VERSION 5.8 ;
BUSBITCHARS "[]" ;
DIVIDERCHAR "/" ;
UNITS
    DATABASE MICRONS 1000 ;
END UNITS

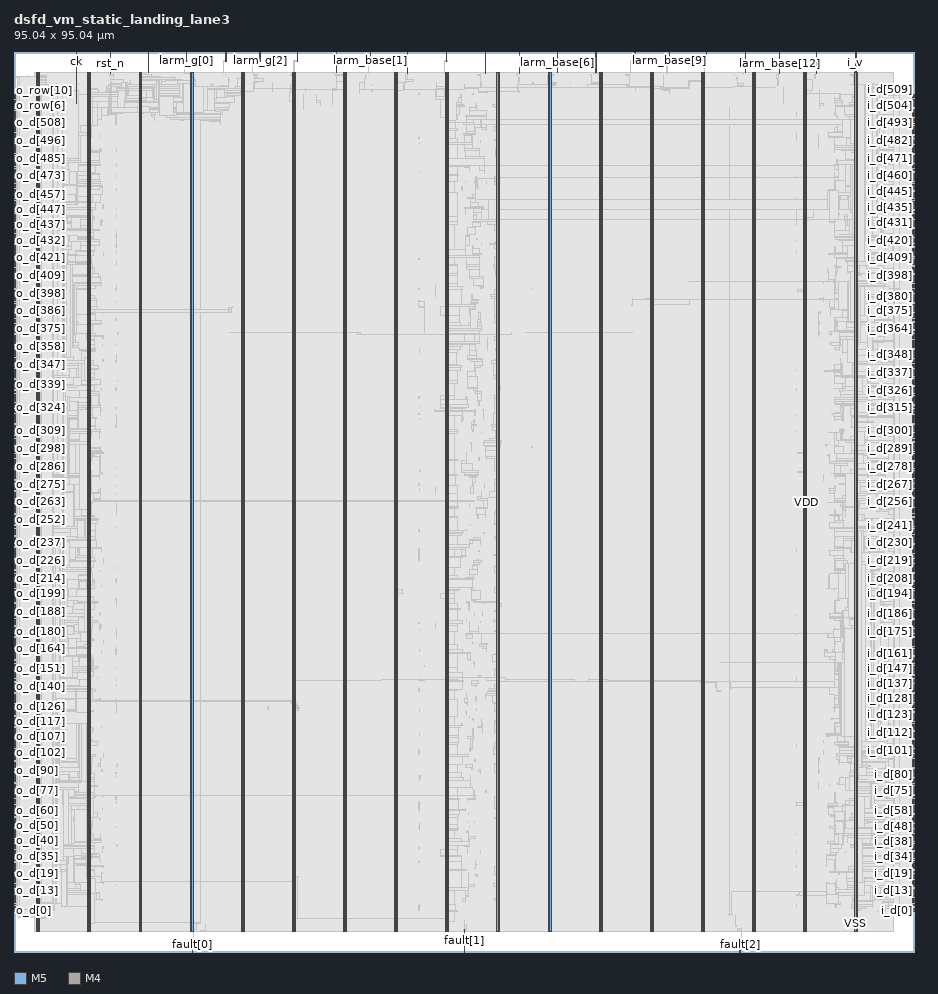
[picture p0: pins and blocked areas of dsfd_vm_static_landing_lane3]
MACRO dsfd_vm_static_landing_lane3
  FOREIGN dsfd_vm_static_landing_lane3 0 0 ;
  CLASS BLOCK ;
  SIZE 95.04 BY 95.04 ;
  PIN ck
    DIRECTION INPUT ;
    USE SIGNAL ;
    PORT
      LAYER M5 ;
        RECT  6.576 94.848 6.6 95.04 ;
    END
    PORT
      LAYER M5 ;
        RECT  6.576 89.555 6.6 94.864 ;
    END
  END ck
  PIN fault[0]
    DIRECTION OUTPUT ;
    USE SIGNAL ;
    PORT
      LAYER M5 ;
        RECT  18.816 0 18.84 0.192 ;
    END
    PORT
      LAYER M5 ;
        RECT  18.816 0.144 18.84 0.563 ;
    END
  END fault[0]
  PIN fault[1]
    DIRECTION OUTPUT ;
    USE SIGNAL ;
    PORT
      LAYER M5 ;
        RECT  47.568 0 47.592 0.192 ;
    END
    PORT
      LAYER M5 ;
        RECT  47.568 0.144 47.592 2.339 ;
    END
  END fault[1]
  PIN fault[2]
    DIRECTION OUTPUT ;
    USE SIGNAL ;
    PORT
      LAYER M5 ;
        RECT  76.656 0 76.68 0.192 ;
    END
    PORT
      LAYER M5 ;
        RECT  76.656 0.144 76.68 0.227 ;
    END
  END fault[2]
  PIN i_d[0]
    DIRECTION INPUT ;
    USE SIGNAL ;
    PORT
      LAYER M4 ;
        RECT  94.848 4.32 95.04 4.344 ;
    END
  END i_d[0]
  PIN i_d[100]
    DIRECTION INPUT ;
    USE SIGNAL ;
    PORT
      LAYER M4 ;
        RECT  94.848 21.168 95.04 21.192 ;
    END
  END i_d[100]
  PIN i_d[101]
    DIRECTION INPUT ;
    USE SIGNAL ;
    PORT
      LAYER M4 ;
        RECT  94.848 21.312 95.04 21.336 ;
    END
  END i_d[101]
  PIN i_d[102]
    DIRECTION INPUT ;
    USE SIGNAL ;
    PORT
      LAYER M4 ;
        RECT  94.848 21.6 95.04 21.624 ;
    END
  END i_d[102]
  PIN i_d[103]
    DIRECTION INPUT ;
    USE SIGNAL ;
    PORT
      LAYER M4 ;
        RECT  94.848 21.744 95.04 21.768 ;
    END
  END i_d[103]
  PIN i_d[104]
    DIRECTION INPUT ;
    USE SIGNAL ;
    PORT
      LAYER M4 ;
        RECT  94.848 21.888 95.04 21.912 ;
    END
  END i_d[104]
  PIN i_d[105]
    DIRECTION INPUT ;
    USE SIGNAL ;
    PORT
      LAYER M4 ;
        RECT  94.848 22.032 95.04 22.056 ;
    END
  END i_d[105]
  PIN i_d[106]
    DIRECTION INPUT ;
    USE SIGNAL ;
    PORT
      LAYER M4 ;
        RECT  94.848 22.176 95.04 22.2 ;
    END
  END i_d[106]
  PIN i_d[107]
    DIRECTION INPUT ;
    USE SIGNAL ;
    PORT
      LAYER M4 ;
        RECT  94.848 22.32 95.04 22.344 ;
    END
  END i_d[107]
  PIN i_d[108]
    DIRECTION INPUT ;
    USE SIGNAL ;
    PORT
      LAYER M4 ;
        RECT  94.848 22.608 95.04 22.632 ;
    END
  END i_d[108]
  PIN i_d[109]
    DIRECTION INPUT ;
    USE SIGNAL ;
    PORT
      LAYER M4 ;
        RECT  94.848 22.752 95.04 22.776 ;
    END
  END i_d[109]
  PIN i_d[10]
    DIRECTION INPUT ;
    USE SIGNAL ;
    PORT
      LAYER M4 ;
        RECT  94.848 6.048 95.04 6.072 ;
    END
  END i_d[10]
  PIN i_d[110]
    DIRECTION INPUT ;
    USE SIGNAL ;
    PORT
      LAYER M4 ;
        RECT  94.848 22.896 95.04 22.92 ;
    END
  END i_d[110]
  PIN i_d[111]
    DIRECTION INPUT ;
    USE SIGNAL ;
    PORT
      LAYER M4 ;
        RECT  94.848 23.04 95.04 23.064 ;
    END
  END i_d[111]
  PIN i_d[112]
    DIRECTION INPUT ;
    USE SIGNAL ;
    PORT
      LAYER M4 ;
        RECT  94.848 23.184 95.04 23.208 ;
    END
  END i_d[112]
  PIN i_d[113]
    DIRECTION INPUT ;
    USE SIGNAL ;
    PORT
      LAYER M4 ;
        RECT  94.848 23.472 95.04 23.496 ;
    END
  END i_d[113]
  PIN i_d[114]
    DIRECTION INPUT ;
    USE SIGNAL ;
    PORT
      LAYER M4 ;
        RECT  94.848 23.616 95.04 23.64 ;
    END
  END i_d[114]
  PIN i_d[115]
    DIRECTION INPUT ;
    USE SIGNAL ;
    PORT
      LAYER M4 ;
        RECT  94.848 23.76 95.04 23.784 ;
    END
  END i_d[115]
  PIN i_d[116]
    DIRECTION INPUT ;
    USE SIGNAL ;
    PORT
      LAYER M4 ;
        RECT  94.848 23.904 95.04 23.928 ;
    END
  END i_d[116]
  PIN i_d[117]
    DIRECTION INPUT ;
    USE SIGNAL ;
    PORT
      LAYER M4 ;
        RECT  94.848 24.048 95.04 24.072 ;
    END
  END i_d[117]
  PIN i_d[118]
    DIRECTION INPUT ;
    USE SIGNAL ;
    PORT
      LAYER M4 ;
        RECT  94.848 24.192 95.04 24.216 ;
    END
  END i_d[118]
  PIN i_d[119]
    DIRECTION INPUT ;
    USE SIGNAL ;
    PORT
      LAYER M4 ;
        RECT  94.848 24.48 95.04 24.504 ;
    END
  END i_d[119]
  PIN i_d[11]
    DIRECTION INPUT ;
    USE SIGNAL ;
    PORT
      LAYER M4 ;
        RECT  94.848 6.192 95.04 6.216 ;
    END
  END i_d[11]
  PIN i_d[120]
    DIRECTION INPUT ;
    USE SIGNAL ;
    PORT
      LAYER M4 ;
        RECT  94.848 24.624 95.04 24.648 ;
    END
  END i_d[120]
  PIN i_d[121]
    DIRECTION INPUT ;
    USE SIGNAL ;
    PORT
      LAYER M4 ;
        RECT  94.848 24.768 95.04 24.792 ;
    END
  END i_d[121]
  PIN i_d[122]
    DIRECTION INPUT ;
    USE SIGNAL ;
    PORT
      LAYER M4 ;
        RECT  94.848 24.912 95.04 24.936 ;
    END
  END i_d[122]
  PIN i_d[123]
    DIRECTION INPUT ;
    USE SIGNAL ;
    PORT
      LAYER M4 ;
        RECT  94.848 25.056 95.04 25.08 ;
    END
  END i_d[123]
  PIN i_d[124]
    DIRECTION INPUT ;
    USE SIGNAL ;
    PORT
      LAYER M4 ;
        RECT  94.848 25.2 95.04 25.224 ;
    END
  END i_d[124]
  PIN i_d[125]
    DIRECTION INPUT ;
    USE SIGNAL ;
    PORT
      LAYER M4 ;
        RECT  94.848 25.488 95.04 25.512 ;
    END
  END i_d[125]
  PIN i_d[126]
    DIRECTION INPUT ;
    USE SIGNAL ;
    PORT
      LAYER M4 ;
        RECT  94.848 25.632 95.04 25.656 ;
    END
  END i_d[126]
  PIN i_d[127]
    DIRECTION INPUT ;
    USE SIGNAL ;
    PORT
      LAYER M4 ;
        RECT  94.848 25.776 95.04 25.8 ;
    END
  END i_d[127]
  PIN i_d[128]
    DIRECTION INPUT ;
    USE SIGNAL ;
    PORT
      LAYER M4 ;
        RECT  94.848 25.92 95.04 25.944 ;
    END
  END i_d[128]
  PIN i_d[129]
    DIRECTION INPUT ;
    USE SIGNAL ;
    PORT
      LAYER M4 ;
        RECT  94.848 26.064 95.04 26.088 ;
    END
  END i_d[129]
  PIN i_d[12]
    DIRECTION INPUT ;
    USE SIGNAL ;
    PORT
      LAYER M4 ;
        RECT  94.848 6.336 95.04 6.36 ;
    END
  END i_d[12]
  PIN i_d[130]
    DIRECTION INPUT ;
    USE SIGNAL ;
    PORT
      LAYER M4 ;
        RECT  94.848 26.208 95.04 26.232 ;
    END
  END i_d[130]
  PIN i_d[131]
    DIRECTION INPUT ;
    USE SIGNAL ;
    PORT
      LAYER M4 ;
        RECT  94.848 26.496 95.04 26.52 ;
    END
  END i_d[131]
  PIN i_d[132]
    DIRECTION INPUT ;
    USE SIGNAL ;
    PORT
      LAYER M4 ;
        RECT  94.848 26.64 95.04 26.664 ;
    END
  END i_d[132]
  PIN i_d[133]
    DIRECTION INPUT ;
    USE SIGNAL ;
    PORT
      LAYER M4 ;
        RECT  94.848 26.784 95.04 26.808 ;
    END
  END i_d[133]
  PIN i_d[134]
    DIRECTION INPUT ;
    USE SIGNAL ;
    PORT
      LAYER M4 ;
        RECT  94.848 26.928 95.04 26.952 ;
    END
  END i_d[134]
  PIN i_d[135]
    DIRECTION INPUT ;
    USE SIGNAL ;
    PORT
      LAYER M4 ;
        RECT  94.848 27.072 95.04 27.096 ;
    END
  END i_d[135]
  PIN i_d[136]
    DIRECTION INPUT ;
    USE SIGNAL ;
    PORT
      LAYER M4 ;
        RECT  94.848 27.216 95.04 27.24 ;
    END
  END i_d[136]
  PIN i_d[137]
    DIRECTION INPUT ;
    USE SIGNAL ;
    PORT
      LAYER M4 ;
        RECT  94.848 27.504 95.04 27.528 ;
    END
  END i_d[137]
  PIN i_d[138]
    DIRECTION INPUT ;
    USE SIGNAL ;
    PORT
      LAYER M4 ;
        RECT  94.848 27.648 95.04 27.672 ;
    END
  END i_d[138]
  PIN i_d[139]
    DIRECTION INPUT ;
    USE SIGNAL ;
    PORT
      LAYER M4 ;
        RECT  94.848 27.792 95.04 27.816 ;
    END
  END i_d[139]
  PIN i_d[13]
    DIRECTION INPUT ;
    USE SIGNAL ;
    PORT
      LAYER M4 ;
        RECT  94.848 6.48 95.04 6.504 ;
    END
  END i_d[13]
  PIN i_d[140]
    DIRECTION INPUT ;
    USE SIGNAL ;
    PORT
      LAYER M4 ;
        RECT  94.848 27.936 95.04 27.96 ;
    END
  END i_d[140]
  PIN i_d[141]
    DIRECTION INPUT ;
    USE SIGNAL ;
    PORT
      LAYER M4 ;
        RECT  94.848 28.08 95.04 28.104 ;
    END
  END i_d[141]
  PIN i_d[142]
    DIRECTION INPUT ;
    USE SIGNAL ;
    PORT
      LAYER M4 ;
        RECT  94.848 28.224 95.04 28.248 ;
    END
  END i_d[142]
  PIN i_d[143]
    DIRECTION INPUT ;
    USE SIGNAL ;
    PORT
      LAYER M4 ;
        RECT  94.848 28.512 95.04 28.536 ;
    END
  END i_d[143]
  PIN i_d[144]
    DIRECTION INPUT ;
    USE SIGNAL ;
    PORT
      LAYER M4 ;
        RECT  94.848 28.656 95.04 28.68 ;
    END
  END i_d[144]
  PIN i_d[145]
    DIRECTION INPUT ;
    USE SIGNAL ;
    PORT
      LAYER M4 ;
        RECT  94.848 28.8 95.04 28.824 ;
    END
  END i_d[145]
  PIN i_d[146]
    DIRECTION INPUT ;
    USE SIGNAL ;
    PORT
      LAYER M4 ;
        RECT  94.848 28.944 95.04 28.968 ;
    END
  END i_d[146]
  PIN i_d[147]
    DIRECTION INPUT ;
    USE SIGNAL ;
    PORT
      LAYER M4 ;
        RECT  94.848 29.088 95.04 29.112 ;
    END
  END i_d[147]
  PIN i_d[148]
    DIRECTION INPUT ;
    USE SIGNAL ;
    PORT
      LAYER M4 ;
        RECT  94.848 29.376 95.04 29.4 ;
    END
  END i_d[148]
  PIN i_d[149]
    DIRECTION INPUT ;
    USE SIGNAL ;
    PORT
      LAYER M4 ;
        RECT  94.848 29.52 95.04 29.544 ;
    END
  END i_d[149]
  PIN i_d[14]
    DIRECTION INPUT ;
    USE SIGNAL ;
    PORT
      LAYER M4 ;
        RECT  94.848 6.624 95.04 6.648 ;
    END
  END i_d[14]
  PIN i_d[150]
    DIRECTION INPUT ;
    USE SIGNAL ;
    PORT
      LAYER M4 ;
        RECT  94.848 29.664 95.04 29.688 ;
    END
  END i_d[150]
  PIN i_d[151]
    DIRECTION INPUT ;
    USE SIGNAL ;
    PORT
      LAYER M4 ;
        RECT  94.848 29.808 95.04 29.832 ;
    END
  END i_d[151]
  PIN i_d[152]
    DIRECTION INPUT ;
    USE SIGNAL ;
    PORT
      LAYER M4 ;
        RECT  94.848 29.952 95.04 29.976 ;
    END
  END i_d[152]
  PIN i_d[153]
    DIRECTION INPUT ;
    USE SIGNAL ;
    PORT
      LAYER M4 ;
        RECT  94.848 30.096 95.04 30.12 ;
    END
  END i_d[153]
  PIN i_d[154]
    DIRECTION INPUT ;
    USE SIGNAL ;
    PORT
      LAYER M4 ;
        RECT  94.848 30.384 95.04 30.408 ;
    END
  END i_d[154]
  PIN i_d[155]
    DIRECTION INPUT ;
    USE SIGNAL ;
    PORT
      LAYER M4 ;
        RECT  94.848 30.528 95.04 30.552 ;
    END
  END i_d[155]
  PIN i_d[156]
    DIRECTION INPUT ;
    USE SIGNAL ;
    PORT
      LAYER M4 ;
        RECT  94.848 30.672 95.04 30.696 ;
    END
  END i_d[156]
  PIN i_d[157]
    DIRECTION INPUT ;
    USE SIGNAL ;
    PORT
      LAYER M4 ;
        RECT  94.848 30.816 95.04 30.84 ;
    END
  END i_d[157]
  PIN i_d[158]
    DIRECTION INPUT ;
    USE SIGNAL ;
    PORT
      LAYER M4 ;
        RECT  94.848 30.96 95.04 30.984 ;
    END
  END i_d[158]
  PIN i_d[159]
    DIRECTION INPUT ;
    USE SIGNAL ;
    PORT
      LAYER M4 ;
        RECT  94.848 31.104 95.04 31.128 ;
    END
  END i_d[159]
  PIN i_d[15]
    DIRECTION INPUT ;
    USE SIGNAL ;
    PORT
      LAYER M4 ;
        RECT  94.848 6.912 95.04 6.936 ;
    END
  END i_d[15]
  PIN i_d[160]
    DIRECTION INPUT ;
    USE SIGNAL ;
    PORT
      LAYER M4 ;
        RECT  94.848 31.392 95.04 31.416 ;
    END
  END i_d[160]
  PIN i_d[161]
    DIRECTION INPUT ;
    USE SIGNAL ;
    PORT
      LAYER M4 ;
        RECT  94.848 31.536 95.04 31.56 ;
    END
  END i_d[161]
  PIN i_d[162]
    DIRECTION INPUT ;
    USE SIGNAL ;
    PORT
      LAYER M4 ;
        RECT  94.848 31.68 95.04 31.704 ;
    END
  END i_d[162]
  PIN i_d[163]
    DIRECTION INPUT ;
    USE SIGNAL ;
    PORT
      LAYER M4 ;
        RECT  94.848 31.824 95.04 31.848 ;
    END
  END i_d[163]
  PIN i_d[164]
    DIRECTION INPUT ;
    USE SIGNAL ;
    PORT
      LAYER M4 ;
        RECT  94.848 31.968 95.04 31.992 ;
    END
  END i_d[164]
  PIN i_d[165]
    DIRECTION INPUT ;
    USE SIGNAL ;
    PORT
      LAYER M4 ;
        RECT  94.848 32.112 95.04 32.136 ;
    END
  END i_d[165]
  PIN i_d[166]
    DIRECTION INPUT ;
    USE SIGNAL ;
    PORT
      LAYER M4 ;
        RECT  94.848 32.4 95.04 32.424 ;
    END
  END i_d[166]
  PIN i_d[167]
    DIRECTION INPUT ;
    USE SIGNAL ;
    PORT
      LAYER M4 ;
        RECT  94.848 32.544 95.04 32.568 ;
    END
  END i_d[167]
  PIN i_d[168]
    DIRECTION INPUT ;
    USE SIGNAL ;
    PORT
      LAYER M4 ;
        RECT  94.848 32.688 95.04 32.712 ;
    END
  END i_d[168]
  PIN i_d[169]
    DIRECTION INPUT ;
    USE SIGNAL ;
    PORT
      LAYER M4 ;
        RECT  94.848 32.832 95.04 32.856 ;
    END
  END i_d[169]
  PIN i_d[16]
    DIRECTION INPUT ;
    USE SIGNAL ;
    PORT
      LAYER M4 ;
        RECT  94.848 7.056 95.04 7.08 ;
    END
  END i_d[16]
  PIN i_d[170]
    DIRECTION INPUT ;
    USE SIGNAL ;
    PORT
      LAYER M4 ;
        RECT  94.848 32.976 95.04 33 ;
    END
  END i_d[170]
  PIN i_d[171]
    DIRECTION INPUT ;
    USE SIGNAL ;
    PORT
      LAYER M4 ;
        RECT  94.848 33.12 95.04 33.144 ;
    END
  END i_d[171]
  PIN i_d[172]
    DIRECTION INPUT ;
    USE SIGNAL ;
    PORT
      LAYER M4 ;
        RECT  94.848 33.408 95.04 33.432 ;
    END
  END i_d[172]
  PIN i_d[173]
    DIRECTION INPUT ;
    USE SIGNAL ;
    PORT
      LAYER M4 ;
        RECT  94.848 33.552 95.04 33.576 ;
    END
  END i_d[173]
  PIN i_d[174]
    DIRECTION INPUT ;
    USE SIGNAL ;
    PORT
      LAYER M4 ;
        RECT  94.848 33.696 95.04 33.72 ;
    END
  END i_d[174]
  PIN i_d[175]
    DIRECTION INPUT ;
    USE SIGNAL ;
    PORT
      LAYER M4 ;
        RECT  94.848 33.84 95.04 33.864 ;
    END
  END i_d[175]
  PIN i_d[176]
    DIRECTION INPUT ;
    USE SIGNAL ;
    PORT
      LAYER M4 ;
        RECT  94.848 33.984 95.04 34.008 ;
    END
  END i_d[176]
  PIN i_d[177]
    DIRECTION INPUT ;
    USE SIGNAL ;
    PORT
      LAYER M4 ;
        RECT  94.848 34.272 95.04 34.296 ;
    END
  END i_d[177]
  PIN i_d[178]
    DIRECTION INPUT ;
    USE SIGNAL ;
    PORT
      LAYER M4 ;
        RECT  94.848 34.416 95.04 34.44 ;
    END
  END i_d[178]
  PIN i_d[179]
    DIRECTION INPUT ;
    USE SIGNAL ;
    PORT
      LAYER M4 ;
        RECT  94.848 34.56 95.04 34.584 ;
    END
  END i_d[179]
  PIN i_d[17]
    DIRECTION INPUT ;
    USE SIGNAL ;
    PORT
      LAYER M4 ;
        RECT  94.848 7.2 95.04 7.224 ;
    END
  END i_d[17]
  PIN i_d[180]
    DIRECTION INPUT ;
    USE SIGNAL ;
    PORT
      LAYER M4 ;
        RECT  94.848 34.704 95.04 34.728 ;
    END
  END i_d[180]
  PIN i_d[181]
    DIRECTION INPUT ;
    USE SIGNAL ;
    PORT
      LAYER M4 ;
        RECT  94.848 34.848 95.04 34.872 ;
    END
  END i_d[181]
  PIN i_d[182]
    DIRECTION INPUT ;
    USE SIGNAL ;
    PORT
      LAYER M4 ;
        RECT  94.848 34.992 95.04 35.016 ;
    END
  END i_d[182]
  PIN i_d[183]
    DIRECTION INPUT ;
    USE SIGNAL ;
    PORT
      LAYER M4 ;
        RECT  94.848 35.28 95.04 35.304 ;
    END
  END i_d[183]
  PIN i_d[184]
    DIRECTION INPUT ;
    USE SIGNAL ;
    PORT
      LAYER M4 ;
        RECT  94.848 35.424 95.04 35.448 ;
    END
  END i_d[184]
  PIN i_d[185]
    DIRECTION INPUT ;
    USE SIGNAL ;
    PORT
      LAYER M4 ;
        RECT  94.848 35.568 95.04 35.592 ;
    END
  END i_d[185]
  PIN i_d[186]
    DIRECTION INPUT ;
    USE SIGNAL ;
    PORT
      LAYER M4 ;
        RECT  94.848 35.712 95.04 35.736 ;
    END
  END i_d[186]
  PIN i_d[187]
    DIRECTION INPUT ;
    USE SIGNAL ;
    PORT
      LAYER M4 ;
        RECT  94.848 35.856 95.04 35.88 ;
    END
  END i_d[187]
  PIN i_d[188]
    DIRECTION INPUT ;
    USE SIGNAL ;
    PORT
      LAYER M4 ;
        RECT  94.848 36 95.04 36.024 ;
    END
  END i_d[188]
  PIN i_d[189]
    DIRECTION INPUT ;
    USE SIGNAL ;
    PORT
      LAYER M4 ;
        RECT  94.848 36.288 95.04 36.312 ;
    END
  END i_d[189]
  PIN i_d[18]
    DIRECTION INPUT ;
    USE SIGNAL ;
    PORT
      LAYER M4 ;
        RECT  94.848 7.344 95.04 7.368 ;
    END
  END i_d[18]
  PIN i_d[190]
    DIRECTION INPUT ;
    USE SIGNAL ;
    PORT
      LAYER M4 ;
        RECT  94.848 36.432 95.04 36.456 ;
    END
  END i_d[190]
  PIN i_d[191]
    DIRECTION INPUT ;
    USE SIGNAL ;
    PORT
      LAYER M4 ;
        RECT  94.848 36.576 95.04 36.6 ;
    END
  END i_d[191]
  PIN i_d[192]
    DIRECTION INPUT ;
    USE SIGNAL ;
    PORT
      LAYER M4 ;
        RECT  94.848 36.72 95.04 36.744 ;
    END
  END i_d[192]
  PIN i_d[193]
    DIRECTION INPUT ;
    USE SIGNAL ;
    PORT
      LAYER M4 ;
        RECT  94.848 36.864 95.04 36.888 ;
    END
  END i_d[193]
  PIN i_d[194]
    DIRECTION INPUT ;
    USE SIGNAL ;
    PORT
      LAYER M4 ;
        RECT  94.848 37.008 95.04 37.032 ;
    END
  END i_d[194]
  PIN i_d[195]
    DIRECTION INPUT ;
    USE SIGNAL ;
    PORT
      LAYER M4 ;
        RECT  94.848 37.296 95.04 37.32 ;
    END
  END i_d[195]
  PIN i_d[196]
    DIRECTION INPUT ;
    USE SIGNAL ;
    PORT
      LAYER M4 ;
        RECT  94.848 37.44 95.04 37.464 ;
    END
  END i_d[196]
  PIN i_d[197]
    DIRECTION INPUT ;
    USE SIGNAL ;
    PORT
      LAYER M4 ;
        RECT  94.848 37.584 95.04 37.608 ;
    END
  END i_d[197]
  PIN i_d[198]
    DIRECTION INPUT ;
    USE SIGNAL ;
    PORT
      LAYER M4 ;
        RECT  94.848 37.728 95.04 37.752 ;
    END
  END i_d[198]
  PIN i_d[199]
    DIRECTION INPUT ;
    USE SIGNAL ;
    PORT
      LAYER M4 ;
        RECT  94.848 37.872 95.04 37.896 ;
    END
  END i_d[199]
  PIN i_d[19]
    DIRECTION INPUT ;
    USE SIGNAL ;
    PORT
      LAYER M4 ;
        RECT  94.848 7.488 95.04 7.512 ;
    END
  END i_d[19]
  PIN i_d[1]
    DIRECTION INPUT ;
    USE SIGNAL ;
    PORT
      LAYER M4 ;
        RECT  94.848 4.464 95.04 4.488 ;
    END
  END i_d[1]
  PIN i_d[200]
    DIRECTION INPUT ;
    USE SIGNAL ;
    PORT
      LAYER M4 ;
        RECT  94.848 38.016 95.04 38.04 ;
    END
  END i_d[200]
  PIN i_d[201]
    DIRECTION INPUT ;
    USE SIGNAL ;
    PORT
      LAYER M4 ;
        RECT  94.848 38.304 95.04 38.328 ;
    END
  END i_d[201]
  PIN i_d[202]
    DIRECTION INPUT ;
    USE SIGNAL ;
    PORT
      LAYER M4 ;
        RECT  94.848 38.448 95.04 38.472 ;
    END
  END i_d[202]
  PIN i_d[203]
    DIRECTION INPUT ;
    USE SIGNAL ;
    PORT
      LAYER M4 ;
        RECT  94.848 38.592 95.04 38.616 ;
    END
  END i_d[203]
  PIN i_d[204]
    DIRECTION INPUT ;
    USE SIGNAL ;
    PORT
      LAYER M4 ;
        RECT  94.848 38.736 95.04 38.76 ;
    END
  END i_d[204]
  PIN i_d[205]
    DIRECTION INPUT ;
    USE SIGNAL ;
    PORT
      LAYER M4 ;
        RECT  94.848 38.88 95.04 38.904 ;
    END
  END i_d[205]
  PIN i_d[206]
    DIRECTION INPUT ;
    USE SIGNAL ;
    PORT
      LAYER M4 ;
        RECT  94.848 39.024 95.04 39.048 ;
    END
  END i_d[206]
  PIN i_d[207]
    DIRECTION INPUT ;
    USE SIGNAL ;
    PORT
      LAYER M4 ;
        RECT  94.848 39.312 95.04 39.336 ;
    END
  END i_d[207]
  PIN i_d[208]
    DIRECTION INPUT ;
    USE SIGNAL ;
    PORT
      LAYER M4 ;
        RECT  94.848 39.456 95.04 39.48 ;
    END
  END i_d[208]
  PIN i_d[209]
    DIRECTION INPUT ;
    USE SIGNAL ;
    PORT
      LAYER M4 ;
        RECT  94.848 39.6 95.04 39.624 ;
    END
  END i_d[209]
  PIN i_d[20]
    DIRECTION INPUT ;
    USE SIGNAL ;
    PORT
      LAYER M4 ;
        RECT  94.848 7.776 95.04 7.8 ;
    END
  END i_d[20]
  PIN i_d[210]
    DIRECTION INPUT ;
    USE SIGNAL ;
    PORT
      LAYER M4 ;
        RECT  94.848 39.744 95.04 39.768 ;
    END
  END i_d[210]
  PIN i_d[211]
    DIRECTION INPUT ;
    USE SIGNAL ;
    PORT
      LAYER M4 ;
        RECT  94.848 39.888 95.04 39.912 ;
    END
  END i_d[211]
  PIN i_d[212]
    DIRECTION INPUT ;
    USE SIGNAL ;
    PORT
      LAYER M4 ;
        RECT  94.848 40.176 95.04 40.2 ;
    END
  END i_d[212]
  PIN i_d[213]
    DIRECTION INPUT ;
    USE SIGNAL ;
    PORT
      LAYER M4 ;
        RECT  94.848 40.32 95.04 40.344 ;
    END
  END i_d[213]
  PIN i_d[214]
    DIRECTION INPUT ;
    USE SIGNAL ;
    PORT
      LAYER M4 ;
        RECT  94.848 40.464 95.04 40.488 ;
    END
  END i_d[214]
  PIN i_d[215]
    DIRECTION INPUT ;
    USE SIGNAL ;
    PORT
      LAYER M4 ;
        RECT  94.848 40.608 95.04 40.632 ;
    END
  END i_d[215]
  PIN i_d[216]
    DIRECTION INPUT ;
    USE SIGNAL ;
    PORT
      LAYER M4 ;
        RECT  94.848 40.752 95.04 40.776 ;
    END
  END i_d[216]
  PIN i_d[217]
    DIRECTION INPUT ;
    USE SIGNAL ;
    PORT
      LAYER M4 ;
        RECT  94.848 40.896 95.04 40.92 ;
    END
  END i_d[217]
  PIN i_d[218]
    DIRECTION INPUT ;
    USE SIGNAL ;
    PORT
      LAYER M4 ;
        RECT  94.848 41.184 95.04 41.208 ;
    END
  END i_d[218]
  PIN i_d[219]
    DIRECTION INPUT ;
    USE SIGNAL ;
    PORT
      LAYER M4 ;
        RECT  94.848 41.328 95.04 41.352 ;
    END
  END i_d[219]
  PIN i_d[21]
    DIRECTION INPUT ;
    USE SIGNAL ;
    PORT
      LAYER M4 ;
        RECT  94.848 7.92 95.04 7.944 ;
    END
  END i_d[21]
  PIN i_d[220]
    DIRECTION INPUT ;
    USE SIGNAL ;
    PORT
      LAYER M4 ;
        RECT  94.848 41.472 95.04 41.496 ;
    END
  END i_d[220]
  PIN i_d[221]
    DIRECTION INPUT ;
    USE SIGNAL ;
    PORT
      LAYER M4 ;
        RECT  94.848 41.616 95.04 41.64 ;
    END
  END i_d[221]
  PIN i_d[222]
    DIRECTION INPUT ;
    USE SIGNAL ;
    PORT
      LAYER M4 ;
        RECT  94.848 41.76 95.04 41.784 ;
    END
  END i_d[222]
  PIN i_d[223]
    DIRECTION INPUT ;
    USE SIGNAL ;
    PORT
      LAYER M4 ;
        RECT  94.848 41.904 95.04 41.928 ;
    END
  END i_d[223]
  PIN i_d[224]
    DIRECTION INPUT ;
    USE SIGNAL ;
    PORT
      LAYER M4 ;
        RECT  94.848 42.192 95.04 42.216 ;
    END
  END i_d[224]
  PIN i_d[225]
    DIRECTION INPUT ;
    USE SIGNAL ;
    PORT
      LAYER M4 ;
        RECT  94.848 42.336 95.04 42.36 ;
    END
  END i_d[225]
  PIN i_d[226]
    DIRECTION INPUT ;
    USE SIGNAL ;
    PORT
      LAYER M4 ;
        RECT  94.848 42.48 95.04 42.504 ;
    END
  END i_d[226]
  PIN i_d[227]
    DIRECTION INPUT ;
    USE SIGNAL ;
    PORT
      LAYER M4 ;
        RECT  94.848 42.624 95.04 42.648 ;
    END
  END i_d[227]
  PIN i_d[228]
    DIRECTION INPUT ;
    USE SIGNAL ;
    PORT
      LAYER M4 ;
        RECT  94.848 42.768 95.04 42.792 ;
    END
  END i_d[228]
  PIN i_d[229]
    DIRECTION INPUT ;
    USE SIGNAL ;
    PORT
      LAYER M4 ;
        RECT  94.848 42.912 95.04 42.936 ;
    END
  END i_d[229]
  PIN i_d[22]
    DIRECTION INPUT ;
    USE SIGNAL ;
    PORT
      LAYER M4 ;
        RECT  94.848 8.064 95.04 8.088 ;
    END
  END i_d[22]
  PIN i_d[230]
    DIRECTION INPUT ;
    USE SIGNAL ;
    PORT
      LAYER M4 ;
        RECT  94.848 43.2 95.04 43.224 ;
    END
  END i_d[230]
  PIN i_d[231]
    DIRECTION INPUT ;
    USE SIGNAL ;
    PORT
      LAYER M4 ;
        RECT  94.848 43.344 95.04 43.368 ;
    END
  END i_d[231]
  PIN i_d[232]
    DIRECTION INPUT ;
    USE SIGNAL ;
    PORT
      LAYER M4 ;
        RECT  94.848 43.488 95.04 43.512 ;
    END
  END i_d[232]
  PIN i_d[233]
    DIRECTION INPUT ;
    USE SIGNAL ;
    PORT
      LAYER M4 ;
        RECT  94.848 43.632 95.04 43.656 ;
    END
  END i_d[233]
  PIN i_d[234]
    DIRECTION INPUT ;
    USE SIGNAL ;
    PORT
      LAYER M4 ;
        RECT  94.848 43.776 95.04 43.8 ;
    END
  END i_d[234]
  PIN i_d[235]
    DIRECTION INPUT ;
    USE SIGNAL ;
    PORT
      LAYER M4 ;
        RECT  94.848 43.92 95.04 43.944 ;
    END
  END i_d[235]
  PIN i_d[236]
    DIRECTION INPUT ;
    USE SIGNAL ;
    PORT
      LAYER M4 ;
        RECT  94.848 44.208 95.04 44.232 ;
    END
  END i_d[236]
  PIN i_d[237]
    DIRECTION INPUT ;
    USE SIGNAL ;
    PORT
      LAYER M4 ;
        RECT  94.848 44.352 95.04 44.376 ;
    END
  END i_d[237]
  PIN i_d[238]
    DIRECTION INPUT ;
    USE SIGNAL ;
    PORT
      LAYER M4 ;
        RECT  94.848 44.496 95.04 44.52 ;
    END
  END i_d[238]
  PIN i_d[239]
    DIRECTION INPUT ;
    USE SIGNAL ;
    PORT
      LAYER M4 ;
        RECT  94.848 44.64 95.04 44.664 ;
    END
  END i_d[239]
  PIN i_d[23]
    DIRECTION INPUT ;
    USE SIGNAL ;
    PORT
      LAYER M4 ;
        RECT  94.848 8.208 95.04 8.232 ;
    END
  END i_d[23]
  PIN i_d[240]
    DIRECTION INPUT ;
    USE SIGNAL ;
    PORT
      LAYER M4 ;
        RECT  94.848 44.784 95.04 44.808 ;
    END
  END i_d[240]
  PIN i_d[241]
    DIRECTION INPUT ;
    USE SIGNAL ;
    PORT
      LAYER M4 ;
        RECT  94.848 45.072 95.04 45.096 ;
    END
  END i_d[241]
  PIN i_d[242]
    DIRECTION INPUT ;
    USE SIGNAL ;
    PORT
      LAYER M4 ;
        RECT  94.848 45.216 95.04 45.24 ;
    END
  END i_d[242]
  PIN i_d[243]
    DIRECTION INPUT ;
    USE SIGNAL ;
    PORT
      LAYER M4 ;
        RECT  94.848 45.36 95.04 45.384 ;
    END
  END i_d[243]
  PIN i_d[244]
    DIRECTION INPUT ;
    USE SIGNAL ;
    PORT
      LAYER M4 ;
        RECT  94.848 45.504 95.04 45.528 ;
    END
  END i_d[244]
  PIN i_d[245]
    DIRECTION INPUT ;
    USE SIGNAL ;
    PORT
      LAYER M4 ;
        RECT  94.848 45.648 95.04 45.672 ;
    END
  END i_d[245]
  PIN i_d[246]
    DIRECTION INPUT ;
    USE SIGNAL ;
    PORT
      LAYER M4 ;
        RECT  94.848 45.792 95.04 45.816 ;
    END
  END i_d[246]
  PIN i_d[247]
    DIRECTION INPUT ;
    USE SIGNAL ;
    PORT
      LAYER M4 ;
        RECT  94.848 46.08 95.04 46.104 ;
    END
  END i_d[247]
  PIN i_d[248]
    DIRECTION INPUT ;
    USE SIGNAL ;
    PORT
      LAYER M4 ;
        RECT  94.848 46.224 95.04 46.248 ;
    END
  END i_d[248]
  PIN i_d[249]
    DIRECTION INPUT ;
    USE SIGNAL ;
    PORT
      LAYER M4 ;
        RECT  94.848 46.368 95.04 46.392 ;
    END
  END i_d[249]
  PIN i_d[24]
    DIRECTION INPUT ;
    USE SIGNAL ;
    PORT
      LAYER M4 ;
        RECT  94.848 8.352 95.04 8.376 ;
    END
  END i_d[24]
  PIN i_d[250]
    DIRECTION INPUT ;
    USE SIGNAL ;
    PORT
      LAYER M4 ;
        RECT  94.848 46.512 95.04 46.536 ;
    END
  END i_d[250]
  PIN i_d[251]
    DIRECTION INPUT ;
    USE SIGNAL ;
    PORT
      LAYER M4 ;
        RECT  94.848 46.656 95.04 46.68 ;
    END
  END i_d[251]
  PIN i_d[252]
    DIRECTION INPUT ;
    USE SIGNAL ;
    PORT
      LAYER M4 ;
        RECT  94.848 46.8 95.04 46.824 ;
    END
  END i_d[252]
  PIN i_d[253]
    DIRECTION INPUT ;
    USE SIGNAL ;
    PORT
      LAYER M4 ;
        RECT  94.848 47.088 95.04 47.112 ;
    END
  END i_d[253]
  PIN i_d[254]
    DIRECTION INPUT ;
    USE SIGNAL ;
    PORT
      LAYER M4 ;
        RECT  94.848 47.232 95.04 47.256 ;
    END
  END i_d[254]
  PIN i_d[255]
    DIRECTION INPUT ;
    USE SIGNAL ;
    PORT
      LAYER M4 ;
        RECT  94.848 47.376 95.04 47.4 ;
    END
  END i_d[255]
  PIN i_d[256]
    DIRECTION INPUT ;
    USE SIGNAL ;
    PORT
      LAYER M4 ;
        RECT  94.848 47.52 95.04 47.544 ;
    END
  END i_d[256]
  PIN i_d[257]
    DIRECTION INPUT ;
    USE SIGNAL ;
    PORT
      LAYER M4 ;
        RECT  94.848 47.664 95.04 47.688 ;
    END
  END i_d[257]
  PIN i_d[258]
    DIRECTION INPUT ;
    USE SIGNAL ;
    PORT
      LAYER M4 ;
        RECT  94.848 47.808 95.04 47.832 ;
    END
  END i_d[258]
  PIN i_d[259]
    DIRECTION INPUT ;
    USE SIGNAL ;
    PORT
      LAYER M4 ;
        RECT  94.848 48.096 95.04 48.12 ;
    END
  END i_d[259]
  PIN i_d[25]
    DIRECTION INPUT ;
    USE SIGNAL ;
    PORT
      LAYER M4 ;
        RECT  94.848 8.496 95.04 8.52 ;
    END
  END i_d[25]
  PIN i_d[260]
    DIRECTION INPUT ;
    USE SIGNAL ;
    PORT
      LAYER M4 ;
        RECT  94.848 48.24 95.04 48.264 ;
    END
  END i_d[260]
  PIN i_d[261]
    DIRECTION INPUT ;
    USE SIGNAL ;
    PORT
      LAYER M4 ;
        RECT  94.848 48.384 95.04 48.408 ;
    END
  END i_d[261]
  PIN i_d[262]
    DIRECTION INPUT ;
    USE SIGNAL ;
    PORT
      LAYER M4 ;
        RECT  94.848 48.528 95.04 48.552 ;
    END
  END i_d[262]
  PIN i_d[263]
    DIRECTION INPUT ;
    USE SIGNAL ;
    PORT
      LAYER M4 ;
        RECT  94.848 48.672 95.04 48.696 ;
    END
  END i_d[263]
  PIN i_d[264]
    DIRECTION INPUT ;
    USE SIGNAL ;
    PORT
      LAYER M4 ;
        RECT  94.848 48.816 95.04 48.84 ;
    END
  END i_d[264]
  PIN i_d[265]
    DIRECTION INPUT ;
    USE SIGNAL ;
    PORT
      LAYER M4 ;
        RECT  94.848 49.104 95.04 49.128 ;
    END
  END i_d[265]
  PIN i_d[266]
    DIRECTION INPUT ;
    USE SIGNAL ;
    PORT
      LAYER M4 ;
        RECT  94.848 49.248 95.04 49.272 ;
    END
  END i_d[266]
  PIN i_d[267]
    DIRECTION INPUT ;
    USE SIGNAL ;
    PORT
      LAYER M4 ;
        RECT  94.848 49.392 95.04 49.416 ;
    END
  END i_d[267]
  PIN i_d[268]
    DIRECTION INPUT ;
    USE SIGNAL ;
    PORT
      LAYER M4 ;
        RECT  94.848 49.536 95.04 49.56 ;
    END
  END i_d[268]
  PIN i_d[269]
    DIRECTION INPUT ;
    USE SIGNAL ;
    PORT
      LAYER M4 ;
        RECT  94.848 49.68 95.04 49.704 ;
    END
  END i_d[269]
  PIN i_d[26]
    DIRECTION INPUT ;
    USE SIGNAL ;
    PORT
      LAYER M4 ;
        RECT  94.848 8.784 95.04 8.808 ;
    END
  END i_d[26]
  PIN i_d[270]
    DIRECTION INPUT ;
    USE SIGNAL ;
    PORT
      LAYER M4 ;
        RECT  94.848 49.824 95.04 49.848 ;
    END
  END i_d[270]
  PIN i_d[271]
    DIRECTION INPUT ;
    USE SIGNAL ;
    PORT
      LAYER M4 ;
        RECT  94.848 50.112 95.04 50.136 ;
    END
  END i_d[271]
  PIN i_d[272]
    DIRECTION INPUT ;
    USE SIGNAL ;
    PORT
      LAYER M4 ;
        RECT  94.848 50.256 95.04 50.28 ;
    END
  END i_d[272]
  PIN i_d[273]
    DIRECTION INPUT ;
    USE SIGNAL ;
    PORT
      LAYER M4 ;
        RECT  94.848 50.4 95.04 50.424 ;
    END
  END i_d[273]
  PIN i_d[274]
    DIRECTION INPUT ;
    USE SIGNAL ;
    PORT
      LAYER M4 ;
        RECT  94.848 50.544 95.04 50.568 ;
    END
  END i_d[274]
  PIN i_d[275]
    DIRECTION INPUT ;
    USE SIGNAL ;
    PORT
      LAYER M4 ;
        RECT  94.848 50.688 95.04 50.712 ;
    END
  END i_d[275]
  PIN i_d[276]
    DIRECTION INPUT ;
    USE SIGNAL ;
    PORT
      LAYER M4 ;
        RECT  94.848 50.976 95.04 51 ;
    END
  END i_d[276]
  PIN i_d[277]
    DIRECTION INPUT ;
    USE SIGNAL ;
    PORT
      LAYER M4 ;
        RECT  94.848 51.12 95.04 51.144 ;
    END
  END i_d[277]
  PIN i_d[278]
    DIRECTION INPUT ;
    USE SIGNAL ;
    PORT
      LAYER M4 ;
        RECT  94.848 51.264 95.04 51.288 ;
    END
  END i_d[278]
  PIN i_d[279]
    DIRECTION INPUT ;
    USE SIGNAL ;
    PORT
      LAYER M4 ;
        RECT  94.848 51.408 95.04 51.432 ;
    END
  END i_d[279]
  PIN i_d[27]
    DIRECTION INPUT ;
    USE SIGNAL ;
    PORT
      LAYER M4 ;
        RECT  94.848 8.928 95.04 8.952 ;
    END
  END i_d[27]
  PIN i_d[280]
    DIRECTION INPUT ;
    USE SIGNAL ;
    PORT
      LAYER M4 ;
        RECT  94.848 51.552 95.04 51.576 ;
    END
  END i_d[280]
  PIN i_d[281]
    DIRECTION INPUT ;
    USE SIGNAL ;
    PORT
      LAYER M4 ;
        RECT  94.848 51.696 95.04 51.72 ;
    END
  END i_d[281]
  PIN i_d[282]
    DIRECTION INPUT ;
    USE SIGNAL ;
    PORT
      LAYER M4 ;
        RECT  94.848 51.984 95.04 52.008 ;
    END
  END i_d[282]
  PIN i_d[283]
    DIRECTION INPUT ;
    USE SIGNAL ;
    PORT
      LAYER M4 ;
        RECT  94.848 52.128 95.04 52.152 ;
    END
  END i_d[283]
  PIN i_d[284]
    DIRECTION INPUT ;
    USE SIGNAL ;
    PORT
      LAYER M4 ;
        RECT  94.848 52.272 95.04 52.296 ;
    END
  END i_d[284]
  PIN i_d[285]
    DIRECTION INPUT ;
    USE SIGNAL ;
    PORT
      LAYER M4 ;
        RECT  94.848 52.416 95.04 52.44 ;
    END
  END i_d[285]
  PIN i_d[286]
    DIRECTION INPUT ;
    USE SIGNAL ;
    PORT
      LAYER M4 ;
        RECT  94.848 52.56 95.04 52.584 ;
    END
  END i_d[286]
  PIN i_d[287]
    DIRECTION INPUT ;
    USE SIGNAL ;
    PORT
      LAYER M4 ;
        RECT  94.848 52.704 95.04 52.728 ;
    END
  END i_d[287]
  PIN i_d[288]
    DIRECTION INPUT ;
    USE SIGNAL ;
    PORT
      LAYER M4 ;
        RECT  94.848 52.992 95.04 53.016 ;
    END
  END i_d[288]
  PIN i_d[289]
    DIRECTION INPUT ;
    USE SIGNAL ;
    PORT
      LAYER M4 ;
        RECT  94.848 53.136 95.04 53.16 ;
    END
  END i_d[289]
  PIN i_d[28]
    DIRECTION INPUT ;
    USE SIGNAL ;
    PORT
      LAYER M4 ;
        RECT  94.848 9.072 95.04 9.096 ;
    END
  END i_d[28]
  PIN i_d[290]
    DIRECTION INPUT ;
    USE SIGNAL ;
    PORT
      LAYER M4 ;
        RECT  94.848 53.28 95.04 53.304 ;
    END
  END i_d[290]
  PIN i_d[291]
    DIRECTION INPUT ;
    USE SIGNAL ;
    PORT
      LAYER M4 ;
        RECT  94.848 53.424 95.04 53.448 ;
    END
  END i_d[291]
  PIN i_d[292]
    DIRECTION INPUT ;
    USE SIGNAL ;
    PORT
      LAYER M4 ;
        RECT  94.848 53.568 95.04 53.592 ;
    END
  END i_d[292]
  PIN i_d[293]
    DIRECTION INPUT ;
    USE SIGNAL ;
    PORT
      LAYER M4 ;
        RECT  94.848 53.712 95.04 53.736 ;
    END
  END i_d[293]
  PIN i_d[294]
    DIRECTION INPUT ;
    USE SIGNAL ;
    PORT
      LAYER M4 ;
        RECT  94.848 54 95.04 54.024 ;
    END
  END i_d[294]
  PIN i_d[295]
    DIRECTION INPUT ;
    USE SIGNAL ;
    PORT
      LAYER M4 ;
        RECT  94.848 54.144 95.04 54.168 ;
    END
  END i_d[295]
  PIN i_d[296]
    DIRECTION INPUT ;
    USE SIGNAL ;
    PORT
      LAYER M4 ;
        RECT  94.848 54.288 95.04 54.312 ;
    END
  END i_d[296]
  PIN i_d[297]
    DIRECTION INPUT ;
    USE SIGNAL ;
    PORT
      LAYER M4 ;
        RECT  94.848 54.432 95.04 54.456 ;
    END
  END i_d[297]
  PIN i_d[298]
    DIRECTION INPUT ;
    USE SIGNAL ;
    PORT
      LAYER M4 ;
        RECT  94.848 54.576 95.04 54.6 ;
    END
  END i_d[298]
  PIN i_d[299]
    DIRECTION INPUT ;
    USE SIGNAL ;
    PORT
      LAYER M4 ;
        RECT  94.848 54.72 95.04 54.744 ;
    END
  END i_d[299]
  PIN i_d[29]
    DIRECTION INPUT ;
    USE SIGNAL ;
    PORT
      LAYER M4 ;
        RECT  94.848 9.216 95.04 9.24 ;
    END
  END i_d[29]
  PIN i_d[2]
    DIRECTION INPUT ;
    USE SIGNAL ;
    PORT
      LAYER M4 ;
        RECT  94.848 4.608 95.04 4.632 ;
    END
  END i_d[2]
  PIN i_d[300]
    DIRECTION INPUT ;
    USE SIGNAL ;
    PORT
      LAYER M4 ;
        RECT  94.848 55.008 95.04 55.032 ;
    END
  END i_d[300]
  PIN i_d[301]
    DIRECTION INPUT ;
    USE SIGNAL ;
    PORT
      LAYER M4 ;
        RECT  94.848 55.152 95.04 55.176 ;
    END
  END i_d[301]
  PIN i_d[302]
    DIRECTION INPUT ;
    USE SIGNAL ;
    PORT
      LAYER M4 ;
        RECT  94.848 55.296 95.04 55.32 ;
    END
  END i_d[302]
  PIN i_d[303]
    DIRECTION INPUT ;
    USE SIGNAL ;
    PORT
      LAYER M4 ;
        RECT  94.848 55.44 95.04 55.464 ;
    END
  END i_d[303]
  PIN i_d[304]
    DIRECTION INPUT ;
    USE SIGNAL ;
    PORT
      LAYER M4 ;
        RECT  94.848 55.584 95.04 55.608 ;
    END
  END i_d[304]
  PIN i_d[305]
    DIRECTION INPUT ;
    USE SIGNAL ;
    PORT
      LAYER M4 ;
        RECT  94.848 55.872 95.04 55.896 ;
    END
  END i_d[305]
  PIN i_d[306]
    DIRECTION INPUT ;
    USE SIGNAL ;
    PORT
      LAYER M4 ;
        RECT  94.848 56.016 95.04 56.04 ;
    END
  END i_d[306]
  PIN i_d[307]
    DIRECTION INPUT ;
    USE SIGNAL ;
    PORT
      LAYER M4 ;
        RECT  94.848 56.16 95.04 56.184 ;
    END
  END i_d[307]
  PIN i_d[308]
    DIRECTION INPUT ;
    USE SIGNAL ;
    PORT
      LAYER M4 ;
        RECT  94.848 56.304 95.04 56.328 ;
    END
  END i_d[308]
  PIN i_d[309]
    DIRECTION INPUT ;
    USE SIGNAL ;
    PORT
      LAYER M4 ;
        RECT  94.848 56.448 95.04 56.472 ;
    END
  END i_d[309]
  PIN i_d[30]
    DIRECTION INPUT ;
    USE SIGNAL ;
    PORT
      LAYER M4 ;
        RECT  94.848 9.36 95.04 9.384 ;
    END
  END i_d[30]
  PIN i_d[310]
    DIRECTION INPUT ;
    USE SIGNAL ;
    PORT
      LAYER M4 ;
        RECT  94.848 56.592 95.04 56.616 ;
    END
  END i_d[310]
  PIN i_d[311]
    DIRECTION INPUT ;
    USE SIGNAL ;
    PORT
      LAYER M4 ;
        RECT  94.848 56.88 95.04 56.904 ;
    END
  END i_d[311]
  PIN i_d[312]
    DIRECTION INPUT ;
    USE SIGNAL ;
    PORT
      LAYER M4 ;
        RECT  94.848 57.024 95.04 57.048 ;
    END
  END i_d[312]
  PIN i_d[313]
    DIRECTION INPUT ;
    USE SIGNAL ;
    PORT
      LAYER M4 ;
        RECT  94.848 57.168 95.04 57.192 ;
    END
  END i_d[313]
  PIN i_d[314]
    DIRECTION INPUT ;
    USE SIGNAL ;
    PORT
      LAYER M4 ;
        RECT  94.848 57.312 95.04 57.336 ;
    END
  END i_d[314]
  PIN i_d[315]
    DIRECTION INPUT ;
    USE SIGNAL ;
    PORT
      LAYER M4 ;
        RECT  94.848 57.456 95.04 57.48 ;
    END
  END i_d[315]
  PIN i_d[316]
    DIRECTION INPUT ;
    USE SIGNAL ;
    PORT
      LAYER M4 ;
        RECT  94.848 57.6 95.04 57.624 ;
    END
  END i_d[316]
  PIN i_d[317]
    DIRECTION INPUT ;
    USE SIGNAL ;
    PORT
      LAYER M4 ;
        RECT  94.848 57.888 95.04 57.912 ;
    END
  END i_d[317]
  PIN i_d[318]
    DIRECTION INPUT ;
    USE SIGNAL ;
    PORT
      LAYER M4 ;
        RECT  94.848 58.032 95.04 58.056 ;
    END
  END i_d[318]
  PIN i_d[319]
    DIRECTION INPUT ;
    USE SIGNAL ;
    PORT
      LAYER M4 ;
        RECT  94.848 58.176 95.04 58.2 ;
    END
  END i_d[319]
  PIN i_d[31]
    DIRECTION INPUT ;
    USE SIGNAL ;
    PORT
      LAYER M4 ;
        RECT  94.848 9.504 95.04 9.528 ;
    END
  END i_d[31]
  PIN i_d[320]
    DIRECTION INPUT ;
    USE SIGNAL ;
    PORT
      LAYER M4 ;
        RECT  94.848 58.32 95.04 58.344 ;
    END
  END i_d[320]
  PIN i_d[321]
    DIRECTION INPUT ;
    USE SIGNAL ;
    PORT
      LAYER M4 ;
        RECT  94.848 58.464 95.04 58.488 ;
    END
  END i_d[321]
  PIN i_d[322]
    DIRECTION INPUT ;
    USE SIGNAL ;
    PORT
      LAYER M4 ;
        RECT  94.848 58.608 95.04 58.632 ;
    END
  END i_d[322]
  PIN i_d[323]
    DIRECTION INPUT ;
    USE SIGNAL ;
    PORT
      LAYER M4 ;
        RECT  94.848 58.896 95.04 58.92 ;
    END
  END i_d[323]
  PIN i_d[324]
    DIRECTION INPUT ;
    USE SIGNAL ;
    PORT
      LAYER M4 ;
        RECT  94.848 59.04 95.04 59.064 ;
    END
  END i_d[324]
  PIN i_d[325]
    DIRECTION INPUT ;
    USE SIGNAL ;
    PORT
      LAYER M4 ;
        RECT  94.848 59.184 95.04 59.208 ;
    END
  END i_d[325]
  PIN i_d[326]
    DIRECTION INPUT ;
    USE SIGNAL ;
    PORT
      LAYER M4 ;
        RECT  94.848 59.328 95.04 59.352 ;
    END
  END i_d[326]
  PIN i_d[327]
    DIRECTION INPUT ;
    USE SIGNAL ;
    PORT
      LAYER M4 ;
        RECT  94.848 59.472 95.04 59.496 ;
    END
  END i_d[327]
  PIN i_d[328]
    DIRECTION INPUT ;
    USE SIGNAL ;
    PORT
      LAYER M4 ;
        RECT  94.848 59.616 95.04 59.64 ;
    END
  END i_d[328]
  PIN i_d[329]
    DIRECTION INPUT ;
    USE SIGNAL ;
    PORT
      LAYER M4 ;
        RECT  94.848 59.904 95.04 59.928 ;
    END
  END i_d[329]
  PIN i_d[32]
    DIRECTION INPUT ;
    USE SIGNAL ;
    PORT
      LAYER M4 ;
        RECT  94.848 9.792 95.04 9.816 ;
    END
  END i_d[32]
  PIN i_d[330]
    DIRECTION INPUT ;
    USE SIGNAL ;
    PORT
      LAYER M4 ;
        RECT  94.848 60.048 95.04 60.072 ;
    END
  END i_d[330]
  PIN i_d[331]
    DIRECTION INPUT ;
    USE SIGNAL ;
    PORT
      LAYER M4 ;
        RECT  94.848 60.192 95.04 60.216 ;
    END
  END i_d[331]
  PIN i_d[332]
    DIRECTION INPUT ;
    USE SIGNAL ;
    PORT
      LAYER M4 ;
        RECT  94.848 60.336 95.04 60.36 ;
    END
  END i_d[332]
  PIN i_d[333]
    DIRECTION INPUT ;
    USE SIGNAL ;
    PORT
      LAYER M4 ;
        RECT  94.848 60.48 95.04 60.504 ;
    END
  END i_d[333]
  PIN i_d[334]
    DIRECTION INPUT ;
    USE SIGNAL ;
    PORT
      LAYER M4 ;
        RECT  94.848 60.624 95.04 60.648 ;
    END
  END i_d[334]
  PIN i_d[335]
    DIRECTION INPUT ;
    USE SIGNAL ;
    PORT
      LAYER M4 ;
        RECT  94.848 60.912 95.04 60.936 ;
    END
  END i_d[335]
  PIN i_d[336]
    DIRECTION INPUT ;
    USE SIGNAL ;
    PORT
      LAYER M4 ;
        RECT  94.848 61.056 95.04 61.08 ;
    END
  END i_d[336]
  PIN i_d[337]
    DIRECTION INPUT ;
    USE SIGNAL ;
    PORT
      LAYER M4 ;
        RECT  94.848 61.2 95.04 61.224 ;
    END
  END i_d[337]
  PIN i_d[338]
    DIRECTION INPUT ;
    USE SIGNAL ;
    PORT
      LAYER M4 ;
        RECT  94.848 61.344 95.04 61.368 ;
    END
  END i_d[338]
  PIN i_d[339]
    DIRECTION INPUT ;
    USE SIGNAL ;
    PORT
      LAYER M4 ;
        RECT  94.848 61.488 95.04 61.512 ;
    END
  END i_d[339]
  PIN i_d[33]
    DIRECTION INPUT ;
    USE SIGNAL ;
    PORT
      LAYER M4 ;
        RECT  94.848 9.936 95.04 9.96 ;
    END
  END i_d[33]
  PIN i_d[340]
    DIRECTION INPUT ;
    USE SIGNAL ;
    PORT
      LAYER M4 ;
        RECT  94.848 61.776 95.04 61.8 ;
    END
  END i_d[340]
  PIN i_d[341]
    DIRECTION INPUT ;
    USE SIGNAL ;
    PORT
      LAYER M4 ;
        RECT  94.848 61.92 95.04 61.944 ;
    END
  END i_d[341]
  PIN i_d[342]
    DIRECTION INPUT ;
    USE SIGNAL ;
    PORT
      LAYER M4 ;
        RECT  94.848 62.064 95.04 62.088 ;
    END
  END i_d[342]
  PIN i_d[343]
    DIRECTION INPUT ;
    USE SIGNAL ;
    PORT
      LAYER M4 ;
        RECT  94.848 62.208 95.04 62.232 ;
    END
  END i_d[343]
  PIN i_d[344]
    DIRECTION INPUT ;
    USE SIGNAL ;
    PORT
      LAYER M4 ;
        RECT  94.848 62.352 95.04 62.376 ;
    END
  END i_d[344]
  PIN i_d[345]
    DIRECTION INPUT ;
    USE SIGNAL ;
    PORT
      LAYER M4 ;
        RECT  94.848 62.496 95.04 62.52 ;
    END
  END i_d[345]
  PIN i_d[346]
    DIRECTION INPUT ;
    USE SIGNAL ;
    PORT
      LAYER M4 ;
        RECT  94.848 62.784 95.04 62.808 ;
    END
  END i_d[346]
  PIN i_d[347]
    DIRECTION INPUT ;
    USE SIGNAL ;
    PORT
      LAYER M4 ;
        RECT  94.848 62.928 95.04 62.952 ;
    END
  END i_d[347]
  PIN i_d[348]
    DIRECTION INPUT ;
    USE SIGNAL ;
    PORT
      LAYER M4 ;
        RECT  94.848 63.072 95.04 63.096 ;
    END
  END i_d[348]
  PIN i_d[349]
    DIRECTION INPUT ;
    USE SIGNAL ;
    PORT
      LAYER M4 ;
        RECT  94.848 63.216 95.04 63.24 ;
    END
  END i_d[349]
  PIN i_d[34]
    DIRECTION INPUT ;
    USE SIGNAL ;
    PORT
      LAYER M4 ;
        RECT  94.848 10.08 95.04 10.104 ;
    END
  END i_d[34]
  PIN i_d[350]
    DIRECTION INPUT ;
    USE SIGNAL ;
    PORT
      LAYER M4 ;
        RECT  94.848 63.36 95.04 63.384 ;
    END
  END i_d[350]
  PIN i_d[351]
    DIRECTION INPUT ;
    USE SIGNAL ;
    PORT
      LAYER M4 ;
        RECT  94.848 63.504 95.04 63.528 ;
    END
  END i_d[351]
  PIN i_d[352]
    DIRECTION INPUT ;
    USE SIGNAL ;
    PORT
      LAYER M4 ;
        RECT  94.848 63.792 95.04 63.816 ;
    END
  END i_d[352]
  PIN i_d[353]
    DIRECTION INPUT ;
    USE SIGNAL ;
    PORT
      LAYER M4 ;
        RECT  94.848 63.936 95.04 63.96 ;
    END
  END i_d[353]
  PIN i_d[354]
    DIRECTION INPUT ;
    USE SIGNAL ;
    PORT
      LAYER M4 ;
        RECT  94.848 64.08 95.04 64.104 ;
    END
  END i_d[354]
  PIN i_d[355]
    DIRECTION INPUT ;
    USE SIGNAL ;
    PORT
      LAYER M4 ;
        RECT  94.848 64.224 95.04 64.248 ;
    END
  END i_d[355]
  PIN i_d[356]
    DIRECTION INPUT ;
    USE SIGNAL ;
    PORT
      LAYER M4 ;
        RECT  94.848 64.368 95.04 64.392 ;
    END
  END i_d[356]
  PIN i_d[357]
    DIRECTION INPUT ;
    USE SIGNAL ;
    PORT
      LAYER M4 ;
        RECT  94.848 64.512 95.04 64.536 ;
    END
  END i_d[357]
  PIN i_d[358]
    DIRECTION INPUT ;
    USE SIGNAL ;
    PORT
      LAYER M4 ;
        RECT  94.848 64.8 95.04 64.824 ;
    END
  END i_d[358]
  PIN i_d[359]
    DIRECTION INPUT ;
    USE SIGNAL ;
    PORT
      LAYER M4 ;
        RECT  94.848 64.944 95.04 64.968 ;
    END
  END i_d[359]
  PIN i_d[35]
    DIRECTION INPUT ;
    USE SIGNAL ;
    PORT
      LAYER M4 ;
        RECT  94.848 10.224 95.04 10.248 ;
    END
  END i_d[35]
  PIN i_d[360]
    DIRECTION INPUT ;
    USE SIGNAL ;
    PORT
      LAYER M4 ;
        RECT  94.848 65.088 95.04 65.112 ;
    END
  END i_d[360]
  PIN i_d[361]
    DIRECTION INPUT ;
    USE SIGNAL ;
    PORT
      LAYER M4 ;
        RECT  94.848 65.232 95.04 65.256 ;
    END
  END i_d[361]
  PIN i_d[362]
    DIRECTION INPUT ;
    USE SIGNAL ;
    PORT
      LAYER M4 ;
        RECT  94.848 65.376 95.04 65.4 ;
    END
  END i_d[362]
  PIN i_d[363]
    DIRECTION INPUT ;
    USE SIGNAL ;
    PORT
      LAYER M4 ;
        RECT  94.848 65.52 95.04 65.544 ;
    END
  END i_d[363]
  PIN i_d[364]
    DIRECTION INPUT ;
    USE SIGNAL ;
    PORT
      LAYER M4 ;
        RECT  94.848 65.808 95.04 65.832 ;
    END
  END i_d[364]
  PIN i_d[365]
    DIRECTION INPUT ;
    USE SIGNAL ;
    PORT
      LAYER M4 ;
        RECT  94.848 65.952 95.04 65.976 ;
    END
  END i_d[365]
  PIN i_d[366]
    DIRECTION INPUT ;
    USE SIGNAL ;
    PORT
      LAYER M4 ;
        RECT  94.848 66.096 95.04 66.12 ;
    END
  END i_d[366]
  PIN i_d[367]
    DIRECTION INPUT ;
    USE SIGNAL ;
    PORT
      LAYER M4 ;
        RECT  94.848 66.24 95.04 66.264 ;
    END
  END i_d[367]
  PIN i_d[368]
    DIRECTION INPUT ;
    USE SIGNAL ;
    PORT
      LAYER M4 ;
        RECT  94.848 66.384 95.04 66.408 ;
    END
  END i_d[368]
  PIN i_d[369]
    DIRECTION INPUT ;
    USE SIGNAL ;
    PORT
      LAYER M4 ;
        RECT  94.848 66.672 95.04 66.696 ;
    END
  END i_d[369]
  PIN i_d[36]
    DIRECTION INPUT ;
    USE SIGNAL ;
    PORT
      LAYER M4 ;
        RECT  94.848 10.368 95.04 10.392 ;
    END
  END i_d[36]
  PIN i_d[370]
    DIRECTION INPUT ;
    USE SIGNAL ;
    PORT
      LAYER M4 ;
        RECT  94.848 66.816 95.04 66.84 ;
    END
  END i_d[370]
  PIN i_d[371]
    DIRECTION INPUT ;
    USE SIGNAL ;
    PORT
      LAYER M4 ;
        RECT  94.848 66.96 95.04 66.984 ;
    END
  END i_d[371]
  PIN i_d[372]
    DIRECTION INPUT ;
    USE SIGNAL ;
    PORT
      LAYER M4 ;
        RECT  94.848 67.104 95.04 67.128 ;
    END
  END i_d[372]
  PIN i_d[373]
    DIRECTION INPUT ;
    USE SIGNAL ;
    PORT
      LAYER M4 ;
        RECT  94.848 67.248 95.04 67.272 ;
    END
  END i_d[373]
  PIN i_d[374]
    DIRECTION INPUT ;
    USE SIGNAL ;
    PORT
      LAYER M4 ;
        RECT  94.848 67.392 95.04 67.416 ;
    END
  END i_d[374]
  PIN i_d[375]
    DIRECTION INPUT ;
    USE SIGNAL ;
    PORT
      LAYER M4 ;
        RECT  94.848 67.68 95.04 67.704 ;
    END
  END i_d[375]
  PIN i_d[376]
    DIRECTION INPUT ;
    USE SIGNAL ;
    PORT
      LAYER M4 ;
        RECT  94.848 67.824 95.04 67.848 ;
    END
  END i_d[376]
  PIN i_d[377]
    DIRECTION INPUT ;
    USE SIGNAL ;
    PORT
      LAYER M4 ;
        RECT  94.848 67.968 95.04 67.992 ;
    END
  END i_d[377]
  PIN i_d[378]
    DIRECTION INPUT ;
    USE SIGNAL ;
    PORT
      LAYER M4 ;
        RECT  94.848 68.112 95.04 68.136 ;
    END
  END i_d[378]
  PIN i_d[379]
    DIRECTION INPUT ;
    USE SIGNAL ;
    PORT
      LAYER M4 ;
        RECT  94.848 68.256 95.04 68.28 ;
    END
  END i_d[379]
  PIN i_d[37]
    DIRECTION INPUT ;
    USE SIGNAL ;
    PORT
      LAYER M4 ;
        RECT  94.848 10.512 95.04 10.536 ;
    END
  END i_d[37]
  PIN i_d[380]
    DIRECTION INPUT ;
    USE SIGNAL ;
    PORT
      LAYER M4 ;
        RECT  94.848 68.4 95.04 68.424 ;
    END
  END i_d[380]
  PIN i_d[381]
    DIRECTION INPUT ;
    USE SIGNAL ;
    PORT
      LAYER M4 ;
        RECT  94.848 68.688 95.04 68.712 ;
    END
  END i_d[381]
  PIN i_d[382]
    DIRECTION INPUT ;
    USE SIGNAL ;
    PORT
      LAYER M4 ;
        RECT  94.848 68.832 95.04 68.856 ;
    END
  END i_d[382]
  PIN i_d[383]
    DIRECTION INPUT ;
    USE SIGNAL ;
    PORT
      LAYER M4 ;
        RECT  94.848 68.976 95.04 69 ;
    END
  END i_d[383]
  PIN i_d[384]
    DIRECTION INPUT ;
    USE SIGNAL ;
    PORT
      LAYER M4 ;
        RECT  94.848 69.12 95.04 69.144 ;
    END
  END i_d[384]
  PIN i_d[385]
    DIRECTION INPUT ;
    USE SIGNAL ;
    PORT
      LAYER M4 ;
        RECT  94.848 69.264 95.04 69.288 ;
    END
  END i_d[385]
  PIN i_d[386]
    DIRECTION INPUT ;
    USE SIGNAL ;
    PORT
      LAYER M4 ;
        RECT  94.848 69.408 95.04 69.432 ;
    END
  END i_d[386]
  PIN i_d[387]
    DIRECTION INPUT ;
    USE SIGNAL ;
    PORT
      LAYER M4 ;
        RECT  94.848 69.696 95.04 69.72 ;
    END
  END i_d[387]
  PIN i_d[388]
    DIRECTION INPUT ;
    USE SIGNAL ;
    PORT
      LAYER M4 ;
        RECT  94.848 69.84 95.04 69.864 ;
    END
  END i_d[388]
  PIN i_d[389]
    DIRECTION INPUT ;
    USE SIGNAL ;
    PORT
      LAYER M4 ;
        RECT  94.848 69.984 95.04 70.008 ;
    END
  END i_d[389]
  PIN i_d[38]
    DIRECTION INPUT ;
    USE SIGNAL ;
    PORT
      LAYER M4 ;
        RECT  94.848 10.8 95.04 10.824 ;
    END
  END i_d[38]
  PIN i_d[390]
    DIRECTION INPUT ;
    USE SIGNAL ;
    PORT
      LAYER M4 ;
        RECT  94.848 70.128 95.04 70.152 ;
    END
  END i_d[390]
  PIN i_d[391]
    DIRECTION INPUT ;
    USE SIGNAL ;
    PORT
      LAYER M4 ;
        RECT  94.848 70.272 95.04 70.296 ;
    END
  END i_d[391]
  PIN i_d[392]
    DIRECTION INPUT ;
    USE SIGNAL ;
    PORT
      LAYER M4 ;
        RECT  94.848 70.416 95.04 70.44 ;
    END
  END i_d[392]
  PIN i_d[393]
    DIRECTION INPUT ;
    USE SIGNAL ;
    PORT
      LAYER M4 ;
        RECT  94.848 70.704 95.04 70.728 ;
    END
  END i_d[393]
  PIN i_d[394]
    DIRECTION INPUT ;
    USE SIGNAL ;
    PORT
      LAYER M4 ;
        RECT  94.848 70.848 95.04 70.872 ;
    END
  END i_d[394]
  PIN i_d[395]
    DIRECTION INPUT ;
    USE SIGNAL ;
    PORT
      LAYER M4 ;
        RECT  94.848 70.992 95.04 71.016 ;
    END
  END i_d[395]
  PIN i_d[396]
    DIRECTION INPUT ;
    USE SIGNAL ;
    PORT
      LAYER M4 ;
        RECT  94.848 71.136 95.04 71.16 ;
    END
  END i_d[396]
  PIN i_d[397]
    DIRECTION INPUT ;
    USE SIGNAL ;
    PORT
      LAYER M4 ;
        RECT  94.848 71.28 95.04 71.304 ;
    END
  END i_d[397]
  PIN i_d[398]
    DIRECTION INPUT ;
    USE SIGNAL ;
    PORT
      LAYER M4 ;
        RECT  94.848 71.424 95.04 71.448 ;
    END
  END i_d[398]
  PIN i_d[399]
    DIRECTION INPUT ;
    USE SIGNAL ;
    PORT
      LAYER M4 ;
        RECT  94.848 71.712 95.04 71.736 ;
    END
  END i_d[399]
  PIN i_d[39]
    DIRECTION INPUT ;
    USE SIGNAL ;
    PORT
      LAYER M4 ;
        RECT  94.848 10.944 95.04 10.968 ;
    END
  END i_d[39]
  PIN i_d[3]
    DIRECTION INPUT ;
    USE SIGNAL ;
    PORT
      LAYER M4 ;
        RECT  94.848 4.896 95.04 4.92 ;
    END
  END i_d[3]
  PIN i_d[400]
    DIRECTION INPUT ;
    USE SIGNAL ;
    PORT
      LAYER M4 ;
        RECT  94.848 71.856 95.04 71.88 ;
    END
  END i_d[400]
  PIN i_d[401]
    DIRECTION INPUT ;
    USE SIGNAL ;
    PORT
      LAYER M4 ;
        RECT  94.848 72 95.04 72.024 ;
    END
  END i_d[401]
  PIN i_d[402]
    DIRECTION INPUT ;
    USE SIGNAL ;
    PORT
      LAYER M4 ;
        RECT  94.848 72.144 95.04 72.168 ;
    END
  END i_d[402]
  PIN i_d[403]
    DIRECTION INPUT ;
    USE SIGNAL ;
    PORT
      LAYER M4 ;
        RECT  94.848 72.288 95.04 72.312 ;
    END
  END i_d[403]
  PIN i_d[404]
    DIRECTION INPUT ;
    USE SIGNAL ;
    PORT
      LAYER M4 ;
        RECT  94.848 72.576 95.04 72.6 ;
    END
  END i_d[404]
  PIN i_d[405]
    DIRECTION INPUT ;
    USE SIGNAL ;
    PORT
      LAYER M4 ;
        RECT  94.848 72.72 95.04 72.744 ;
    END
  END i_d[405]
  PIN i_d[406]
    DIRECTION INPUT ;
    USE SIGNAL ;
    PORT
      LAYER M4 ;
        RECT  94.848 72.864 95.04 72.888 ;
    END
  END i_d[406]
  PIN i_d[407]
    DIRECTION INPUT ;
    USE SIGNAL ;
    PORT
      LAYER M4 ;
        RECT  94.848 73.008 95.04 73.032 ;
    END
  END i_d[407]
  PIN i_d[408]
    DIRECTION INPUT ;
    USE SIGNAL ;
    PORT
      LAYER M4 ;
        RECT  94.848 73.152 95.04 73.176 ;
    END
  END i_d[408]
  PIN i_d[409]
    DIRECTION INPUT ;
    USE SIGNAL ;
    PORT
      LAYER M4 ;
        RECT  94.848 73.296 95.04 73.32 ;
    END
  END i_d[409]
  PIN i_d[40]
    DIRECTION INPUT ;
    USE SIGNAL ;
    PORT
      LAYER M4 ;
        RECT  94.848 11.088 95.04 11.112 ;
    END
  END i_d[40]
  PIN i_d[410]
    DIRECTION INPUT ;
    USE SIGNAL ;
    PORT
      LAYER M4 ;
        RECT  94.848 73.584 95.04 73.608 ;
    END
  END i_d[410]
  PIN i_d[411]
    DIRECTION INPUT ;
    USE SIGNAL ;
    PORT
      LAYER M4 ;
        RECT  94.848 73.728 95.04 73.752 ;
    END
  END i_d[411]
  PIN i_d[412]
    DIRECTION INPUT ;
    USE SIGNAL ;
    PORT
      LAYER M4 ;
        RECT  94.848 73.872 95.04 73.896 ;
    END
  END i_d[412]
  PIN i_d[413]
    DIRECTION INPUT ;
    USE SIGNAL ;
    PORT
      LAYER M4 ;
        RECT  94.848 74.016 95.04 74.04 ;
    END
  END i_d[413]
  PIN i_d[414]
    DIRECTION INPUT ;
    USE SIGNAL ;
    PORT
      LAYER M4 ;
        RECT  94.848 74.16 95.04 74.184 ;
    END
  END i_d[414]
  PIN i_d[415]
    DIRECTION INPUT ;
    USE SIGNAL ;
    PORT
      LAYER M4 ;
        RECT  94.848 74.304 95.04 74.328 ;
    END
  END i_d[415]
  PIN i_d[416]
    DIRECTION INPUT ;
    USE SIGNAL ;
    PORT
      LAYER M4 ;
        RECT  94.848 74.592 95.04 74.616 ;
    END
  END i_d[416]
  PIN i_d[417]
    DIRECTION INPUT ;
    USE SIGNAL ;
    PORT
      LAYER M4 ;
        RECT  94.848 74.736 95.04 74.76 ;
    END
  END i_d[417]
  PIN i_d[418]
    DIRECTION INPUT ;
    USE SIGNAL ;
    PORT
      LAYER M4 ;
        RECT  94.848 74.88 95.04 74.904 ;
    END
  END i_d[418]
  PIN i_d[419]
    DIRECTION INPUT ;
    USE SIGNAL ;
    PORT
      LAYER M4 ;
        RECT  94.848 75.024 95.04 75.048 ;
    END
  END i_d[419]
  PIN i_d[41]
    DIRECTION INPUT ;
    USE SIGNAL ;
    PORT
      LAYER M4 ;
        RECT  94.848 11.232 95.04 11.256 ;
    END
  END i_d[41]
  PIN i_d[420]
    DIRECTION INPUT ;
    USE SIGNAL ;
    PORT
      LAYER M4 ;
        RECT  94.848 75.168 95.04 75.192 ;
    END
  END i_d[420]
  PIN i_d[421]
    DIRECTION INPUT ;
    USE SIGNAL ;
    PORT
      LAYER M4 ;
        RECT  94.848 75.312 95.04 75.336 ;
    END
  END i_d[421]
  PIN i_d[422]
    DIRECTION INPUT ;
    USE SIGNAL ;
    PORT
      LAYER M4 ;
        RECT  94.848 75.6 95.04 75.624 ;
    END
  END i_d[422]
  PIN i_d[423]
    DIRECTION INPUT ;
    USE SIGNAL ;
    PORT
      LAYER M4 ;
        RECT  94.848 75.744 95.04 75.768 ;
    END
  END i_d[423]
  PIN i_d[424]
    DIRECTION INPUT ;
    USE SIGNAL ;
    PORT
      LAYER M4 ;
        RECT  94.848 75.888 95.04 75.912 ;
    END
  END i_d[424]
  PIN i_d[425]
    DIRECTION INPUT ;
    USE SIGNAL ;
    PORT
      LAYER M4 ;
        RECT  94.848 76.032 95.04 76.056 ;
    END
  END i_d[425]
  PIN i_d[426]
    DIRECTION INPUT ;
    USE SIGNAL ;
    PORT
      LAYER M4 ;
        RECT  94.848 76.176 95.04 76.2 ;
    END
  END i_d[426]
  PIN i_d[427]
    DIRECTION INPUT ;
    USE SIGNAL ;
    PORT
      LAYER M4 ;
        RECT  94.848 76.32 95.04 76.344 ;
    END
  END i_d[427]
  PIN i_d[428]
    DIRECTION INPUT ;
    USE SIGNAL ;
    PORT
      LAYER M4 ;
        RECT  94.848 76.608 95.04 76.632 ;
    END
  END i_d[428]
  PIN i_d[429]
    DIRECTION INPUT ;
    USE SIGNAL ;
    PORT
      LAYER M4 ;
        RECT  94.848 76.752 95.04 76.776 ;
    END
  END i_d[429]
  PIN i_d[42]
    DIRECTION INPUT ;
    USE SIGNAL ;
    PORT
      LAYER M4 ;
        RECT  94.848 11.376 95.04 11.4 ;
    END
  END i_d[42]
  PIN i_d[430]
    DIRECTION INPUT ;
    USE SIGNAL ;
    PORT
      LAYER M4 ;
        RECT  94.848 76.896 95.04 76.92 ;
    END
  END i_d[430]
  PIN i_d[431]
    DIRECTION INPUT ;
    USE SIGNAL ;
    PORT
      LAYER M4 ;
        RECT  94.848 77.04 95.04 77.064 ;
    END
  END i_d[431]
  PIN i_d[432]
    DIRECTION INPUT ;
    USE SIGNAL ;
    PORT
      LAYER M4 ;
        RECT  94.848 77.184 95.04 77.208 ;
    END
  END i_d[432]
  PIN i_d[433]
    DIRECTION INPUT ;
    USE SIGNAL ;
    PORT
      LAYER M4 ;
        RECT  94.848 77.472 95.04 77.496 ;
    END
  END i_d[433]
  PIN i_d[434]
    DIRECTION INPUT ;
    USE SIGNAL ;
    PORT
      LAYER M4 ;
        RECT  94.848 77.616 95.04 77.64 ;
    END
  END i_d[434]
  PIN i_d[435]
    DIRECTION INPUT ;
    USE SIGNAL ;
    PORT
      LAYER M4 ;
        RECT  94.848 77.76 95.04 77.784 ;
    END
  END i_d[435]
  PIN i_d[436]
    DIRECTION INPUT ;
    USE SIGNAL ;
    PORT
      LAYER M4 ;
        RECT  94.848 77.904 95.04 77.928 ;
    END
  END i_d[436]
  PIN i_d[437]
    DIRECTION INPUT ;
    USE SIGNAL ;
    PORT
      LAYER M4 ;
        RECT  94.848 78.048 95.04 78.072 ;
    END
  END i_d[437]
  PIN i_d[438]
    DIRECTION INPUT ;
    USE SIGNAL ;
    PORT
      LAYER M4 ;
        RECT  94.848 78.192 95.04 78.216 ;
    END
  END i_d[438]
  PIN i_d[439]
    DIRECTION INPUT ;
    USE SIGNAL ;
    PORT
      LAYER M4 ;
        RECT  94.848 78.48 95.04 78.504 ;
    END
  END i_d[439]
  PIN i_d[43]
    DIRECTION INPUT ;
    USE SIGNAL ;
    PORT
      LAYER M4 ;
        RECT  94.848 11.52 95.04 11.544 ;
    END
  END i_d[43]
  PIN i_d[440]
    DIRECTION INPUT ;
    USE SIGNAL ;
    PORT
      LAYER M4 ;
        RECT  94.848 78.624 95.04 78.648 ;
    END
  END i_d[440]
  PIN i_d[441]
    DIRECTION INPUT ;
    USE SIGNAL ;
    PORT
      LAYER M4 ;
        RECT  94.848 78.768 95.04 78.792 ;
    END
  END i_d[441]
  PIN i_d[442]
    DIRECTION INPUT ;
    USE SIGNAL ;
    PORT
      LAYER M4 ;
        RECT  94.848 78.912 95.04 78.936 ;
    END
  END i_d[442]
  PIN i_d[443]
    DIRECTION INPUT ;
    USE SIGNAL ;
    PORT
      LAYER M4 ;
        RECT  94.848 79.056 95.04 79.08 ;
    END
  END i_d[443]
  PIN i_d[444]
    DIRECTION INPUT ;
    USE SIGNAL ;
    PORT
      LAYER M4 ;
        RECT  94.848 79.2 95.04 79.224 ;
    END
  END i_d[444]
  PIN i_d[445]
    DIRECTION INPUT ;
    USE SIGNAL ;
    PORT
      LAYER M4 ;
        RECT  94.848 79.488 95.04 79.512 ;
    END
  END i_d[445]
  PIN i_d[446]
    DIRECTION INPUT ;
    USE SIGNAL ;
    PORT
      LAYER M4 ;
        RECT  94.848 79.632 95.04 79.656 ;
    END
  END i_d[446]
  PIN i_d[447]
    DIRECTION INPUT ;
    USE SIGNAL ;
    PORT
      LAYER M4 ;
        RECT  94.848 79.776 95.04 79.8 ;
    END
  END i_d[447]
  PIN i_d[448]
    DIRECTION INPUT ;
    USE SIGNAL ;
    PORT
      LAYER M4 ;
        RECT  94.848 79.92 95.04 79.944 ;
    END
  END i_d[448]
  PIN i_d[449]
    DIRECTION INPUT ;
    USE SIGNAL ;
    PORT
      LAYER M4 ;
        RECT  94.848 80.064 95.04 80.088 ;
    END
  END i_d[449]
  PIN i_d[44]
    DIRECTION INPUT ;
    USE SIGNAL ;
    PORT
      LAYER M4 ;
        RECT  94.848 11.808 95.04 11.832 ;
    END
  END i_d[44]
  PIN i_d[450]
    DIRECTION INPUT ;
    USE SIGNAL ;
    PORT
      LAYER M4 ;
        RECT  94.848 80.208 95.04 80.232 ;
    END
  END i_d[450]
  PIN i_d[451]
    DIRECTION INPUT ;
    USE SIGNAL ;
    PORT
      LAYER M4 ;
        RECT  94.848 80.496 95.04 80.52 ;
    END
  END i_d[451]
  PIN i_d[452]
    DIRECTION INPUT ;
    USE SIGNAL ;
    PORT
      LAYER M4 ;
        RECT  94.848 80.64 95.04 80.664 ;
    END
  END i_d[452]
  PIN i_d[453]
    DIRECTION INPUT ;
    USE SIGNAL ;
    PORT
      LAYER M4 ;
        RECT  94.848 80.784 95.04 80.808 ;
    END
  END i_d[453]
  PIN i_d[454]
    DIRECTION INPUT ;
    USE SIGNAL ;
    PORT
      LAYER M4 ;
        RECT  94.848 80.928 95.04 80.952 ;
    END
  END i_d[454]
  PIN i_d[455]
    DIRECTION INPUT ;
    USE SIGNAL ;
    PORT
      LAYER M4 ;
        RECT  94.848 81.072 95.04 81.096 ;
    END
  END i_d[455]
  PIN i_d[456]
    DIRECTION INPUT ;
    USE SIGNAL ;
    PORT
      LAYER M4 ;
        RECT  94.848 81.216 95.04 81.24 ;
    END
  END i_d[456]
  PIN i_d[457]
    DIRECTION INPUT ;
    USE SIGNAL ;
    PORT
      LAYER M4 ;
        RECT  94.848 81.504 95.04 81.528 ;
    END
  END i_d[457]
  PIN i_d[458]
    DIRECTION INPUT ;
    USE SIGNAL ;
    PORT
      LAYER M4 ;
        RECT  94.848 81.648 95.04 81.672 ;
    END
  END i_d[458]
  PIN i_d[459]
    DIRECTION INPUT ;
    USE SIGNAL ;
    PORT
      LAYER M4 ;
        RECT  94.848 81.792 95.04 81.816 ;
    END
  END i_d[459]
  PIN i_d[45]
    DIRECTION INPUT ;
    USE SIGNAL ;
    PORT
      LAYER M4 ;
        RECT  94.848 11.952 95.04 11.976 ;
    END
  END i_d[45]
  PIN i_d[460]
    DIRECTION INPUT ;
    USE SIGNAL ;
    PORT
      LAYER M4 ;
        RECT  94.848 81.936 95.04 81.96 ;
    END
  END i_d[460]
  PIN i_d[461]
    DIRECTION INPUT ;
    USE SIGNAL ;
    PORT
      LAYER M4 ;
        RECT  94.848 82.08 95.04 82.104 ;
    END
  END i_d[461]
  PIN i_d[462]
    DIRECTION INPUT ;
    USE SIGNAL ;
    PORT
      LAYER M4 ;
        RECT  94.848 82.224 95.04 82.248 ;
    END
  END i_d[462]
  PIN i_d[463]
    DIRECTION INPUT ;
    USE SIGNAL ;
    PORT
      LAYER M4 ;
        RECT  94.848 82.512 95.04 82.536 ;
    END
  END i_d[463]
  PIN i_d[464]
    DIRECTION INPUT ;
    USE SIGNAL ;
    PORT
      LAYER M4 ;
        RECT  94.848 82.656 95.04 82.68 ;
    END
  END i_d[464]
  PIN i_d[465]
    DIRECTION INPUT ;
    USE SIGNAL ;
    PORT
      LAYER M4 ;
        RECT  94.848 82.8 95.04 82.824 ;
    END
  END i_d[465]
  PIN i_d[466]
    DIRECTION INPUT ;
    USE SIGNAL ;
    PORT
      LAYER M4 ;
        RECT  94.848 82.944 95.04 82.968 ;
    END
  END i_d[466]
  PIN i_d[467]
    DIRECTION INPUT ;
    USE SIGNAL ;
    PORT
      LAYER M4 ;
        RECT  94.848 83.088 95.04 83.112 ;
    END
  END i_d[467]
  PIN i_d[468]
    DIRECTION INPUT ;
    USE SIGNAL ;
    PORT
      LAYER M4 ;
        RECT  94.848 83.376 95.04 83.4 ;
    END
  END i_d[468]
  PIN i_d[469]
    DIRECTION INPUT ;
    USE SIGNAL ;
    PORT
      LAYER M4 ;
        RECT  94.848 83.52 95.04 83.544 ;
    END
  END i_d[469]
  PIN i_d[46]
    DIRECTION INPUT ;
    USE SIGNAL ;
    PORT
      LAYER M4 ;
        RECT  94.848 12.096 95.04 12.12 ;
    END
  END i_d[46]
  PIN i_d[470]
    DIRECTION INPUT ;
    USE SIGNAL ;
    PORT
      LAYER M4 ;
        RECT  94.848 83.664 95.04 83.688 ;
    END
  END i_d[470]
  PIN i_d[471]
    DIRECTION INPUT ;
    USE SIGNAL ;
    PORT
      LAYER M4 ;
        RECT  94.848 83.808 95.04 83.832 ;
    END
  END i_d[471]
  PIN i_d[472]
    DIRECTION INPUT ;
    USE SIGNAL ;
    PORT
      LAYER M4 ;
        RECT  94.848 83.952 95.04 83.976 ;
    END
  END i_d[472]
  PIN i_d[473]
    DIRECTION INPUT ;
    USE SIGNAL ;
    PORT
      LAYER M4 ;
        RECT  94.848 84.096 95.04 84.12 ;
    END
  END i_d[473]
  PIN i_d[474]
    DIRECTION INPUT ;
    USE SIGNAL ;
    PORT
      LAYER M4 ;
        RECT  94.848 84.384 95.04 84.408 ;
    END
  END i_d[474]
  PIN i_d[475]
    DIRECTION INPUT ;
    USE SIGNAL ;
    PORT
      LAYER M4 ;
        RECT  94.848 84.528 95.04 84.552 ;
    END
  END i_d[475]
  PIN i_d[476]
    DIRECTION INPUT ;
    USE SIGNAL ;
    PORT
      LAYER M4 ;
        RECT  94.848 84.672 95.04 84.696 ;
    END
  END i_d[476]
  PIN i_d[477]
    DIRECTION INPUT ;
    USE SIGNAL ;
    PORT
      LAYER M4 ;
        RECT  94.848 84.816 95.04 84.84 ;
    END
  END i_d[477]
  PIN i_d[478]
    DIRECTION INPUT ;
    USE SIGNAL ;
    PORT
      LAYER M4 ;
        RECT  94.848 84.96 95.04 84.984 ;
    END
  END i_d[478]
  PIN i_d[479]
    DIRECTION INPUT ;
    USE SIGNAL ;
    PORT
      LAYER M4 ;
        RECT  94.848 85.104 95.04 85.128 ;
    END
  END i_d[479]
  PIN i_d[47]
    DIRECTION INPUT ;
    USE SIGNAL ;
    PORT
      LAYER M4 ;
        RECT  94.848 12.24 95.04 12.264 ;
    END
  END i_d[47]
  PIN i_d[480]
    DIRECTION INPUT ;
    USE SIGNAL ;
    PORT
      LAYER M4 ;
        RECT  94.848 85.392 95.04 85.416 ;
    END
  END i_d[480]
  PIN i_d[481]
    DIRECTION INPUT ;
    USE SIGNAL ;
    PORT
      LAYER M4 ;
        RECT  94.848 85.536 95.04 85.56 ;
    END
  END i_d[481]
  PIN i_d[482]
    DIRECTION INPUT ;
    USE SIGNAL ;
    PORT
      LAYER M4 ;
        RECT  94.848 85.68 95.04 85.704 ;
    END
  END i_d[482]
  PIN i_d[483]
    DIRECTION INPUT ;
    USE SIGNAL ;
    PORT
      LAYER M4 ;
        RECT  94.848 85.824 95.04 85.848 ;
    END
  END i_d[483]
  PIN i_d[484]
    DIRECTION INPUT ;
    USE SIGNAL ;
    PORT
      LAYER M4 ;
        RECT  94.848 85.968 95.04 85.992 ;
    END
  END i_d[484]
  PIN i_d[485]
    DIRECTION INPUT ;
    USE SIGNAL ;
    PORT
      LAYER M4 ;
        RECT  94.848 86.112 95.04 86.136 ;
    END
  END i_d[485]
  PIN i_d[486]
    DIRECTION INPUT ;
    USE SIGNAL ;
    PORT
      LAYER M4 ;
        RECT  94.848 86.4 95.04 86.424 ;
    END
  END i_d[486]
  PIN i_d[487]
    DIRECTION INPUT ;
    USE SIGNAL ;
    PORT
      LAYER M4 ;
        RECT  94.848 86.544 95.04 86.568 ;
    END
  END i_d[487]
  PIN i_d[488]
    DIRECTION INPUT ;
    USE SIGNAL ;
    PORT
      LAYER M4 ;
        RECT  94.848 86.688 95.04 86.712 ;
    END
  END i_d[488]
  PIN i_d[489]
    DIRECTION INPUT ;
    USE SIGNAL ;
    PORT
      LAYER M4 ;
        RECT  94.848 86.832 95.04 86.856 ;
    END
  END i_d[489]
  PIN i_d[48]
    DIRECTION INPUT ;
    USE SIGNAL ;
    PORT
      LAYER M4 ;
        RECT  94.848 12.384 95.04 12.408 ;
    END
  END i_d[48]
  PIN i_d[490]
    DIRECTION INPUT ;
    USE SIGNAL ;
    PORT
      LAYER M4 ;
        RECT  94.848 86.976 95.04 87 ;
    END
  END i_d[490]
  PIN i_d[491]
    DIRECTION INPUT ;
    USE SIGNAL ;
    PORT
      LAYER M4 ;
        RECT  94.848 87.12 95.04 87.144 ;
    END
  END i_d[491]
  PIN i_d[492]
    DIRECTION INPUT ;
    USE SIGNAL ;
    PORT
      LAYER M4 ;
        RECT  94.848 87.408 95.04 87.432 ;
    END
  END i_d[492]
  PIN i_d[493]
    DIRECTION INPUT ;
    USE SIGNAL ;
    PORT
      LAYER M4 ;
        RECT  94.848 87.552 95.04 87.576 ;
    END
  END i_d[493]
  PIN i_d[494]
    DIRECTION INPUT ;
    USE SIGNAL ;
    PORT
      LAYER M4 ;
        RECT  94.848 87.696 95.04 87.72 ;
    END
  END i_d[494]
  PIN i_d[495]
    DIRECTION INPUT ;
    USE SIGNAL ;
    PORT
      LAYER M4 ;
        RECT  94.848 87.84 95.04 87.864 ;
    END
  END i_d[495]
  PIN i_d[496]
    DIRECTION INPUT ;
    USE SIGNAL ;
    PORT
      LAYER M4 ;
        RECT  94.848 87.984 95.04 88.008 ;
    END
  END i_d[496]
  PIN i_d[497]
    DIRECTION INPUT ;
    USE SIGNAL ;
    PORT
      LAYER M4 ;
        RECT  94.848 88.272 95.04 88.296 ;
    END
  END i_d[497]
  PIN i_d[498]
    DIRECTION INPUT ;
    USE SIGNAL ;
    PORT
      LAYER M4 ;
        RECT  94.848 88.416 95.04 88.44 ;
    END
  END i_d[498]
  PIN i_d[499]
    DIRECTION INPUT ;
    USE SIGNAL ;
    PORT
      LAYER M4 ;
        RECT  94.848 88.56 95.04 88.584 ;
    END
  END i_d[499]
  PIN i_d[49]
    DIRECTION INPUT ;
    USE SIGNAL ;
    PORT
      LAYER M4 ;
        RECT  94.848 12.672 95.04 12.696 ;
    END
  END i_d[49]
  PIN i_d[4]
    DIRECTION INPUT ;
    USE SIGNAL ;
    PORT
      LAYER M4 ;
        RECT  94.848 5.04 95.04 5.064 ;
    END
  END i_d[4]
  PIN i_d[500]
    DIRECTION INPUT ;
    USE SIGNAL ;
    PORT
      LAYER M4 ;
        RECT  94.848 88.704 95.04 88.728 ;
    END
  END i_d[500]
  PIN i_d[501]
    DIRECTION INPUT ;
    USE SIGNAL ;
    PORT
      LAYER M4 ;
        RECT  94.848 88.848 95.04 88.872 ;
    END
  END i_d[501]
  PIN i_d[502]
    DIRECTION INPUT ;
    USE SIGNAL ;
    PORT
      LAYER M4 ;
        RECT  94.848 88.992 95.04 89.016 ;
    END
  END i_d[502]
  PIN i_d[503]
    DIRECTION INPUT ;
    USE SIGNAL ;
    PORT
      LAYER M4 ;
        RECT  94.848 89.28 95.04 89.304 ;
    END
  END i_d[503]
  PIN i_d[504]
    DIRECTION INPUT ;
    USE SIGNAL ;
    PORT
      LAYER M4 ;
        RECT  94.848 89.424 95.04 89.448 ;
    END
  END i_d[504]
  PIN i_d[505]
    DIRECTION INPUT ;
    USE SIGNAL ;
    PORT
      LAYER M4 ;
        RECT  94.848 89.568 95.04 89.592 ;
    END
  END i_d[505]
  PIN i_d[506]
    DIRECTION INPUT ;
    USE SIGNAL ;
    PORT
      LAYER M4 ;
        RECT  94.848 89.712 95.04 89.736 ;
    END
  END i_d[506]
  PIN i_d[507]
    DIRECTION INPUT ;
    USE SIGNAL ;
    PORT
      LAYER M4 ;
        RECT  94.848 89.856 95.04 89.88 ;
    END
  END i_d[507]
  PIN i_d[508]
    DIRECTION INPUT ;
    USE SIGNAL ;
    PORT
      LAYER M4 ;
        RECT  94.848 90 95.04 90.024 ;
    END
  END i_d[508]
  PIN i_d[509]
    DIRECTION INPUT ;
    USE SIGNAL ;
    PORT
      LAYER M4 ;
        RECT  94.848 90.288 95.04 90.312 ;
    END
  END i_d[509]
  PIN i_d[50]
    DIRECTION INPUT ;
    USE SIGNAL ;
    PORT
      LAYER M4 ;
        RECT  94.848 12.816 95.04 12.84 ;
    END
  END i_d[50]
  PIN i_d[510]
    DIRECTION INPUT ;
    USE SIGNAL ;
    PORT
      LAYER M4 ;
        RECT  94.848 90.432 95.04 90.456 ;
    END
  END i_d[510]
  PIN i_d[511]
    DIRECTION INPUT ;
    USE SIGNAL ;
    PORT
      LAYER M4 ;
        RECT  94.848 90.576 95.04 90.6 ;
    END
  END i_d[511]
  PIN i_d[51]
    DIRECTION INPUT ;
    USE SIGNAL ;
    PORT
      LAYER M4 ;
        RECT  94.848 12.96 95.04 12.984 ;
    END
  END i_d[51]
  PIN i_d[52]
    DIRECTION INPUT ;
    USE SIGNAL ;
    PORT
      LAYER M4 ;
        RECT  94.848 13.104 95.04 13.128 ;
    END
  END i_d[52]
  PIN i_d[53]
    DIRECTION INPUT ;
    USE SIGNAL ;
    PORT
      LAYER M4 ;
        RECT  94.848 13.248 95.04 13.272 ;
    END
  END i_d[53]
  PIN i_d[54]
    DIRECTION INPUT ;
    USE SIGNAL ;
    PORT
      LAYER M4 ;
        RECT  94.848 13.392 95.04 13.416 ;
    END
  END i_d[54]
  PIN i_d[55]
    DIRECTION INPUT ;
    USE SIGNAL ;
    PORT
      LAYER M4 ;
        RECT  94.848 13.68 95.04 13.704 ;
    END
  END i_d[55]
  PIN i_d[56]
    DIRECTION INPUT ;
    USE SIGNAL ;
    PORT
      LAYER M4 ;
        RECT  94.848 13.824 95.04 13.848 ;
    END
  END i_d[56]
  PIN i_d[57]
    DIRECTION INPUT ;
    USE SIGNAL ;
    PORT
      LAYER M4 ;
        RECT  94.848 13.968 95.04 13.992 ;
    END
  END i_d[57]
  PIN i_d[58]
    DIRECTION INPUT ;
    USE SIGNAL ;
    PORT
      LAYER M4 ;
        RECT  94.848 14.112 95.04 14.136 ;
    END
  END i_d[58]
  PIN i_d[59]
    DIRECTION INPUT ;
    USE SIGNAL ;
    PORT
      LAYER M4 ;
        RECT  94.848 14.256 95.04 14.28 ;
    END
  END i_d[59]
  PIN i_d[5]
    DIRECTION INPUT ;
    USE SIGNAL ;
    PORT
      LAYER M4 ;
        RECT  94.848 5.184 95.04 5.208 ;
    END
  END i_d[5]
  PIN i_d[60]
    DIRECTION INPUT ;
    USE SIGNAL ;
    PORT
      LAYER M4 ;
        RECT  94.848 14.4 95.04 14.424 ;
    END
  END i_d[60]
  PIN i_d[61]
    DIRECTION INPUT ;
    USE SIGNAL ;
    PORT
      LAYER M4 ;
        RECT  94.848 14.688 95.04 14.712 ;
    END
  END i_d[61]
  PIN i_d[62]
    DIRECTION INPUT ;
    USE SIGNAL ;
    PORT
      LAYER M4 ;
        RECT  94.848 14.832 95.04 14.856 ;
    END
  END i_d[62]
  PIN i_d[63]
    DIRECTION INPUT ;
    USE SIGNAL ;
    PORT
      LAYER M4 ;
        RECT  94.848 14.976 95.04 15 ;
    END
  END i_d[63]
  PIN i_d[64]
    DIRECTION INPUT ;
    USE SIGNAL ;
    PORT
      LAYER M4 ;
        RECT  94.848 15.12 95.04 15.144 ;
    END
  END i_d[64]
  PIN i_d[65]
    DIRECTION INPUT ;
    USE SIGNAL ;
    PORT
      LAYER M4 ;
        RECT  94.848 15.264 95.04 15.288 ;
    END
  END i_d[65]
  PIN i_d[66]
    DIRECTION INPUT ;
    USE SIGNAL ;
    PORT
      LAYER M4 ;
        RECT  94.848 15.408 95.04 15.432 ;
    END
  END i_d[66]
  PIN i_d[67]
    DIRECTION INPUT ;
    USE SIGNAL ;
    PORT
      LAYER M4 ;
        RECT  94.848 15.696 95.04 15.72 ;
    END
  END i_d[67]
  PIN i_d[68]
    DIRECTION INPUT ;
    USE SIGNAL ;
    PORT
      LAYER M4 ;
        RECT  94.848 15.84 95.04 15.864 ;
    END
  END i_d[68]
  PIN i_d[69]
    DIRECTION INPUT ;
    USE SIGNAL ;
    PORT
      LAYER M4 ;
        RECT  94.848 15.984 95.04 16.008 ;
    END
  END i_d[69]
  PIN i_d[6]
    DIRECTION INPUT ;
    USE SIGNAL ;
    PORT
      LAYER M4 ;
        RECT  94.848 5.328 95.04 5.352 ;
    END
  END i_d[6]
  PIN i_d[70]
    DIRECTION INPUT ;
    USE SIGNAL ;
    PORT
      LAYER M4 ;
        RECT  94.848 16.128 95.04 16.152 ;
    END
  END i_d[70]
  PIN i_d[71]
    DIRECTION INPUT ;
    USE SIGNAL ;
    PORT
      LAYER M4 ;
        RECT  94.848 16.272 95.04 16.296 ;
    END
  END i_d[71]
  PIN i_d[72]
    DIRECTION INPUT ;
    USE SIGNAL ;
    PORT
      LAYER M4 ;
        RECT  94.848 16.416 95.04 16.44 ;
    END
  END i_d[72]
  PIN i_d[73]
    DIRECTION INPUT ;
    USE SIGNAL ;
    PORT
      LAYER M4 ;
        RECT  94.848 16.704 95.04 16.728 ;
    END
  END i_d[73]
  PIN i_d[74]
    DIRECTION INPUT ;
    USE SIGNAL ;
    PORT
      LAYER M4 ;
        RECT  94.848 16.848 95.04 16.872 ;
    END
  END i_d[74]
  PIN i_d[75]
    DIRECTION INPUT ;
    USE SIGNAL ;
    PORT
      LAYER M4 ;
        RECT  94.848 16.992 95.04 17.016 ;
    END
  END i_d[75]
  PIN i_d[76]
    DIRECTION INPUT ;
    USE SIGNAL ;
    PORT
      LAYER M4 ;
        RECT  94.848 17.136 95.04 17.16 ;
    END
  END i_d[76]
  PIN i_d[77]
    DIRECTION INPUT ;
    USE SIGNAL ;
    PORT
      LAYER M4 ;
        RECT  94.848 17.28 95.04 17.304 ;
    END
  END i_d[77]
  PIN i_d[78]
    DIRECTION INPUT ;
    USE SIGNAL ;
    PORT
      LAYER M4 ;
        RECT  94.848 17.424 95.04 17.448 ;
    END
  END i_d[78]
  PIN i_d[79]
    DIRECTION INPUT ;
    USE SIGNAL ;
    PORT
      LAYER M4 ;
        RECT  94.848 17.712 95.04 17.736 ;
    END
  END i_d[79]
  PIN i_d[7]
    DIRECTION INPUT ;
    USE SIGNAL ;
    PORT
      LAYER M4 ;
        RECT  94.848 5.472 95.04 5.496 ;
    END
  END i_d[7]
  PIN i_d[80]
    DIRECTION INPUT ;
    USE SIGNAL ;
    PORT
      LAYER M4 ;
        RECT  94.848 17.856 95.04 17.88 ;
    END
  END i_d[80]
  PIN i_d[81]
    DIRECTION INPUT ;
    USE SIGNAL ;
    PORT
      LAYER M4 ;
        RECT  94.848 18 95.04 18.024 ;
    END
  END i_d[81]
  PIN i_d[82]
    DIRECTION INPUT ;
    USE SIGNAL ;
    PORT
      LAYER M4 ;
        RECT  94.848 18.144 95.04 18.168 ;
    END
  END i_d[82]
  PIN i_d[83]
    DIRECTION INPUT ;
    USE SIGNAL ;
    PORT
      LAYER M4 ;
        RECT  94.848 18.288 95.04 18.312 ;
    END
  END i_d[83]
  PIN i_d[84]
    DIRECTION INPUT ;
    USE SIGNAL ;
    PORT
      LAYER M4 ;
        RECT  94.848 18.576 95.04 18.6 ;
    END
  END i_d[84]
  PIN i_d[85]
    DIRECTION INPUT ;
    USE SIGNAL ;
    PORT
      LAYER M4 ;
        RECT  94.848 18.72 95.04 18.744 ;
    END
  END i_d[85]
  PIN i_d[86]
    DIRECTION INPUT ;
    USE SIGNAL ;
    PORT
      LAYER M4 ;
        RECT  94.848 18.864 95.04 18.888 ;
    END
  END i_d[86]
  PIN i_d[87]
    DIRECTION INPUT ;
    USE SIGNAL ;
    PORT
      LAYER M4 ;
        RECT  94.848 19.008 95.04 19.032 ;
    END
  END i_d[87]
  PIN i_d[88]
    DIRECTION INPUT ;
    USE SIGNAL ;
    PORT
      LAYER M4 ;
        RECT  94.848 19.152 95.04 19.176 ;
    END
  END i_d[88]
  PIN i_d[89]
    DIRECTION INPUT ;
    USE SIGNAL ;
    PORT
      LAYER M4 ;
        RECT  94.848 19.296 95.04 19.32 ;
    END
  END i_d[89]
  PIN i_d[8]
    DIRECTION INPUT ;
    USE SIGNAL ;
    PORT
      LAYER M4 ;
        RECT  94.848 5.616 95.04 5.64 ;
    END
  END i_d[8]
  PIN i_d[90]
    DIRECTION INPUT ;
    USE SIGNAL ;
    PORT
      LAYER M4 ;
        RECT  94.848 19.584 95.04 19.608 ;
    END
  END i_d[90]
  PIN i_d[91]
    DIRECTION INPUT ;
    USE SIGNAL ;
    PORT
      LAYER M4 ;
        RECT  94.848 19.728 95.04 19.752 ;
    END
  END i_d[91]
  PIN i_d[92]
    DIRECTION INPUT ;
    USE SIGNAL ;
    PORT
      LAYER M4 ;
        RECT  94.848 19.872 95.04 19.896 ;
    END
  END i_d[92]
  PIN i_d[93]
    DIRECTION INPUT ;
    USE SIGNAL ;
    PORT
      LAYER M4 ;
        RECT  94.848 20.016 95.04 20.04 ;
    END
  END i_d[93]
  PIN i_d[94]
    DIRECTION INPUT ;
    USE SIGNAL ;
    PORT
      LAYER M4 ;
        RECT  94.848 20.16 95.04 20.184 ;
    END
  END i_d[94]
  PIN i_d[95]
    DIRECTION INPUT ;
    USE SIGNAL ;
    PORT
      LAYER M4 ;
        RECT  94.848 20.304 95.04 20.328 ;
    END
  END i_d[95]
  PIN i_d[96]
    DIRECTION INPUT ;
    USE SIGNAL ;
    PORT
      LAYER M4 ;
        RECT  94.848 20.592 95.04 20.616 ;
    END
  END i_d[96]
  PIN i_d[97]
    DIRECTION INPUT ;
    USE SIGNAL ;
    PORT
      LAYER M4 ;
        RECT  94.848 20.736 95.04 20.76 ;
    END
  END i_d[97]
  PIN i_d[98]
    DIRECTION INPUT ;
    USE SIGNAL ;
    PORT
      LAYER M4 ;
        RECT  94.848 20.88 95.04 20.904 ;
    END
  END i_d[98]
  PIN i_d[99]
    DIRECTION INPUT ;
    USE SIGNAL ;
    PORT
      LAYER M4 ;
        RECT  94.848 21.024 95.04 21.048 ;
    END
  END i_d[99]
  PIN i_d[9]
    DIRECTION INPUT ;
    USE SIGNAL ;
    PORT
      LAYER M4 ;
        RECT  94.848 5.904 95.04 5.928 ;
    END
  END i_d[9]
  PIN i_v
    DIRECTION INPUT ;
    USE SIGNAL ;
    PORT
      LAYER M5 ;
        RECT  88.896 94.848 88.92 95.04 ;
    END
    PORT
      LAYER M5 ;
        RECT  88.896 92.903 88.92 94.864 ;
    END
  END i_v
  PIN larm_base[0]
    DIRECTION INPUT ;
    USE SIGNAL ;
    PORT
      LAYER M5 ;
        RECT  34.032 94.848 34.056 95.04 ;
    END
    PORT
      LAYER M5 ;
        RECT  34.032 92.903 34.056 94.864 ;
    END
  END larm_base[0]
  PIN larm_base[10]
    DIRECTION INPUT ;
    USE SIGNAL ;
    PORT
      LAYER M5 ;
        RECT  73.104 94.848 73.128 95.04 ;
    END
    PORT
      LAYER M5 ;
        RECT  73.104 94.069 73.128 94.864 ;
    END
  END larm_base[10]
  PIN larm_base[11]
    DIRECTION INPUT ;
    USE SIGNAL ;
    PORT
      LAYER M5 ;
        RECT  77.232 94.848 77.256 95.04 ;
    END
    PORT
      LAYER M5 ;
        RECT  77.232 92.903 77.256 94.864 ;
    END
  END larm_base[11]
  PIN larm_base[12]
    DIRECTION INPUT ;
    USE SIGNAL ;
    PORT
      LAYER M5 ;
        RECT  80.832 94.848 80.856 95.04 ;
    END
    PORT
      LAYER M5 ;
        RECT  80.832 92.821 80.856 94.864 ;
    END
  END larm_base[12]
  PIN larm_base[13]
    DIRECTION INPUT ;
    USE SIGNAL ;
    PORT
      LAYER M5 ;
        RECT  84.768 94.848 84.792 95.04 ;
    END
    PORT
      LAYER M5 ;
        RECT  84.768 92.821 84.792 94.864 ;
    END
  END larm_base[13]
  PIN larm_base[1]
    DIRECTION INPUT ;
    USE SIGNAL ;
    PORT
      LAYER M5 ;
        RECT  37.632 94.848 37.656 95.04 ;
    END
    PORT
      LAYER M5 ;
        RECT  37.632 94.069 37.656 94.864 ;
    END
  END larm_base[1]
  PIN larm_base[2]
    DIRECTION INPUT ;
    USE SIGNAL ;
    PORT
      LAYER M5 ;
        RECT  41.568 94.848 41.592 95.04 ;
    END
    PORT
      LAYER M5 ;
        RECT  41.568 92.821 41.592 94.864 ;
    END
  END larm_base[2]
  PIN larm_base[3]
    DIRECTION INPUT ;
    USE SIGNAL ;
    PORT
      LAYER M5 ;
        RECT  45.696 94.848 45.72 95.04 ;
    END
    PORT
      LAYER M5 ;
        RECT  45.696 94.069 45.72 94.864 ;
    END
  END larm_base[3]
  PIN larm_base[4]
    DIRECTION INPUT ;
    USE SIGNAL ;
    PORT
      LAYER M5 ;
        RECT  49.776 94.848 49.8 95.04 ;
    END
    PORT
      LAYER M5 ;
        RECT  49.776 92.821 49.8 94.864 ;
    END
  END larm_base[4]
  PIN larm_base[5]
    DIRECTION INPUT ;
    USE SIGNAL ;
    PORT
      LAYER M5 ;
        RECT  53.376 94.848 53.4 95.04 ;
    END
    PORT
      LAYER M5 ;
        RECT  53.376 92.821 53.4 94.864 ;
    END
  END larm_base[5]
  PIN larm_base[6]
    DIRECTION INPUT ;
    USE SIGNAL ;
    PORT
      LAYER M5 ;
        RECT  57.36 94.848 57.384 95.04 ;
    END
    PORT
      LAYER M5 ;
        RECT  57.36 92.903 57.384 94.864 ;
    END
  END larm_base[6]
  PIN larm_base[7]
    DIRECTION INPUT ;
    USE SIGNAL ;
    PORT
      LAYER M5 ;
        RECT  61.44 94.848 61.464 95.04 ;
    END
    PORT
      LAYER M5 ;
        RECT  61.44 92.903 61.464 94.864 ;
    END
  END larm_base[7]
  PIN larm_base[8]
    DIRECTION INPUT ;
    USE SIGNAL ;
    PORT
      LAYER M5 ;
        RECT  65.568 94.848 65.592 95.04 ;
    END
    PORT
      LAYER M5 ;
        RECT  65.568 94.069 65.592 94.864 ;
    END
  END larm_base[8]
  PIN larm_base[9]
    DIRECTION INPUT ;
    USE SIGNAL ;
    PORT
      LAYER M5 ;
        RECT  69.168 94.848 69.192 95.04 ;
    END
    PORT
      LAYER M5 ;
        RECT  69.168 94.069 69.192 94.864 ;
    END
  END larm_base[9]
  PIN larm_g[0]
    DIRECTION INPUT ;
    USE SIGNAL ;
    PORT
      LAYER M5 ;
        RECT  18.24 94.848 18.264 95.04 ;
    END
    PORT
      LAYER M5 ;
        RECT  18.24 94.069 18.264 94.864 ;
    END
  END larm_g[0]
  PIN larm_g[1]
    DIRECTION INPUT ;
    USE SIGNAL ;
    PORT
      LAYER M5 ;
        RECT  22.368 94.848 22.392 95.04 ;
    END
    PORT
      LAYER M5 ;
        RECT  22.368 94.069 22.392 94.864 ;
    END
  END larm_g[1]
  PIN larm_g[2]
    DIRECTION INPUT ;
    USE SIGNAL ;
    PORT
      LAYER M5 ;
        RECT  25.968 94.848 25.992 95.04 ;
    END
    PORT
      LAYER M5 ;
        RECT  25.968 94.069 25.992 94.864 ;
    END
  END larm_g[2]
  PIN larm_g[3]
    DIRECTION INPUT ;
    USE SIGNAL ;
    PORT
      LAYER M5 ;
        RECT  29.904 94.848 29.928 95.04 ;
    END
    PORT
      LAYER M5 ;
        RECT  29.904 94.069 29.928 94.864 ;
    END
  END larm_g[3]
  PIN larm_v
    DIRECTION INPUT ;
    USE SIGNAL ;
    PORT
      LAYER M5 ;
        RECT  14.16 94.848 14.184 95.04 ;
    END
    PORT
      LAYER M5 ;
        RECT  14.16 92.903 14.184 94.864 ;
    END
  END larm_v
  PIN o_d[0]
    DIRECTION OUTPUT ;
    USE SIGNAL ;
    PORT
      LAYER M4 ;
        RECT  0 4.32 0.192 4.344 ;
    END
  END o_d[0]
  PIN o_d[100]
    DIRECTION OUTPUT ;
    USE SIGNAL ;
    PORT
      LAYER M4 ;
        RECT  0 20.736 0.192 20.76 ;
    END
  END o_d[100]
  PIN o_d[101]
    DIRECTION OUTPUT ;
    USE SIGNAL ;
    PORT
      LAYER M4 ;
        RECT  0 20.88 0.192 20.904 ;
    END
  END o_d[101]
  PIN o_d[102]
    DIRECTION OUTPUT ;
    USE SIGNAL ;
    PORT
      LAYER M4 ;
        RECT  0 21.024 0.192 21.048 ;
    END
  END o_d[102]
  PIN o_d[103]
    DIRECTION OUTPUT ;
    USE SIGNAL ;
    PORT
      LAYER M4 ;
        RECT  0 21.168 0.192 21.192 ;
    END
  END o_d[103]
  PIN o_d[104]
    DIRECTION OUTPUT ;
    USE SIGNAL ;
    PORT
      LAYER M4 ;
        RECT  0 21.312 0.192 21.336 ;
    END
  END o_d[104]
  PIN o_d[105]
    DIRECTION OUTPUT ;
    USE SIGNAL ;
    PORT
      LAYER M4 ;
        RECT  0 21.6 0.192 21.624 ;
    END
  END o_d[105]
  PIN o_d[106]
    DIRECTION OUTPUT ;
    USE SIGNAL ;
    PORT
      LAYER M4 ;
        RECT  0 21.744 0.192 21.768 ;
    END
  END o_d[106]
  PIN o_d[107]
    DIRECTION OUTPUT ;
    USE SIGNAL ;
    PORT
      LAYER M4 ;
        RECT  0 21.888 0.192 21.912 ;
    END
  END o_d[107]
  PIN o_d[108]
    DIRECTION OUTPUT ;
    USE SIGNAL ;
    PORT
      LAYER M4 ;
        RECT  0 22.032 0.192 22.056 ;
    END
  END o_d[108]
  PIN o_d[109]
    DIRECTION OUTPUT ;
    USE SIGNAL ;
    PORT
      LAYER M4 ;
        RECT  0 22.176 0.192 22.2 ;
    END
  END o_d[109]
  PIN o_d[10]
    DIRECTION OUTPUT ;
    USE SIGNAL ;
    PORT
      LAYER M4 ;
        RECT  0 5.904 0.192 5.928 ;
    END
  END o_d[10]
  PIN o_d[110]
    DIRECTION OUTPUT ;
    USE SIGNAL ;
    PORT
      LAYER M4 ;
        RECT  0 22.32 0.192 22.344 ;
    END
  END o_d[110]
  PIN o_d[111]
    DIRECTION OUTPUT ;
    USE SIGNAL ;
    PORT
      LAYER M4 ;
        RECT  0 22.464 0.192 22.488 ;
    END
  END o_d[111]
  PIN o_d[112]
    DIRECTION OUTPUT ;
    USE SIGNAL ;
    PORT
      LAYER M4 ;
        RECT  0 22.752 0.192 22.776 ;
    END
  END o_d[112]
  PIN o_d[113]
    DIRECTION OUTPUT ;
    USE SIGNAL ;
    PORT
      LAYER M4 ;
        RECT  0 22.896 0.192 22.92 ;
    END
  END o_d[113]
  PIN o_d[114]
    DIRECTION OUTPUT ;
    USE SIGNAL ;
    PORT
      LAYER M4 ;
        RECT  0 23.04 0.192 23.064 ;
    END
  END o_d[114]
  PIN o_d[115]
    DIRECTION OUTPUT ;
    USE SIGNAL ;
    PORT
      LAYER M4 ;
        RECT  0 23.184 0.192 23.208 ;
    END
  END o_d[115]
  PIN o_d[116]
    DIRECTION OUTPUT ;
    USE SIGNAL ;
    PORT
      LAYER M4 ;
        RECT  0 23.328 0.192 23.352 ;
    END
  END o_d[116]
  PIN o_d[117]
    DIRECTION OUTPUT ;
    USE SIGNAL ;
    PORT
      LAYER M4 ;
        RECT  0 23.472 0.192 23.496 ;
    END
  END o_d[117]
  PIN o_d[118]
    DIRECTION OUTPUT ;
    USE SIGNAL ;
    PORT
      LAYER M4 ;
        RECT  0 23.616 0.192 23.64 ;
    END
  END o_d[118]
  PIN o_d[119]
    DIRECTION OUTPUT ;
    USE SIGNAL ;
    PORT
      LAYER M4 ;
        RECT  0 23.904 0.192 23.928 ;
    END
  END o_d[119]
  PIN o_d[11]
    DIRECTION OUTPUT ;
    USE SIGNAL ;
    PORT
      LAYER M4 ;
        RECT  0 6.192 0.192 6.216 ;
    END
  END o_d[11]
  PIN o_d[120]
    DIRECTION OUTPUT ;
    USE SIGNAL ;
    PORT
      LAYER M4 ;
        RECT  0 24.048 0.192 24.072 ;
    END
  END o_d[120]
  PIN o_d[121]
    DIRECTION OUTPUT ;
    USE SIGNAL ;
    PORT
      LAYER M4 ;
        RECT  0 24.192 0.192 24.216 ;
    END
  END o_d[121]
  PIN o_d[122]
    DIRECTION OUTPUT ;
    USE SIGNAL ;
    PORT
      LAYER M4 ;
        RECT  0 24.336 0.192 24.36 ;
    END
  END o_d[122]
  PIN o_d[123]
    DIRECTION OUTPUT ;
    USE SIGNAL ;
    PORT
      LAYER M4 ;
        RECT  0 24.48 0.192 24.504 ;
    END
  END o_d[123]
  PIN o_d[124]
    DIRECTION OUTPUT ;
    USE SIGNAL ;
    PORT
      LAYER M4 ;
        RECT  0 24.624 0.192 24.648 ;
    END
  END o_d[124]
  PIN o_d[125]
    DIRECTION OUTPUT ;
    USE SIGNAL ;
    PORT
      LAYER M4 ;
        RECT  0 24.768 0.192 24.792 ;
    END
  END o_d[125]
  PIN o_d[126]
    DIRECTION OUTPUT ;
    USE SIGNAL ;
    PORT
      LAYER M4 ;
        RECT  0 25.056 0.192 25.08 ;
    END
  END o_d[126]
  PIN o_d[127]
    DIRECTION OUTPUT ;
    USE SIGNAL ;
    PORT
      LAYER M4 ;
        RECT  0 25.2 0.192 25.224 ;
    END
  END o_d[127]
  PIN o_d[128]
    DIRECTION OUTPUT ;
    USE SIGNAL ;
    PORT
      LAYER M4 ;
        RECT  0 25.344 0.192 25.368 ;
    END
  END o_d[128]
  PIN o_d[129]
    DIRECTION OUTPUT ;
    USE SIGNAL ;
    PORT
      LAYER M4 ;
        RECT  0 25.488 0.192 25.512 ;
    END
  END o_d[129]
  PIN o_d[12]
    DIRECTION OUTPUT ;
    USE SIGNAL ;
    PORT
      LAYER M4 ;
        RECT  0 6.336 0.192 6.36 ;
    END
  END o_d[12]
  PIN o_d[130]
    DIRECTION OUTPUT ;
    USE SIGNAL ;
    PORT
      LAYER M4 ;
        RECT  0 25.632 0.192 25.656 ;
    END
  END o_d[130]
  PIN o_d[131]
    DIRECTION OUTPUT ;
    USE SIGNAL ;
    PORT
      LAYER M4 ;
        RECT  0 25.776 0.192 25.8 ;
    END
  END o_d[131]
  PIN o_d[132]
    DIRECTION OUTPUT ;
    USE SIGNAL ;
    PORT
      LAYER M4 ;
        RECT  0 25.92 0.192 25.944 ;
    END
  END o_d[132]
  PIN o_d[133]
    DIRECTION OUTPUT ;
    USE SIGNAL ;
    PORT
      LAYER M4 ;
        RECT  0 26.064 0.192 26.088 ;
    END
  END o_d[133]
  PIN o_d[134]
    DIRECTION OUTPUT ;
    USE SIGNAL ;
    PORT
      LAYER M4 ;
        RECT  0 26.352 0.192 26.376 ;
    END
  END o_d[134]
  PIN o_d[135]
    DIRECTION OUTPUT ;
    USE SIGNAL ;
    PORT
      LAYER M4 ;
        RECT  0 26.496 0.192 26.52 ;
    END
  END o_d[135]
  PIN o_d[136]
    DIRECTION OUTPUT ;
    USE SIGNAL ;
    PORT
      LAYER M4 ;
        RECT  0 26.64 0.192 26.664 ;
    END
  END o_d[136]
  PIN o_d[137]
    DIRECTION OUTPUT ;
    USE SIGNAL ;
    PORT
      LAYER M4 ;
        RECT  0 26.784 0.192 26.808 ;
    END
  END o_d[137]
  PIN o_d[138]
    DIRECTION OUTPUT ;
    USE SIGNAL ;
    PORT
      LAYER M4 ;
        RECT  0 26.928 0.192 26.952 ;
    END
  END o_d[138]
  PIN o_d[139]
    DIRECTION OUTPUT ;
    USE SIGNAL ;
    PORT
      LAYER M4 ;
        RECT  0 27.072 0.192 27.096 ;
    END
  END o_d[139]
  PIN o_d[13]
    DIRECTION OUTPUT ;
    USE SIGNAL ;
    PORT
      LAYER M4 ;
        RECT  0 6.48 0.192 6.504 ;
    END
  END o_d[13]
  PIN o_d[140]
    DIRECTION OUTPUT ;
    USE SIGNAL ;
    PORT
      LAYER M4 ;
        RECT  0 27.216 0.192 27.24 ;
    END
  END o_d[140]
  PIN o_d[141]
    DIRECTION OUTPUT ;
    USE SIGNAL ;
    PORT
      LAYER M4 ;
        RECT  0 27.504 0.192 27.528 ;
    END
  END o_d[141]
  PIN o_d[142]
    DIRECTION OUTPUT ;
    USE SIGNAL ;
    PORT
      LAYER M4 ;
        RECT  0 27.648 0.192 27.672 ;
    END
  END o_d[142]
  PIN o_d[143]
    DIRECTION OUTPUT ;
    USE SIGNAL ;
    PORT
      LAYER M4 ;
        RECT  0 27.792 0.192 27.816 ;
    END
  END o_d[143]
  PIN o_d[144]
    DIRECTION OUTPUT ;
    USE SIGNAL ;
    PORT
      LAYER M4 ;
        RECT  0 27.936 0.192 27.96 ;
    END
  END o_d[144]
  PIN o_d[145]
    DIRECTION OUTPUT ;
    USE SIGNAL ;
    PORT
      LAYER M4 ;
        RECT  0 28.08 0.192 28.104 ;
    END
  END o_d[145]
  PIN o_d[146]
    DIRECTION OUTPUT ;
    USE SIGNAL ;
    PORT
      LAYER M4 ;
        RECT  0 28.224 0.192 28.248 ;
    END
  END o_d[146]
  PIN o_d[147]
    DIRECTION OUTPUT ;
    USE SIGNAL ;
    PORT
      LAYER M4 ;
        RECT  0 28.368 0.192 28.392 ;
    END
  END o_d[147]
  PIN o_d[148]
    DIRECTION OUTPUT ;
    USE SIGNAL ;
    PORT
      LAYER M4 ;
        RECT  0 28.656 0.192 28.68 ;
    END
  END o_d[148]
  PIN o_d[149]
    DIRECTION OUTPUT ;
    USE SIGNAL ;
    PORT
      LAYER M4 ;
        RECT  0 28.8 0.192 28.824 ;
    END
  END o_d[149]
  PIN o_d[14]
    DIRECTION OUTPUT ;
    USE SIGNAL ;
    PORT
      LAYER M4 ;
        RECT  0 6.624 0.192 6.648 ;
    END
  END o_d[14]
  PIN o_d[150]
    DIRECTION OUTPUT ;
    USE SIGNAL ;
    PORT
      LAYER M4 ;
        RECT  0 28.944 0.192 28.968 ;
    END
  END o_d[150]
  PIN o_d[151]
    DIRECTION OUTPUT ;
    USE SIGNAL ;
    PORT
      LAYER M4 ;
        RECT  0 29.088 0.192 29.112 ;
    END
  END o_d[151]
  PIN o_d[152]
    DIRECTION OUTPUT ;
    USE SIGNAL ;
    PORT
      LAYER M4 ;
        RECT  0 29.232 0.192 29.256 ;
    END
  END o_d[152]
  PIN o_d[153]
    DIRECTION OUTPUT ;
    USE SIGNAL ;
    PORT
      LAYER M4 ;
        RECT  0 29.376 0.192 29.4 ;
    END
  END o_d[153]
  PIN o_d[154]
    DIRECTION OUTPUT ;
    USE SIGNAL ;
    PORT
      LAYER M4 ;
        RECT  0 29.52 0.192 29.544 ;
    END
  END o_d[154]
  PIN o_d[155]
    DIRECTION OUTPUT ;
    USE SIGNAL ;
    PORT
      LAYER M4 ;
        RECT  0 29.808 0.192 29.832 ;
    END
  END o_d[155]
  PIN o_d[156]
    DIRECTION OUTPUT ;
    USE SIGNAL ;
    PORT
      LAYER M4 ;
        RECT  0 29.952 0.192 29.976 ;
    END
  END o_d[156]
  PIN o_d[157]
    DIRECTION OUTPUT ;
    USE SIGNAL ;
    PORT
      LAYER M4 ;
        RECT  0 30.096 0.192 30.12 ;
    END
  END o_d[157]
  PIN o_d[158]
    DIRECTION OUTPUT ;
    USE SIGNAL ;
    PORT
      LAYER M4 ;
        RECT  0 30.24 0.192 30.264 ;
    END
  END o_d[158]
  PIN o_d[159]
    DIRECTION OUTPUT ;
    USE SIGNAL ;
    PORT
      LAYER M4 ;
        RECT  0 30.384 0.192 30.408 ;
    END
  END o_d[159]
  PIN o_d[15]
    DIRECTION OUTPUT ;
    USE SIGNAL ;
    PORT
      LAYER M4 ;
        RECT  0 6.768 0.192 6.792 ;
    END
  END o_d[15]
  PIN o_d[160]
    DIRECTION OUTPUT ;
    USE SIGNAL ;
    PORT
      LAYER M4 ;
        RECT  0 30.528 0.192 30.552 ;
    END
  END o_d[160]
  PIN o_d[161]
    DIRECTION OUTPUT ;
    USE SIGNAL ;
    PORT
      LAYER M4 ;
        RECT  0 30.672 0.192 30.696 ;
    END
  END o_d[161]
  PIN o_d[162]
    DIRECTION OUTPUT ;
    USE SIGNAL ;
    PORT
      LAYER M4 ;
        RECT  0 30.96 0.192 30.984 ;
    END
  END o_d[162]
  PIN o_d[163]
    DIRECTION OUTPUT ;
    USE SIGNAL ;
    PORT
      LAYER M4 ;
        RECT  0 31.104 0.192 31.128 ;
    END
  END o_d[163]
  PIN o_d[164]
    DIRECTION OUTPUT ;
    USE SIGNAL ;
    PORT
      LAYER M4 ;
        RECT  0 31.248 0.192 31.272 ;
    END
  END o_d[164]
  PIN o_d[165]
    DIRECTION OUTPUT ;
    USE SIGNAL ;
    PORT
      LAYER M4 ;
        RECT  0 31.392 0.192 31.416 ;
    END
  END o_d[165]
  PIN o_d[166]
    DIRECTION OUTPUT ;
    USE SIGNAL ;
    PORT
      LAYER M4 ;
        RECT  0 31.536 0.192 31.56 ;
    END
  END o_d[166]
  PIN o_d[167]
    DIRECTION OUTPUT ;
    USE SIGNAL ;
    PORT
      LAYER M4 ;
        RECT  0 31.68 0.192 31.704 ;
    END
  END o_d[167]
  PIN o_d[168]
    DIRECTION OUTPUT ;
    USE SIGNAL ;
    PORT
      LAYER M4 ;
        RECT  0 31.824 0.192 31.848 ;
    END
  END o_d[168]
  PIN o_d[169]
    DIRECTION OUTPUT ;
    USE SIGNAL ;
    PORT
      LAYER M4 ;
        RECT  0 31.968 0.192 31.992 ;
    END
  END o_d[169]
  PIN o_d[16]
    DIRECTION OUTPUT ;
    USE SIGNAL ;
    PORT
      LAYER M4 ;
        RECT  0 6.912 0.192 6.936 ;
    END
  END o_d[16]
  PIN o_d[170]
    DIRECTION OUTPUT ;
    USE SIGNAL ;
    PORT
      LAYER M4 ;
        RECT  0 32.256 0.192 32.28 ;
    END
  END o_d[170]
  PIN o_d[171]
    DIRECTION OUTPUT ;
    USE SIGNAL ;
    PORT
      LAYER M4 ;
        RECT  0 32.4 0.192 32.424 ;
    END
  END o_d[171]
  PIN o_d[172]
    DIRECTION OUTPUT ;
    USE SIGNAL ;
    PORT
      LAYER M4 ;
        RECT  0 32.544 0.192 32.568 ;
    END
  END o_d[172]
  PIN o_d[173]
    DIRECTION OUTPUT ;
    USE SIGNAL ;
    PORT
      LAYER M4 ;
        RECT  0 32.688 0.192 32.712 ;
    END
  END o_d[173]
  PIN o_d[174]
    DIRECTION OUTPUT ;
    USE SIGNAL ;
    PORT
      LAYER M4 ;
        RECT  0 32.832 0.192 32.856 ;
    END
  END o_d[174]
  PIN o_d[175]
    DIRECTION OUTPUT ;
    USE SIGNAL ;
    PORT
      LAYER M4 ;
        RECT  0 32.976 0.192 33 ;
    END
  END o_d[175]
  PIN o_d[176]
    DIRECTION OUTPUT ;
    USE SIGNAL ;
    PORT
      LAYER M4 ;
        RECT  0 33.12 0.192 33.144 ;
    END
  END o_d[176]
  PIN o_d[177]
    DIRECTION OUTPUT ;
    USE SIGNAL ;
    PORT
      LAYER M4 ;
        RECT  0 33.408 0.192 33.432 ;
    END
  END o_d[177]
  PIN o_d[178]
    DIRECTION OUTPUT ;
    USE SIGNAL ;
    PORT
      LAYER M4 ;
        RECT  0 33.552 0.192 33.576 ;
    END
  END o_d[178]
  PIN o_d[179]
    DIRECTION OUTPUT ;
    USE SIGNAL ;
    PORT
      LAYER M4 ;
        RECT  0 33.696 0.192 33.72 ;
    END
  END o_d[179]
  PIN o_d[17]
    DIRECTION OUTPUT ;
    USE SIGNAL ;
    PORT
      LAYER M4 ;
        RECT  0 7.056 0.192 7.08 ;
    END
  END o_d[17]
  PIN o_d[180]
    DIRECTION OUTPUT ;
    USE SIGNAL ;
    PORT
      LAYER M4 ;
        RECT  0 33.84 0.192 33.864 ;
    END
  END o_d[180]
  PIN o_d[181]
    DIRECTION OUTPUT ;
    USE SIGNAL ;
    PORT
      LAYER M4 ;
        RECT  0 33.984 0.192 34.008 ;
    END
  END o_d[181]
  PIN o_d[182]
    DIRECTION OUTPUT ;
    USE SIGNAL ;
    PORT
      LAYER M4 ;
        RECT  0 34.128 0.192 34.152 ;
    END
  END o_d[182]
  PIN o_d[183]
    DIRECTION OUTPUT ;
    USE SIGNAL ;
    PORT
      LAYER M4 ;
        RECT  0 34.272 0.192 34.296 ;
    END
  END o_d[183]
  PIN o_d[184]
    DIRECTION OUTPUT ;
    USE SIGNAL ;
    PORT
      LAYER M4 ;
        RECT  0 34.56 0.192 34.584 ;
    END
  END o_d[184]
  PIN o_d[185]
    DIRECTION OUTPUT ;
    USE SIGNAL ;
    PORT
      LAYER M4 ;
        RECT  0 34.704 0.192 34.728 ;
    END
  END o_d[185]
  PIN o_d[186]
    DIRECTION OUTPUT ;
    USE SIGNAL ;
    PORT
      LAYER M4 ;
        RECT  0 34.848 0.192 34.872 ;
    END
  END o_d[186]
  PIN o_d[187]
    DIRECTION OUTPUT ;
    USE SIGNAL ;
    PORT
      LAYER M4 ;
        RECT  0 34.992 0.192 35.016 ;
    END
  END o_d[187]
  PIN o_d[188]
    DIRECTION OUTPUT ;
    USE SIGNAL ;
    PORT
      LAYER M4 ;
        RECT  0 35.136 0.192 35.16 ;
    END
  END o_d[188]
  PIN o_d[189]
    DIRECTION OUTPUT ;
    USE SIGNAL ;
    PORT
      LAYER M4 ;
        RECT  0 35.28 0.192 35.304 ;
    END
  END o_d[189]
  PIN o_d[18]
    DIRECTION OUTPUT ;
    USE SIGNAL ;
    PORT
      LAYER M4 ;
        RECT  0 7.344 0.192 7.368 ;
    END
  END o_d[18]
  PIN o_d[190]
    DIRECTION OUTPUT ;
    USE SIGNAL ;
    PORT
      LAYER M4 ;
        RECT  0 35.424 0.192 35.448 ;
    END
  END o_d[190]
  PIN o_d[191]
    DIRECTION OUTPUT ;
    USE SIGNAL ;
    PORT
      LAYER M4 ;
        RECT  0 35.712 0.192 35.736 ;
    END
  END o_d[191]
  PIN o_d[192]
    DIRECTION OUTPUT ;
    USE SIGNAL ;
    PORT
      LAYER M4 ;
        RECT  0 35.856 0.192 35.88 ;
    END
  END o_d[192]
  PIN o_d[193]
    DIRECTION OUTPUT ;
    USE SIGNAL ;
    PORT
      LAYER M4 ;
        RECT  0 36 0.192 36.024 ;
    END
  END o_d[193]
  PIN o_d[194]
    DIRECTION OUTPUT ;
    USE SIGNAL ;
    PORT
      LAYER M4 ;
        RECT  0 36.144 0.192 36.168 ;
    END
  END o_d[194]
  PIN o_d[195]
    DIRECTION OUTPUT ;
    USE SIGNAL ;
    PORT
      LAYER M4 ;
        RECT  0 36.288 0.192 36.312 ;
    END
  END o_d[195]
  PIN o_d[196]
    DIRECTION OUTPUT ;
    USE SIGNAL ;
    PORT
      LAYER M4 ;
        RECT  0 36.432 0.192 36.456 ;
    END
  END o_d[196]
  PIN o_d[197]
    DIRECTION OUTPUT ;
    USE SIGNAL ;
    PORT
      LAYER M4 ;
        RECT  0 36.576 0.192 36.6 ;
    END
  END o_d[197]
  PIN o_d[198]
    DIRECTION OUTPUT ;
    USE SIGNAL ;
    PORT
      LAYER M4 ;
        RECT  0 36.72 0.192 36.744 ;
    END
  END o_d[198]
  PIN o_d[199]
    DIRECTION OUTPUT ;
    USE SIGNAL ;
    PORT
      LAYER M4 ;
        RECT  0 37.008 0.192 37.032 ;
    END
  END o_d[199]
  PIN o_d[19]
    DIRECTION OUTPUT ;
    USE SIGNAL ;
    PORT
      LAYER M4 ;
        RECT  0 7.488 0.192 7.512 ;
    END
  END o_d[19]
  PIN o_d[1]
    DIRECTION OUTPUT ;
    USE SIGNAL ;
    PORT
      LAYER M4 ;
        RECT  0 4.464 0.192 4.488 ;
    END
  END o_d[1]
  PIN o_d[200]
    DIRECTION OUTPUT ;
    USE SIGNAL ;
    PORT
      LAYER M4 ;
        RECT  0 37.152 0.192 37.176 ;
    END
  END o_d[200]
  PIN o_d[201]
    DIRECTION OUTPUT ;
    USE SIGNAL ;
    PORT
      LAYER M4 ;
        RECT  0 37.296 0.192 37.32 ;
    END
  END o_d[201]
  PIN o_d[202]
    DIRECTION OUTPUT ;
    USE SIGNAL ;
    PORT
      LAYER M4 ;
        RECT  0 37.44 0.192 37.464 ;
    END
  END o_d[202]
  PIN o_d[203]
    DIRECTION OUTPUT ;
    USE SIGNAL ;
    PORT
      LAYER M4 ;
        RECT  0 37.584 0.192 37.608 ;
    END
  END o_d[203]
  PIN o_d[204]
    DIRECTION OUTPUT ;
    USE SIGNAL ;
    PORT
      LAYER M4 ;
        RECT  0 37.728 0.192 37.752 ;
    END
  END o_d[204]
  PIN o_d[205]
    DIRECTION OUTPUT ;
    USE SIGNAL ;
    PORT
      LAYER M4 ;
        RECT  0 37.872 0.192 37.896 ;
    END
  END o_d[205]
  PIN o_d[206]
    DIRECTION OUTPUT ;
    USE SIGNAL ;
    PORT
      LAYER M4 ;
        RECT  0 38.16 0.192 38.184 ;
    END
  END o_d[206]
  PIN o_d[207]
    DIRECTION OUTPUT ;
    USE SIGNAL ;
    PORT
      LAYER M4 ;
        RECT  0 38.304 0.192 38.328 ;
    END
  END o_d[207]
  PIN o_d[208]
    DIRECTION OUTPUT ;
    USE SIGNAL ;
    PORT
      LAYER M4 ;
        RECT  0 38.448 0.192 38.472 ;
    END
  END o_d[208]
  PIN o_d[209]
    DIRECTION OUTPUT ;
    USE SIGNAL ;
    PORT
      LAYER M4 ;
        RECT  0 38.592 0.192 38.616 ;
    END
  END o_d[209]
  PIN o_d[20]
    DIRECTION OUTPUT ;
    USE SIGNAL ;
    PORT
      LAYER M4 ;
        RECT  0 7.632 0.192 7.656 ;
    END
  END o_d[20]
  PIN o_d[210]
    DIRECTION OUTPUT ;
    USE SIGNAL ;
    PORT
      LAYER M4 ;
        RECT  0 38.736 0.192 38.76 ;
    END
  END o_d[210]
  PIN o_d[211]
    DIRECTION OUTPUT ;
    USE SIGNAL ;
    PORT
      LAYER M4 ;
        RECT  0 38.88 0.192 38.904 ;
    END
  END o_d[211]
  PIN o_d[212]
    DIRECTION OUTPUT ;
    USE SIGNAL ;
    PORT
      LAYER M4 ;
        RECT  0 39.024 0.192 39.048 ;
    END
  END o_d[212]
  PIN o_d[213]
    DIRECTION OUTPUT ;
    USE SIGNAL ;
    PORT
      LAYER M4 ;
        RECT  0 39.312 0.192 39.336 ;
    END
  END o_d[213]
  PIN o_d[214]
    DIRECTION OUTPUT ;
    USE SIGNAL ;
    PORT
      LAYER M4 ;
        RECT  0 39.456 0.192 39.48 ;
    END
  END o_d[214]
  PIN o_d[215]
    DIRECTION OUTPUT ;
    USE SIGNAL ;
    PORT
      LAYER M4 ;
        RECT  0 39.6 0.192 39.624 ;
    END
  END o_d[215]
  PIN o_d[216]
    DIRECTION OUTPUT ;
    USE SIGNAL ;
    PORT
      LAYER M4 ;
        RECT  0 39.744 0.192 39.768 ;
    END
  END o_d[216]
  PIN o_d[217]
    DIRECTION OUTPUT ;
    USE SIGNAL ;
    PORT
      LAYER M4 ;
        RECT  0 39.888 0.192 39.912 ;
    END
  END o_d[217]
  PIN o_d[218]
    DIRECTION OUTPUT ;
    USE SIGNAL ;
    PORT
      LAYER M4 ;
        RECT  0 40.032 0.192 40.056 ;
    END
  END o_d[218]
  PIN o_d[219]
    DIRECTION OUTPUT ;
    USE SIGNAL ;
    PORT
      LAYER M4 ;
        RECT  0 40.176 0.192 40.2 ;
    END
  END o_d[219]
  PIN o_d[21]
    DIRECTION OUTPUT ;
    USE SIGNAL ;
    PORT
      LAYER M4 ;
        RECT  0 7.776 0.192 7.8 ;
    END
  END o_d[21]
  PIN o_d[220]
    DIRECTION OUTPUT ;
    USE SIGNAL ;
    PORT
      LAYER M4 ;
        RECT  0 40.464 0.192 40.488 ;
    END
  END o_d[220]
  PIN o_d[221]
    DIRECTION OUTPUT ;
    USE SIGNAL ;
    PORT
      LAYER M4 ;
        RECT  0 40.608 0.192 40.632 ;
    END
  END o_d[221]
  PIN o_d[222]
    DIRECTION OUTPUT ;
    USE SIGNAL ;
    PORT
      LAYER M4 ;
        RECT  0 40.752 0.192 40.776 ;
    END
  END o_d[222]
  PIN o_d[223]
    DIRECTION OUTPUT ;
    USE SIGNAL ;
    PORT
      LAYER M4 ;
        RECT  0 40.896 0.192 40.92 ;
    END
  END o_d[223]
  PIN o_d[224]
    DIRECTION OUTPUT ;
    USE SIGNAL ;
    PORT
      LAYER M4 ;
        RECT  0 41.04 0.192 41.064 ;
    END
  END o_d[224]
  PIN o_d[225]
    DIRECTION OUTPUT ;
    USE SIGNAL ;
    PORT
      LAYER M4 ;
        RECT  0 41.184 0.192 41.208 ;
    END
  END o_d[225]
  PIN o_d[226]
    DIRECTION OUTPUT ;
    USE SIGNAL ;
    PORT
      LAYER M4 ;
        RECT  0 41.328 0.192 41.352 ;
    END
  END o_d[226]
  PIN o_d[227]
    DIRECTION OUTPUT ;
    USE SIGNAL ;
    PORT
      LAYER M4 ;
        RECT  0 41.616 0.192 41.64 ;
    END
  END o_d[227]
  PIN o_d[228]
    DIRECTION OUTPUT ;
    USE SIGNAL ;
    PORT
      LAYER M4 ;
        RECT  0 41.76 0.192 41.784 ;
    END
  END o_d[228]
  PIN o_d[229]
    DIRECTION OUTPUT ;
    USE SIGNAL ;
    PORT
      LAYER M4 ;
        RECT  0 41.904 0.192 41.928 ;
    END
  END o_d[229]
  PIN o_d[22]
    DIRECTION OUTPUT ;
    USE SIGNAL ;
    PORT
      LAYER M4 ;
        RECT  0 7.92 0.192 7.944 ;
    END
  END o_d[22]
  PIN o_d[230]
    DIRECTION OUTPUT ;
    USE SIGNAL ;
    PORT
      LAYER M4 ;
        RECT  0 42.048 0.192 42.072 ;
    END
  END o_d[230]
  PIN o_d[231]
    DIRECTION OUTPUT ;
    USE SIGNAL ;
    PORT
      LAYER M4 ;
        RECT  0 42.192 0.192 42.216 ;
    END
  END o_d[231]
  PIN o_d[232]
    DIRECTION OUTPUT ;
    USE SIGNAL ;
    PORT
      LAYER M4 ;
        RECT  0 42.336 0.192 42.36 ;
    END
  END o_d[232]
  PIN o_d[233]
    DIRECTION OUTPUT ;
    USE SIGNAL ;
    PORT
      LAYER M4 ;
        RECT  0 42.48 0.192 42.504 ;
    END
  END o_d[233]
  PIN o_d[234]
    DIRECTION OUTPUT ;
    USE SIGNAL ;
    PORT
      LAYER M4 ;
        RECT  0 42.624 0.192 42.648 ;
    END
  END o_d[234]
  PIN o_d[235]
    DIRECTION OUTPUT ;
    USE SIGNAL ;
    PORT
      LAYER M4 ;
        RECT  0 42.912 0.192 42.936 ;
    END
  END o_d[235]
  PIN o_d[236]
    DIRECTION OUTPUT ;
    USE SIGNAL ;
    PORT
      LAYER M4 ;
        RECT  0 43.056 0.192 43.08 ;
    END
  END o_d[236]
  PIN o_d[237]
    DIRECTION OUTPUT ;
    USE SIGNAL ;
    PORT
      LAYER M4 ;
        RECT  0 43.2 0.192 43.224 ;
    END
  END o_d[237]
  PIN o_d[238]
    DIRECTION OUTPUT ;
    USE SIGNAL ;
    PORT
      LAYER M4 ;
        RECT  0 43.344 0.192 43.368 ;
    END
  END o_d[238]
  PIN o_d[239]
    DIRECTION OUTPUT ;
    USE SIGNAL ;
    PORT
      LAYER M4 ;
        RECT  0 43.488 0.192 43.512 ;
    END
  END o_d[239]
  PIN o_d[23]
    DIRECTION OUTPUT ;
    USE SIGNAL ;
    PORT
      LAYER M4 ;
        RECT  0 8.064 0.192 8.088 ;
    END
  END o_d[23]
  PIN o_d[240]
    DIRECTION OUTPUT ;
    USE SIGNAL ;
    PORT
      LAYER M4 ;
        RECT  0 43.632 0.192 43.656 ;
    END
  END o_d[240]
  PIN o_d[241]
    DIRECTION OUTPUT ;
    USE SIGNAL ;
    PORT
      LAYER M4 ;
        RECT  0 43.776 0.192 43.8 ;
    END
  END o_d[241]
  PIN o_d[242]
    DIRECTION OUTPUT ;
    USE SIGNAL ;
    PORT
      LAYER M4 ;
        RECT  0 44.064 0.192 44.088 ;
    END
  END o_d[242]
  PIN o_d[243]
    DIRECTION OUTPUT ;
    USE SIGNAL ;
    PORT
      LAYER M4 ;
        RECT  0 44.208 0.192 44.232 ;
    END
  END o_d[243]
  PIN o_d[244]
    DIRECTION OUTPUT ;
    USE SIGNAL ;
    PORT
      LAYER M4 ;
        RECT  0 44.352 0.192 44.376 ;
    END
  END o_d[244]
  PIN o_d[245]
    DIRECTION OUTPUT ;
    USE SIGNAL ;
    PORT
      LAYER M4 ;
        RECT  0 44.496 0.192 44.52 ;
    END
  END o_d[245]
  PIN o_d[246]
    DIRECTION OUTPUT ;
    USE SIGNAL ;
    PORT
      LAYER M4 ;
        RECT  0 44.64 0.192 44.664 ;
    END
  END o_d[246]
  PIN o_d[247]
    DIRECTION OUTPUT ;
    USE SIGNAL ;
    PORT
      LAYER M4 ;
        RECT  0 44.784 0.192 44.808 ;
    END
  END o_d[247]
  PIN o_d[248]
    DIRECTION OUTPUT ;
    USE SIGNAL ;
    PORT
      LAYER M4 ;
        RECT  0 44.928 0.192 44.952 ;
    END
  END o_d[248]
  PIN o_d[249]
    DIRECTION OUTPUT ;
    USE SIGNAL ;
    PORT
      LAYER M4 ;
        RECT  0 45.216 0.192 45.24 ;
    END
  END o_d[249]
  PIN o_d[24]
    DIRECTION OUTPUT ;
    USE SIGNAL ;
    PORT
      LAYER M4 ;
        RECT  0 8.208 0.192 8.232 ;
    END
  END o_d[24]
  PIN o_d[250]
    DIRECTION OUTPUT ;
    USE SIGNAL ;
    PORT
      LAYER M4 ;
        RECT  0 45.36 0.192 45.384 ;
    END
  END o_d[250]
  PIN o_d[251]
    DIRECTION OUTPUT ;
    USE SIGNAL ;
    PORT
      LAYER M4 ;
        RECT  0 45.504 0.192 45.528 ;
    END
  END o_d[251]
  PIN o_d[252]
    DIRECTION OUTPUT ;
    USE SIGNAL ;
    PORT
      LAYER M4 ;
        RECT  0 45.648 0.192 45.672 ;
    END
  END o_d[252]
  PIN o_d[253]
    DIRECTION OUTPUT ;
    USE SIGNAL ;
    PORT
      LAYER M4 ;
        RECT  0 45.792 0.192 45.816 ;
    END
  END o_d[253]
  PIN o_d[254]
    DIRECTION OUTPUT ;
    USE SIGNAL ;
    PORT
      LAYER M4 ;
        RECT  0 45.936 0.192 45.96 ;
    END
  END o_d[254]
  PIN o_d[255]
    DIRECTION OUTPUT ;
    USE SIGNAL ;
    PORT
      LAYER M4 ;
        RECT  0 46.08 0.192 46.104 ;
    END
  END o_d[255]
  PIN o_d[256]
    DIRECTION OUTPUT ;
    USE SIGNAL ;
    PORT
      LAYER M4 ;
        RECT  0 46.368 0.192 46.392 ;
    END
  END o_d[256]
  PIN o_d[257]
    DIRECTION OUTPUT ;
    USE SIGNAL ;
    PORT
      LAYER M4 ;
        RECT  0 46.512 0.192 46.536 ;
    END
  END o_d[257]
  PIN o_d[258]
    DIRECTION OUTPUT ;
    USE SIGNAL ;
    PORT
      LAYER M4 ;
        RECT  0 46.656 0.192 46.68 ;
    END
  END o_d[258]
  PIN o_d[259]
    DIRECTION OUTPUT ;
    USE SIGNAL ;
    PORT
      LAYER M4 ;
        RECT  0 46.8 0.192 46.824 ;
    END
  END o_d[259]
  PIN o_d[25]
    DIRECTION OUTPUT ;
    USE SIGNAL ;
    PORT
      LAYER M4 ;
        RECT  0 8.496 0.192 8.52 ;
    END
  END o_d[25]
  PIN o_d[260]
    DIRECTION OUTPUT ;
    USE SIGNAL ;
    PORT
      LAYER M4 ;
        RECT  0 46.944 0.192 46.968 ;
    END
  END o_d[260]
  PIN o_d[261]
    DIRECTION OUTPUT ;
    USE SIGNAL ;
    PORT
      LAYER M4 ;
        RECT  0 47.088 0.192 47.112 ;
    END
  END o_d[261]
  PIN o_d[262]
    DIRECTION OUTPUT ;
    USE SIGNAL ;
    PORT
      LAYER M4 ;
        RECT  0 47.232 0.192 47.256 ;
    END
  END o_d[262]
  PIN o_d[263]
    DIRECTION OUTPUT ;
    USE SIGNAL ;
    PORT
      LAYER M4 ;
        RECT  0 47.52 0.192 47.544 ;
    END
  END o_d[263]
  PIN o_d[264]
    DIRECTION OUTPUT ;
    USE SIGNAL ;
    PORT
      LAYER M4 ;
        RECT  0 47.664 0.192 47.688 ;
    END
  END o_d[264]
  PIN o_d[265]
    DIRECTION OUTPUT ;
    USE SIGNAL ;
    PORT
      LAYER M4 ;
        RECT  0 47.808 0.192 47.832 ;
    END
  END o_d[265]
  PIN o_d[266]
    DIRECTION OUTPUT ;
    USE SIGNAL ;
    PORT
      LAYER M4 ;
        RECT  0 47.952 0.192 47.976 ;
    END
  END o_d[266]
  PIN o_d[267]
    DIRECTION OUTPUT ;
    USE SIGNAL ;
    PORT
      LAYER M4 ;
        RECT  0 48.096 0.192 48.12 ;
    END
  END o_d[267]
  PIN o_d[268]
    DIRECTION OUTPUT ;
    USE SIGNAL ;
    PORT
      LAYER M4 ;
        RECT  0 48.24 0.192 48.264 ;
    END
  END o_d[268]
  PIN o_d[269]
    DIRECTION OUTPUT ;
    USE SIGNAL ;
    PORT
      LAYER M4 ;
        RECT  0 48.384 0.192 48.408 ;
    END
  END o_d[269]
  PIN o_d[26]
    DIRECTION OUTPUT ;
    USE SIGNAL ;
    PORT
      LAYER M4 ;
        RECT  0 8.64 0.192 8.664 ;
    END
  END o_d[26]
  PIN o_d[270]
    DIRECTION OUTPUT ;
    USE SIGNAL ;
    PORT
      LAYER M4 ;
        RECT  0 48.528 0.192 48.552 ;
    END
  END o_d[270]
  PIN o_d[271]
    DIRECTION OUTPUT ;
    USE SIGNAL ;
    PORT
      LAYER M4 ;
        RECT  0 48.816 0.192 48.84 ;
    END
  END o_d[271]
  PIN o_d[272]
    DIRECTION OUTPUT ;
    USE SIGNAL ;
    PORT
      LAYER M4 ;
        RECT  0 48.96 0.192 48.984 ;
    END
  END o_d[272]
  PIN o_d[273]
    DIRECTION OUTPUT ;
    USE SIGNAL ;
    PORT
      LAYER M4 ;
        RECT  0 49.104 0.192 49.128 ;
    END
  END o_d[273]
  PIN o_d[274]
    DIRECTION OUTPUT ;
    USE SIGNAL ;
    PORT
      LAYER M4 ;
        RECT  0 49.248 0.192 49.272 ;
    END
  END o_d[274]
  PIN o_d[275]
    DIRECTION OUTPUT ;
    USE SIGNAL ;
    PORT
      LAYER M4 ;
        RECT  0 49.392 0.192 49.416 ;
    END
  END o_d[275]
  PIN o_d[276]
    DIRECTION OUTPUT ;
    USE SIGNAL ;
    PORT
      LAYER M4 ;
        RECT  0 49.536 0.192 49.56 ;
    END
  END o_d[276]
  PIN o_d[277]
    DIRECTION OUTPUT ;
    USE SIGNAL ;
    PORT
      LAYER M4 ;
        RECT  0 49.68 0.192 49.704 ;
    END
  END o_d[277]
  PIN o_d[278]
    DIRECTION OUTPUT ;
    USE SIGNAL ;
    PORT
      LAYER M4 ;
        RECT  0 49.968 0.192 49.992 ;
    END
  END o_d[278]
  PIN o_d[279]
    DIRECTION OUTPUT ;
    USE SIGNAL ;
    PORT
      LAYER M4 ;
        RECT  0 50.112 0.192 50.136 ;
    END
  END o_d[279]
  PIN o_d[27]
    DIRECTION OUTPUT ;
    USE SIGNAL ;
    PORT
      LAYER M4 ;
        RECT  0 8.784 0.192 8.808 ;
    END
  END o_d[27]
  PIN o_d[280]
    DIRECTION OUTPUT ;
    USE SIGNAL ;
    PORT
      LAYER M4 ;
        RECT  0 50.256 0.192 50.28 ;
    END
  END o_d[280]
  PIN o_d[281]
    DIRECTION OUTPUT ;
    USE SIGNAL ;
    PORT
      LAYER M4 ;
        RECT  0 50.4 0.192 50.424 ;
    END
  END o_d[281]
  PIN o_d[282]
    DIRECTION OUTPUT ;
    USE SIGNAL ;
    PORT
      LAYER M4 ;
        RECT  0 50.544 0.192 50.568 ;
    END
  END o_d[282]
  PIN o_d[283]
    DIRECTION OUTPUT ;
    USE SIGNAL ;
    PORT
      LAYER M4 ;
        RECT  0 50.688 0.192 50.712 ;
    END
  END o_d[283]
  PIN o_d[284]
    DIRECTION OUTPUT ;
    USE SIGNAL ;
    PORT
      LAYER M4 ;
        RECT  0 50.832 0.192 50.856 ;
    END
  END o_d[284]
  PIN o_d[285]
    DIRECTION OUTPUT ;
    USE SIGNAL ;
    PORT
      LAYER M4 ;
        RECT  0 51.12 0.192 51.144 ;
    END
  END o_d[285]
  PIN o_d[286]
    DIRECTION OUTPUT ;
    USE SIGNAL ;
    PORT
      LAYER M4 ;
        RECT  0 51.264 0.192 51.288 ;
    END
  END o_d[286]
  PIN o_d[287]
    DIRECTION OUTPUT ;
    USE SIGNAL ;
    PORT
      LAYER M4 ;
        RECT  0 51.408 0.192 51.432 ;
    END
  END o_d[287]
  PIN o_d[288]
    DIRECTION OUTPUT ;
    USE SIGNAL ;
    PORT
      LAYER M4 ;
        RECT  0 51.552 0.192 51.576 ;
    END
  END o_d[288]
  PIN o_d[289]
    DIRECTION OUTPUT ;
    USE SIGNAL ;
    PORT
      LAYER M4 ;
        RECT  0 51.696 0.192 51.72 ;
    END
  END o_d[289]
  PIN o_d[28]
    DIRECTION OUTPUT ;
    USE SIGNAL ;
    PORT
      LAYER M4 ;
        RECT  0 8.928 0.192 8.952 ;
    END
  END o_d[28]
  PIN o_d[290]
    DIRECTION OUTPUT ;
    USE SIGNAL ;
    PORT
      LAYER M4 ;
        RECT  0 51.84 0.192 51.864 ;
    END
  END o_d[290]
  PIN o_d[291]
    DIRECTION OUTPUT ;
    USE SIGNAL ;
    PORT
      LAYER M4 ;
        RECT  0 51.984 0.192 52.008 ;
    END
  END o_d[291]
  PIN o_d[292]
    DIRECTION OUTPUT ;
    USE SIGNAL ;
    PORT
      LAYER M4 ;
        RECT  0 52.272 0.192 52.296 ;
    END
  END o_d[292]
  PIN o_d[293]
    DIRECTION OUTPUT ;
    USE SIGNAL ;
    PORT
      LAYER M4 ;
        RECT  0 52.416 0.192 52.44 ;
    END
  END o_d[293]
  PIN o_d[294]
    DIRECTION OUTPUT ;
    USE SIGNAL ;
    PORT
      LAYER M4 ;
        RECT  0 52.56 0.192 52.584 ;
    END
  END o_d[294]
  PIN o_d[295]
    DIRECTION OUTPUT ;
    USE SIGNAL ;
    PORT
      LAYER M4 ;
        RECT  0 52.704 0.192 52.728 ;
    END
  END o_d[295]
  PIN o_d[296]
    DIRECTION OUTPUT ;
    USE SIGNAL ;
    PORT
      LAYER M4 ;
        RECT  0 52.848 0.192 52.872 ;
    END
  END o_d[296]
  PIN o_d[297]
    DIRECTION OUTPUT ;
    USE SIGNAL ;
    PORT
      LAYER M4 ;
        RECT  0 52.992 0.192 53.016 ;
    END
  END o_d[297]
  PIN o_d[298]
    DIRECTION OUTPUT ;
    USE SIGNAL ;
    PORT
      LAYER M4 ;
        RECT  0 53.136 0.192 53.16 ;
    END
  END o_d[298]
  PIN o_d[299]
    DIRECTION OUTPUT ;
    USE SIGNAL ;
    PORT
      LAYER M4 ;
        RECT  0 53.28 0.192 53.304 ;
    END
  END o_d[299]
  PIN o_d[29]
    DIRECTION OUTPUT ;
    USE SIGNAL ;
    PORT
      LAYER M4 ;
        RECT  0 9.072 0.192 9.096 ;
    END
  END o_d[29]
  PIN o_d[2]
    DIRECTION OUTPUT ;
    USE SIGNAL ;
    PORT
      LAYER M4 ;
        RECT  0 4.608 0.192 4.632 ;
    END
  END o_d[2]
  PIN o_d[300]
    DIRECTION OUTPUT ;
    USE SIGNAL ;
    PORT
      LAYER M4 ;
        RECT  0 53.568 0.192 53.592 ;
    END
  END o_d[300]
  PIN o_d[301]
    DIRECTION OUTPUT ;
    USE SIGNAL ;
    PORT
      LAYER M4 ;
        RECT  0 53.712 0.192 53.736 ;
    END
  END o_d[301]
  PIN o_d[302]
    DIRECTION OUTPUT ;
    USE SIGNAL ;
    PORT
      LAYER M4 ;
        RECT  0 53.856 0.192 53.88 ;
    END
  END o_d[302]
  PIN o_d[303]
    DIRECTION OUTPUT ;
    USE SIGNAL ;
    PORT
      LAYER M4 ;
        RECT  0 54 0.192 54.024 ;
    END
  END o_d[303]
  PIN o_d[304]
    DIRECTION OUTPUT ;
    USE SIGNAL ;
    PORT
      LAYER M4 ;
        RECT  0 54.144 0.192 54.168 ;
    END
  END o_d[304]
  PIN o_d[305]
    DIRECTION OUTPUT ;
    USE SIGNAL ;
    PORT
      LAYER M4 ;
        RECT  0 54.288 0.192 54.312 ;
    END
  END o_d[305]
  PIN o_d[306]
    DIRECTION OUTPUT ;
    USE SIGNAL ;
    PORT
      LAYER M4 ;
        RECT  0 54.432 0.192 54.456 ;
    END
  END o_d[306]
  PIN o_d[307]
    DIRECTION OUTPUT ;
    USE SIGNAL ;
    PORT
      LAYER M4 ;
        RECT  0 54.72 0.192 54.744 ;
    END
  END o_d[307]
  PIN o_d[308]
    DIRECTION OUTPUT ;
    USE SIGNAL ;
    PORT
      LAYER M4 ;
        RECT  0 54.864 0.192 54.888 ;
    END
  END o_d[308]
  PIN o_d[309]
    DIRECTION OUTPUT ;
    USE SIGNAL ;
    PORT
      LAYER M4 ;
        RECT  0 55.008 0.192 55.032 ;
    END
  END o_d[309]
  PIN o_d[30]
    DIRECTION OUTPUT ;
    USE SIGNAL ;
    PORT
      LAYER M4 ;
        RECT  0 9.216 0.192 9.24 ;
    END
  END o_d[30]
  PIN o_d[310]
    DIRECTION OUTPUT ;
    USE SIGNAL ;
    PORT
      LAYER M4 ;
        RECT  0 55.152 0.192 55.176 ;
    END
  END o_d[310]
  PIN o_d[311]
    DIRECTION OUTPUT ;
    USE SIGNAL ;
    PORT
      LAYER M4 ;
        RECT  0 55.296 0.192 55.32 ;
    END
  END o_d[311]
  PIN o_d[312]
    DIRECTION OUTPUT ;
    USE SIGNAL ;
    PORT
      LAYER M4 ;
        RECT  0 55.44 0.192 55.464 ;
    END
  END o_d[312]
  PIN o_d[313]
    DIRECTION OUTPUT ;
    USE SIGNAL ;
    PORT
      LAYER M4 ;
        RECT  0 55.584 0.192 55.608 ;
    END
  END o_d[313]
  PIN o_d[314]
    DIRECTION OUTPUT ;
    USE SIGNAL ;
    PORT
      LAYER M4 ;
        RECT  0 55.872 0.192 55.896 ;
    END
  END o_d[314]
  PIN o_d[315]
    DIRECTION OUTPUT ;
    USE SIGNAL ;
    PORT
      LAYER M4 ;
        RECT  0 56.016 0.192 56.04 ;
    END
  END o_d[315]
  PIN o_d[316]
    DIRECTION OUTPUT ;
    USE SIGNAL ;
    PORT
      LAYER M4 ;
        RECT  0 56.16 0.192 56.184 ;
    END
  END o_d[316]
  PIN o_d[317]
    DIRECTION OUTPUT ;
    USE SIGNAL ;
    PORT
      LAYER M4 ;
        RECT  0 56.304 0.192 56.328 ;
    END
  END o_d[317]
  PIN o_d[318]
    DIRECTION OUTPUT ;
    USE SIGNAL ;
    PORT
      LAYER M4 ;
        RECT  0 56.448 0.192 56.472 ;
    END
  END o_d[318]
  PIN o_d[319]
    DIRECTION OUTPUT ;
    USE SIGNAL ;
    PORT
      LAYER M4 ;
        RECT  0 56.592 0.192 56.616 ;
    END
  END o_d[319]
  PIN o_d[31]
    DIRECTION OUTPUT ;
    USE SIGNAL ;
    PORT
      LAYER M4 ;
        RECT  0 9.36 0.192 9.384 ;
    END
  END o_d[31]
  PIN o_d[320]
    DIRECTION OUTPUT ;
    USE SIGNAL ;
    PORT
      LAYER M4 ;
        RECT  0 56.736 0.192 56.76 ;
    END
  END o_d[320]
  PIN o_d[321]
    DIRECTION OUTPUT ;
    USE SIGNAL ;
    PORT
      LAYER M4 ;
        RECT  0 57.024 0.192 57.048 ;
    END
  END o_d[321]
  PIN o_d[322]
    DIRECTION OUTPUT ;
    USE SIGNAL ;
    PORT
      LAYER M4 ;
        RECT  0 57.168 0.192 57.192 ;
    END
  END o_d[322]
  PIN o_d[323]
    DIRECTION OUTPUT ;
    USE SIGNAL ;
    PORT
      LAYER M4 ;
        RECT  0 57.312 0.192 57.336 ;
    END
  END o_d[323]
  PIN o_d[324]
    DIRECTION OUTPUT ;
    USE SIGNAL ;
    PORT
      LAYER M4 ;
        RECT  0 57.456 0.192 57.48 ;
    END
  END o_d[324]
  PIN o_d[325]
    DIRECTION OUTPUT ;
    USE SIGNAL ;
    PORT
      LAYER M4 ;
        RECT  0 57.6 0.192 57.624 ;
    END
  END o_d[325]
  PIN o_d[326]
    DIRECTION OUTPUT ;
    USE SIGNAL ;
    PORT
      LAYER M4 ;
        RECT  0 57.744 0.192 57.768 ;
    END
  END o_d[326]
  PIN o_d[327]
    DIRECTION OUTPUT ;
    USE SIGNAL ;
    PORT
      LAYER M4 ;
        RECT  0 57.888 0.192 57.912 ;
    END
  END o_d[327]
  PIN o_d[328]
    DIRECTION OUTPUT ;
    USE SIGNAL ;
    PORT
      LAYER M4 ;
        RECT  0 58.176 0.192 58.2 ;
    END
  END o_d[328]
  PIN o_d[329]
    DIRECTION OUTPUT ;
    USE SIGNAL ;
    PORT
      LAYER M4 ;
        RECT  0 58.32 0.192 58.344 ;
    END
  END o_d[329]
  PIN o_d[32]
    DIRECTION OUTPUT ;
    USE SIGNAL ;
    PORT
      LAYER M4 ;
        RECT  0 9.648 0.192 9.672 ;
    END
  END o_d[32]
  PIN o_d[330]
    DIRECTION OUTPUT ;
    USE SIGNAL ;
    PORT
      LAYER M4 ;
        RECT  0 58.464 0.192 58.488 ;
    END
  END o_d[330]
  PIN o_d[331]
    DIRECTION OUTPUT ;
    USE SIGNAL ;
    PORT
      LAYER M4 ;
        RECT  0 58.608 0.192 58.632 ;
    END
  END o_d[331]
  PIN o_d[332]
    DIRECTION OUTPUT ;
    USE SIGNAL ;
    PORT
      LAYER M4 ;
        RECT  0 58.752 0.192 58.776 ;
    END
  END o_d[332]
  PIN o_d[333]
    DIRECTION OUTPUT ;
    USE SIGNAL ;
    PORT
      LAYER M4 ;
        RECT  0 58.896 0.192 58.92 ;
    END
  END o_d[333]
  PIN o_d[334]
    DIRECTION OUTPUT ;
    USE SIGNAL ;
    PORT
      LAYER M4 ;
        RECT  0 59.04 0.192 59.064 ;
    END
  END o_d[334]
  PIN o_d[335]
    DIRECTION OUTPUT ;
    USE SIGNAL ;
    PORT
      LAYER M4 ;
        RECT  0 59.184 0.192 59.208 ;
    END
  END o_d[335]
  PIN o_d[336]
    DIRECTION OUTPUT ;
    USE SIGNAL ;
    PORT
      LAYER M4 ;
        RECT  0 59.472 0.192 59.496 ;
    END
  END o_d[336]
  PIN o_d[337]
    DIRECTION OUTPUT ;
    USE SIGNAL ;
    PORT
      LAYER M4 ;
        RECT  0 59.616 0.192 59.64 ;
    END
  END o_d[337]
  PIN o_d[338]
    DIRECTION OUTPUT ;
    USE SIGNAL ;
    PORT
      LAYER M4 ;
        RECT  0 59.76 0.192 59.784 ;
    END
  END o_d[338]
  PIN o_d[339]
    DIRECTION OUTPUT ;
    USE SIGNAL ;
    PORT
      LAYER M4 ;
        RECT  0 59.904 0.192 59.928 ;
    END
  END o_d[339]
  PIN o_d[33]
    DIRECTION OUTPUT ;
    USE SIGNAL ;
    PORT
      LAYER M4 ;
        RECT  0 9.792 0.192 9.816 ;
    END
  END o_d[33]
  PIN o_d[340]
    DIRECTION OUTPUT ;
    USE SIGNAL ;
    PORT
      LAYER M4 ;
        RECT  0 60.048 0.192 60.072 ;
    END
  END o_d[340]
  PIN o_d[341]
    DIRECTION OUTPUT ;
    USE SIGNAL ;
    PORT
      LAYER M4 ;
        RECT  0 60.192 0.192 60.216 ;
    END
  END o_d[341]
  PIN o_d[342]
    DIRECTION OUTPUT ;
    USE SIGNAL ;
    PORT
      LAYER M4 ;
        RECT  0 60.336 0.192 60.36 ;
    END
  END o_d[342]
  PIN o_d[343]
    DIRECTION OUTPUT ;
    USE SIGNAL ;
    PORT
      LAYER M4 ;
        RECT  0 60.624 0.192 60.648 ;
    END
  END o_d[343]
  PIN o_d[344]
    DIRECTION OUTPUT ;
    USE SIGNAL ;
    PORT
      LAYER M4 ;
        RECT  0 60.768 0.192 60.792 ;
    END
  END o_d[344]
  PIN o_d[345]
    DIRECTION OUTPUT ;
    USE SIGNAL ;
    PORT
      LAYER M4 ;
        RECT  0 60.912 0.192 60.936 ;
    END
  END o_d[345]
  PIN o_d[346]
    DIRECTION OUTPUT ;
    USE SIGNAL ;
    PORT
      LAYER M4 ;
        RECT  0 61.056 0.192 61.08 ;
    END
  END o_d[346]
  PIN o_d[347]
    DIRECTION OUTPUT ;
    USE SIGNAL ;
    PORT
      LAYER M4 ;
        RECT  0 61.2 0.192 61.224 ;
    END
  END o_d[347]
  PIN o_d[348]
    DIRECTION OUTPUT ;
    USE SIGNAL ;
    PORT
      LAYER M4 ;
        RECT  0 61.344 0.192 61.368 ;
    END
  END o_d[348]
  PIN o_d[349]
    DIRECTION OUTPUT ;
    USE SIGNAL ;
    PORT
      LAYER M4 ;
        RECT  0 61.488 0.192 61.512 ;
    END
  END o_d[349]
  PIN o_d[34]
    DIRECTION OUTPUT ;
    USE SIGNAL ;
    PORT
      LAYER M4 ;
        RECT  0 9.936 0.192 9.96 ;
    END
  END o_d[34]
  PIN o_d[350]
    DIRECTION OUTPUT ;
    USE SIGNAL ;
    PORT
      LAYER M4 ;
        RECT  0 61.776 0.192 61.8 ;
    END
  END o_d[350]
  PIN o_d[351]
    DIRECTION OUTPUT ;
    USE SIGNAL ;
    PORT
      LAYER M4 ;
        RECT  0 61.92 0.192 61.944 ;
    END
  END o_d[351]
  PIN o_d[352]
    DIRECTION OUTPUT ;
    USE SIGNAL ;
    PORT
      LAYER M4 ;
        RECT  0 62.064 0.192 62.088 ;
    END
  END o_d[352]
  PIN o_d[353]
    DIRECTION OUTPUT ;
    USE SIGNAL ;
    PORT
      LAYER M4 ;
        RECT  0 62.208 0.192 62.232 ;
    END
  END o_d[353]
  PIN o_d[354]
    DIRECTION OUTPUT ;
    USE SIGNAL ;
    PORT
      LAYER M4 ;
        RECT  0 62.352 0.192 62.376 ;
    END
  END o_d[354]
  PIN o_d[355]
    DIRECTION OUTPUT ;
    USE SIGNAL ;
    PORT
      LAYER M4 ;
        RECT  0 62.496 0.192 62.52 ;
    END
  END o_d[355]
  PIN o_d[356]
    DIRECTION OUTPUT ;
    USE SIGNAL ;
    PORT
      LAYER M4 ;
        RECT  0 62.64 0.192 62.664 ;
    END
  END o_d[356]
  PIN o_d[357]
    DIRECTION OUTPUT ;
    USE SIGNAL ;
    PORT
      LAYER M4 ;
        RECT  0 62.928 0.192 62.952 ;
    END
  END o_d[357]
  PIN o_d[358]
    DIRECTION OUTPUT ;
    USE SIGNAL ;
    PORT
      LAYER M4 ;
        RECT  0 63.072 0.192 63.096 ;
    END
  END o_d[358]
  PIN o_d[359]
    DIRECTION OUTPUT ;
    USE SIGNAL ;
    PORT
      LAYER M4 ;
        RECT  0 63.216 0.192 63.24 ;
    END
  END o_d[359]
  PIN o_d[35]
    DIRECTION OUTPUT ;
    USE SIGNAL ;
    PORT
      LAYER M4 ;
        RECT  0 10.08 0.192 10.104 ;
    END
  END o_d[35]
  PIN o_d[360]
    DIRECTION OUTPUT ;
    USE SIGNAL ;
    PORT
      LAYER M4 ;
        RECT  0 63.36 0.192 63.384 ;
    END
  END o_d[360]
  PIN o_d[361]
    DIRECTION OUTPUT ;
    USE SIGNAL ;
    PORT
      LAYER M4 ;
        RECT  0 63.504 0.192 63.528 ;
    END
  END o_d[361]
  PIN o_d[362]
    DIRECTION OUTPUT ;
    USE SIGNAL ;
    PORT
      LAYER M4 ;
        RECT  0 63.648 0.192 63.672 ;
    END
  END o_d[362]
  PIN o_d[363]
    DIRECTION OUTPUT ;
    USE SIGNAL ;
    PORT
      LAYER M4 ;
        RECT  0 63.792 0.192 63.816 ;
    END
  END o_d[363]
  PIN o_d[364]
    DIRECTION OUTPUT ;
    USE SIGNAL ;
    PORT
      LAYER M4 ;
        RECT  0 63.936 0.192 63.96 ;
    END
  END o_d[364]
  PIN o_d[365]
    DIRECTION OUTPUT ;
    USE SIGNAL ;
    PORT
      LAYER M4 ;
        RECT  0 64.224 0.192 64.248 ;
    END
  END o_d[365]
  PIN o_d[366]
    DIRECTION OUTPUT ;
    USE SIGNAL ;
    PORT
      LAYER M4 ;
        RECT  0 64.368 0.192 64.392 ;
    END
  END o_d[366]
  PIN o_d[367]
    DIRECTION OUTPUT ;
    USE SIGNAL ;
    PORT
      LAYER M4 ;
        RECT  0 64.512 0.192 64.536 ;
    END
  END o_d[367]
  PIN o_d[368]
    DIRECTION OUTPUT ;
    USE SIGNAL ;
    PORT
      LAYER M4 ;
        RECT  0 64.656 0.192 64.68 ;
    END
  END o_d[368]
  PIN o_d[369]
    DIRECTION OUTPUT ;
    USE SIGNAL ;
    PORT
      LAYER M4 ;
        RECT  0 64.8 0.192 64.824 ;
    END
  END o_d[369]
  PIN o_d[36]
    DIRECTION OUTPUT ;
    USE SIGNAL ;
    PORT
      LAYER M4 ;
        RECT  0 10.224 0.192 10.248 ;
    END
  END o_d[36]
  PIN o_d[370]
    DIRECTION OUTPUT ;
    USE SIGNAL ;
    PORT
      LAYER M4 ;
        RECT  0 64.944 0.192 64.968 ;
    END
  END o_d[370]
  PIN o_d[371]
    DIRECTION OUTPUT ;
    USE SIGNAL ;
    PORT
      LAYER M4 ;
        RECT  0 65.088 0.192 65.112 ;
    END
  END o_d[371]
  PIN o_d[372]
    DIRECTION OUTPUT ;
    USE SIGNAL ;
    PORT
      LAYER M4 ;
        RECT  0 65.376 0.192 65.4 ;
    END
  END o_d[372]
  PIN o_d[373]
    DIRECTION OUTPUT ;
    USE SIGNAL ;
    PORT
      LAYER M4 ;
        RECT  0 65.52 0.192 65.544 ;
    END
  END o_d[373]
  PIN o_d[374]
    DIRECTION OUTPUT ;
    USE SIGNAL ;
    PORT
      LAYER M4 ;
        RECT  0 65.664 0.192 65.688 ;
    END
  END o_d[374]
  PIN o_d[375]
    DIRECTION OUTPUT ;
    USE SIGNAL ;
    PORT
      LAYER M4 ;
        RECT  0 65.808 0.192 65.832 ;
    END
  END o_d[375]
  PIN o_d[376]
    DIRECTION OUTPUT ;
    USE SIGNAL ;
    PORT
      LAYER M4 ;
        RECT  0 65.952 0.192 65.976 ;
    END
  END o_d[376]
  PIN o_d[377]
    DIRECTION OUTPUT ;
    USE SIGNAL ;
    PORT
      LAYER M4 ;
        RECT  0 66.096 0.192 66.12 ;
    END
  END o_d[377]
  PIN o_d[378]
    DIRECTION OUTPUT ;
    USE SIGNAL ;
    PORT
      LAYER M4 ;
        RECT  0 66.24 0.192 66.264 ;
    END
  END o_d[378]
  PIN o_d[379]
    DIRECTION OUTPUT ;
    USE SIGNAL ;
    PORT
      LAYER M4 ;
        RECT  0 66.528 0.192 66.552 ;
    END
  END o_d[379]
  PIN o_d[37]
    DIRECTION OUTPUT ;
    USE SIGNAL ;
    PORT
      LAYER M4 ;
        RECT  0 10.368 0.192 10.392 ;
    END
  END o_d[37]
  PIN o_d[380]
    DIRECTION OUTPUT ;
    USE SIGNAL ;
    PORT
      LAYER M4 ;
        RECT  0 66.672 0.192 66.696 ;
    END
  END o_d[380]
  PIN o_d[381]
    DIRECTION OUTPUT ;
    USE SIGNAL ;
    PORT
      LAYER M4 ;
        RECT  0 66.816 0.192 66.84 ;
    END
  END o_d[381]
  PIN o_d[382]
    DIRECTION OUTPUT ;
    USE SIGNAL ;
    PORT
      LAYER M4 ;
        RECT  0 66.96 0.192 66.984 ;
    END
  END o_d[382]
  PIN o_d[383]
    DIRECTION OUTPUT ;
    USE SIGNAL ;
    PORT
      LAYER M4 ;
        RECT  0 67.104 0.192 67.128 ;
    END
  END o_d[383]
  PIN o_d[384]
    DIRECTION OUTPUT ;
    USE SIGNAL ;
    PORT
      LAYER M4 ;
        RECT  0 67.248 0.192 67.272 ;
    END
  END o_d[384]
  PIN o_d[385]
    DIRECTION OUTPUT ;
    USE SIGNAL ;
    PORT
      LAYER M4 ;
        RECT  0 67.392 0.192 67.416 ;
    END
  END o_d[385]
  PIN o_d[386]
    DIRECTION OUTPUT ;
    USE SIGNAL ;
    PORT
      LAYER M4 ;
        RECT  0 67.68 0.192 67.704 ;
    END
  END o_d[386]
  PIN o_d[387]
    DIRECTION OUTPUT ;
    USE SIGNAL ;
    PORT
      LAYER M4 ;
        RECT  0 67.824 0.192 67.848 ;
    END
  END o_d[387]
  PIN o_d[388]
    DIRECTION OUTPUT ;
    USE SIGNAL ;
    PORT
      LAYER M4 ;
        RECT  0 67.968 0.192 67.992 ;
    END
  END o_d[388]
  PIN o_d[389]
    DIRECTION OUTPUT ;
    USE SIGNAL ;
    PORT
      LAYER M4 ;
        RECT  0 68.112 0.192 68.136 ;
    END
  END o_d[389]
  PIN o_d[38]
    DIRECTION OUTPUT ;
    USE SIGNAL ;
    PORT
      LAYER M4 ;
        RECT  0 10.512 0.192 10.536 ;
    END
  END o_d[38]
  PIN o_d[390]
    DIRECTION OUTPUT ;
    USE SIGNAL ;
    PORT
      LAYER M4 ;
        RECT  0 68.256 0.192 68.28 ;
    END
  END o_d[390]
  PIN o_d[391]
    DIRECTION OUTPUT ;
    USE SIGNAL ;
    PORT
      LAYER M4 ;
        RECT  0 68.4 0.192 68.424 ;
    END
  END o_d[391]
  PIN o_d[392]
    DIRECTION OUTPUT ;
    USE SIGNAL ;
    PORT
      LAYER M4 ;
        RECT  0 68.544 0.192 68.568 ;
    END
  END o_d[392]
  PIN o_d[393]
    DIRECTION OUTPUT ;
    USE SIGNAL ;
    PORT
      LAYER M4 ;
        RECT  0 68.832 0.192 68.856 ;
    END
  END o_d[393]
  PIN o_d[394]
    DIRECTION OUTPUT ;
    USE SIGNAL ;
    PORT
      LAYER M4 ;
        RECT  0 68.976 0.192 69 ;
    END
  END o_d[394]
  PIN o_d[395]
    DIRECTION OUTPUT ;
    USE SIGNAL ;
    PORT
      LAYER M4 ;
        RECT  0 69.12 0.192 69.144 ;
    END
  END o_d[395]
  PIN o_d[396]
    DIRECTION OUTPUT ;
    USE SIGNAL ;
    PORT
      LAYER M4 ;
        RECT  0 69.264 0.192 69.288 ;
    END
  END o_d[396]
  PIN o_d[397]
    DIRECTION OUTPUT ;
    USE SIGNAL ;
    PORT
      LAYER M4 ;
        RECT  0 69.408 0.192 69.432 ;
    END
  END o_d[397]
  PIN o_d[398]
    DIRECTION OUTPUT ;
    USE SIGNAL ;
    PORT
      LAYER M4 ;
        RECT  0 69.552 0.192 69.576 ;
    END
  END o_d[398]
  PIN o_d[399]
    DIRECTION OUTPUT ;
    USE SIGNAL ;
    PORT
      LAYER M4 ;
        RECT  0 69.696 0.192 69.72 ;
    END
  END o_d[399]
  PIN o_d[39]
    DIRECTION OUTPUT ;
    USE SIGNAL ;
    PORT
      LAYER M4 ;
        RECT  0 10.656 0.192 10.68 ;
    END
  END o_d[39]
  PIN o_d[3]
    DIRECTION OUTPUT ;
    USE SIGNAL ;
    PORT
      LAYER M4 ;
        RECT  0 4.752 0.192 4.776 ;
    END
  END o_d[3]
  PIN o_d[400]
    DIRECTION OUTPUT ;
    USE SIGNAL ;
    PORT
      LAYER M4 ;
        RECT  0 69.84 0.192 69.864 ;
    END
  END o_d[400]
  PIN o_d[401]
    DIRECTION OUTPUT ;
    USE SIGNAL ;
    PORT
      LAYER M4 ;
        RECT  0 70.128 0.192 70.152 ;
    END
  END o_d[401]
  PIN o_d[402]
    DIRECTION OUTPUT ;
    USE SIGNAL ;
    PORT
      LAYER M4 ;
        RECT  0 70.272 0.192 70.296 ;
    END
  END o_d[402]
  PIN o_d[403]
    DIRECTION OUTPUT ;
    USE SIGNAL ;
    PORT
      LAYER M4 ;
        RECT  0 70.416 0.192 70.44 ;
    END
  END o_d[403]
  PIN o_d[404]
    DIRECTION OUTPUT ;
    USE SIGNAL ;
    PORT
      LAYER M4 ;
        RECT  0 70.56 0.192 70.584 ;
    END
  END o_d[404]
  PIN o_d[405]
    DIRECTION OUTPUT ;
    USE SIGNAL ;
    PORT
      LAYER M4 ;
        RECT  0 70.704 0.192 70.728 ;
    END
  END o_d[405]
  PIN o_d[406]
    DIRECTION OUTPUT ;
    USE SIGNAL ;
    PORT
      LAYER M4 ;
        RECT  0 70.848 0.192 70.872 ;
    END
  END o_d[406]
  PIN o_d[407]
    DIRECTION OUTPUT ;
    USE SIGNAL ;
    PORT
      LAYER M4 ;
        RECT  0 70.992 0.192 71.016 ;
    END
  END o_d[407]
  PIN o_d[408]
    DIRECTION OUTPUT ;
    USE SIGNAL ;
    PORT
      LAYER M4 ;
        RECT  0 71.28 0.192 71.304 ;
    END
  END o_d[408]
  PIN o_d[409]
    DIRECTION OUTPUT ;
    USE SIGNAL ;
    PORT
      LAYER M4 ;
        RECT  0 71.424 0.192 71.448 ;
    END
  END o_d[409]
  PIN o_d[40]
    DIRECTION OUTPUT ;
    USE SIGNAL ;
    PORT
      LAYER M4 ;
        RECT  0 10.944 0.192 10.968 ;
    END
  END o_d[40]
  PIN o_d[410]
    DIRECTION OUTPUT ;
    USE SIGNAL ;
    PORT
      LAYER M4 ;
        RECT  0 71.568 0.192 71.592 ;
    END
  END o_d[410]
  PIN o_d[411]
    DIRECTION OUTPUT ;
    USE SIGNAL ;
    PORT
      LAYER M4 ;
        RECT  0 71.712 0.192 71.736 ;
    END
  END o_d[411]
  PIN o_d[412]
    DIRECTION OUTPUT ;
    USE SIGNAL ;
    PORT
      LAYER M4 ;
        RECT  0 71.856 0.192 71.88 ;
    END
  END o_d[412]
  PIN o_d[413]
    DIRECTION OUTPUT ;
    USE SIGNAL ;
    PORT
      LAYER M4 ;
        RECT  0 72 0.192 72.024 ;
    END
  END o_d[413]
  PIN o_d[414]
    DIRECTION OUTPUT ;
    USE SIGNAL ;
    PORT
      LAYER M4 ;
        RECT  0 72.144 0.192 72.168 ;
    END
  END o_d[414]
  PIN o_d[415]
    DIRECTION OUTPUT ;
    USE SIGNAL ;
    PORT
      LAYER M4 ;
        RECT  0 72.432 0.192 72.456 ;
    END
  END o_d[415]
  PIN o_d[416]
    DIRECTION OUTPUT ;
    USE SIGNAL ;
    PORT
      LAYER M4 ;
        RECT  0 72.576 0.192 72.6 ;
    END
  END o_d[416]
  PIN o_d[417]
    DIRECTION OUTPUT ;
    USE SIGNAL ;
    PORT
      LAYER M4 ;
        RECT  0 72.72 0.192 72.744 ;
    END
  END o_d[417]
  PIN o_d[418]
    DIRECTION OUTPUT ;
    USE SIGNAL ;
    PORT
      LAYER M4 ;
        RECT  0 72.864 0.192 72.888 ;
    END
  END o_d[418]
  PIN o_d[419]
    DIRECTION OUTPUT ;
    USE SIGNAL ;
    PORT
      LAYER M4 ;
        RECT  0 73.008 0.192 73.032 ;
    END
  END o_d[419]
  PIN o_d[41]
    DIRECTION OUTPUT ;
    USE SIGNAL ;
    PORT
      LAYER M4 ;
        RECT  0 11.088 0.192 11.112 ;
    END
  END o_d[41]
  PIN o_d[420]
    DIRECTION OUTPUT ;
    USE SIGNAL ;
    PORT
      LAYER M4 ;
        RECT  0 73.152 0.192 73.176 ;
    END
  END o_d[420]
  PIN o_d[421]
    DIRECTION OUTPUT ;
    USE SIGNAL ;
    PORT
      LAYER M4 ;
        RECT  0 73.296 0.192 73.32 ;
    END
  END o_d[421]
  PIN o_d[422]
    DIRECTION OUTPUT ;
    USE SIGNAL ;
    PORT
      LAYER M4 ;
        RECT  0 73.584 0.192 73.608 ;
    END
  END o_d[422]
  PIN o_d[423]
    DIRECTION OUTPUT ;
    USE SIGNAL ;
    PORT
      LAYER M4 ;
        RECT  0 73.728 0.192 73.752 ;
    END
  END o_d[423]
  PIN o_d[424]
    DIRECTION OUTPUT ;
    USE SIGNAL ;
    PORT
      LAYER M4 ;
        RECT  0 73.872 0.192 73.896 ;
    END
  END o_d[424]
  PIN o_d[425]
    DIRECTION OUTPUT ;
    USE SIGNAL ;
    PORT
      LAYER M4 ;
        RECT  0 74.016 0.192 74.04 ;
    END
  END o_d[425]
  PIN o_d[426]
    DIRECTION OUTPUT ;
    USE SIGNAL ;
    PORT
      LAYER M4 ;
        RECT  0 74.16 0.192 74.184 ;
    END
  END o_d[426]
  PIN o_d[427]
    DIRECTION OUTPUT ;
    USE SIGNAL ;
    PORT
      LAYER M4 ;
        RECT  0 74.304 0.192 74.328 ;
    END
  END o_d[427]
  PIN o_d[428]
    DIRECTION OUTPUT ;
    USE SIGNAL ;
    PORT
      LAYER M4 ;
        RECT  0 74.448 0.192 74.472 ;
    END
  END o_d[428]
  PIN o_d[429]
    DIRECTION OUTPUT ;
    USE SIGNAL ;
    PORT
      LAYER M4 ;
        RECT  0 74.592 0.192 74.616 ;
    END
  END o_d[429]
  PIN o_d[42]
    DIRECTION OUTPUT ;
    USE SIGNAL ;
    PORT
      LAYER M4 ;
        RECT  0 11.232 0.192 11.256 ;
    END
  END o_d[42]
  PIN o_d[430]
    DIRECTION OUTPUT ;
    USE SIGNAL ;
    PORT
      LAYER M4 ;
        RECT  0 74.88 0.192 74.904 ;
    END
  END o_d[430]
  PIN o_d[431]
    DIRECTION OUTPUT ;
    USE SIGNAL ;
    PORT
      LAYER M4 ;
        RECT  0 75.024 0.192 75.048 ;
    END
  END o_d[431]
  PIN o_d[432]
    DIRECTION OUTPUT ;
    USE SIGNAL ;
    PORT
      LAYER M4 ;
        RECT  0 75.168 0.192 75.192 ;
    END
  END o_d[432]
  PIN o_d[433]
    DIRECTION OUTPUT ;
    USE SIGNAL ;
    PORT
      LAYER M4 ;
        RECT  0 75.312 0.192 75.336 ;
    END
  END o_d[433]
  PIN o_d[434]
    DIRECTION OUTPUT ;
    USE SIGNAL ;
    PORT
      LAYER M4 ;
        RECT  0 75.456 0.192 75.48 ;
    END
  END o_d[434]
  PIN o_d[435]
    DIRECTION OUTPUT ;
    USE SIGNAL ;
    PORT
      LAYER M4 ;
        RECT  0 75.6 0.192 75.624 ;
    END
  END o_d[435]
  PIN o_d[436]
    DIRECTION OUTPUT ;
    USE SIGNAL ;
    PORT
      LAYER M4 ;
        RECT  0 75.744 0.192 75.768 ;
    END
  END o_d[436]
  PIN o_d[437]
    DIRECTION OUTPUT ;
    USE SIGNAL ;
    PORT
      LAYER M4 ;
        RECT  0 76.032 0.192 76.056 ;
    END
  END o_d[437]
  PIN o_d[438]
    DIRECTION OUTPUT ;
    USE SIGNAL ;
    PORT
      LAYER M4 ;
        RECT  0 76.176 0.192 76.2 ;
    END
  END o_d[438]
  PIN o_d[439]
    DIRECTION OUTPUT ;
    USE SIGNAL ;
    PORT
      LAYER M4 ;
        RECT  0 76.32 0.192 76.344 ;
    END
  END o_d[439]
  PIN o_d[43]
    DIRECTION OUTPUT ;
    USE SIGNAL ;
    PORT
      LAYER M4 ;
        RECT  0 11.376 0.192 11.4 ;
    END
  END o_d[43]
  PIN o_d[440]
    DIRECTION OUTPUT ;
    USE SIGNAL ;
    PORT
      LAYER M4 ;
        RECT  0 76.464 0.192 76.488 ;
    END
  END o_d[440]
  PIN o_d[441]
    DIRECTION OUTPUT ;
    USE SIGNAL ;
    PORT
      LAYER M4 ;
        RECT  0 76.608 0.192 76.632 ;
    END
  END o_d[441]
  PIN o_d[442]
    DIRECTION OUTPUT ;
    USE SIGNAL ;
    PORT
      LAYER M4 ;
        RECT  0 76.752 0.192 76.776 ;
    END
  END o_d[442]
  PIN o_d[443]
    DIRECTION OUTPUT ;
    USE SIGNAL ;
    PORT
      LAYER M4 ;
        RECT  0 76.896 0.192 76.92 ;
    END
  END o_d[443]
  PIN o_d[444]
    DIRECTION OUTPUT ;
    USE SIGNAL ;
    PORT
      LAYER M4 ;
        RECT  0 77.184 0.192 77.208 ;
    END
  END o_d[444]
  PIN o_d[445]
    DIRECTION OUTPUT ;
    USE SIGNAL ;
    PORT
      LAYER M4 ;
        RECT  0 77.328 0.192 77.352 ;
    END
  END o_d[445]
  PIN o_d[446]
    DIRECTION OUTPUT ;
    USE SIGNAL ;
    PORT
      LAYER M4 ;
        RECT  0 77.472 0.192 77.496 ;
    END
  END o_d[446]
  PIN o_d[447]
    DIRECTION OUTPUT ;
    USE SIGNAL ;
    PORT
      LAYER M4 ;
        RECT  0 77.616 0.192 77.64 ;
    END
  END o_d[447]
  PIN o_d[448]
    DIRECTION OUTPUT ;
    USE SIGNAL ;
    PORT
      LAYER M4 ;
        RECT  0 77.76 0.192 77.784 ;
    END
  END o_d[448]
  PIN o_d[449]
    DIRECTION OUTPUT ;
    USE SIGNAL ;
    PORT
      LAYER M4 ;
        RECT  0 77.904 0.192 77.928 ;
    END
  END o_d[449]
  PIN o_d[44]
    DIRECTION OUTPUT ;
    USE SIGNAL ;
    PORT
      LAYER M4 ;
        RECT  0 11.52 0.192 11.544 ;
    END
  END o_d[44]
  PIN o_d[450]
    DIRECTION OUTPUT ;
    USE SIGNAL ;
    PORT
      LAYER M4 ;
        RECT  0 78.048 0.192 78.072 ;
    END
  END o_d[450]
  PIN o_d[451]
    DIRECTION OUTPUT ;
    USE SIGNAL ;
    PORT
      LAYER M4 ;
        RECT  0 78.336 0.192 78.36 ;
    END
  END o_d[451]
  PIN o_d[452]
    DIRECTION OUTPUT ;
    USE SIGNAL ;
    PORT
      LAYER M4 ;
        RECT  0 78.48 0.192 78.504 ;
    END
  END o_d[452]
  PIN o_d[453]
    DIRECTION OUTPUT ;
    USE SIGNAL ;
    PORT
      LAYER M4 ;
        RECT  0 78.624 0.192 78.648 ;
    END
  END o_d[453]
  PIN o_d[454]
    DIRECTION OUTPUT ;
    USE SIGNAL ;
    PORT
      LAYER M4 ;
        RECT  0 78.768 0.192 78.792 ;
    END
  END o_d[454]
  PIN o_d[455]
    DIRECTION OUTPUT ;
    USE SIGNAL ;
    PORT
      LAYER M4 ;
        RECT  0 78.912 0.192 78.936 ;
    END
  END o_d[455]
  PIN o_d[456]
    DIRECTION OUTPUT ;
    USE SIGNAL ;
    PORT
      LAYER M4 ;
        RECT  0 79.056 0.192 79.08 ;
    END
  END o_d[456]
  PIN o_d[457]
    DIRECTION OUTPUT ;
    USE SIGNAL ;
    PORT
      LAYER M4 ;
        RECT  0 79.2 0.192 79.224 ;
    END
  END o_d[457]
  PIN o_d[458]
    DIRECTION OUTPUT ;
    USE SIGNAL ;
    PORT
      LAYER M4 ;
        RECT  0 79.488 0.192 79.512 ;
    END
  END o_d[458]
  PIN o_d[459]
    DIRECTION OUTPUT ;
    USE SIGNAL ;
    PORT
      LAYER M4 ;
        RECT  0 79.632 0.192 79.656 ;
    END
  END o_d[459]
  PIN o_d[45]
    DIRECTION OUTPUT ;
    USE SIGNAL ;
    PORT
      LAYER M4 ;
        RECT  0 11.664 0.192 11.688 ;
    END
  END o_d[45]
  PIN o_d[460]
    DIRECTION OUTPUT ;
    USE SIGNAL ;
    PORT
      LAYER M4 ;
        RECT  0 79.776 0.192 79.8 ;
    END
  END o_d[460]
  PIN o_d[461]
    DIRECTION OUTPUT ;
    USE SIGNAL ;
    PORT
      LAYER M4 ;
        RECT  0 79.92 0.192 79.944 ;
    END
  END o_d[461]
  PIN o_d[462]
    DIRECTION OUTPUT ;
    USE SIGNAL ;
    PORT
      LAYER M4 ;
        RECT  0 80.064 0.192 80.088 ;
    END
  END o_d[462]
  PIN o_d[463]
    DIRECTION OUTPUT ;
    USE SIGNAL ;
    PORT
      LAYER M4 ;
        RECT  0 80.208 0.192 80.232 ;
    END
  END o_d[463]
  PIN o_d[464]
    DIRECTION OUTPUT ;
    USE SIGNAL ;
    PORT
      LAYER M4 ;
        RECT  0 80.352 0.192 80.376 ;
    END
  END o_d[464]
  PIN o_d[465]
    DIRECTION OUTPUT ;
    USE SIGNAL ;
    PORT
      LAYER M4 ;
        RECT  0 80.496 0.192 80.52 ;
    END
  END o_d[465]
  PIN o_d[466]
    DIRECTION OUTPUT ;
    USE SIGNAL ;
    PORT
      LAYER M4 ;
        RECT  0 80.784 0.192 80.808 ;
    END
  END o_d[466]
  PIN o_d[467]
    DIRECTION OUTPUT ;
    USE SIGNAL ;
    PORT
      LAYER M4 ;
        RECT  0 80.928 0.192 80.952 ;
    END
  END o_d[467]
  PIN o_d[468]
    DIRECTION OUTPUT ;
    USE SIGNAL ;
    PORT
      LAYER M4 ;
        RECT  0 81.072 0.192 81.096 ;
    END
  END o_d[468]
  PIN o_d[469]
    DIRECTION OUTPUT ;
    USE SIGNAL ;
    PORT
      LAYER M4 ;
        RECT  0 81.216 0.192 81.24 ;
    END
  END o_d[469]
  PIN o_d[46]
    DIRECTION OUTPUT ;
    USE SIGNAL ;
    PORT
      LAYER M4 ;
        RECT  0 11.808 0.192 11.832 ;
    END
  END o_d[46]
  PIN o_d[470]
    DIRECTION OUTPUT ;
    USE SIGNAL ;
    PORT
      LAYER M4 ;
        RECT  0 81.36 0.192 81.384 ;
    END
  END o_d[470]
  PIN o_d[471]
    DIRECTION OUTPUT ;
    USE SIGNAL ;
    PORT
      LAYER M4 ;
        RECT  0 81.504 0.192 81.528 ;
    END
  END o_d[471]
  PIN o_d[472]
    DIRECTION OUTPUT ;
    USE SIGNAL ;
    PORT
      LAYER M4 ;
        RECT  0 81.648 0.192 81.672 ;
    END
  END o_d[472]
  PIN o_d[473]
    DIRECTION OUTPUT ;
    USE SIGNAL ;
    PORT
      LAYER M4 ;
        RECT  0 81.936 0.192 81.96 ;
    END
  END o_d[473]
  PIN o_d[474]
    DIRECTION OUTPUT ;
    USE SIGNAL ;
    PORT
      LAYER M4 ;
        RECT  0 82.08 0.192 82.104 ;
    END
  END o_d[474]
  PIN o_d[475]
    DIRECTION OUTPUT ;
    USE SIGNAL ;
    PORT
      LAYER M4 ;
        RECT  0 82.224 0.192 82.248 ;
    END
  END o_d[475]
  PIN o_d[476]
    DIRECTION OUTPUT ;
    USE SIGNAL ;
    PORT
      LAYER M4 ;
        RECT  0 82.368 0.192 82.392 ;
    END
  END o_d[476]
  PIN o_d[477]
    DIRECTION OUTPUT ;
    USE SIGNAL ;
    PORT
      LAYER M4 ;
        RECT  0 82.512 0.192 82.536 ;
    END
  END o_d[477]
  PIN o_d[478]
    DIRECTION OUTPUT ;
    USE SIGNAL ;
    PORT
      LAYER M4 ;
        RECT  0 82.656 0.192 82.68 ;
    END
  END o_d[478]
  PIN o_d[479]
    DIRECTION OUTPUT ;
    USE SIGNAL ;
    PORT
      LAYER M4 ;
        RECT  0 82.8 0.192 82.824 ;
    END
  END o_d[479]
  PIN o_d[47]
    DIRECTION OUTPUT ;
    USE SIGNAL ;
    PORT
      LAYER M4 ;
        RECT  0 12.096 0.192 12.12 ;
    END
  END o_d[47]
  PIN o_d[480]
    DIRECTION OUTPUT ;
    USE SIGNAL ;
    PORT
      LAYER M4 ;
        RECT  0 83.088 0.192 83.112 ;
    END
  END o_d[480]
  PIN o_d[481]
    DIRECTION OUTPUT ;
    USE SIGNAL ;
    PORT
      LAYER M4 ;
        RECT  0 83.232 0.192 83.256 ;
    END
  END o_d[481]
  PIN o_d[482]
    DIRECTION OUTPUT ;
    USE SIGNAL ;
    PORT
      LAYER M4 ;
        RECT  0 83.376 0.192 83.4 ;
    END
  END o_d[482]
  PIN o_d[483]
    DIRECTION OUTPUT ;
    USE SIGNAL ;
    PORT
      LAYER M4 ;
        RECT  0 83.52 0.192 83.544 ;
    END
  END o_d[483]
  PIN o_d[484]
    DIRECTION OUTPUT ;
    USE SIGNAL ;
    PORT
      LAYER M4 ;
        RECT  0 83.664 0.192 83.688 ;
    END
  END o_d[484]
  PIN o_d[485]
    DIRECTION OUTPUT ;
    USE SIGNAL ;
    PORT
      LAYER M4 ;
        RECT  0 83.808 0.192 83.832 ;
    END
  END o_d[485]
  PIN o_d[486]
    DIRECTION OUTPUT ;
    USE SIGNAL ;
    PORT
      LAYER M4 ;
        RECT  0 83.952 0.192 83.976 ;
    END
  END o_d[486]
  PIN o_d[487]
    DIRECTION OUTPUT ;
    USE SIGNAL ;
    PORT
      LAYER M4 ;
        RECT  0 84.24 0.192 84.264 ;
    END
  END o_d[487]
  PIN o_d[488]
    DIRECTION OUTPUT ;
    USE SIGNAL ;
    PORT
      LAYER M4 ;
        RECT  0 84.384 0.192 84.408 ;
    END
  END o_d[488]
  PIN o_d[489]
    DIRECTION OUTPUT ;
    USE SIGNAL ;
    PORT
      LAYER M4 ;
        RECT  0 84.528 0.192 84.552 ;
    END
  END o_d[489]
  PIN o_d[48]
    DIRECTION OUTPUT ;
    USE SIGNAL ;
    PORT
      LAYER M4 ;
        RECT  0 12.24 0.192 12.264 ;
    END
  END o_d[48]
  PIN o_d[490]
    DIRECTION OUTPUT ;
    USE SIGNAL ;
    PORT
      LAYER M4 ;
        RECT  0 84.672 0.192 84.696 ;
    END
  END o_d[490]
  PIN o_d[491]
    DIRECTION OUTPUT ;
    USE SIGNAL ;
    PORT
      LAYER M4 ;
        RECT  0 84.816 0.192 84.84 ;
    END
  END o_d[491]
  PIN o_d[492]
    DIRECTION OUTPUT ;
    USE SIGNAL ;
    PORT
      LAYER M4 ;
        RECT  0 84.96 0.192 84.984 ;
    END
  END o_d[492]
  PIN o_d[493]
    DIRECTION OUTPUT ;
    USE SIGNAL ;
    PORT
      LAYER M4 ;
        RECT  0 85.104 0.192 85.128 ;
    END
  END o_d[493]
  PIN o_d[494]
    DIRECTION OUTPUT ;
    USE SIGNAL ;
    PORT
      LAYER M4 ;
        RECT  0 85.248 0.192 85.272 ;
    END
  END o_d[494]
  PIN o_d[495]
    DIRECTION OUTPUT ;
    USE SIGNAL ;
    PORT
      LAYER M4 ;
        RECT  0 85.536 0.192 85.56 ;
    END
  END o_d[495]
  PIN o_d[496]
    DIRECTION OUTPUT ;
    USE SIGNAL ;
    PORT
      LAYER M4 ;
        RECT  0 85.68 0.192 85.704 ;
    END
  END o_d[496]
  PIN o_d[497]
    DIRECTION OUTPUT ;
    USE SIGNAL ;
    PORT
      LAYER M4 ;
        RECT  0 85.824 0.192 85.848 ;
    END
  END o_d[497]
  PIN o_d[498]
    DIRECTION OUTPUT ;
    USE SIGNAL ;
    PORT
      LAYER M4 ;
        RECT  0 85.968 0.192 85.992 ;
    END
  END o_d[498]
  PIN o_d[499]
    DIRECTION OUTPUT ;
    USE SIGNAL ;
    PORT
      LAYER M4 ;
        RECT  0 86.112 0.192 86.136 ;
    END
  END o_d[499]
  PIN o_d[49]
    DIRECTION OUTPUT ;
    USE SIGNAL ;
    PORT
      LAYER M4 ;
        RECT  0 12.384 0.192 12.408 ;
    END
  END o_d[49]
  PIN o_d[4]
    DIRECTION OUTPUT ;
    USE SIGNAL ;
    PORT
      LAYER M4 ;
        RECT  0 5.04 0.192 5.064 ;
    END
  END o_d[4]
  PIN o_d[500]
    DIRECTION OUTPUT ;
    USE SIGNAL ;
    PORT
      LAYER M4 ;
        RECT  0 86.256 0.192 86.28 ;
    END
  END o_d[500]
  PIN o_d[501]
    DIRECTION OUTPUT ;
    USE SIGNAL ;
    PORT
      LAYER M4 ;
        RECT  0 86.4 0.192 86.424 ;
    END
  END o_d[501]
  PIN o_d[502]
    DIRECTION OUTPUT ;
    USE SIGNAL ;
    PORT
      LAYER M4 ;
        RECT  0 86.688 0.192 86.712 ;
    END
  END o_d[502]
  PIN o_d[503]
    DIRECTION OUTPUT ;
    USE SIGNAL ;
    PORT
      LAYER M4 ;
        RECT  0 86.832 0.192 86.856 ;
    END
  END o_d[503]
  PIN o_d[504]
    DIRECTION OUTPUT ;
    USE SIGNAL ;
    PORT
      LAYER M4 ;
        RECT  0 86.976 0.192 87 ;
    END
  END o_d[504]
  PIN o_d[505]
    DIRECTION OUTPUT ;
    USE SIGNAL ;
    PORT
      LAYER M4 ;
        RECT  0 87.12 0.192 87.144 ;
    END
  END o_d[505]
  PIN o_d[506]
    DIRECTION OUTPUT ;
    USE SIGNAL ;
    PORT
      LAYER M4 ;
        RECT  0 87.264 0.192 87.288 ;
    END
  END o_d[506]
  PIN o_d[507]
    DIRECTION OUTPUT ;
    USE SIGNAL ;
    PORT
      LAYER M4 ;
        RECT  0 87.408 0.192 87.432 ;
    END
  END o_d[507]
  PIN o_d[508]
    DIRECTION OUTPUT ;
    USE SIGNAL ;
    PORT
      LAYER M4 ;
        RECT  0 87.552 0.192 87.576 ;
    END
  END o_d[508]
  PIN o_d[509]
    DIRECTION OUTPUT ;
    USE SIGNAL ;
    PORT
      LAYER M4 ;
        RECT  0 87.84 0.192 87.864 ;
    END
  END o_d[509]
  PIN o_d[50]
    DIRECTION OUTPUT ;
    USE SIGNAL ;
    PORT
      LAYER M4 ;
        RECT  0 12.528 0.192 12.552 ;
    END
  END o_d[50]
  PIN o_d[510]
    DIRECTION OUTPUT ;
    USE SIGNAL ;
    PORT
      LAYER M4 ;
        RECT  0 87.984 0.192 88.008 ;
    END
  END o_d[510]
  PIN o_d[511]
    DIRECTION OUTPUT ;
    USE SIGNAL ;
    PORT
      LAYER M4 ;
        RECT  0 88.128 0.192 88.152 ;
    END
  END o_d[511]
  PIN o_d[51]
    DIRECTION OUTPUT ;
    USE SIGNAL ;
    PORT
      LAYER M4 ;
        RECT  0 12.672 0.192 12.696 ;
    END
  END o_d[51]
  PIN o_d[52]
    DIRECTION OUTPUT ;
    USE SIGNAL ;
    PORT
      LAYER M4 ;
        RECT  0 12.816 0.192 12.84 ;
    END
  END o_d[52]
  PIN o_d[53]
    DIRECTION OUTPUT ;
    USE SIGNAL ;
    PORT
      LAYER M4 ;
        RECT  0 12.96 0.192 12.984 ;
    END
  END o_d[53]
  PIN o_d[54]
    DIRECTION OUTPUT ;
    USE SIGNAL ;
    PORT
      LAYER M4 ;
        RECT  0 13.248 0.192 13.272 ;
    END
  END o_d[54]
  PIN o_d[55]
    DIRECTION OUTPUT ;
    USE SIGNAL ;
    PORT
      LAYER M4 ;
        RECT  0 13.392 0.192 13.416 ;
    END
  END o_d[55]
  PIN o_d[56]
    DIRECTION OUTPUT ;
    USE SIGNAL ;
    PORT
      LAYER M4 ;
        RECT  0 13.536 0.192 13.56 ;
    END
  END o_d[56]
  PIN o_d[57]
    DIRECTION OUTPUT ;
    USE SIGNAL ;
    PORT
      LAYER M4 ;
        RECT  0 13.68 0.192 13.704 ;
    END
  END o_d[57]
  PIN o_d[58]
    DIRECTION OUTPUT ;
    USE SIGNAL ;
    PORT
      LAYER M4 ;
        RECT  0 13.824 0.192 13.848 ;
    END
  END o_d[58]
  PIN o_d[59]
    DIRECTION OUTPUT ;
    USE SIGNAL ;
    PORT
      LAYER M4 ;
        RECT  0 13.968 0.192 13.992 ;
    END
  END o_d[59]
  PIN o_d[5]
    DIRECTION OUTPUT ;
    USE SIGNAL ;
    PORT
      LAYER M4 ;
        RECT  0 5.184 0.192 5.208 ;
    END
  END o_d[5]
  PIN o_d[60]
    DIRECTION OUTPUT ;
    USE SIGNAL ;
    PORT
      LAYER M4 ;
        RECT  0 14.112 0.192 14.136 ;
    END
  END o_d[60]
  PIN o_d[61]
    DIRECTION OUTPUT ;
    USE SIGNAL ;
    PORT
      LAYER M4 ;
        RECT  0 14.4 0.192 14.424 ;
    END
  END o_d[61]
  PIN o_d[62]
    DIRECTION OUTPUT ;
    USE SIGNAL ;
    PORT
      LAYER M4 ;
        RECT  0 14.544 0.192 14.568 ;
    END
  END o_d[62]
  PIN o_d[63]
    DIRECTION OUTPUT ;
    USE SIGNAL ;
    PORT
      LAYER M4 ;
        RECT  0 14.688 0.192 14.712 ;
    END
  END o_d[63]
  PIN o_d[64]
    DIRECTION OUTPUT ;
    USE SIGNAL ;
    PORT
      LAYER M4 ;
        RECT  0 14.832 0.192 14.856 ;
    END
  END o_d[64]
  PIN o_d[65]
    DIRECTION OUTPUT ;
    USE SIGNAL ;
    PORT
      LAYER M4 ;
        RECT  0 14.976 0.192 15 ;
    END
  END o_d[65]
  PIN o_d[66]
    DIRECTION OUTPUT ;
    USE SIGNAL ;
    PORT
      LAYER M4 ;
        RECT  0 15.12 0.192 15.144 ;
    END
  END o_d[66]
  PIN o_d[67]
    DIRECTION OUTPUT ;
    USE SIGNAL ;
    PORT
      LAYER M4 ;
        RECT  0 15.264 0.192 15.288 ;
    END
  END o_d[67]
  PIN o_d[68]
    DIRECTION OUTPUT ;
    USE SIGNAL ;
    PORT
      LAYER M4 ;
        RECT  0 15.408 0.192 15.432 ;
    END
  END o_d[68]
  PIN o_d[69]
    DIRECTION OUTPUT ;
    USE SIGNAL ;
    PORT
      LAYER M4 ;
        RECT  0 15.696 0.192 15.72 ;
    END
  END o_d[69]
  PIN o_d[6]
    DIRECTION OUTPUT ;
    USE SIGNAL ;
    PORT
      LAYER M4 ;
        RECT  0 5.328 0.192 5.352 ;
    END
  END o_d[6]
  PIN o_d[70]
    DIRECTION OUTPUT ;
    USE SIGNAL ;
    PORT
      LAYER M4 ;
        RECT  0 15.84 0.192 15.864 ;
    END
  END o_d[70]
  PIN o_d[71]
    DIRECTION OUTPUT ;
    USE SIGNAL ;
    PORT
      LAYER M4 ;
        RECT  0 15.984 0.192 16.008 ;
    END
  END o_d[71]
  PIN o_d[72]
    DIRECTION OUTPUT ;
    USE SIGNAL ;
    PORT
      LAYER M4 ;
        RECT  0 16.128 0.192 16.152 ;
    END
  END o_d[72]
  PIN o_d[73]
    DIRECTION OUTPUT ;
    USE SIGNAL ;
    PORT
      LAYER M4 ;
        RECT  0 16.272 0.192 16.296 ;
    END
  END o_d[73]
  PIN o_d[74]
    DIRECTION OUTPUT ;
    USE SIGNAL ;
    PORT
      LAYER M4 ;
        RECT  0 16.416 0.192 16.44 ;
    END
  END o_d[74]
  PIN o_d[75]
    DIRECTION OUTPUT ;
    USE SIGNAL ;
    PORT
      LAYER M4 ;
        RECT  0 16.56 0.192 16.584 ;
    END
  END o_d[75]
  PIN o_d[76]
    DIRECTION OUTPUT ;
    USE SIGNAL ;
    PORT
      LAYER M4 ;
        RECT  0 16.848 0.192 16.872 ;
    END
  END o_d[76]
  PIN o_d[77]
    DIRECTION OUTPUT ;
    USE SIGNAL ;
    PORT
      LAYER M4 ;
        RECT  0 16.992 0.192 17.016 ;
    END
  END o_d[77]
  PIN o_d[78]
    DIRECTION OUTPUT ;
    USE SIGNAL ;
    PORT
      LAYER M4 ;
        RECT  0 17.136 0.192 17.16 ;
    END
  END o_d[78]
  PIN o_d[79]
    DIRECTION OUTPUT ;
    USE SIGNAL ;
    PORT
      LAYER M4 ;
        RECT  0 17.28 0.192 17.304 ;
    END
  END o_d[79]
  PIN o_d[7]
    DIRECTION OUTPUT ;
    USE SIGNAL ;
    PORT
      LAYER M4 ;
        RECT  0 5.472 0.192 5.496 ;
    END
  END o_d[7]
  PIN o_d[80]
    DIRECTION OUTPUT ;
    USE SIGNAL ;
    PORT
      LAYER M4 ;
        RECT  0 17.424 0.192 17.448 ;
    END
  END o_d[80]
  PIN o_d[81]
    DIRECTION OUTPUT ;
    USE SIGNAL ;
    PORT
      LAYER M4 ;
        RECT  0 17.568 0.192 17.592 ;
    END
  END o_d[81]
  PIN o_d[82]
    DIRECTION OUTPUT ;
    USE SIGNAL ;
    PORT
      LAYER M4 ;
        RECT  0 17.712 0.192 17.736 ;
    END
  END o_d[82]
  PIN o_d[83]
    DIRECTION OUTPUT ;
    USE SIGNAL ;
    PORT
      LAYER M4 ;
        RECT  0 18 0.192 18.024 ;
    END
  END o_d[83]
  PIN o_d[84]
    DIRECTION OUTPUT ;
    USE SIGNAL ;
    PORT
      LAYER M4 ;
        RECT  0 18.144 0.192 18.168 ;
    END
  END o_d[84]
  PIN o_d[85]
    DIRECTION OUTPUT ;
    USE SIGNAL ;
    PORT
      LAYER M4 ;
        RECT  0 18.288 0.192 18.312 ;
    END
  END o_d[85]
  PIN o_d[86]
    DIRECTION OUTPUT ;
    USE SIGNAL ;
    PORT
      LAYER M4 ;
        RECT  0 18.432 0.192 18.456 ;
    END
  END o_d[86]
  PIN o_d[87]
    DIRECTION OUTPUT ;
    USE SIGNAL ;
    PORT
      LAYER M4 ;
        RECT  0 18.576 0.192 18.6 ;
    END
  END o_d[87]
  PIN o_d[88]
    DIRECTION OUTPUT ;
    USE SIGNAL ;
    PORT
      LAYER M4 ;
        RECT  0 18.72 0.192 18.744 ;
    END
  END o_d[88]
  PIN o_d[89]
    DIRECTION OUTPUT ;
    USE SIGNAL ;
    PORT
      LAYER M4 ;
        RECT  0 18.864 0.192 18.888 ;
    END
  END o_d[89]
  PIN o_d[8]
    DIRECTION OUTPUT ;
    USE SIGNAL ;
    PORT
      LAYER M4 ;
        RECT  0 5.616 0.192 5.64 ;
    END
  END o_d[8]
  PIN o_d[90]
    DIRECTION OUTPUT ;
    USE SIGNAL ;
    PORT
      LAYER M4 ;
        RECT  0 19.152 0.192 19.176 ;
    END
  END o_d[90]
  PIN o_d[91]
    DIRECTION OUTPUT ;
    USE SIGNAL ;
    PORT
      LAYER M4 ;
        RECT  0 19.296 0.192 19.32 ;
    END
  END o_d[91]
  PIN o_d[92]
    DIRECTION OUTPUT ;
    USE SIGNAL ;
    PORT
      LAYER M4 ;
        RECT  0 19.44 0.192 19.464 ;
    END
  END o_d[92]
  PIN o_d[93]
    DIRECTION OUTPUT ;
    USE SIGNAL ;
    PORT
      LAYER M4 ;
        RECT  0 19.584 0.192 19.608 ;
    END
  END o_d[93]
  PIN o_d[94]
    DIRECTION OUTPUT ;
    USE SIGNAL ;
    PORT
      LAYER M4 ;
        RECT  0 19.728 0.192 19.752 ;
    END
  END o_d[94]
  PIN o_d[95]
    DIRECTION OUTPUT ;
    USE SIGNAL ;
    PORT
      LAYER M4 ;
        RECT  0 19.872 0.192 19.896 ;
    END
  END o_d[95]
  PIN o_d[96]
    DIRECTION OUTPUT ;
    USE SIGNAL ;
    PORT
      LAYER M4 ;
        RECT  0 20.016 0.192 20.04 ;
    END
  END o_d[96]
  PIN o_d[97]
    DIRECTION OUTPUT ;
    USE SIGNAL ;
    PORT
      LAYER M4 ;
        RECT  0 20.304 0.192 20.328 ;
    END
  END o_d[97]
  PIN o_d[98]
    DIRECTION OUTPUT ;
    USE SIGNAL ;
    PORT
      LAYER M4 ;
        RECT  0 20.448 0.192 20.472 ;
    END
  END o_d[98]
  PIN o_d[99]
    DIRECTION OUTPUT ;
    USE SIGNAL ;
    PORT
      LAYER M4 ;
        RECT  0 20.592 0.192 20.616 ;
    END
  END o_d[99]
  PIN o_d[9]
    DIRECTION OUTPUT ;
    USE SIGNAL ;
    PORT
      LAYER M4 ;
        RECT  0 5.76 0.192 5.784 ;
    END
  END o_d[9]
  PIN o_row[0]
    DIRECTION OUTPUT ;
    USE SIGNAL ;
    PORT
      LAYER M4 ;
        RECT  0 88.416 0.192 88.44 ;
    END
  END o_row[0]
  PIN o_row[10]
    DIRECTION OUTPUT ;
    USE SIGNAL ;
    PORT
      LAYER M4 ;
        RECT  0 90.144 0.192 90.168 ;
    END
  END o_row[10]
  PIN o_row[11]
    DIRECTION OUTPUT ;
    USE SIGNAL ;
    PORT
      LAYER M4 ;
        RECT  0 90.288 0.192 90.312 ;
    END
  END o_row[11]
  PIN o_row[12]
    DIRECTION OUTPUT ;
    USE SIGNAL ;
    PORT
      LAYER M4 ;
        RECT  0 90.432 0.192 90.456 ;
    END
  END o_row[12]
  PIN o_row[13]
    DIRECTION OUTPUT ;
    USE SIGNAL ;
    PORT
      LAYER M4 ;
        RECT  0 90.576 0.192 90.6 ;
    END
  END o_row[13]
  PIN o_row[1]
    DIRECTION OUTPUT ;
    USE SIGNAL ;
    PORT
      LAYER M4 ;
        RECT  0 88.56 0.192 88.584 ;
    END
  END o_row[1]
  PIN o_row[2]
    DIRECTION OUTPUT ;
    USE SIGNAL ;
    PORT
      LAYER M4 ;
        RECT  0 88.704 0.192 88.728 ;
    END
  END o_row[2]
  PIN o_row[3]
    DIRECTION OUTPUT ;
    USE SIGNAL ;
    PORT
      LAYER M4 ;
        RECT  0 88.992 0.192 89.016 ;
    END
  END o_row[3]
  PIN o_row[4]
    DIRECTION OUTPUT ;
    USE SIGNAL ;
    PORT
      LAYER M4 ;
        RECT  0 89.136 0.192 89.16 ;
    END
  END o_row[4]
  PIN o_row[5]
    DIRECTION OUTPUT ;
    USE SIGNAL ;
    PORT
      LAYER M4 ;
        RECT  0 89.28 0.192 89.304 ;
    END
  END o_row[5]
  PIN o_row[6]
    DIRECTION OUTPUT ;
    USE SIGNAL ;
    PORT
      LAYER M4 ;
        RECT  0 89.424 0.192 89.448 ;
    END
  END o_row[6]
  PIN o_row[7]
    DIRECTION OUTPUT ;
    USE SIGNAL ;
    PORT
      LAYER M4 ;
        RECT  0 89.568 0.192 89.592 ;
    END
  END o_row[7]
  PIN o_row[8]
    DIRECTION OUTPUT ;
    USE SIGNAL ;
    PORT
      LAYER M4 ;
        RECT  0 89.712 0.192 89.736 ;
    END
  END o_row[8]
  PIN o_row[9]
    DIRECTION OUTPUT ;
    USE SIGNAL ;
    PORT
      LAYER M4 ;
        RECT  0 89.856 0.192 89.88 ;
    END
  END o_row[9]
  PIN o_v
    DIRECTION OUTPUT ;
    USE SIGNAL ;
    PORT
      LAYER M4 ;
        RECT  0 88.272 0.192 88.296 ;
    END
  END o_v
  PIN rst_n
    DIRECTION INPUT ;
    USE SIGNAL ;
    PORT
      LAYER M5 ;
        RECT  10.176 94.848 10.2 95.04 ;
    END
    PORT
      LAYER M5 ;
        RECT  10.176 92.821 10.2 94.864 ;
    END
  END rst_n
  PIN VDD
    DIRECTION INOUT ;
    USE POWER ;
    PORT
      LAYER M5 ;
        RECT  88.992 2.151 89.112 92.889 ;
        RECT  83.592 2.151 83.712 92.889 ;
        RECT  78.192 2.151 78.312 92.889 ;
        RECT  72.792 2.151 72.912 92.889 ;
        RECT  67.392 2.151 67.512 92.889 ;
        RECT  61.992 2.151 62.112 92.889 ;
        RECT  56.592 2.151 56.712 92.889 ;
        RECT  51.192 2.151 51.312 92.889 ;
        RECT  45.792 2.151 45.912 92.889 ;
        RECT  40.392 2.151 40.512 92.889 ;
        RECT  34.992 2.151 35.112 92.889 ;
        RECT  29.592 2.151 29.712 92.889 ;
        RECT  24.192 2.151 24.312 92.889 ;
        RECT  18.792 2.151 18.912 92.889 ;
        RECT  13.392 2.151 13.512 92.889 ;
        RECT  7.992 2.151 8.112 92.889 ;
        RECT  2.592 2.151 2.712 92.889 ;
    END
  END VDD
  PIN VSS
    DIRECTION INOUT ;
    USE GROUND ;
    PORT
      LAYER M5 ;
        RECT  88.8 2.137 88.92 92.903 ;
        RECT  83.4 2.137 83.52 92.903 ;
        RECT  78 2.137 78.12 92.903 ;
        RECT  72.6 2.137 72.72 92.903 ;
        RECT  67.2 2.137 67.32 92.903 ;
        RECT  61.8 2.137 61.92 92.903 ;
        RECT  56.4 2.137 56.52 92.903 ;
        RECT  51 2.137 51.12 92.903 ;
        RECT  45.6 2.137 45.72 92.903 ;
        RECT  40.2 2.137 40.32 92.903 ;
        RECT  34.8 2.137 34.92 92.903 ;
        RECT  29.4 2.137 29.52 92.903 ;
        RECT  24 2.137 24.12 92.903 ;
        RECT  18.6 2.137 18.72 92.903 ;
        RECT  13.2 2.137 13.32 92.903 ;
        RECT  7.8 2.137 7.92 92.903 ;
        RECT  2.4 2.137 2.52 92.903 ;
    END
  END VSS
  # OT_OBS_CLOSED layer=M5 d_um=1.536 added=119
  OBS
    LAYER RVTN ;
     RECT  2.16 2.16 92.88 2.295 ;
     RECT  2.16 2.565 92.88 2.835 ;
     RECT  2.16 3.105 92.88 3.375 ;
     RECT  2.16 3.645 92.88 3.915 ;
     RECT  2.16 4.185 92.88 4.455 ;
     RECT  2.16 4.725 92.88 4.995 ;
     RECT  2.16 5.265 92.88 5.535 ;
     RECT  2.16 5.805 92.88 6.075 ;
     RECT  2.16 6.345 92.88 6.615 ;
     RECT  2.16 6.885 92.88 7.155 ;
     RECT  2.16 7.425 92.88 7.695 ;
     RECT  2.16 7.965 92.88 8.235 ;
     RECT  2.16 8.505 92.88 8.775 ;
     RECT  2.16 9.045 92.88 9.315 ;
     RECT  2.16 9.585 92.88 9.855 ;
     RECT  2.16 10.125 92.88 10.395 ;
     RECT  2.16 10.665 92.88 10.935 ;
     RECT  2.16 11.205 92.88 11.475 ;
     RECT  2.16 11.745 92.88 12.015 ;
     RECT  2.16 12.285 92.88 12.555 ;
     RECT  2.16 12.825 92.88 13.095 ;
     RECT  2.16 13.365 92.88 13.635 ;
     RECT  2.16 13.905 92.88 14.175 ;
     RECT  2.16 14.445 92.88 14.715 ;
     RECT  2.16 14.985 92.88 15.255 ;
     RECT  2.16 15.525 92.88 15.795 ;
     RECT  2.16 16.065 92.88 16.335 ;
     RECT  2.16 16.605 92.88 16.875 ;
     RECT  2.16 17.145 92.88 17.415 ;
     RECT  2.16 17.685 92.88 17.955 ;
     RECT  2.16 18.225 92.88 18.495 ;
     RECT  2.16 18.765 92.88 19.035 ;
     RECT  2.16 19.305 92.88 19.575 ;
     RECT  2.16 19.845 92.88 20.115 ;
     RECT  2.16 20.385 92.88 20.655 ;
     RECT  2.16 20.925 92.88 21.195 ;
     RECT  2.16 21.465 92.88 21.735 ;
     RECT  2.16 22.005 92.88 22.275 ;
     RECT  2.16 22.545 92.88 22.815 ;
     RECT  2.16 23.085 92.88 23.355 ;
     RECT  2.16 23.625 92.88 23.895 ;
     RECT  2.16 24.165 92.88 24.435 ;
     RECT  2.16 24.705 92.88 24.975 ;
     RECT  2.16 25.245 92.88 25.515 ;
     RECT  2.16 25.785 92.88 26.055 ;
     RECT  2.16 26.325 92.88 26.595 ;
     RECT  2.16 26.865 92.88 27.135 ;
     RECT  2.16 27.405 92.88 27.675 ;
     RECT  2.16 27.945 92.88 28.215 ;
     RECT  2.16 28.485 92.88 28.755 ;
     RECT  2.16 29.025 92.88 29.295 ;
     RECT  2.16 29.565 92.88 29.835 ;
     RECT  2.16 30.105 92.88 30.375 ;
     RECT  2.16 30.645 92.88 30.915 ;
     RECT  2.16 31.185 92.88 31.455 ;
     RECT  2.16 31.725 92.88 31.995 ;
     RECT  2.16 32.265 92.88 32.535 ;
     RECT  2.16 32.805 92.88 33.075 ;
     RECT  2.16 33.345 92.88 33.615 ;
     RECT  2.16 33.885 92.88 34.155 ;
     RECT  2.16 34.425 92.88 34.695 ;
     RECT  2.16 34.965 92.88 35.235 ;
     RECT  2.16 35.505 92.88 35.775 ;
     RECT  2.16 36.045 92.88 36.315 ;
     RECT  2.16 36.585 92.88 36.855 ;
     RECT  2.16 37.125 92.88 37.395 ;
     RECT  2.16 37.665 92.88 37.935 ;
     RECT  2.16 38.205 92.88 38.475 ;
     RECT  2.16 38.745 92.88 39.015 ;
     RECT  2.16 39.285 92.88 39.555 ;
     RECT  2.16 39.825 92.88 40.095 ;
     RECT  2.16 40.365 92.88 40.635 ;
     RECT  2.16 40.905 92.88 41.175 ;
     RECT  2.16 41.445 92.88 41.715 ;
     RECT  2.16 41.985 92.88 42.255 ;
     RECT  2.16 42.525 92.88 42.795 ;
     RECT  2.16 43.065 92.88 43.335 ;
     RECT  2.16 43.605 92.88 43.875 ;
     RECT  2.16 44.145 92.88 44.415 ;
     RECT  2.16 44.685 92.88 44.955 ;
     RECT  2.16 45.225 92.88 45.495 ;
     RECT  2.16 45.765 92.88 46.035 ;
     RECT  2.16 46.305 92.88 46.575 ;
     RECT  2.16 46.845 92.88 47.115 ;
     RECT  2.16 47.385 92.88 47.655 ;
     RECT  2.16 47.925 92.88 48.195 ;
     RECT  2.16 48.465 92.88 48.735 ;
     RECT  2.16 49.005 92.88 49.275 ;
     RECT  2.16 49.545 92.88 49.815 ;
     RECT  2.16 50.085 92.88 50.355 ;
     RECT  2.16 50.625 92.88 50.895 ;
     RECT  2.16 51.165 92.88 51.435 ;
     RECT  2.16 51.705 92.88 51.975 ;
     RECT  2.16 52.245 92.88 52.515 ;
     RECT  2.16 52.785 92.88 53.055 ;
     RECT  2.16 53.325 92.88 53.595 ;
     RECT  2.16 53.865 92.88 54.135 ;
     RECT  2.16 54.405 92.88 54.675 ;
     RECT  2.16 54.945 92.88 55.215 ;
     RECT  2.16 55.485 92.88 55.755 ;
     RECT  2.16 56.025 92.88 56.295 ;
     RECT  2.16 56.565 92.88 56.835 ;
     RECT  2.16 57.105 92.88 57.375 ;
     RECT  2.16 57.645 92.88 57.915 ;
     RECT  2.16 58.185 92.88 58.455 ;
     RECT  2.16 58.725 92.88 58.995 ;
     RECT  2.16 59.265 92.88 59.535 ;
     RECT  2.16 59.805 92.88 60.075 ;
     RECT  2.16 60.345 92.88 60.615 ;
     RECT  2.16 60.885 92.88 61.155 ;
     RECT  2.16 61.425 92.88 61.695 ;
     RECT  2.16 61.965 92.88 62.235 ;
     RECT  2.16 62.505 92.88 62.775 ;
     RECT  2.16 63.045 92.88 63.315 ;
     RECT  2.16 63.585 92.88 63.855 ;
     RECT  2.16 64.125 92.88 64.395 ;
     RECT  2.16 64.665 92.88 64.935 ;
     RECT  2.16 65.205 92.88 65.475 ;
     RECT  2.16 65.745 92.88 66.015 ;
     RECT  2.16 66.285 92.88 66.555 ;
     RECT  2.16 66.825 92.88 67.095 ;
     RECT  2.16 67.365 92.88 67.635 ;
     RECT  2.16 67.905 92.88 68.175 ;
     RECT  2.16 68.445 92.88 68.715 ;
     RECT  2.16 68.985 92.88 69.255 ;
     RECT  2.16 69.525 92.88 69.795 ;
     RECT  2.16 70.065 92.88 70.335 ;
     RECT  2.16 70.605 92.88 70.875 ;
     RECT  2.16 71.145 92.88 71.415 ;
     RECT  2.16 71.685 92.88 71.955 ;
     RECT  2.16 72.225 92.88 72.495 ;
     RECT  2.16 72.765 92.88 73.035 ;
     RECT  2.16 73.305 92.88 73.575 ;
     RECT  2.16 73.845 92.88 74.115 ;
     RECT  2.16 74.385 92.88 74.655 ;
     RECT  2.16 74.925 92.88 75.195 ;
     RECT  2.16 75.465 92.88 75.735 ;
     RECT  2.16 76.005 92.88 76.275 ;
     RECT  2.16 76.545 92.88 76.815 ;
     RECT  2.16 77.085 92.88 77.355 ;
     RECT  2.16 77.625 92.88 77.895 ;
     RECT  2.16 78.165 92.88 78.435 ;
     RECT  2.16 78.705 92.88 78.975 ;
     RECT  2.16 79.245 92.88 79.515 ;
     RECT  2.16 79.785 92.88 80.055 ;
     RECT  2.16 80.325 92.88 80.595 ;
     RECT  2.16 80.865 92.88 81.135 ;
     RECT  2.16 81.405 92.88 81.675 ;
     RECT  2.16 81.945 92.88 82.215 ;
     RECT  2.16 82.485 92.88 82.755 ;
     RECT  2.16 83.025 92.88 83.295 ;
     RECT  2.16 83.565 92.88 83.835 ;
     RECT  2.16 84.105 92.88 84.375 ;
     RECT  2.16 84.645 92.88 84.915 ;
     RECT  2.16 85.185 92.88 85.455 ;
     RECT  2.16 85.725 92.88 85.995 ;
     RECT  2.16 86.265 92.88 86.535 ;
     RECT  2.16 86.805 92.88 87.075 ;
     RECT  2.16 87.345 92.88 87.615 ;
     RECT  2.16 87.885 92.88 88.155 ;
     RECT  2.16 88.425 92.88 88.695 ;
     RECT  2.16 88.965 92.88 89.235 ;
     RECT  2.16 89.505 92.88 89.775 ;
     RECT  2.16 90.045 92.88 90.315 ;
     RECT  2.16 90.585 92.88 90.855 ;
     RECT  2.16 91.125 92.88 91.395 ;
     RECT  2.16 91.665 92.88 91.935 ;
     RECT  2.16 92.205 92.88 92.475 ;
     RECT  2.16 92.745 92.88 92.88 ;
    LAYER RVTP ;
     RECT  2.16 2.295 92.88 2.565 ;
     RECT  2.16 2.835 92.88 3.105 ;
     RECT  2.16 3.375 92.88 3.645 ;
     RECT  2.16 3.915 92.88 4.185 ;
     RECT  2.16 4.455 92.88 4.725 ;
     RECT  2.16 4.995 92.88 5.265 ;
     RECT  2.16 5.535 92.88 5.805 ;
     RECT  2.16 6.075 92.88 6.345 ;
     RECT  2.16 6.615 92.88 6.885 ;
     RECT  2.16 7.155 92.88 7.425 ;
     RECT  2.16 7.695 92.88 7.965 ;
     RECT  2.16 8.235 92.88 8.505 ;
     RECT  2.16 8.775 92.88 9.045 ;
     RECT  2.16 9.315 92.88 9.585 ;
     RECT  2.16 9.855 92.88 10.125 ;
     RECT  2.16 10.395 92.88 10.665 ;
     RECT  2.16 10.935 92.88 11.205 ;
     RECT  2.16 11.475 92.88 11.745 ;
     RECT  2.16 12.015 92.88 12.285 ;
     RECT  2.16 12.555 92.88 12.825 ;
     RECT  2.16 13.095 92.88 13.365 ;
     RECT  2.16 13.635 92.88 13.905 ;
     RECT  2.16 14.175 92.88 14.445 ;
     RECT  2.16 14.715 92.88 14.985 ;
     RECT  2.16 15.255 92.88 15.525 ;
     RECT  2.16 15.795 92.88 16.065 ;
     RECT  2.16 16.335 92.88 16.605 ;
     RECT  2.16 16.875 92.88 17.145 ;
     RECT  2.16 17.415 92.88 17.685 ;
     RECT  2.16 17.955 92.88 18.225 ;
     RECT  2.16 18.495 92.88 18.765 ;
     RECT  2.16 19.035 92.88 19.305 ;
     RECT  2.16 19.575 92.88 19.845 ;
     RECT  2.16 20.115 92.88 20.385 ;
     RECT  2.16 20.655 92.88 20.925 ;
     RECT  2.16 21.195 92.88 21.465 ;
     RECT  2.16 21.735 92.88 22.005 ;
     RECT  2.16 22.275 92.88 22.545 ;
     RECT  2.16 22.815 92.88 23.085 ;
     RECT  2.16 23.355 92.88 23.625 ;
     RECT  2.16 23.895 92.88 24.165 ;
     RECT  2.16 24.435 92.88 24.705 ;
     RECT  2.16 24.975 92.88 25.245 ;
     RECT  2.16 25.515 92.88 25.785 ;
     RECT  2.16 26.055 92.88 26.325 ;
     RECT  2.16 26.595 92.88 26.865 ;
     RECT  2.16 27.135 92.88 27.405 ;
     RECT  2.16 27.675 92.88 27.945 ;
     RECT  2.16 28.215 92.88 28.485 ;
     RECT  2.16 28.755 92.88 29.025 ;
     RECT  2.16 29.295 92.88 29.565 ;
     RECT  2.16 29.835 92.88 30.105 ;
     RECT  2.16 30.375 92.88 30.645 ;
     RECT  2.16 30.915 92.88 31.185 ;
     RECT  2.16 31.455 92.88 31.725 ;
     RECT  2.16 31.995 92.88 32.265 ;
     RECT  2.16 32.535 92.88 32.805 ;
     RECT  2.16 33.075 92.88 33.345 ;
     RECT  2.16 33.615 92.88 33.885 ;
     RECT  2.16 34.155 92.88 34.425 ;
     RECT  2.16 34.695 92.88 34.965 ;
     RECT  2.16 35.235 92.88 35.505 ;
     RECT  2.16 35.775 92.88 36.045 ;
     RECT  2.16 36.315 92.88 36.585 ;
     RECT  2.16 36.855 92.88 37.125 ;
     RECT  2.16 37.395 92.88 37.665 ;
     RECT  2.16 37.935 92.88 38.205 ;
     RECT  2.16 38.475 92.88 38.745 ;
     RECT  2.16 39.015 92.88 39.285 ;
     RECT  2.16 39.555 92.88 39.825 ;
     RECT  2.16 40.095 92.88 40.365 ;
     RECT  2.16 40.635 92.88 40.905 ;
     RECT  2.16 41.175 92.88 41.445 ;
     RECT  2.16 41.715 92.88 41.985 ;
     RECT  2.16 42.255 92.88 42.525 ;
     RECT  2.16 42.795 92.88 43.065 ;
     RECT  2.16 43.335 92.88 43.605 ;
     RECT  2.16 43.875 92.88 44.145 ;
     RECT  2.16 44.415 92.88 44.685 ;
     RECT  2.16 44.955 92.88 45.225 ;
     RECT  2.16 45.495 92.88 45.765 ;
     RECT  2.16 46.035 92.88 46.305 ;
     RECT  2.16 46.575 92.88 46.845 ;
     RECT  2.16 47.115 92.88 47.385 ;
     RECT  2.16 47.655 92.88 47.925 ;
     RECT  2.16 48.195 92.88 48.465 ;
     RECT  2.16 48.735 92.88 49.005 ;
     RECT  2.16 49.275 92.88 49.545 ;
     RECT  2.16 49.815 92.88 50.085 ;
     RECT  2.16 50.355 92.88 50.625 ;
     RECT  2.16 50.895 92.88 51.165 ;
     RECT  2.16 51.435 92.88 51.705 ;
     RECT  2.16 51.975 92.88 52.245 ;
     RECT  2.16 52.515 92.88 52.785 ;
     RECT  2.16 53.055 92.88 53.325 ;
     RECT  2.16 53.595 92.88 53.865 ;
     RECT  2.16 54.135 92.88 54.405 ;
     RECT  2.16 54.675 92.88 54.945 ;
     RECT  2.16 55.215 92.88 55.485 ;
     RECT  2.16 55.755 92.88 56.025 ;
     RECT  2.16 56.295 92.88 56.565 ;
     RECT  2.16 56.835 92.88 57.105 ;
     RECT  2.16 57.375 92.88 57.645 ;
     RECT  2.16 57.915 92.88 58.185 ;
     RECT  2.16 58.455 92.88 58.725 ;
     RECT  2.16 58.995 92.88 59.265 ;
     RECT  2.16 59.535 92.88 59.805 ;
     RECT  2.16 60.075 92.88 60.345 ;
     RECT  2.16 60.615 92.88 60.885 ;
     RECT  2.16 61.155 92.88 61.425 ;
     RECT  2.16 61.695 92.88 61.965 ;
     RECT  2.16 62.235 92.88 62.505 ;
     RECT  2.16 62.775 92.88 63.045 ;
     RECT  2.16 63.315 92.88 63.585 ;
     RECT  2.16 63.855 92.88 64.125 ;
     RECT  2.16 64.395 92.88 64.665 ;
     RECT  2.16 64.935 92.88 65.205 ;
     RECT  2.16 65.475 92.88 65.745 ;
     RECT  2.16 66.015 92.88 66.285 ;
     RECT  2.16 66.555 92.88 66.825 ;
     RECT  2.16 67.095 92.88 67.365 ;
     RECT  2.16 67.635 92.88 67.905 ;
     RECT  2.16 68.175 92.88 68.445 ;
     RECT  2.16 68.715 92.88 68.985 ;
     RECT  2.16 69.255 92.88 69.525 ;
     RECT  2.16 69.795 92.88 70.065 ;
     RECT  2.16 70.335 92.88 70.605 ;
     RECT  2.16 70.875 92.88 71.145 ;
     RECT  2.16 71.415 92.88 71.685 ;
     RECT  2.16 71.955 92.88 72.225 ;
     RECT  2.16 72.495 92.88 72.765 ;
     RECT  2.16 73.035 92.88 73.305 ;
     RECT  2.16 73.575 92.88 73.845 ;
     RECT  2.16 74.115 92.88 74.385 ;
     RECT  2.16 74.655 92.88 74.925 ;
     RECT  2.16 75.195 92.88 75.465 ;
     RECT  2.16 75.735 92.88 76.005 ;
     RECT  2.16 76.275 92.88 76.545 ;
     RECT  2.16 76.815 92.88 77.085 ;
     RECT  2.16 77.355 92.88 77.625 ;
     RECT  2.16 77.895 92.88 78.165 ;
     RECT  2.16 78.435 92.88 78.705 ;
     RECT  2.16 78.975 92.88 79.245 ;
     RECT  2.16 79.515 92.88 79.785 ;
     RECT  2.16 80.055 92.88 80.325 ;
     RECT  2.16 80.595 92.88 80.865 ;
     RECT  2.16 81.135 92.88 81.405 ;
     RECT  2.16 81.675 92.88 81.945 ;
     RECT  2.16 82.215 92.88 82.485 ;
     RECT  2.16 82.755 92.88 83.025 ;
     RECT  2.16 83.295 92.88 83.565 ;
     RECT  2.16 83.835 92.88 84.105 ;
     RECT  2.16 84.375 92.88 84.645 ;
     RECT  2.16 84.915 92.88 85.185 ;
     RECT  2.16 85.455 92.88 85.725 ;
     RECT  2.16 85.995 92.88 86.265 ;
     RECT  2.16 86.535 92.88 86.805 ;
     RECT  2.16 87.075 92.88 87.345 ;
     RECT  2.16 87.615 92.88 87.885 ;
     RECT  2.16 88.155 92.88 88.425 ;
     RECT  2.16 88.695 92.88 88.965 ;
     RECT  2.16 89.235 92.88 89.505 ;
     RECT  2.16 89.775 92.88 90.045 ;
     RECT  2.16 90.315 92.88 90.585 ;
     RECT  2.16 90.855 92.88 91.125 ;
     RECT  2.16 91.395 92.88 91.665 ;
     RECT  2.16 91.935 92.88 92.205 ;
     RECT  2.16 92.475 92.88 92.745 ;
    LAYER M1 ;
     RECT  2.16 2.151 92.88 92.889 ;
    LAYER M2 ;
     RECT  0.211 76.896 0.283 76.914 ;
     RECT  0.283 76.788 0.311 76.914 ;
     RECT  0.247 18.846 0.347 18.864 ;
     RECT  0.247 33.966 0.347 33.984 ;
     RECT  0.211 37.908 0.347 37.926 ;
     RECT  0.311 76.788 0.383 76.806 ;
     RECT  0.283 4.194 0.463 4.212 ;
     RECT  0.463 4.194 0.499 4.482 ;
     RECT  0.499 3.654 0.535 4.482 ;
     RECT  0.211 81.954 0.535 81.972 ;
     RECT  0.535 3.654 2.16 4.554 ;
     RECT  0.535 6.084 2.16 6.102 ;
     RECT  0.535 11.754 2.16 12.348 ;
     RECT  0.535 16.506 2.16 16.524 ;
     RECT  0.535 17.424 2.16 17.442 ;
     RECT  2.083 40.338 2.16 40.356 ;
     RECT  0.211 51.246 2.16 51.264 ;
     RECT  0.535 57.546 2.16 57.564 ;
     RECT  0.535 81.45 2.16 81.972 ;
     RECT  1.147 90.396 2.16 90.414 ;
     RECT  1.435 92.484 2.16 92.502 ;
     RECT  2.16 2.151 92.88 92.889 ;
     RECT  92.88 4.23 92.939 91.116 ;
     RECT  92.939 4.77 92.975 20.952 ;
     RECT  92.939 32.238 92.975 57.636 ;
     RECT  92.939 58.5 92.975 59.796 ;
     RECT  92.939 60.588 92.975 65.502 ;
     RECT  92.939 75.438 92.975 91.116 ;
     RECT  92.975 6.588 93.011 11.736 ;
     RECT  92.975 12.528 93.011 17.946 ;
     RECT  92.975 45.27 93.011 51.696 ;
     RECT  92.975 52.488 93.011 56.628 ;
     RECT  92.975 4.77 93.515 5.832 ;
     RECT  93.011 6.696 93.515 11.736 ;
     RECT  93.011 12.528 93.515 13.896 ;
     RECT  93.011 15.03 93.515 17.946 ;
     RECT  92.975 18.702 93.515 18.72 ;
     RECT  92.975 19.548 93.515 20.916 ;
     RECT  92.939 21.78 93.515 30.978 ;
     RECT  92.975 32.238 93.515 33.03 ;
     RECT  92.975 33.858 93.515 36.576 ;
     RECT  92.975 37.44 93.515 43.326 ;
     RECT  92.975 44.118 93.515 44.406 ;
     RECT  93.011 45.27 93.515 49.536 ;
     RECT  93.011 50.4 93.515 51.696 ;
     RECT  93.011 52.488 93.515 56.556 ;
     RECT  92.975 57.42 93.515 57.636 ;
     RECT  92.975 58.698 93.515 59.796 ;
     RECT  92.975 60.588 93.515 63.648 ;
     RECT  92.975 64.638 93.515 65.502 ;
     RECT  92.939 66.258 93.515 74.646 ;
     RECT  92.975 75.438 93.515 78.156 ;
     RECT  92.975 79.02 93.515 80.856 ;
     RECT  92.975 81.99 93.515 88.416 ;
     RECT  92.975 89.208 93.515 89.874 ;
     RECT  92.975 90.828 93.515 91.116 ;
     RECT  93.515 7.128 93.551 10.188 ;
     RECT  93.515 11.25 93.551 11.268 ;
     RECT  93.515 13.176 93.551 13.626 ;
     RECT  93.515 15.228 93.551 15.246 ;
     RECT  93.515 16.65 93.551 17.478 ;
     RECT  93.515 20.088 93.551 20.106 ;
     RECT  93.515 23.058 93.551 23.076 ;
     RECT  93.515 24.174 93.551 24.426 ;
     RECT  93.515 35.208 93.551 35.226 ;
     RECT  93.515 37.602 93.551 38.736 ;
     RECT  93.515 40.14 93.551 40.356 ;
     RECT  93.515 41.22 93.551 42.75 ;
     RECT  93.515 45.81 93.551 46.026 ;
     RECT  93.515 48.708 93.551 48.726 ;
     RECT  93.515 50.598 93.551 50.616 ;
     RECT  93.515 59.58 93.551 59.598 ;
     RECT  93.515 60.93 93.551 60.948 ;
     RECT  93.515 61.974 93.551 62.298 ;
     RECT  93.515 67.608 93.551 68.166 ;
     RECT  93.515 69.498 93.551 69.516 ;
     RECT  93.515 70.884 93.551 71.676 ;
     RECT  93.515 73.278 93.551 73.872 ;
     RECT  93.515 75.438 93.551 75.996 ;
     RECT  93.515 84.15 93.551 84.906 ;
     RECT  93.515 85.968 93.551 85.986 ;
     RECT  93.515 87.048 93.551 87.336 ;
     RECT  93.551 87.318 93.587 87.336 ;
     RECT  93.515 5.814 94.091 5.832 ;
     RECT  93.551 9.054 94.091 9.072 ;
     RECT  93.551 9.864 94.091 9.882 ;
     RECT  93.551 13.176 94.091 13.194 ;
     RECT  93.551 17.46 94.091 17.478 ;
     RECT  93.551 24.174 94.091 24.192 ;
     RECT  93.515 25.254 94.091 25.272 ;
     RECT  93.515 26.568 94.091 26.586 ;
     RECT  93.515 27.648 94.091 28.206 ;
     RECT  93.515 32.274 94.091 32.292 ;
     RECT  93.515 34.434 94.091 34.452 ;
     RECT  93.515 36.36 94.091 36.378 ;
     RECT  93.551 37.602 94.091 37.62 ;
     RECT  93.551 40.338 94.091 40.356 ;
     RECT  93.551 41.76 94.091 42.75 ;
     RECT  93.551 45.81 94.091 45.828 ;
     RECT  93.515 46.854 94.091 47.448 ;
     RECT  93.551 61.974 94.091 61.992 ;
     RECT  93.515 65.484 94.091 65.502 ;
     RECT  93.515 66.798 94.091 66.816 ;
     RECT  93.551 70.884 94.091 71.442 ;
     RECT  93.551 73.818 94.091 73.872 ;
     RECT  93.551 75.438 94.091 75.456 ;
     RECT  93.515 77.904 94.091 77.922 ;
     RECT  93.515 82.764 94.091 82.782 ;
     RECT  93.515 88.164 94.091 88.182 ;
     RECT  93.515 89.28 94.091 89.298 ;
     RECT  93.515 91.098 94.091 91.116 ;
     RECT  94.091 73.854 94.163 73.872 ;
    LAYER M3 ;
     RECT  18.936 0.523 18.954 2.143 ;
     RECT  47.772 2.191 47.79 2.227 ;
     RECT  76.824 0.187 76.842 2.227 ;
     RECT  19.692 2.191 20.25 2.291 ;
     RECT  47.556 2.227 47.79 2.291 ;
     RECT  47.556 2.291 47.754 2.299 ;
     RECT  18.615 2.143 18.954 2.371 ;
     RECT  2.415 2.143 2.505 2.413 ;
     RECT  7.815 2.143 7.905 2.413 ;
     RECT  13.215 2.143 13.305 2.413 ;
     RECT  24.015 2.143 24.105 2.413 ;
     RECT  29.415 2.143 29.505 2.413 ;
     RECT  34.815 2.143 34.905 2.413 ;
     RECT  40.215 2.143 40.305 2.413 ;
     RECT  45.615 2.143 45.705 2.413 ;
     RECT  51.015 2.143 51.105 2.413 ;
     RECT  56.415 2.143 56.505 2.413 ;
     RECT  61.815 2.143 61.905 2.413 ;
     RECT  67.215 2.143 67.305 2.413 ;
     RECT  72.615 2.143 72.705 2.413 ;
     RECT  78.015 2.143 78.105 2.413 ;
     RECT  83.415 2.143 83.505 2.413 ;
     RECT  88.815 2.143 88.905 2.413 ;
     RECT  47.52 2.299 47.754 2.489 ;
     RECT  76.392 2.227 76.842 2.489 ;
     RECT  76.392 2.489 76.734 2.525 ;
     RECT  76.248 2.641 76.266 2.731 ;
     RECT  47.556 2.489 47.754 2.759 ;
     RECT  76.176 2.731 76.266 2.759 ;
     RECT  47.556 2.759 47.61 2.795 ;
     RECT  20.232 2.291 20.25 3.029 ;
     RECT  18.615 2.371 19.242 3.037 ;
     RECT  18.615 3.037 19.746 3.101 ;
     RECT  45.615 2.413 45.897 3.271 ;
     RECT  47.556 2.795 47.574 3.299 ;
     RECT  2.415 2.413 2.697 3.577 ;
     RECT  2.415 3.577 3.366 3.685 ;
     RECT  0.504 3.649 0.522 3.721 ;
     RECT  76.176 2.759 76.194 3.839 ;
     RECT  75.564 3.883 75.582 3.931 ;
     RECT  75.42 3.931 75.582 3.983 ;
     RECT  0.504 3.721 0.558 4.189 ;
     RECT  45.615 3.271 46.566 4.261 ;
     RECT  92.916 4.225 92.934 4.349 ;
     RECT  45.615 4.261 46.854 4.379 ;
     RECT  91.152 4.261 91.17 4.379 ;
     RECT  88.815 2.413 89.097 4.387 ;
     RECT  92.016 4.261 92.034 4.603 ;
     RECT  88.815 4.387 89.442 4.621 ;
     RECT  2.304 3.685 3.366 4.693 ;
     RECT  86.724 4.693 86.742 4.729 ;
     RECT  2.304 4.693 3.438 4.765 ;
     RECT  4.212 4.423 4.23 4.765 ;
     RECT  88.488 4.621 89.91 4.765 ;
     RECT  90.648 4.693 90.702 4.765 ;
     RECT  0.288 4.189 0.558 4.781 ;
     RECT  5.292 4.729 5.31 4.795 ;
     RECT  5.076 4.795 5.31 4.801 ;
     RECT  6.84 4.765 6.858 4.801 ;
     RECT  7.815 2.413 8.097 4.801 ;
     RECT  42.768 4.351 42.786 4.801 ;
     RECT  5.076 4.801 5.49 4.891 ;
     RECT  42.768 4.801 42.822 4.919 ;
     RECT  86.724 4.729 86.814 4.927 ;
     RECT  6.84 4.801 8.097 4.939 ;
     RECT  92.016 4.603 92.358 4.963 ;
     RECT  45.615 4.379 46.602 4.991 ;
     RECT  82.656 4.801 82.674 4.991 ;
     RECT  42.804 4.919 42.822 5.027 ;
     RECT  88.488 4.765 90.702 5.027 ;
     RECT  86.616 4.927 86.814 5.035 ;
     RECT  86.616 5.035 87.246 5.063 ;
     RECT  0.288 4.781 0.486 5.069 ;
     RECT  2.304 4.765 4.23 5.083 ;
     RECT  5.076 4.891 5.742 5.083 ;
     RECT  85.788 5.035 85.806 5.117 ;
     RECT  91.764 4.963 92.358 5.179 ;
     RECT  93.492 4.459 93.51 5.179 ;
     RECT  87.048 5.063 87.246 5.189 ;
     RECT  88.524 5.027 90.702 5.305 ;
     RECT  91.764 5.179 93.51 5.323 ;
     RECT  2.304 5.083 5.742 5.341 ;
     RECT  6.48 4.939 8.097 5.341 ;
     RECT  47.34 5.305 47.358 5.341 ;
     RECT  91.764 5.323 94.086 5.341 ;
     RECT  0.288 5.069 0.306 5.357 ;
     RECT  88.524 5.305 90.81 5.431 ;
     RECT  2.304 5.341 8.097 5.461 ;
     RECT  51.015 2.413 51.297 5.467 ;
     RECT  2.304 5.461 8.37 5.501 ;
     RECT  88.524 5.431 90.882 5.503 ;
     RECT  91.728 5.341 94.086 5.503 ;
     RECT  88.524 5.503 94.086 5.504 ;
     RECT  9.216 5.431 9.306 5.549 ;
     RECT  47.34 5.341 47.718 5.603 ;
     RECT  50.688 5.467 51.297 5.639 ;
     RECT  0.252 5.515 0.27 5.645 ;
     RECT  90.036 5.504 94.086 5.801 ;
     RECT  94.068 5.801 94.086 5.837 ;
     RECT  47.7 5.603 47.718 5.845 ;
     RECT  2.304 5.501 8.19 5.933 ;
     RECT  83.415 2.413 83.697 5.971 ;
     RECT  47.7 5.845 48.042 5.999 ;
     RECT  82.98 5.971 83.697 6.007 ;
     RECT  82.656 6.007 83.697 6.029 ;
     RECT  90.036 5.801 93.006 6.035 ;
     RECT  87.048 5.189 87.066 6.043 ;
     RECT  82.656 6.029 82.674 6.107 ;
     RECT  84.6 6.007 84.618 6.107 ;
     RECT  87.048 6.043 87.75 6.115 ;
     RECT  86.724 6.115 87.75 6.151 ;
     RECT  88.524 5.504 89.097 6.151 ;
     RECT  2.34 5.933 8.19 6.235 ;
     RECT  9.036 6.139 9.054 6.235 ;
     RECT  2.34 6.235 9.054 6.269 ;
     RECT  85.932 6.043 85.95 6.269 ;
     RECT  86.724 6.151 89.097 6.269 ;
     RECT  2.34 6.269 8.73 6.275 ;
     RECT  86.796 6.269 89.097 6.283 ;
     RECT  83.412 6.029 83.697 6.419 ;
     RECT  2.34 6.275 8.334 6.449 ;
     RECT  0.54 6.079 0.558 6.509 ;
     RECT  45.615 4.991 46.566 6.511 ;
     RECT  47.7 5.999 48.006 6.511 ;
     RECT  90.396 6.035 93.006 6.619 ;
     RECT  86.796 6.283 89.406 6.647 ;
     RECT  2.34 6.449 7.074 6.691 ;
     RECT  2.304 6.691 7.074 6.719 ;
     RECT  88.02 6.647 89.406 6.781 ;
     RECT  0.288 6.667 0.306 6.797 ;
     RECT  45.615 6.511 48.006 6.809 ;
     RECT  2.304 6.719 5.67 6.845 ;
     RECT  86.796 6.647 87.066 6.845 ;
     RECT  51.015 5.639 51.297 6.925 ;
     RECT  48.024 6.889 48.042 6.961 ;
     RECT  2.304 6.845 5.166 7.051 ;
     RECT  88.02 6.781 89.658 7.051 ;
     RECT  90.396 6.619 93.51 7.051 ;
     RECT  6.444 6.719 7.074 7.079 ;
     RECT  48.024 6.961 48.654 7.079 ;
     RECT  2.268 7.051 5.166 7.151 ;
     RECT  10.836 7.051 10.854 7.151 ;
     RECT  86.796 6.845 86.886 7.159 ;
     RECT  85.788 6.379 85.806 7.231 ;
     RECT  86.652 7.159 86.886 7.231 ;
     RECT  50.652 6.925 51.297 7.259 ;
     RECT  85.788 7.231 86.886 7.259 ;
     RECT  85.788 7.259 86.022 7.349 ;
     RECT  86.796 7.259 86.886 7.349 ;
     RECT  9.36 7.231 9.45 7.421 ;
     RECT  86.832 7.349 86.886 7.43 ;
     RECT  88.02 7.051 93.546 7.435 ;
     RECT  6.444 7.079 6.966 7.501 ;
     RECT  6.192 7.501 6.966 7.655 ;
     RECT  86.832 7.43 86.85 7.691 ;
     RECT  7.815 6.449 8.334 7.735 ;
     RECT  87.948 7.435 93.546 7.763 ;
     RECT  2.304 7.151 5.166 7.861 ;
     RECT  6.192 7.655 6.462 7.861 ;
     RECT  2.304 7.861 6.462 7.949 ;
     RECT  7.815 7.735 8.478 7.963 ;
     RECT  4.788 7.949 6.462 7.964 ;
     RECT  48.888 7.969 48.906 8.041 ;
     RECT  48.78 8.041 48.906 8.159 ;
     RECT  51.015 7.259 51.297 8.167 ;
     RECT  4.824 7.964 6.462 8.195 ;
     RECT  9.252 7.861 9.27 8.239 ;
     RECT  87.048 8.167 87.138 8.339 ;
     RECT  9.252 8.239 9.342 8.429 ;
     RECT  48.024 7.079 48.042 8.429 ;
     RECT  87.048 8.339 87.066 8.429 ;
     RECT  4.824 8.195 5.778 8.477 ;
     RECT  86.112 8.437 86.13 8.477 ;
     RECT  87.948 7.763 92.394 8.477 ;
     RECT  93.492 7.763 93.546 8.491 ;
     RECT  88.092 8.477 92.394 8.501 ;
     RECT  7.308 7.963 8.478 8.581 ;
     RECT  45.615 6.809 47.286 8.581 ;
     RECT  4.86 8.477 5.778 8.699 ;
     RECT  6.84 8.581 8.55 8.699 ;
     RECT  86.652 8.581 86.742 8.699 ;
     RECT  45.615 8.581 47.79 8.735 ;
     RECT  88.092 8.501 91.782 8.735 ;
     RECT  0.252 8.635 0.27 8.765 ;
     RECT  2.304 7.949 4.05 8.779 ;
     RECT  93.492 8.491 94.086 8.923 ;
     RECT  48.672 8.815 48.69 8.969 ;
     RECT  86.688 8.699 86.742 8.969 ;
     RECT  6.84 8.699 8.478 9.005 ;
     RECT  88.164 8.735 91.782 9.005 ;
     RECT  50.724 8.167 51.297 9.041 ;
     RECT  9.396 8.941 9.414 9.101 ;
     RECT  82.656 8.941 82.674 9.113 ;
     RECT  2.304 8.779 4.122 9.211 ;
     RECT  4.86 8.699 5.562 9.211 ;
     RECT  48.744 9.121 48.834 9.239 ;
     RECT  6.84 9.005 8.097 9.247 ;
     RECT  88.815 9.005 91.782 9.319 ;
     RECT  92.916 8.923 94.086 9.347 ;
     RECT  6.624 9.247 8.097 9.355 ;
     RECT  45.615 8.735 47.286 9.509 ;
     RECT  42.768 9.481 42.786 9.581 ;
     RECT  88.815 9.319 92.034 9.589 ;
     RECT  9.108 9.481 9.126 9.617 ;
     RECT  48.744 9.239 48.762 9.689 ;
     RECT  85.788 8.977 85.806 9.751 ;
     RECT  86.688 8.969 86.706 9.751 ;
     RECT  2.304 9.211 5.562 9.787 ;
     RECT  6.408 9.355 8.097 9.787 ;
     RECT  2.304 9.787 8.097 9.851 ;
     RECT  93.492 9.347 94.086 9.887 ;
     RECT  7.092 9.851 8.097 9.895 ;
     RECT  2.304 9.851 6.282 9.931 ;
     RECT  7.092 9.895 8.262 9.931 ;
     RECT  9.036 9.787 9.054 9.931 ;
     RECT  7.092 9.931 9.054 10.049 ;
     RECT  88.815 9.589 92.358 10.075 ;
     RECT  93.492 9.887 93.546 10.075 ;
     RECT  2.268 9.931 6.282 10.121 ;
     RECT  45.615 9.509 47.214 10.129 ;
     RECT  88.815 10.075 93.546 10.193 ;
     RECT  85.788 9.751 86.706 10.219 ;
     RECT  45.036 10.129 47.214 10.229 ;
     RECT  85.788 10.219 86.886 10.253 ;
     RECT  7.128 10.049 9.054 10.355 ;
     RECT  86.184 10.253 86.886 10.471 ;
     RECT  49.212 10.435 49.23 10.589 ;
     RECT  87.804 10.471 87.822 10.589 ;
     RECT  82.656 10.363 82.674 10.625 ;
     RECT  9.36 10.471 9.378 10.769 ;
     RECT  45.036 10.229 46.854 10.859 ;
     RECT  2.304 10.121 6.282 10.939 ;
     RECT  7.128 10.355 8.478 10.939 ;
     RECT  88.815 10.193 93.51 10.939 ;
     RECT  86.184 10.471 87.03 10.975 ;
     RECT  88.815 10.939 93.546 11.011 ;
     RECT  9.396 10.939 9.486 11.039 ;
     RECT  42.768 10.939 42.786 11.039 ;
     RECT  47.916 10.435 47.934 11.101 ;
     RECT  2.304 10.939 8.478 11.129 ;
     RECT  9.396 11.039 9.414 11.129 ;
     RECT  47.592 11.101 47.934 11.173 ;
     RECT  3.96 11.129 8.478 11.209 ;
     RECT  0.252 10.507 0.27 11.213 ;
     RECT  10.836 11.101 10.854 11.245 ;
     RECT  10.836 11.245 10.926 11.273 ;
     RECT  88.344 11.011 93.546 11.273 ;
     RECT  45.615 10.859 46.854 11.281 ;
     RECT  47.592 11.173 48.15 11.281 ;
     RECT  88.344 11.273 91.926 11.309 ;
     RECT  86.184 10.975 87.426 11.371 ;
     RECT  10.908 11.273 10.926 11.399 ;
     RECT  86.184 11.371 87.57 11.407 ;
     RECT  85.896 11.407 87.57 11.453 ;
     RECT  88.815 11.309 91.926 11.471 ;
     RECT  3.96 11.209 8.55 11.551 ;
     RECT  45.615 11.281 48.15 11.669 ;
     RECT  85.896 11.453 87.102 11.669 ;
     RECT  85.896 11.669 85.914 11.705 ;
     RECT  2.304 11.129 3.042 11.803 ;
     RECT  92.736 11.273 93.51 11.813 ;
     RECT  2.232 11.803 3.042 11.849 ;
     RECT  3.96 11.551 9.234 11.849 ;
     RECT  3.96 11.849 9.126 11.911 ;
     RECT  45.615 11.669 47.214 11.939 ;
     RECT  2.304 11.849 3.042 11.947 ;
     RECT  3.888 11.911 9.126 11.947 ;
     RECT  2.304 11.947 9.126 11.975 ;
     RECT  47.988 11.669 48.15 11.983 ;
     RECT  88.02 11.551 88.038 12.091 ;
     RECT  88.815 11.471 89.478 12.091 ;
     RECT  90.396 11.471 91.926 12.091 ;
     RECT  92.736 11.813 92.754 12.091 ;
     RECT  47.988 11.983 48.726 12.209 ;
     RECT  88.02 12.091 89.478 12.325 ;
     RECT  90.396 12.091 92.754 12.325 ;
     RECT  0.54 11.749 0.558 12.379 ;
     RECT  86.652 11.669 87.102 12.379 ;
     RECT  88.02 12.325 92.754 12.379 ;
     RECT  9.108 11.975 9.126 12.389 ;
     RECT  82.656 12.361 82.674 12.515 ;
     RECT  0.252 12.379 0.558 12.557 ;
     RECT  2.304 11.975 8.334 12.557 ;
     RECT  86.652 12.379 92.754 12.557 ;
     RECT  47.988 12.209 48.006 12.631 ;
     RECT  47.808 12.631 48.006 12.749 ;
     RECT  87.624 12.557 92.754 12.811 ;
     RECT  93.492 11.813 93.51 12.811 ;
     RECT  87.624 12.811 93.51 12.821 ;
     RECT  47.988 12.749 48.006 12.857 ;
     RECT  45.615 11.939 46.566 12.865 ;
     RECT  45.615 12.865 46.782 12.901 ;
     RECT  45.615 12.901 46.962 13.019 ;
     RECT  86.652 12.557 86.742 13.063 ;
     RECT  87.624 12.821 92.142 13.091 ;
     RECT  92.916 12.821 93.51 13.099 ;
     RECT  42.804 12.793 42.822 13.171 ;
     RECT  92.916 13.099 93.546 13.171 ;
     RECT  0.216 12.955 0.234 13.277 ;
     RECT  10.8 13.171 10.818 13.289 ;
     RECT  42.768 13.171 42.822 13.289 ;
     RECT  48.096 13.171 48.114 13.289 ;
     RECT  86.076 13.063 86.742 13.289 ;
     RECT  2.304 12.557 8.19 13.297 ;
     RECT  2.304 13.297 8.262 13.325 ;
     RECT  92.916 13.171 94.086 13.421 ;
     RECT  86.616 13.289 86.742 13.433 ;
     RECT  2.34 13.325 8.262 13.441 ;
     RECT  45.615 13.019 46.818 13.469 ;
     RECT  92.916 13.421 93.546 13.631 ;
     RECT  42.804 13.289 42.822 13.667 ;
     RECT  87.624 13.091 91.854 13.675 ;
     RECT  2.34 13.441 8.298 13.829 ;
     RECT  47.88 13.711 47.898 13.829 ;
     RECT  48.636 13.675 48.654 13.829 ;
     RECT  87.552 13.675 91.854 13.829 ;
     RECT  92.916 13.631 93.51 13.901 ;
     RECT  88.272 13.829 91.854 13.981 ;
     RECT  92.916 13.901 93.006 13.981 ;
     RECT  2.34 13.829 7.074 14.093 ;
     RECT  9.072 13.981 9.09 14.099 ;
     RECT  51.015 9.041 51.297 14.107 ;
     RECT  2.34 14.093 6.93 14.135 ;
     RECT  88.272 13.981 93.006 14.171 ;
     RECT  50.688 14.107 51.297 14.207 ;
     RECT  7.815 13.829 8.298 14.251 ;
     RECT  45.615 13.469 46.782 14.251 ;
     RECT  86.616 13.433 86.67 14.251 ;
     RECT  86.616 14.251 86.742 14.341 ;
     RECT  86.184 14.341 86.742 14.369 ;
     RECT  2.34 14.135 6.858 14.395 ;
     RECT  86.184 14.369 86.67 14.485 ;
     RECT  45.615 14.251 46.962 14.521 ;
     RECT  48.024 14.521 48.042 14.639 ;
     RECT  88.416 14.171 93.006 14.639 ;
     RECT  2.304 14.395 6.858 14.669 ;
     RECT  88.815 14.639 93.006 14.683 ;
     RECT  7.815 14.251 8.802 14.783 ;
     RECT  2.304 14.669 6.066 14.819 ;
     RECT  6.84 14.669 6.858 14.881 ;
     RECT  7.815 14.783 8.334 14.881 ;
     RECT  6.84 14.881 8.334 14.915 ;
     RECT  45.615 14.521 47.07 14.917 ;
     RECT  87.444 14.755 87.462 14.917 ;
     RECT  2.304 14.819 4.59 14.945 ;
     RECT  42.804 14.881 42.822 15.052 ;
     RECT  42.768 15.052 42.822 15.053 ;
     RECT  45.615 14.917 47.718 15.089 ;
     RECT  9.324 15.061 9.342 15.179 ;
     RECT  47.7 15.089 47.718 15.179 ;
     RECT  87.444 14.917 87.498 15.179 ;
     RECT  51.015 14.207 51.297 15.187 ;
     RECT  88.815 14.683 93.51 15.223 ;
     RECT  88.815 15.223 93.546 15.293 ;
     RECT  5.472 14.819 6.066 15.421 ;
     RECT  6.84 14.915 8.097 15.421 ;
     RECT  83.415 6.419 83.697 15.421 ;
     RECT  88.815 15.293 93.51 15.421 ;
     RECT  85.968 14.485 86.67 15.493 ;
     RECT  2.304 14.945 4.554 15.691 ;
     RECT  5.472 15.421 8.097 15.691 ;
     RECT  85.968 15.493 86.958 15.719 ;
     RECT  82.656 15.421 83.697 15.755 ;
     RECT  86.652 15.719 86.958 15.791 ;
     RECT  0.252 13.531 0.27 15.821 ;
     RECT  10.8 15.727 10.818 15.899 ;
     RECT  42.768 15.053 42.786 15.899 ;
     RECT  82.656 15.755 82.674 15.899 ;
     RECT  87.804 15.421 93.51 15.989 ;
     RECT  48.024 15.997 48.042 16.105 ;
     RECT  45.615 15.089 46.962 16.141 ;
     RECT  2.304 15.691 8.097 16.169 ;
     RECT  2.376 16.169 8.097 16.219 ;
     RECT  45.615 16.141 47.07 16.259 ;
     RECT  47.844 16.105 48.69 16.259 ;
     RECT  88.2 15.989 93.51 16.259 ;
     RECT  2.376 16.219 8.37 16.339 ;
     RECT  88.812 16.259 93.51 16.367 ;
     RECT  92.916 16.367 93.51 16.402 ;
     RECT  10.692 16.069 10.782 16.403 ;
     RECT  10.764 16.403 10.782 16.439 ;
     RECT  50.688 15.187 51.297 16.439 ;
     RECT  48.528 16.259 48.69 16.501 ;
     RECT  2.376 16.339 8.622 16.529 ;
     RECT  9.396 16.411 9.414 16.529 ;
     RECT  48.528 16.501 48.798 16.541 ;
     RECT  0.54 16.501 0.558 16.589 ;
     RECT  2.376 16.529 8.55 16.799 ;
     RECT  86.652 15.791 86.742 16.871 ;
     RECT  49.752 16.843 49.77 16.879 ;
     RECT  2.376 16.799 6.858 16.951 ;
     RECT  92.916 16.402 93.546 16.987 ;
     RECT  48.528 16.541 48.618 17.069 ;
     RECT  49.752 16.879 49.878 17.069 ;
     RECT  88.812 16.367 92.178 17.105 ;
     RECT  87.84 17.077 87.858 17.117 ;
     RECT  84.96 17.185 84.978 17.221 ;
     RECT  88.815 17.105 92.178 17.311 ;
     RECT  92.916 16.987 94.086 17.311 ;
     RECT  2.304 16.951 6.858 17.339 ;
     RECT  84.924 17.221 84.978 17.339 ;
     RECT  47.628 17.221 47.646 17.347 ;
     RECT  48.42 17.185 48.438 17.347 ;
     RECT  47.628 17.347 48.438 17.375 ;
     RECT  45.615 16.259 46.782 17.383 ;
     RECT  47.628 17.375 48.258 17.383 ;
     RECT  7.815 16.799 8.55 17.455 ;
     RECT  88.815 17.311 94.086 17.483 ;
     RECT  7.815 17.455 8.838 17.609 ;
     RECT  87.948 17.611 87.966 17.651 ;
     RECT  86.976 17.659 86.994 17.689 ;
     RECT  86.076 17.617 86.094 17.717 ;
     RECT  0.54 17.419 0.558 17.741 ;
     RECT  2.34 17.339 6.858 17.851 ;
     RECT  88.815 17.483 93.51 17.887 ;
     RECT  86.976 17.689 87.21 17.915 ;
     RECT  84.924 17.339 84.942 17.951 ;
     RECT  88.2 17.887 93.51 17.951 ;
     RECT  2.34 17.851 7.038 17.995 ;
     RECT  7.815 17.609 8.514 17.995 ;
     RECT  88.2 17.951 92.97 18.023 ;
     RECT  45.615 17.383 48.258 18.149 ;
     RECT  42.804 17.995 42.822 18.22 ;
     RECT  2.34 17.995 8.514 18.221 ;
     RECT  2.34 18.221 5.886 18.283 ;
     RECT  42.804 18.22 42.858 18.301 ;
     RECT  2.304 18.283 5.886 18.329 ;
     RECT  87.156 17.915 87.21 18.391 ;
     RECT  45.615 18.149 47.502 18.419 ;
     RECT  6.696 18.221 8.514 18.427 ;
     RECT  87.156 18.391 87.39 18.461 ;
     RECT  87.372 18.461 87.39 18.491 ;
     RECT  42.804 18.301 42.894 18.571 ;
     RECT  42.768 18.571 42.894 18.599 ;
     RECT  10.8 18.391 10.818 18.689 ;
     RECT  42.768 18.599 42.786 18.689 ;
     RECT  48.24 18.149 48.258 18.689 ;
     RECT  88.2 18.023 92.034 18.689 ;
     RECT  92.916 18.023 92.97 18.697 ;
     RECT  6.696 18.427 8.55 18.806 ;
     RECT  0.252 18.571 0.27 18.811 ;
     RECT  0.252 18.811 0.342 18.869 ;
     RECT  0.252 18.869 0.27 18.893 ;
     RECT  51.015 16.439 51.297 18.931 ;
     RECT  84.924 18.841 84.942 18.931 ;
     RECT  90.036 18.689 92.034 18.931 ;
     RECT  92.916 18.697 93.51 18.931 ;
     RECT  10.764 18.805 10.782 18.959 ;
     RECT  45.615 18.419 47.214 18.959 ;
     RECT  6.696 18.806 8.19 18.968 ;
     RECT  88.2 18.689 89.19 18.995 ;
     RECT  2.376 18.329 5.886 19.075 ;
     RECT  2.34 19.075 5.886 19.111 ;
     RECT  6.696 18.968 8.154 19.111 ;
     RECT  49.212 18.841 49.23 19.111 ;
     RECT  84.924 18.931 85.014 19.139 ;
     RECT  88.308 18.995 89.19 19.139 ;
     RECT  49.104 19.111 49.23 19.229 ;
     RECT  9.288 19.111 9.306 19.301 ;
     RECT  90.036 18.931 93.51 19.373 ;
     RECT  2.304 19.111 8.154 19.435 ;
     RECT  48.348 19.309 48.366 19.507 ;
     RECT  10.8 19.507 10.818 19.679 ;
     RECT  47.628 19.507 48.366 19.769 ;
     RECT  50.724 18.931 51.297 19.777 ;
     RECT  45.615 18.959 46.818 19.849 ;
     RECT  88.308 19.139 89.154 19.867 ;
     RECT  10.908 19.741 10.926 19.877 ;
     RECT  8.892 19.615 9.126 19.913 ;
     RECT  50.688 19.777 51.297 19.949 ;
     RECT  87.12 19.813 87.138 20.005 ;
     RECT  92.916 19.373 93.51 20.011 ;
     RECT  88.128 19.867 89.154 20.047 ;
     RECT  90.036 19.373 92.034 20.047 ;
     RECT  2.268 19.435 8.154 20.048 ;
     RECT  92.916 20.011 93.546 20.111 ;
     RECT  88.128 20.047 92.034 20.119 ;
     RECT  2.304 20.048 8.154 20.155 ;
     RECT  88.128 20.119 92.106 20.155 ;
     RECT  92.916 20.111 93.51 20.155 ;
     RECT  9.108 19.913 9.126 20.191 ;
     RECT  84.924 19.139 84.942 20.191 ;
     RECT  87.048 20.005 87.138 20.281 ;
     RECT  48.672 20.155 48.69 20.309 ;
     RECT  88.056 20.155 93.51 20.381 ;
     RECT  9.108 20.191 9.162 20.453 ;
     RECT  0.252 19.723 0.27 20.477 ;
     RECT  84.924 20.191 85.014 20.489 ;
     RECT  88.056 20.381 92.034 20.623 ;
     RECT  45.615 19.849 47.394 20.659 ;
     RECT  2.304 20.155 8.298 20.695 ;
     RECT  86.868 20.281 87.138 20.731 ;
     RECT  87.876 20.623 92.034 20.731 ;
     RECT  2.304 20.695 8.622 20.849 ;
     RECT  45.615 20.659 47.97 20.849 ;
     RECT  51.015 19.949 51.297 20.857 ;
     RECT  9.432 20.587 9.45 20.957 ;
     RECT  86.868 20.731 92.034 20.957 ;
     RECT  2.304 20.849 8.097 21.149 ;
     RECT  87.12 20.957 92.034 21.271 ;
     RECT  92.916 20.381 93.51 21.271 ;
     RECT  85.5 20.857 85.518 21.299 ;
     RECT  42.768 20.821 42.786 21.389 ;
     RECT  50.652 20.857 51.297 21.397 ;
     RECT  48.132 21.127 48.258 21.433 ;
     RECT  0.216 21.307 0.234 21.485 ;
     RECT  2.376 21.149 8.097 21.497 ;
     RECT  48.132 21.433 48.402 21.497 ;
     RECT  50.616 21.397 51.297 21.569 ;
     RECT  0.288 21.499 0.306 21.629 ;
     RECT  48.168 21.497 48.402 21.659 ;
     RECT  87.12 21.271 93.51 21.659 ;
     RECT  87.12 21.659 88.074 21.775 ;
     RECT  7.74 21.497 8.097 21.811 ;
     RECT  2.376 21.497 6.966 21.883 ;
     RECT  86.976 21.775 88.074 21.901 ;
     RECT  82.656 21.703 82.674 21.929 ;
     RECT  45.615 20.849 46.782 21.937 ;
     RECT  45.615 21.937 46.854 22.081 ;
     RECT  2.304 21.883 6.966 22.109 ;
     RECT  50.688 21.569 51.297 22.109 ;
     RECT  86.652 21.901 88.074 22.109 ;
     RECT  88.815 21.659 93.51 22.199 ;
     RECT  7.74 21.811 8.802 22.235 ;
     RECT  86.976 22.109 88.074 22.235 ;
     RECT  88.815 22.199 91.314 22.235 ;
     RECT  7.74 22.235 8.262 22.279 ;
     RECT  48.24 21.659 48.402 22.351 ;
     RECT  85.5 22.171 85.518 22.379 ;
     RECT  7.128 22.279 8.262 22.469 ;
     RECT  48.24 22.351 48.51 22.585 ;
     RECT  45.615 22.081 46.89 22.621 ;
     RECT  7.128 22.469 8.097 22.739 ;
     RECT  47.916 22.585 48.51 22.739 ;
     RECT  92.052 22.199 93.51 22.747 ;
     RECT  45.615 22.621 46.926 22.855 ;
     RECT  85.752 22.783 86.094 22.855 ;
     RECT  86.976 22.235 87.75 22.855 ;
     RECT  2.304 22.109 6.354 22.891 ;
     RECT  85.752 22.855 87.75 22.919 ;
     RECT  88.815 22.235 91.098 22.981 ;
     RECT  92.052 22.747 93.546 22.981 ;
     RECT  48.384 22.739 48.474 23.009 ;
     RECT  86.652 22.919 87.75 23.017 ;
     RECT  85.752 22.919 85.914 23.069 ;
     RECT  86.652 23.017 87.966 23.069 ;
     RECT  42.804 22.819 42.822 23.081 ;
     RECT  87.948 23.069 87.966 23.089 ;
     RECT  88.815 22.981 93.546 23.089 ;
     RECT  0.252 22.891 0.27 23.117 ;
     RECT  85.896 23.069 85.914 23.117 ;
     RECT  51.015 22.109 51.297 23.161 ;
     RECT  2.304 22.891 6.39 23.179 ;
     RECT  2.268 23.179 6.39 23.323 ;
     RECT  50.688 23.161 51.297 23.351 ;
     RECT  2.268 23.323 6.462 23.387 ;
     RECT  87.948 23.089 93.546 23.405 ;
     RECT  7.236 22.739 8.097 23.431 ;
     RECT  7.236 23.431 8.37 23.549 ;
     RECT  48.456 23.009 48.474 23.549 ;
     RECT  2.304 23.387 6.462 23.593 ;
     RECT  7.236 23.549 8.19 23.593 ;
     RECT  88.236 23.405 93.546 23.597 ;
     RECT  92.34 23.597 93.546 23.693 ;
     RECT  45.615 22.855 46.962 23.701 ;
     RECT  49.464 23.089 49.482 23.701 ;
     RECT  2.304 23.593 8.19 23.741 ;
     RECT  93.492 23.693 93.546 23.755 ;
     RECT  48.996 23.701 49.482 23.819 ;
     RECT  88.236 23.597 91.494 23.819 ;
     RECT  86.652 23.069 86.742 23.827 ;
     RECT  9.216 23.701 9.234 23.855 ;
     RECT  88.38 23.819 91.494 23.885 ;
     RECT  45.615 23.701 47.106 23.927 ;
     RECT  47.304 23.971 47.322 24.089 ;
     RECT  49.32 23.819 49.482 24.089 ;
     RECT  92.34 23.693 92.61 24.089 ;
     RECT  50.724 23.351 51.297 24.097 ;
     RECT  86.652 23.827 87.462 24.125 ;
     RECT  86.652 24.125 87.174 24.197 ;
     RECT  50.688 24.097 51.297 24.269 ;
     RECT  88.488 23.885 91.494 24.331 ;
     RECT  92.34 24.089 92.394 24.331 ;
     RECT  50.724 24.269 51.297 24.431 ;
     RECT  0.252 24.043 0.27 24.461 ;
     RECT  48.492 24.331 48.51 24.511 ;
     RECT  86.364 24.601 86.382 24.619 ;
     RECT  48.42 24.511 48.51 24.629 ;
     RECT  49.32 24.089 49.338 24.629 ;
     RECT  87.156 24.197 87.174 24.629 ;
     RECT  86.22 24.619 86.382 24.665 ;
     RECT  86.364 24.665 86.382 24.701 ;
     RECT  88.488 24.331 92.394 24.701 ;
     RECT  48.132 24.781 48.15 24.899 ;
     RECT  45.615 23.927 46.566 24.907 ;
     RECT  87.732 25.015 87.75 25.051 ;
     RECT  88.488 24.701 90.126 25.051 ;
     RECT  0.216 24.907 0.234 25.085 ;
     RECT  87.732 25.051 90.126 25.085 ;
     RECT  90.972 24.701 92.394 25.195 ;
     RECT  93.492 23.755 94.086 25.195 ;
     RECT  87.876 25.085 90.126 25.229 ;
     RECT  90.972 25.195 94.086 25.277 ;
     RECT  47.736 24.943 47.754 25.321 ;
     RECT  2.304 23.741 8.097 25.411 ;
     RECT  88.092 25.229 90.126 25.435 ;
     RECT  90.972 25.277 93.51 25.435 ;
     RECT  47.664 25.321 47.754 25.439 ;
     RECT  51.015 24.431 51.297 25.447 ;
     RECT  88.092 25.435 93.51 25.469 ;
     RECT  2.304 25.411 8.442 25.511 ;
     RECT  29.415 2.413 29.697 25.519 ;
     RECT  42.804 25.411 42.822 25.619 ;
     RECT  48.816 25.483 48.834 25.709 ;
     RECT  26.856 25.519 26.874 25.717 ;
     RECT  29.415 25.519 30.078 25.717 ;
     RECT  86.652 25.447 86.67 25.717 ;
     RECT  26.784 25.717 26.874 25.853 ;
     RECT  29.415 25.717 30.114 25.853 ;
     RECT  26.856 25.853 26.874 25.889 ;
     RECT  29.415 25.853 30.042 25.889 ;
     RECT  2.304 25.511 8.097 25.979 ;
     RECT  29.415 25.889 30.006 25.979 ;
     RECT  0.252 25.339 0.27 26.045 ;
     RECT  86.652 25.717 86.706 26.131 ;
     RECT  29.415 25.979 29.79 26.189 ;
     RECT  88.092 25.469 91.818 26.203 ;
     RECT  92.88 25.469 93.51 26.203 ;
     RECT  29.415 26.189 29.754 26.251 ;
     RECT  29.304 26.251 29.754 26.285 ;
     RECT  47.844 26.023 47.862 26.293 ;
     RECT  50.688 25.447 51.297 26.293 ;
     RECT  88.092 26.203 93.51 26.299 ;
     RECT  47.628 26.293 47.862 26.329 ;
     RECT  50.616 26.293 51.297 26.365 ;
     RECT  6.552 25.979 8.097 26.401 ;
     RECT  10.8 25.141 10.818 26.401 ;
     RECT  6.552 26.401 8.154 26.485 ;
     RECT  6.552 26.485 8.622 26.491 ;
     RECT  13.215 2.413 13.497 26.491 ;
     RECT  24.015 2.413 24.297 26.491 ;
     RECT  88.056 26.299 93.51 26.491 ;
     RECT  29.304 26.285 29.697 26.525 ;
     RECT  6.552 26.491 8.946 26.527 ;
     RECT  48.852 26.401 48.87 26.527 ;
     RECT  13.104 26.491 13.497 26.528 ;
     RECT  23.904 26.491 24.297 26.528 ;
     RECT  88.056 26.491 94.086 26.555 ;
     RECT  48.78 26.527 48.87 26.591 ;
     RECT  91.152 26.555 94.086 26.591 ;
     RECT  6.552 26.527 9.018 26.599 ;
     RECT  88.2 26.555 90.378 26.621 ;
     RECT  45.615 24.907 46.818 26.627 ;
     RECT  6.552 26.599 9.09 26.663 ;
     RECT  10.728 26.401 10.818 26.663 ;
     RECT  9.072 26.663 9.09 26.671 ;
     RECT  10.8 26.663 10.818 26.699 ;
     RECT  2.304 25.979 5.742 26.761 ;
     RECT  6.552 26.663 8.226 26.761 ;
     RECT  86.652 26.131 87.318 26.761 ;
     RECT  9.072 26.671 9.162 26.789 ;
     RECT  47.592 26.329 47.862 26.789 ;
     RECT  48.78 26.591 48.798 26.969 ;
     RECT  86.652 26.761 87.39 27.059 ;
     RECT  91.152 26.591 93.51 27.059 ;
     RECT  49.752 26.671 49.77 27.067 ;
     RECT  50.58 26.365 51.297 27.067 ;
     RECT  86.652 27.059 87.318 27.101 ;
     RECT  86.652 27.101 86.67 27.211 ;
     RECT  86.076 27.211 86.67 27.239 ;
     RECT  49.752 27.067 51.297 27.329 ;
     RECT  49.86 27.329 51.297 27.341 ;
     RECT  88.56 26.621 90.378 27.355 ;
     RECT  91.152 27.059 92.178 27.355 ;
     RECT  47.736 26.789 47.754 27.365 ;
     RECT  2.304 26.761 8.226 27.481 ;
     RECT  50.04 27.341 51.297 27.509 ;
     RECT  45.615 26.627 46.566 27.571 ;
     RECT  88.56 27.355 92.178 27.595 ;
     RECT  50.076 27.509 51.297 27.599 ;
     RECT  74.16 27.481 74.646 27.599 ;
     RECT  92.916 27.059 93.51 27.637 ;
     RECT  42.84 27.481 42.858 27.643 ;
     RECT  42.768 27.643 42.858 27.671 ;
     RECT  2.304 27.481 8.586 27.707 ;
     RECT  45.615 27.571 46.782 27.751 ;
     RECT  2.304 27.707 8.334 27.779 ;
     RECT  86.076 27.239 86.094 27.779 ;
     RECT  88.056 27.595 92.178 27.787 ;
     RECT  92.916 27.637 94.086 27.787 ;
     RECT  0.252 27.499 0.27 27.821 ;
     RECT  88.056 27.787 94.086 27.835 ;
     RECT  75.564 3.983 75.582 27.841 ;
     RECT  42.768 27.671 42.786 27.869 ;
     RECT  50.184 27.599 51.297 27.869 ;
     RECT  74.16 27.599 74.178 27.917 ;
     RECT  75.564 27.841 75.726 27.917 ;
     RECT  87.552 27.835 94.086 27.965 ;
     RECT  87.552 27.965 88.002 28.013 ;
     RECT  2.304 27.779 8.097 28.049 ;
     RECT  2.304 28.049 6.966 28.075 ;
     RECT  2.268 28.075 6.966 28.139 ;
     RECT  88.815 27.965 94.086 28.139 ;
     RECT  48.78 27.985 48.798 28.183 ;
     RECT  10.8 28.111 10.818 28.211 ;
     RECT  92.916 28.139 94.086 28.211 ;
     RECT  50.724 27.869 51.297 28.247 ;
     RECT  48.348 28.183 48.798 28.381 ;
     RECT  87.984 28.013 88.002 28.409 ;
     RECT  0.216 28.219 0.234 28.493 ;
     RECT  72.615 2.413 72.897 28.507 ;
     RECT  45.615 27.751 47.322 28.525 ;
     RECT  87.048 28.363 87.21 28.541 ;
     RECT  87.048 28.541 87.138 28.555 ;
     RECT  34.815 2.413 35.097 28.645 ;
     RECT  43.02 28.561 43.038 28.651 ;
     RECT  61.815 2.413 62.097 28.651 ;
     RECT  67.215 2.413 67.497 28.651 ;
     RECT  45.615 28.525 47.502 28.679 ;
     RECT  48.348 28.381 49.05 28.679 ;
     RECT  88.815 28.139 91.854 28.679 ;
     RECT  34.704 28.645 35.097 28.685 ;
     RECT  72.504 28.507 72.897 28.685 ;
     RECT  67.104 28.651 67.497 28.688 ;
     RECT  59.148 28.687 59.166 28.733 ;
     RECT  10.836 28.651 10.854 28.751 ;
     RECT  42.768 28.651 43.362 28.751 ;
     RECT  38.772 28.651 38.79 28.781 ;
     RECT  61.815 28.651 62.694 28.781 ;
     RECT  42.84 28.751 43.362 28.823 ;
     RECT  42.84 28.823 42.858 28.859 ;
     RECT  60.696 28.747 60.714 28.859 ;
     RECT  2.304 28.139 6.966 28.921 ;
     RECT  7.776 28.049 8.097 28.921 ;
     RECT  2.304 28.921 8.097 28.939 ;
     RECT  82.656 28.723 82.674 28.949 ;
     RECT  87.912 28.831 87.93 28.949 ;
     RECT  2.196 28.939 8.097 28.973 ;
     RECT  8.82 28.831 8.838 29.021 ;
     RECT  7.815 28.973 8.097 29.065 ;
     RECT  49.104 29.029 49.122 29.065 ;
     RECT  92.916 28.211 93.51 29.101 ;
     RECT  2.196 28.973 6.93 29.129 ;
     RECT  49.104 29.065 49.266 29.219 ;
     RECT  51.015 28.247 51.297 29.227 ;
     RECT  86.652 28.555 87.138 29.299 ;
     RECT  86.652 29.299 87.894 29.405 ;
     RECT  45.615 28.679 47.358 29.489 ;
     RECT  88.815 28.679 91.494 29.489 ;
     RECT  86.652 29.405 87.246 29.597 ;
     RECT  91.044 29.489 91.494 29.605 ;
     RECT  91.044 29.605 91.638 29.641 ;
     RECT  92.412 29.101 93.51 29.641 ;
     RECT  2.304 29.129 6.93 29.759 ;
     RECT  86.652 29.597 87.174 29.759 ;
     RECT  2.34 29.759 6.93 29.767 ;
     RECT  7.815 29.065 8.406 29.767 ;
     RECT  50.724 29.227 51.297 29.767 ;
     RECT  2.34 29.767 8.406 29.911 ;
     RECT  50.688 29.767 51.297 29.939 ;
     RECT  86.652 29.759 86.958 29.939 ;
     RECT  10.8 29.911 10.818 30.029 ;
     RECT  45.615 29.489 46.854 30.029 ;
     RECT  2.34 29.911 8.802 30.137 ;
     RECT  7.776 30.137 8.37 30.209 ;
     RECT  88.815 29.489 90.27 30.235 ;
     RECT  91.044 29.641 93.51 30.235 ;
     RECT  43.344 30.109 43.362 30.299 ;
     RECT  88.815 30.235 93.51 30.343 ;
     RECT  48.6 30.181 48.618 30.451 ;
     RECT  48.528 30.451 48.618 30.569 ;
     RECT  88.812 30.343 93.51 30.605 ;
     RECT  0.252 28.651 0.27 30.653 ;
     RECT  88.812 30.605 89.19 30.667 ;
     RECT  48.528 30.569 48.546 30.713 ;
     RECT  51.015 29.939 51.297 30.721 ;
     RECT  48.06 30.811 48.186 30.847 ;
     RECT  87.732 30.811 87.75 30.847 ;
     RECT  87.48 30.847 87.75 30.875 ;
     RECT  86.652 29.939 86.742 30.919 ;
     RECT  90 30.605 93.51 30.983 ;
     RECT  88.74 30.667 89.19 30.991 ;
     RECT  2.34 30.137 6.93 31.081 ;
     RECT  7.815 30.209 8.37 31.109 ;
     RECT  86.112 30.919 86.742 31.217 ;
     RECT  86.112 31.217 86.706 31.225 ;
     RECT  2.304 31.081 6.93 31.289 ;
     RECT  6.588 31.289 6.93 31.351 ;
     RECT  7.815 31.109 8.19 31.351 ;
     RECT  50.544 30.721 51.297 31.379 ;
     RECT  88.668 30.991 89.19 31.387 ;
     RECT  90 30.983 92.934 31.387 ;
     RECT  6.588 31.351 8.19 31.415 ;
     RECT  50.796 31.379 51.297 31.523 ;
     RECT  45.615 30.029 46.782 31.531 ;
     RECT  47.916 30.847 48.186 31.531 ;
     RECT  88.668 31.387 92.934 31.531 ;
     RECT  45.615 31.531 48.186 31.649 ;
     RECT  85.608 31.225 86.706 31.661 ;
     RECT  9.216 31.531 9.234 31.757 ;
     RECT  86.472 31.661 86.706 31.757 ;
     RECT  88.452 31.531 92.934 31.891 ;
     RECT  10.764 31.423 10.782 31.919 ;
     RECT  42.804 31.729 42.822 31.919 ;
     RECT  45.615 31.649 47.394 31.919 ;
     RECT  85.608 31.661 85.626 31.919 ;
     RECT  86.472 31.757 86.67 31.955 ;
     RECT  88.38 31.891 92.934 31.991 ;
     RECT  2.34 31.289 5.778 32.071 ;
     RECT  6.588 31.415 8.097 32.071 ;
     RECT  49.86 31.729 49.878 32.071 ;
     RECT  88.416 31.991 92.934 32.107 ;
     RECT  94.068 31.819 94.086 32.107 ;
     RECT  2.304 32.071 8.097 32.189 ;
     RECT  10.8 32.071 10.818 32.189 ;
     RECT  6.552 32.189 8.097 32.269 ;
     RECT  49.428 32.071 49.878 32.269 ;
     RECT  88.416 32.107 94.086 32.297 ;
     RECT  49.248 32.269 49.878 32.305 ;
     RECT  87.48 30.875 87.498 32.431 ;
     RECT  45.615 31.919 46.782 32.459 ;
     RECT  49.176 32.305 49.878 32.459 ;
     RECT  88.416 32.297 93.51 32.459 ;
     RECT  49.32 32.459 49.878 32.467 ;
     RECT  86.652 31.955 86.67 32.503 ;
     RECT  49.32 32.467 49.95 32.567 ;
     RECT  87.48 32.431 87.642 32.573 ;
     RECT  48.492 32.575 48.51 32.611 ;
     RECT  48.42 32.611 48.51 32.729 ;
     RECT  86.652 32.503 86.706 32.773 ;
     RECT  6.552 32.269 8.226 32.837 ;
     RECT  7.776 32.837 8.226 32.845 ;
     RECT  9.468 32.611 9.486 32.873 ;
     RECT  7.776 32.845 8.478 32.999 ;
     RECT  7.776 32.999 8.298 33.071 ;
     RECT  2.304 32.189 5.778 33.115 ;
     RECT  6.552 32.837 7.038 33.115 ;
     RECT  48.384 33.079 48.402 33.115 ;
     RECT  86.652 32.773 87.246 33.211 ;
     RECT  88.815 32.459 93.51 33.421 ;
     RECT  85.968 33.211 87.246 33.511 ;
     RECT  49.32 32.567 49.338 33.539 ;
     RECT  85.968 33.511 87.642 33.539 ;
     RECT  88.416 33.421 93.51 33.539 ;
     RECT  47.808 33.115 48.402 33.547 ;
     RECT  85.968 33.539 86.706 33.575 ;
     RECT  87.444 33.539 87.642 33.581 ;
     RECT  47.7 33.547 48.402 33.583 ;
     RECT  86.256 33.575 86.706 33.584 ;
     RECT  2.304 33.115 7.038 33.611 ;
     RECT  82.656 33.385 82.674 33.611 ;
     RECT  86.436 33.584 86.706 33.629 ;
     RECT  47.7 33.583 49.086 33.677 ;
     RECT  6.768 33.611 7.038 33.691 ;
     RECT  7.776 33.071 8.154 33.691 ;
     RECT  48.06 33.677 49.086 33.809 ;
     RECT  51.015 31.523 51.297 33.817 ;
     RECT  45.615 32.459 46.566 33.889 ;
     RECT  50.688 33.817 51.297 33.917 ;
     RECT  0.252 32.299 0.27 33.931 ;
     RECT  88.452 33.539 93.51 33.979 ;
     RECT  0.252 33.931 0.342 33.989 ;
     RECT  9.144 33.961 9.162 34.051 ;
     RECT  42.804 33.925 42.822 34.079 ;
     RECT  10.8 33.079 10.818 34.115 ;
     RECT  6.768 33.691 8.154 34.123 ;
     RECT  86.652 33.629 86.706 34.151 ;
     RECT  87.66 34.171 87.678 34.315 ;
     RECT  9.072 34.051 9.162 34.321 ;
     RECT  2.304 33.611 5.886 34.349 ;
     RECT  49.068 33.809 49.086 34.349 ;
     RECT  87.3 34.315 87.678 34.385 ;
     RECT  88.452 33.979 94.086 34.429 ;
     RECT  88.236 34.429 94.086 34.457 ;
     RECT  2.34 34.349 5.886 34.465 ;
     RECT  6.768 34.123 8.262 34.465 ;
     RECT  9.072 34.321 9.27 34.493 ;
     RECT  45.615 33.889 46.782 34.501 ;
     RECT  9.072 34.493 9.198 34.591 ;
     RECT  9.036 34.591 9.198 34.619 ;
     RECT  0.252 33.989 0.27 34.685 ;
     RECT  9.036 34.619 9.054 34.691 ;
     RECT  44.46 34.123 44.478 34.691 ;
     RECT  45.615 34.501 46.854 34.735 ;
     RECT  42.768 34.663 42.786 34.763 ;
     RECT  2.34 34.465 8.262 34.771 ;
     RECT  48.06 33.809 48.078 34.889 ;
     RECT  49.212 34.771 49.23 34.889 ;
     RECT  51.015 33.917 51.297 34.897 ;
     RECT  87.3 34.385 87.462 34.897 ;
     RECT  87.156 34.897 87.462 34.969 ;
     RECT  0.288 34.843 0.306 34.973 ;
     RECT  2.34 34.771 8.766 34.997 ;
     RECT  45.615 34.735 47.322 34.997 ;
     RECT  86.688 34.969 87.462 35.041 ;
     RECT  50.652 34.897 51.297 35.069 ;
     RECT  47.808 35.005 47.826 35.159 ;
     RECT  88.236 34.457 93.546 35.159 ;
     RECT  86.652 35.041 87.462 35.203 ;
     RECT  92.916 35.159 93.546 35.231 ;
     RECT  88.236 35.159 92.142 35.269 ;
     RECT  86.076 35.203 87.462 35.401 ;
     RECT  88.2 35.269 92.142 35.401 ;
     RECT  2.34 34.997 8.097 35.429 ;
     RECT  9 35.509 9.018 35.581 ;
     RECT  82.656 35.509 82.674 35.609 ;
     RECT  9 35.581 9.054 35.671 ;
     RECT  2.376 35.429 8.097 35.699 ;
     RECT  48.636 35.509 48.654 35.699 ;
     RECT  86.076 35.401 92.142 35.699 ;
     RECT  9 35.671 9.09 35.771 ;
     RECT  9 35.771 9.054 35.807 ;
     RECT  86.652 35.699 92.142 35.885 ;
     RECT  49.428 35.581 49.446 35.969 ;
     RECT  51.015 35.069 51.297 35.977 ;
     RECT  92.916 35.231 93.51 35.995 ;
     RECT  87.552 35.885 92.142 36.029 ;
     RECT  50.724 35.977 51.297 36.077 ;
     RECT  6.228 35.699 8.097 36.121 ;
     RECT  45.615 34.997 46.782 36.121 ;
     RECT  45.615 36.121 47.106 36.239 ;
     RECT  0.252 36.139 0.27 36.365 ;
     RECT  48.024 36.085 48.114 36.383 ;
     RECT  92.916 35.995 94.086 36.383 ;
     RECT  87.804 36.029 92.142 36.419 ;
     RECT  51.015 36.077 51.297 36.475 ;
     RECT  87.984 36.419 92.142 36.661 ;
     RECT  92.916 36.383 93.51 36.661 ;
     RECT  2.376 35.699 5.346 36.715 ;
     RECT  6.228 36.121 8.514 36.751 ;
     RECT  45.615 36.239 46.782 36.779 ;
     RECT  51.015 36.475 51.462 36.779 ;
     RECT  2.304 36.715 5.346 36.823 ;
     RECT  6.228 36.751 8.694 36.823 ;
     RECT  48.024 36.383 48.078 36.823 ;
     RECT  49.68 36.751 49.698 36.823 ;
     RECT  51.015 36.779 51.297 36.859 ;
     RECT  2.304 36.823 8.694 36.931 ;
     RECT  47.916 36.823 48.078 36.931 ;
     RECT  50.76 36.859 51.297 36.931 ;
     RECT  2.304 36.931 8.946 36.989 ;
     RECT  47.808 36.931 48.078 37.049 ;
     RECT  49.608 36.823 49.698 37.049 ;
     RECT  50.688 36.931 51.297 37.049 ;
     RECT  86.652 35.885 86.742 37.093 ;
     RECT  86.652 37.093 87.174 37.121 ;
     RECT  10.8 36.481 10.818 37.201 ;
     RECT  48.276 37.129 48.69 37.201 ;
     RECT  10.728 37.201 10.818 37.319 ;
     RECT  86.94 37.121 87.174 37.325 ;
     RECT  45.615 36.779 46.566 37.327 ;
     RECT  10.728 37.319 10.746 37.355 ;
     RECT  87.084 37.325 87.174 37.363 ;
     RECT  87.984 36.661 93.51 37.363 ;
     RECT  2.304 36.989 8.406 37.499 ;
     RECT  87.084 37.363 93.51 37.499 ;
     RECT  87.984 37.499 92.394 37.589 ;
     RECT  93.492 37.499 93.51 37.597 ;
     RECT  87.084 37.499 87.102 37.613 ;
     RECT  0.252 37.291 0.27 37.723 ;
     RECT  93.492 37.597 94.086 37.757 ;
     RECT  45.036 37.327 46.566 37.859 ;
     RECT  0.252 37.723 0.414 37.867 ;
     RECT  40.215 2.413 40.497 37.867 ;
     RECT  0.216 37.867 0.414 37.901 ;
     RECT  0.216 37.901 0.342 37.931 ;
     RECT  0.252 37.931 0.342 37.949 ;
     RECT  51.015 37.049 51.297 37.975 ;
     RECT  48.276 37.201 49.266 38.129 ;
     RECT  87.984 37.589 91.566 38.189 ;
     RECT  45.615 37.859 46.566 38.209 ;
     RECT  6.624 37.499 8.097 38.237 ;
     RECT  40.215 37.867 41.058 38.273 ;
     RECT  6.624 38.237 6.93 38.281 ;
     RECT  45.615 38.209 46.962 38.281 ;
     RECT  92.34 37.589 92.394 38.299 ;
     RECT  93.492 37.757 93.546 38.299 ;
     RECT  7.704 38.237 8.097 38.371 ;
     RECT  48.276 38.129 48.474 38.371 ;
     RECT  88.56 38.189 91.566 38.371 ;
     RECT  92.34 38.299 93.546 38.371 ;
     RECT  48.204 38.371 48.474 38.399 ;
     RECT  85.788 38.371 85.806 38.429 ;
     RECT  45.615 38.281 47.07 38.443 ;
     RECT  86.652 38.209 86.67 38.443 ;
     RECT  45.615 38.443 47.142 38.479 ;
     RECT  48.204 38.399 48.402 38.479 ;
     RECT  50.688 37.975 51.297 38.507 ;
     RECT  86.04 38.443 86.67 38.551 ;
     RECT  2.304 37.499 5.742 38.641 ;
     RECT  9.252 38.551 9.27 38.669 ;
     RECT  86.04 38.551 86.742 38.741 ;
     RECT  88.56 38.371 93.546 38.765 ;
     RECT  0.252 37.949 0.27 38.909 ;
     RECT  88.56 38.765 93.51 38.947 ;
     RECT  88.344 38.947 93.51 39.055 ;
     RECT  6.588 38.281 6.93 39.091 ;
     RECT  7.704 38.371 8.514 39.091 ;
     RECT  10.8 38.911 10.818 39.091 ;
     RECT  86.04 38.741 86.706 39.209 ;
     RECT  87.48 39.019 87.498 39.209 ;
     RECT  88.272 39.055 93.51 39.211 ;
     RECT  2.304 38.641 5.814 39.253 ;
     RECT  6.588 39.091 8.514 39.253 ;
     RECT  86.04 39.209 86.67 39.307 ;
     RECT  2.304 39.253 8.514 39.317 ;
     RECT  10.728 39.091 10.818 39.317 ;
     RECT  45.615 38.479 48.402 39.361 ;
     RECT  10.8 39.317 10.818 39.479 ;
     RECT  45.615 39.361 48.474 39.479 ;
     RECT  87.624 39.211 93.51 39.533 ;
     RECT  47.664 39.479 48.474 39.587 ;
     RECT  88.236 39.533 93.51 39.659 ;
     RECT  92.34 39.659 93.51 39.739 ;
     RECT  45.615 39.479 46.782 39.749 ;
     RECT  86.004 39.307 86.67 39.785 ;
     RECT  48.096 39.587 48.474 39.829 ;
     RECT  86.148 39.785 86.67 40.013 ;
     RECT  51.015 38.507 51.297 40.027 ;
     RECT  86.652 40.013 86.67 40.027 ;
     RECT  92.34 39.739 93.546 40.163 ;
     RECT  2.304 39.317 8.226 40.171 ;
     RECT  9 40.171 9.018 40.289 ;
     RECT  86.652 40.027 87.246 40.297 ;
     RECT  88.236 39.659 91.422 40.297 ;
     RECT  92.916 40.163 93.546 40.315 ;
     RECT  2.088 40.171 8.226 40.361 ;
     RECT  92.916 40.315 94.086 40.361 ;
     RECT  48.096 39.829 48.906 40.397 ;
     RECT  86.652 40.297 91.422 40.441 ;
     RECT  86.652 40.441 91.494 40.469 ;
     RECT  2.304 40.361 8.226 40.567 ;
     RECT  45.615 39.749 46.566 40.567 ;
     RECT  10.908 40.531 10.926 40.631 ;
     RECT  87.588 40.469 91.494 40.711 ;
     RECT  50.724 40.027 51.297 40.739 ;
     RECT  48.42 40.397 48.906 40.829 ;
     RECT  50.796 40.739 51.297 40.829 ;
     RECT  87.588 40.711 91.962 40.829 ;
     RECT  0.252 40.459 0.27 40.877 ;
     RECT  48.564 40.829 48.906 40.909 ;
     RECT  88.815 40.829 91.962 40.937 ;
     RECT  48.564 40.909 49.122 41.143 ;
     RECT  2.304 40.567 8.37 41.251 ;
     RECT  92.916 40.361 93.546 41.251 ;
     RECT  88.815 40.937 91.854 41.279 ;
     RECT  92.664 41.251 93.546 41.323 ;
     RECT  86.652 40.469 86.742 41.341 ;
     RECT  87.588 40.829 88.002 41.341 ;
     RECT  2.304 41.251 8.622 41.369 ;
     RECT  48.564 41.143 49.338 41.369 ;
     RECT  86.652 41.341 88.002 41.369 ;
     RECT  92.664 41.323 94.086 41.369 ;
     RECT  48.996 41.369 49.014 41.441 ;
     RECT  86.652 41.369 87.678 41.513 ;
     RECT  9.468 41.071 9.486 41.549 ;
     RECT  45.615 40.567 47.178 41.683 ;
     RECT  2.304 41.369 8.478 41.693 ;
     RECT  45.615 41.683 47.322 41.719 ;
     RECT  45.615 41.719 47.79 41.747 ;
     RECT  47.304 41.747 47.79 41.819 ;
     RECT  51.015 40.829 51.297 41.881 ;
     RECT  86.652 41.513 87.606 41.881 ;
     RECT  2.304 41.693 8.334 41.909 ;
     RECT  50.652 41.881 51.297 41.981 ;
     RECT  88.815 41.279 89.478 42.139 ;
     RECT  90.36 41.279 91.854 42.139 ;
     RECT  88.815 42.139 91.854 42.151 ;
     RECT  88.815 42.151 91.962 42.223 ;
     RECT  88.344 42.223 91.962 42.251 ;
     RECT  92.916 41.369 94.086 42.295 ;
     RECT  9.252 42.259 9.27 42.331 ;
     RECT  49.14 42.295 49.158 42.331 ;
     RECT  86.076 41.881 87.606 42.359 ;
     RECT  49.068 42.331 49.158 42.449 ;
     RECT  42.768 41.341 42.786 42.457 ;
     RECT  0.396 42.331 0.414 42.475 ;
     RECT  0.216 42.475 0.414 42.509 ;
     RECT  2.304 41.909 6.93 42.523 ;
     RECT  45.615 41.747 46.566 42.529 ;
     RECT  47.304 41.819 47.718 42.529 ;
     RECT  86.652 42.359 87.606 42.565 ;
     RECT  88.344 42.251 91.386 42.565 ;
     RECT  42.768 42.457 42.822 42.593 ;
     RECT  82.656 42.331 82.674 42.593 ;
     RECT  92.34 42.295 94.086 42.593 ;
     RECT  7.815 41.909 8.334 42.601 ;
     RECT  9.216 42.331 9.27 42.601 ;
     RECT  7.815 42.601 9.27 42.629 ;
     RECT  42.768 42.593 42.786 42.629 ;
     RECT  2.16 42.523 6.93 42.653 ;
     RECT  2.268 42.653 6.93 42.691 ;
     RECT  7.815 42.629 9.198 42.691 ;
     RECT  2.268 42.691 9.198 42.719 ;
     RECT  86.652 42.565 91.386 42.719 ;
     RECT  45.615 42.529 47.718 42.727 ;
     RECT  0.216 42.509 0.27 42.749 ;
     RECT  2.268 42.719 9.126 42.755 ;
     RECT  86.652 42.719 91.206 42.797 ;
     RECT  93.492 42.593 94.086 42.797 ;
     RECT  87.588 42.797 91.206 42.827 ;
     RECT  45.615 42.727 48.15 42.989 ;
     RECT  48.132 42.989 48.15 43.105 ;
     RECT  0.252 42.749 0.27 43.229 ;
     RECT  92.34 42.593 92.574 43.339 ;
     RECT  93.492 42.797 93.51 43.339 ;
     RECT  2.268 42.755 8.694 43.439 ;
     RECT  48.132 43.105 48.366 43.501 ;
     RECT  49.212 43.033 49.23 43.501 ;
     RECT  2.268 43.439 8.622 43.529 ;
     RECT  48.132 43.501 49.23 43.529 ;
     RECT  51.015 41.981 51.297 43.609 ;
     RECT  92.34 43.339 93.51 43.609 ;
     RECT  50.796 43.609 51.297 43.681 ;
     RECT  86.652 42.797 86.67 43.681 ;
     RECT  87.588 42.827 91.062 43.681 ;
     RECT  92.304 43.609 93.51 43.681 ;
     RECT  48.528 43.529 49.23 43.799 ;
     RECT  50.724 43.681 51.297 43.835 ;
     RECT  86.652 43.681 86.742 43.843 ;
     RECT  87.588 43.681 93.51 43.843 ;
     RECT  2.304 43.529 8.622 43.853 ;
     RECT  45.615 42.989 46.818 43.951 ;
     RECT  45.615 43.951 47.286 44.221 ;
     RECT  2.304 43.853 5.994 44.249 ;
     RECT  45.615 44.221 47.394 44.311 ;
     RECT  49.608 44.185 49.698 44.339 ;
     RECT  86.652 43.843 93.51 44.411 ;
     RECT  42.804 44.347 42.822 44.447 ;
     RECT  6.732 43.853 8.622 44.477 ;
     RECT  45.615 44.311 47.466 44.491 ;
     RECT  45.615 44.491 47.826 44.519 ;
     RECT  42.768 44.491 42.786 44.609 ;
     RECT  47.808 44.519 47.826 44.609 ;
     RECT  86.652 44.411 92.97 44.689 ;
     RECT  2.415 44.249 5.994 44.761 ;
     RECT  6.732 44.477 6.966 44.761 ;
     RECT  86.076 44.689 92.97 44.879 ;
     RECT  88.776 44.879 92.97 44.915 ;
     RECT  10.8 44.851 10.818 44.951 ;
     RECT  88.815 44.915 92.97 44.951 ;
     RECT  2.415 44.761 6.966 44.957 ;
     RECT  48.24 45.031 48.258 45.149 ;
     RECT  51.015 43.835 51.297 45.157 ;
     RECT  92.664 44.951 92.97 45.211 ;
     RECT  50.688 45.157 51.297 45.257 ;
     RECT  2.415 44.957 5.814 45.265 ;
     RECT  7.704 44.477 8.622 45.265 ;
     RECT  7.704 45.265 8.73 45.301 ;
     RECT  86.076 44.879 87.642 45.329 ;
     RECT  0.252 44.779 0.27 45.485 ;
     RECT  92.664 45.211 93.51 45.499 ;
     RECT  6.552 44.957 6.966 45.571 ;
     RECT  7.704 45.301 8.766 45.571 ;
     RECT  86.652 45.329 87.642 45.581 ;
     RECT  6.552 45.571 8.766 45.661 ;
     RECT  88.815 44.951 91.926 45.733 ;
     RECT  92.664 45.499 94.086 45.733 ;
     RECT  6.552 45.661 8.946 45.773 ;
     RECT  2.304 45.265 5.814 45.805 ;
     RECT  6.552 45.773 8.55 45.805 ;
     RECT  45.615 44.519 46.782 45.841 ;
     RECT  86.652 45.581 87.03 45.959 ;
     RECT  45.615 45.841 46.818 45.995 ;
     RECT  2.304 45.805 8.55 46.013 ;
     RECT  48.996 45.805 49.014 46.075 ;
     RECT  2.304 46.013 5.886 46.109 ;
     RECT  86.652 45.959 86.742 46.111 ;
     RECT  7.128 46.013 8.55 46.139 ;
     RECT  86.076 46.111 86.742 46.157 ;
     RECT  48.888 46.075 49.014 46.201 ;
     RECT  49.752 45.841 49.77 46.201 ;
     RECT  87.804 45.841 87.822 46.237 ;
     RECT  50.724 45.257 51.297 46.409 ;
     RECT  50.796 46.409 51.297 46.571 ;
     RECT  87.804 46.237 87.858 46.615 ;
     RECT  86.652 46.157 86.742 46.679 ;
     RECT  7.128 46.139 8.226 46.747 ;
     RECT  45.615 45.995 46.566 46.813 ;
     RECT  2.304 46.109 4.266 46.843 ;
     RECT  5.004 46.109 5.886 46.843 ;
     RECT  48.888 46.201 49.77 46.849 ;
     RECT  88.815 45.733 94.086 46.877 ;
     RECT  48.888 46.849 49.986 46.913 ;
     RECT  45.615 46.813 46.782 46.921 ;
     RECT  87.516 46.615 87.858 46.921 ;
     RECT  88.815 46.877 89.262 46.921 ;
     RECT  6.696 46.747 8.226 47.011 ;
     RECT  87.516 46.921 89.262 47.011 ;
     RECT  45.615 46.921 46.926 47.039 ;
     RECT  2.304 46.843 5.886 47.191 ;
     RECT  6.624 47.011 8.226 47.191 ;
     RECT  10.8 46.201 10.818 47.309 ;
     RECT  82.656 47.191 82.674 47.309 ;
     RECT  2.304 47.191 8.226 47.317 ;
     RECT  48.132 47.083 48.15 47.345 ;
     RECT  87.228 47.011 89.262 47.425 ;
     RECT  90.108 46.877 94.086 47.453 ;
     RECT  2.304 47.317 8.334 47.501 ;
     RECT  0.216 46.651 0.234 47.549 ;
     RECT  87.084 47.425 89.262 47.623 ;
     RECT  48.24 47.551 48.582 47.651 ;
     RECT  49.536 46.913 49.986 47.695 ;
     RECT  2.304 47.501 5.454 47.707 ;
     RECT  6.228 47.501 8.334 47.731 ;
     RECT  86.688 47.623 89.262 47.731 ;
     RECT  90.108 47.453 93.51 47.731 ;
     RECT  6.228 47.731 8.478 47.821 ;
     RECT  6.228 47.821 9.126 47.849 ;
     RECT  48.924 47.695 49.986 47.849 ;
     RECT  86.688 47.731 93.51 47.849 ;
     RECT  50.94 46.571 51.297 47.965 ;
     RECT  48.924 47.849 49.338 48.119 ;
     RECT  87.444 47.849 93.51 48.191 ;
     RECT  2.268 47.707 5.454 48.271 ;
     RECT  6.228 47.849 7.002 48.271 ;
     RECT  87.84 48.191 93.51 48.379 ;
     RECT  7.776 47.849 9.126 48.389 ;
     RECT  10.836 48.271 10.854 48.389 ;
     RECT  45.615 47.039 46.854 48.389 ;
     RECT  86.652 47.965 86.67 48.397 ;
     RECT  2.268 48.271 7.002 48.569 ;
     RECT  7.815 48.389 9.126 48.569 ;
     RECT  2.304 48.569 7.002 48.658 ;
     RECT  49.32 48.119 49.338 48.659 ;
     RECT  50.22 47.965 51.297 48.659 ;
     RECT  87.84 48.379 93.546 48.659 ;
     RECT  92.88 48.659 93.546 48.731 ;
     RECT  86.076 48.397 86.67 48.775 ;
     RECT  8.964 48.569 9.126 48.839 ;
     RECT  92.88 48.731 93.51 48.845 ;
     RECT  9.108 48.839 9.126 48.929 ;
     RECT  42.804 48.703 42.822 48.929 ;
     RECT  86.076 48.775 86.706 48.929 ;
     RECT  44.46 48.271 44.478 49.199 ;
     RECT  48.24 48.469 48.474 49.199 ;
     RECT  87.84 48.659 92.106 49.199 ;
     RECT  0.252 49.099 0.27 49.229 ;
     RECT  86.688 48.929 86.706 49.235 ;
     RECT  10.836 49.171 10.854 49.271 ;
     RECT  45.615 48.389 46.818 49.271 ;
     RECT  2.304 48.658 7.038 49.339 ;
     RECT  7.815 48.569 8.154 49.339 ;
     RECT  87.84 49.199 88.002 49.351 ;
     RECT  2.304 49.339 8.154 49.373 ;
     RECT  50.688 48.659 51.297 49.379 ;
     RECT  42.768 49.243 42.786 49.469 ;
     RECT  49.644 49.009 49.662 49.469 ;
     RECT  87.156 49.351 88.002 49.469 ;
     RECT  88.815 49.199 92.106 49.549 ;
     RECT  48.456 49.199 48.474 49.585 ;
     RECT  88.815 49.549 92.142 49.585 ;
     RECT  92.916 48.845 93.51 49.585 ;
     RECT  2.304 49.373 5.13 49.675 ;
     RECT  2.268 49.675 5.13 49.739 ;
     RECT  88.815 49.585 93.51 49.739 ;
     RECT  50.724 49.379 51.297 49.919 ;
     RECT  0.216 49.867 0.234 49.997 ;
     RECT  48.456 49.585 48.726 50.089 ;
     RECT  2.304 49.739 5.13 50.107 ;
     RECT  5.904 49.373 8.154 50.107 ;
     RECT  48.132 50.089 48.726 50.161 ;
     RECT  86.724 49.981 86.742 50.161 ;
     RECT  2.304 50.107 8.154 50.251 ;
     RECT  9.036 49.891 9.054 50.251 ;
     RECT  86.652 50.161 86.742 50.251 ;
     RECT  87.768 49.469 88.002 50.251 ;
     RECT  48.132 50.161 48.906 50.287 ;
     RECT  2.304 50.251 9.054 50.315 ;
     RECT  45.615 49.271 46.674 50.323 ;
     RECT  86.652 50.251 88.002 50.323 ;
     RECT  88.815 49.739 92.034 50.323 ;
     RECT  10.836 50.251 10.854 50.351 ;
     RECT  0.252 50.251 0.27 50.381 ;
     RECT  47.592 50.287 48.906 50.395 ;
     RECT  92.916 49.739 93.51 50.395 ;
     RECT  45.615 50.323 46.782 50.423 ;
     RECT  9.036 50.315 9.054 50.431 ;
     RECT  85.5 49.783 85.518 50.459 ;
     RECT  86.652 50.323 92.034 50.459 ;
     RECT  86.652 50.459 87.246 50.521 ;
     RECT  2.304 50.315 7.074 50.549 ;
     RECT  86.184 50.521 87.246 50.573 ;
     RECT  9.036 50.431 9.342 50.621 ;
     RECT  92.916 50.395 93.546 50.621 ;
     RECT  83.415 15.755 83.697 50.629 ;
     RECT  47.592 50.395 49.014 50.665 ;
     RECT  2.304 50.549 7.038 50.693 ;
     RECT  2.304 50.693 6.966 50.729 ;
     RECT  82.728 50.629 83.697 50.729 ;
     RECT  47.304 50.665 49.014 50.819 ;
     RECT  42.804 50.791 42.822 50.827 ;
     RECT  51.015 49.919 51.297 50.827 ;
     RECT  7.815 50.315 8.226 50.855 ;
     RECT  42.804 50.827 42.894 50.891 ;
     RECT  42.876 50.891 42.894 50.963 ;
     RECT  88.308 50.459 92.034 50.971 ;
     RECT  88.308 50.971 92.07 50.999 ;
     RECT  88.74 50.999 92.07 51.061 ;
     RECT  92.916 50.621 93.51 51.061 ;
     RECT  10.8 51.061 10.818 51.197 ;
     RECT  0.216 51.241 0.234 51.293 ;
     RECT  86.688 50.573 87.246 51.367 ;
     RECT  86.688 51.367 87.966 51.403 ;
     RECT  9.036 50.621 9.126 51.467 ;
     RECT  9.036 51.467 9.09 51.503 ;
     RECT  2.376 50.729 6.966 51.511 ;
     RECT  47.304 50.819 48.366 51.629 ;
     RECT  86.652 51.403 87.966 51.637 ;
     RECT  7.815 50.855 8.097 51.781 ;
     RECT  86.076 51.637 87.966 51.809 ;
     RECT  88.74 51.061 93.51 51.835 ;
     RECT  2.376 51.511 7.074 51.871 ;
     RECT  7.815 51.781 8.154 51.871 ;
     RECT  2.376 51.871 8.154 51.899 ;
     RECT  47.304 51.629 47.826 51.899 ;
     RECT  45.615 50.423 46.566 51.907 ;
     RECT  86.832 51.809 87.966 51.943 ;
     RECT  88.704 51.835 93.51 51.943 ;
     RECT  45.615 51.907 46.782 52.007 ;
     RECT  86.832 51.943 93.51 52.079 ;
     RECT  5.4 51.899 8.154 52.141 ;
     RECT  49.896 51.979 49.914 52.141 ;
     RECT  50.688 50.827 51.297 52.141 ;
     RECT  49.104 51.943 49.122 52.205 ;
     RECT  86.076 51.809 86.094 52.213 ;
     RECT  5.4 52.141 8.334 52.285 ;
     RECT  9.072 51.503 9.09 52.285 ;
     RECT  2.376 51.899 4.59 52.321 ;
     RECT  49.896 52.141 51.297 52.321 ;
     RECT  86.04 52.213 86.094 52.447 ;
     RECT  85.896 52.447 86.094 52.493 ;
     RECT  5.4 52.285 9.09 52.591 ;
     RECT  83.415 50.729 83.697 52.591 ;
     RECT  86.832 52.079 90.234 52.619 ;
     RECT  86.832 52.619 87.606 52.681 ;
     RECT  47.808 51.899 47.826 52.709 ;
     RECT  82.728 52.591 83.697 52.709 ;
     RECT  5.4 52.591 9.414 52.781 ;
     RECT  2.304 52.321 4.59 52.861 ;
     RECT  5.4 52.781 9.342 52.861 ;
     RECT  0.252 51.739 0.27 52.877 ;
     RECT  2.304 52.861 9.342 52.889 ;
     RECT  2.304 52.889 9.27 52.979 ;
     RECT  49.824 52.321 51.297 52.987 ;
     RECT  88.488 52.619 90.234 52.987 ;
     RECT  90.972 52.079 93.51 52.987 ;
     RECT  2.304 52.979 9.126 53.131 ;
     RECT  2.268 53.131 9.126 53.285 ;
     RECT  4.968 53.285 9.126 53.321 ;
     RECT  49.752 52.987 51.297 53.329 ;
     RECT  2.268 53.285 4.23 53.357 ;
     RECT  9.108 53.321 9.126 53.429 ;
     RECT  54.684 53.257 54.702 53.429 ;
     RECT  86.616 52.681 87.606 53.429 ;
     RECT  85.824 53.401 85.842 53.519 ;
     RECT  86.616 53.429 87.03 53.519 ;
     RECT  49.752 53.329 51.39 53.527 ;
     RECT  85.68 53.527 85.698 53.597 ;
     RECT  48.276 52.861 48.294 53.671 ;
     RECT  88.488 52.987 93.51 53.761 ;
     RECT  48.204 53.671 48.294 53.789 ;
     RECT  49.572 53.527 51.39 53.789 ;
     RECT  49.644 53.789 51.39 53.797 ;
     RECT  88.38 53.761 93.51 53.797 ;
     RECT  4.968 53.321 8.097 53.897 ;
     RECT  2.415 53.357 4.23 54.031 ;
     RECT  4.968 53.897 6.894 54.031 ;
     RECT  49.644 53.797 51.462 54.059 ;
     RECT  87.804 53.797 93.51 54.059 ;
     RECT  2.415 54.031 6.894 54.139 ;
     RECT  50.184 54.059 51.297 54.239 ;
     RECT  88.344 54.059 93.51 54.437 ;
     RECT  7.776 53.897 8.097 54.481 ;
     RECT  7.776 54.481 8.154 54.667 ;
     RECT  86.652 53.519 87.03 54.715 ;
     RECT  2.304 54.139 6.894 54.751 ;
     RECT  7.74 54.667 8.154 54.751 ;
     RECT  9 54.211 9.018 54.751 ;
     RECT  45.615 52.007 46.566 54.751 ;
     RECT  9 54.751 9.054 54.841 ;
     RECT  86.652 54.715 87.57 54.859 ;
     RECT  49.32 54.751 49.338 54.905 ;
     RECT  86.544 54.859 87.57 54.905 ;
     RECT  45.615 54.751 46.818 54.94 ;
     RECT  87.12 54.905 87.57 54.977 ;
     RECT  2.304 54.751 8.154 54.985 ;
     RECT  9 54.841 9.126 54.985 ;
     RECT  50.832 54.239 51.297 55.021 ;
     RECT  0.252 53.707 0.27 55.037 ;
     RECT  82.656 54.949 82.674 55.049 ;
     RECT  87.192 54.977 87.57 55.099 ;
     RECT  45.615 54.94 46.854 55.139 ;
     RECT  87.192 55.099 87.642 55.139 ;
     RECT  48.456 54.985 48.474 55.147 ;
     RECT  2.304 54.985 9.126 55.175 ;
     RECT  87.192 55.139 87.426 55.211 ;
     RECT  87.408 55.211 87.426 55.283 ;
     RECT  88.815 54.437 93.51 55.381 ;
     RECT  2.304 55.175 8.622 55.483 ;
     RECT  10.764 55.417 10.782 55.489 ;
     RECT  50.544 55.021 51.297 55.525 ;
     RECT  10.764 55.489 10.818 55.553 ;
     RECT  48.276 55.147 48.474 55.561 ;
     RECT  2.268 55.483 8.622 55.613 ;
     RECT  48.276 55.561 48.834 55.679 ;
     RECT  50.4 55.525 51.297 55.679 ;
     RECT  48.276 55.679 48.582 55.949 ;
     RECT  0.252 55.867 0.27 56.059 ;
     RECT  47.376 56.029 47.394 56.065 ;
     RECT  87.552 56.065 87.57 56.141 ;
     RECT  0.252 56.059 0.306 56.155 ;
     RECT  86.688 56.101 86.706 56.191 ;
     RECT  48.564 55.949 48.582 56.219 ;
     RECT  47.304 56.065 47.394 56.227 ;
     RECT  86.688 56.191 87.39 56.254 ;
     RECT  2.304 55.613 8.622 56.299 ;
     RECT  0.252 56.155 0.414 56.333 ;
     RECT  42.804 56.227 42.822 56.363 ;
     RECT  2.304 56.299 8.694 56.399 ;
     RECT  47.304 56.227 47.43 56.399 ;
     RECT  88.488 55.381 93.51 56.461 ;
     RECT  88.416 56.461 93.51 56.561 ;
     RECT  86.652 56.254 87.39 56.569 ;
     RECT  0.252 56.333 0.27 56.573 ;
     RECT  2.304 56.399 8.262 56.633 ;
     RECT  88.416 56.561 93.006 56.633 ;
     RECT  45.615 55.139 46.566 56.641 ;
     RECT  47.304 56.399 47.394 56.641 ;
     RECT  88.416 56.633 92.97 56.641 ;
     RECT  10.8 55.553 10.818 56.759 ;
     RECT  82.656 56.641 82.674 56.795 ;
     RECT  0.216 56.731 0.234 56.861 ;
     RECT  42.768 56.767 42.786 56.867 ;
     RECT  86.544 56.569 87.39 56.867 ;
     RECT  86.544 56.867 87.246 56.875 ;
     RECT  50.652 55.679 51.297 56.903 ;
     RECT  86.364 56.875 87.246 56.912 ;
     RECT  86.724 56.912 87.246 56.939 ;
     RECT  9.108 56.641 9.126 57.181 ;
     RECT  49.536 56.227 49.554 57.181 ;
     RECT  2.304 56.633 6.786 57.209 ;
     RECT  9.108 57.181 9.27 57.299 ;
     RECT  44.424 57.115 44.442 57.299 ;
     RECT  48.672 56.605 48.69 57.299 ;
     RECT  49.428 57.181 49.554 57.299 ;
     RECT  45.615 56.641 47.394 57.343 ;
     RECT  2.376 57.209 6.786 57.379 ;
     RECT  7.596 56.633 8.262 57.415 ;
     RECT  45.615 57.343 47.718 57.415 ;
     RECT  88.344 56.641 92.97 57.415 ;
     RECT  88.344 57.415 93.51 57.443 ;
     RECT  2.376 57.379 6.858 57.451 ;
     RECT  7.596 57.415 8.334 57.451 ;
     RECT  9.108 57.299 9.126 57.451 ;
     RECT  45.036 57.415 47.718 57.451 ;
     RECT  10.764 57.379 10.782 57.479 ;
     RECT  42.804 57.379 42.822 57.479 ;
     RECT  87.228 56.939 87.246 57.595 ;
     RECT  92.916 57.443 93.51 57.641 ;
     RECT  87.228 57.595 87.57 57.685 ;
     RECT  88.344 57.443 92.07 57.685 ;
     RECT  2.376 57.451 9.126 57.713 ;
     RECT  0.54 57.541 0.558 57.739 ;
     RECT  8.928 57.713 9.126 57.839 ;
     RECT  45.036 57.451 48.042 57.839 ;
     RECT  87.228 57.685 92.07 57.847 ;
     RECT  86.724 57.847 92.07 57.883 ;
     RECT  0.252 57.739 0.558 57.917 ;
     RECT  2.376 57.713 8.154 57.991 ;
     RECT  49.104 57.685 49.122 58.153 ;
     RECT  48.924 58.153 49.122 58.189 ;
     RECT  86.652 57.883 92.07 58.315 ;
     RECT  92.916 57.641 92.97 58.315 ;
     RECT  45.036 57.839 47.862 58.379 ;
     RECT  86.652 58.315 92.97 58.379 ;
     RECT  50.724 56.903 51.297 58.495 ;
     RECT  47.7 58.379 47.862 58.523 ;
     RECT  86.688 58.379 92.97 58.523 ;
     RECT  2.304 57.991 8.154 58.559 ;
     RECT  87.228 58.523 92.97 58.603 ;
     RECT  47.7 58.523 47.79 58.649 ;
     RECT  0.252 57.917 0.27 58.685 ;
     RECT  42.768 58.423 42.786 58.685 ;
     RECT  45.036 58.379 46.566 58.721 ;
     RECT  50.688 58.495 51.297 58.721 ;
     RECT  7.815 58.559 8.154 58.801 ;
     RECT  8.928 57.839 8.982 58.801 ;
     RECT  87.228 58.603 93.51 58.919 ;
     RECT  7.815 58.801 8.982 58.963 ;
     RECT  48.924 58.189 49.41 58.963 ;
     RECT  90.288 58.919 93.51 59.179 ;
     RECT  7.815 58.963 9.018 59.189 ;
     RECT  48.78 58.963 49.41 59.189 ;
     RECT  87.228 58.919 89.55 59.261 ;
     RECT  51.015 58.721 51.297 59.305 ;
     RECT  2.304 58.559 6.966 59.341 ;
     RECT  7.815 59.189 8.478 59.341 ;
     RECT  48.78 59.189 48.942 59.341 ;
     RECT  10.728 59.341 10.818 59.431 ;
     RECT  48.492 59.341 48.942 59.467 ;
     RECT  9.216 59.269 9.234 59.495 ;
     RECT  10.728 59.431 10.854 59.531 ;
     RECT  82.656 59.341 82.674 59.531 ;
     RECT  86.544 59.467 86.562 59.549 ;
     RECT  90.288 59.179 93.546 59.603 ;
     RECT  47.916 59.467 48.942 59.611 ;
     RECT  87.48 59.261 89.55 59.707 ;
     RECT  90.288 59.603 93.51 59.707 ;
     RECT  10.8 59.531 10.854 59.729 ;
     RECT  51.015 59.305 51.354 59.729 ;
     RECT  2.304 59.341 8.478 59.837 ;
     RECT  2.304 59.837 6.246 59.845 ;
     RECT  6.984 59.837 8.478 59.909 ;
     RECT  2.232 59.845 6.246 59.933 ;
     RECT  7.128 59.909 8.478 59.971 ;
     RECT  87.48 59.707 93.51 59.999 ;
     RECT  45.615 58.721 46.566 60.007 ;
     RECT  87.48 59.999 87.966 60.043 ;
     RECT  45.615 60.007 46.818 60.341 ;
     RECT  10.908 60.241 10.926 60.377 ;
     RECT  7.128 59.971 9.126 60.413 ;
     RECT  51.015 59.729 51.297 60.547 ;
     RECT  88.74 59.999 93.51 60.61 ;
     RECT  2.304 59.933 6.246 60.691 ;
     RECT  7.128 60.413 8.55 60.691 ;
     RECT  86.652 60.043 87.966 60.781 ;
     RECT  88.74 60.61 93.546 60.781 ;
     RECT  47.88 59.611 48.942 60.809 ;
     RECT  50.724 60.547 51.297 60.853 ;
     RECT  86.652 60.781 93.546 60.917 ;
     RECT  2.304 60.691 8.55 61.051 ;
     RECT  0.252 60.763 0.27 61.181 ;
     RECT  86.652 60.917 87.246 61.231 ;
     RECT  85.716 61.159 85.734 61.339 ;
     RECT  88.596 60.917 93.546 61.339 ;
     RECT  47.916 60.809 48.69 61.349 ;
     RECT  85.572 61.339 85.734 61.349 ;
     RECT  86.508 61.231 87.246 61.349 ;
     RECT  85.572 61.349 85.59 61.385 ;
     RECT  47.916 61.349 47.934 61.421 ;
     RECT  45.615 60.341 46.782 61.429 ;
     RECT  2.232 61.051 8.55 61.501 ;
     RECT  82.656 61.429 82.674 61.529 ;
     RECT  86.544 61.349 87.246 61.529 ;
     RECT  2.232 61.501 8.91 61.655 ;
     RECT  45.615 61.429 47.178 61.735 ;
     RECT  48.672 61.349 48.69 61.771 ;
     RECT  2.34 61.655 8.91 61.889 ;
     RECT  45.615 61.735 47.25 61.889 ;
     RECT  48.672 61.771 49.266 61.969 ;
     RECT  86.688 61.529 87.246 61.997 ;
     RECT  88.596 61.339 94.086 61.997 ;
     RECT  45.615 61.889 46.818 62.069 ;
     RECT  86.76 61.997 87.246 62.069 ;
     RECT  1.152 61.963 1.17 62.093 ;
     RECT  50.616 60.853 51.297 62.167 ;
     RECT  2.34 61.889 8.442 62.195 ;
     RECT  88.596 61.997 93.546 62.288 ;
     RECT  88.02 62.288 93.546 62.303 ;
     RECT  10.764 62.203 10.782 62.311 ;
     RECT  48.672 61.969 49.482 62.311 ;
     RECT  2.34 62.195 8.37 62.429 ;
     RECT  10.764 62.311 10.818 62.429 ;
     RECT  50.436 62.167 51.297 62.429 ;
     RECT  2.34 62.429 8.334 62.491 ;
     RECT  2.304 62.491 8.334 62.501 ;
     RECT  48.204 62.311 49.482 62.545 ;
     RECT  9.396 62.311 9.414 62.609 ;
     RECT  50.724 62.429 51.297 62.609 ;
     RECT  47.88 62.545 49.482 62.699 ;
     RECT  87.264 62.155 87.282 62.699 ;
     RECT  0.252 62.347 0.27 62.827 ;
     RECT  2.304 62.501 6.318 62.879 ;
     RECT  0.216 62.827 0.27 62.957 ;
     RECT  47.88 62.699 48.834 62.969 ;
     RECT  88.02 62.303 93.51 62.969 ;
     RECT  1.152 62.827 1.17 63.005 ;
     RECT  10.8 62.429 10.818 63.077 ;
     RECT  87.516 63.247 87.534 63.293 ;
     RECT  45.615 62.069 46.746 63.319 ;
     RECT  7.092 62.501 8.097 63.391 ;
     RECT  7.092 63.391 8.622 63.481 ;
     RECT  48.132 62.969 48.834 63.509 ;
     RECT  51.015 62.609 51.297 63.517 ;
     RECT  45.615 63.319 46.854 63.589 ;
     RECT  6.912 63.481 8.622 63.653 ;
     RECT  88.272 62.969 93.51 63.653 ;
     RECT  87.12 63.517 87.138 63.661 ;
     RECT  7.815 63.653 8.622 63.689 ;
     RECT  50.796 63.517 51.297 63.689 ;
     RECT  6.912 63.653 6.93 63.779 ;
     RECT  7.815 63.689 8.586 63.779 ;
     RECT  42.804 63.355 42.822 63.779 ;
     RECT  2.304 62.879 5.994 63.787 ;
     RECT  6.804 63.781 6.858 63.787 ;
     RECT  0.252 62.957 0.27 63.821 ;
     RECT  86.652 63.661 87.138 63.851 ;
     RECT  45.615 63.589 47.178 63.895 ;
     RECT  2.304 63.787 6.858 64.049 ;
     RECT  86.328 64.021 86.346 64.109 ;
     RECT  10.836 64.021 10.854 64.157 ;
     RECT  45.615 63.895 47.322 64.165 ;
     RECT  48.132 63.509 48.69 64.165 ;
     RECT  9.36 63.931 9.378 64.193 ;
     RECT  45.615 64.165 48.69 64.291 ;
     RECT  2.304 64.049 6.786 64.391 ;
     RECT  86.148 64.129 86.166 64.397 ;
     RECT  45.615 64.291 49.158 64.463 ;
     RECT  88.272 63.653 90.45 64.471 ;
     RECT  91.188 63.653 93.51 64.471 ;
     RECT  1.152 63.931 1.17 64.507 ;
     RECT  7.815 63.779 8.55 64.561 ;
     RECT  51.015 63.689 51.297 64.597 ;
     RECT  88.272 64.471 93.51 64.597 ;
     RECT  2.304 64.391 6.498 64.625 ;
     RECT  87.912 64.597 93.51 64.625 ;
     RECT  1.152 64.507 1.278 64.685 ;
     RECT  7.776 64.561 8.55 64.705 ;
     RECT  49.968 63.553 49.986 64.859 ;
     RECT  1.152 64.685 1.17 64.925 ;
     RECT  50.724 64.597 51.297 64.967 ;
     RECT  87.12 63.851 87.138 64.987 ;
     RECT  87.912 64.625 91.962 64.987 ;
     RECT  7.632 64.705 8.55 65.011 ;
     RECT  9.396 64.741 9.414 65.011 ;
     RECT  92.916 64.625 93.51 65.083 ;
     RECT  7.632 65.011 9.414 65.129 ;
     RECT  92.916 65.083 94.086 65.201 ;
     RECT  84.924 65.011 84.942 65.209 ;
     RECT  86.328 65.101 86.346 65.209 ;
     RECT  2.415 64.625 6.498 65.245 ;
     RECT  7.632 65.129 8.622 65.272 ;
     RECT  7.452 65.272 8.622 65.273 ;
     RECT  10.908 65.209 10.926 65.281 ;
     RECT  45.615 64.463 47.538 65.281 ;
     RECT  48.672 64.463 49.158 65.281 ;
     RECT  7.452 65.273 8.478 65.309 ;
     RECT  34.815 28.685 35.097 65.365 ;
     RECT  2.415 65.245 6.534 65.371 ;
     RECT  24.015 26.528 24.297 65.371 ;
     RECT  36.324 65.227 36.342 65.371 ;
     RECT  56.415 2.413 56.697 65.371 ;
     RECT  87.12 64.987 91.962 65.371 ;
     RECT  92.916 65.201 92.934 65.371 ;
     RECT  36.324 65.371 36.63 65.399 ;
     RECT  52.524 65.227 52.542 65.399 ;
     RECT  34.704 65.365 35.097 65.405 ;
     RECT  7.704 65.309 8.226 65.408 ;
     RECT  23.904 65.371 24.297 65.408 ;
     RECT  54.072 65.371 54.09 65.408 ;
     RECT  56.304 65.371 56.697 65.408 ;
     RECT  10.908 65.281 10.998 65.435 ;
     RECT  34.776 65.405 35.097 65.453 ;
     RECT  36.612 65.399 36.63 65.453 ;
     RECT  10.908 65.435 10.926 65.471 ;
     RECT  0.252 65.371 0.27 65.501 ;
     RECT  84.924 65.209 85.014 65.507 ;
     RECT  94.068 65.201 94.086 65.507 ;
     RECT  86.148 65.209 86.346 65.515 ;
     RECT  87.12 65.371 92.934 65.515 ;
     RECT  86.148 65.515 92.934 65.549 ;
     RECT  2.415 65.371 6.606 65.641 ;
     RECT  45.615 65.281 49.158 65.641 ;
     RECT  86.616 65.549 92.934 65.669 ;
     RECT  2.412 65.641 6.606 65.785 ;
     RECT  45.615 65.641 49.374 65.849 ;
     RECT  87.912 65.669 92.934 65.947 ;
     RECT  48.996 65.849 49.374 66.119 ;
     RECT  7.815 65.408 8.226 66.181 ;
     RECT  45.615 65.849 48.258 66.209 ;
     RECT  2.304 65.785 6.606 66.217 ;
     RECT  7.815 66.181 8.37 66.217 ;
     RECT  2.304 66.217 8.37 66.269 ;
     RECT  7.776 66.269 8.37 66.289 ;
     RECT  84.924 65.507 84.942 66.289 ;
     RECT  7.776 66.289 9.09 66.325 ;
     RECT  84.924 66.289 85.014 66.325 ;
     RECT  45.615 66.209 47.106 66.479 ;
     RECT  48.024 66.209 48.258 66.479 ;
     RECT  48.996 66.119 49.338 66.479 ;
     RECT  51.015 64.967 51.297 66.487 ;
     RECT  87.912 65.947 93.51 66.515 ;
     RECT  84.924 66.325 85.086 66.551 ;
     RECT  86.616 65.669 86.994 66.559 ;
     RECT  87.912 66.515 90.09 66.559 ;
     RECT  2.304 66.269 6.678 66.623 ;
     RECT  86.616 66.559 90.09 66.623 ;
     RECT  7.776 66.325 9.234 66.659 ;
     RECT  90.864 66.515 93.51 66.667 ;
     RECT  48.996 66.479 49.266 66.749 ;
     RECT  90.864 66.667 94.086 66.821 ;
     RECT  10.764 66.721 10.782 66.857 ;
     RECT  86.616 66.623 88.002 67.019 ;
     RECT  0.252 66.955 0.27 67.085 ;
     RECT  45.615 66.479 47.034 67.261 ;
     RECT  50.724 66.487 51.297 67.261 ;
     RECT  88.815 66.623 90.09 67.297 ;
     RECT  90.864 66.821 93.546 67.297 ;
     RECT  7.776 66.659 8.586 67.369 ;
     RECT  48.24 66.479 48.258 67.369 ;
     RECT  2.304 66.623 6.534 67.405 ;
     RECT  7.344 67.369 8.586 67.405 ;
     RECT  84.924 66.551 84.942 67.405 ;
     RECT  84.924 67.405 85.086 67.433 ;
     RECT  84.96 67.433 85.086 67.441 ;
     RECT  13.215 26.528 13.497 67.531 ;
     RECT  22.644 67.483 22.662 67.531 ;
     RECT  49.068 66.749 49.266 67.559 ;
     RECT  84.96 67.441 85.158 67.559 ;
     RECT  13.104 67.531 13.497 67.568 ;
     RECT  85.068 67.559 85.158 67.595 ;
     RECT  10.8 67.531 10.818 67.631 ;
     RECT  49.068 67.559 49.086 67.631 ;
     RECT  85.14 67.595 85.158 67.631 ;
     RECT  2.304 67.405 8.586 67.675 ;
     RECT  9.432 67.441 9.45 67.675 ;
     RECT  87.48 67.019 88.002 67.711 ;
     RECT  88.815 67.297 93.546 67.711 ;
     RECT  2.304 67.675 9.45 67.739 ;
     RECT  13.215 67.568 13.497 67.771 ;
     RECT  18.615 3.101 18.897 67.771 ;
     RECT  22.644 67.531 22.986 67.771 ;
     RECT  48.06 67.369 48.258 67.801 ;
     RECT  86.184 67.261 86.274 67.801 ;
     RECT  2.304 67.739 9.126 67.805 ;
     RECT  2.304 67.805 8.766 67.829 ;
     RECT  13.215 67.771 13.59 67.829 ;
     RECT  18.615 67.771 18.99 67.829 ;
     RECT  22.608 67.771 22.986 67.829 ;
     RECT  86.184 67.801 86.706 67.901 ;
     RECT  87.48 67.711 93.546 67.901 ;
     RECT  48.06 67.801 48.726 67.945 ;
     RECT  86.184 67.901 86.526 68.071 ;
     RECT  22.644 67.829 22.986 68.099 ;
     RECT  43.344 65.443 43.362 68.107 ;
     RECT  86.112 68.071 86.526 68.141 ;
     RECT  42.804 68.107 43.362 68.143 ;
     RECT  2.34 67.829 8.766 68.171 ;
     RECT  45.036 67.261 47.034 68.171 ;
     RECT  93.492 67.901 93.546 68.171 ;
     RECT  23.04 68.107 23.058 68.207 ;
     RECT  45.615 68.171 47.034 68.215 ;
     RECT  48.024 67.945 48.726 68.215 ;
     RECT  0.252 68.107 0.27 68.237 ;
     RECT  86.508 68.141 86.526 68.333 ;
     RECT  67.215 28.688 67.497 68.341 ;
     RECT  45.615 68.215 48.726 68.369 ;
     RECT  87.48 67.901 92.538 68.369 ;
     RECT  67.215 68.341 67.59 68.381 ;
     RECT  88.596 68.369 92.538 68.405 ;
     RECT  48.204 68.369 48.726 68.521 ;
     RECT  48.204 68.521 48.906 68.639 ;
     RECT  42.768 68.143 43.362 68.675 ;
     RECT  87.48 68.369 87.75 68.683 ;
     RECT  10.8 68.611 10.818 68.711 ;
     RECT  2.34 68.171 8.73 68.791 ;
     RECT  48.312 68.639 48.906 68.791 ;
     RECT  65.268 68.299 65.286 68.791 ;
     RECT  88.815 68.405 92.538 68.791 ;
     RECT  42.768 68.675 42.786 68.819 ;
     RECT  67.215 68.381 67.497 68.881 ;
     RECT  85.5 68.647 85.518 68.881 ;
     RECT  65.268 68.791 65.322 68.909 ;
     RECT  48.312 68.791 49.086 68.945 ;
     RECT  65.304 68.909 65.322 68.957 ;
     RECT  66.672 68.881 67.497 68.957 ;
     RECT  2.304 68.791 8.73 68.981 ;
     RECT  84.924 68.881 85.518 68.981 ;
     RECT  87.372 68.683 87.75 68.989 ;
     RECT  50.688 67.261 51.297 69.061 ;
     RECT  85.5 68.981 85.518 69.089 ;
     RECT  88.815 68.791 92.754 69.115 ;
     RECT  93.492 68.171 93.51 69.115 ;
     RECT  88.815 69.115 93.51 69.179 ;
     RECT  50.4 69.061 51.297 69.223 ;
     RECT  91.044 69.179 93.51 69.25 ;
     RECT  2.304 68.981 8.478 69.341 ;
     RECT  48.312 68.945 48.402 69.449 ;
     RECT  50.292 69.223 51.297 69.449 ;
     RECT  88.815 69.179 90.198 69.449 ;
     RECT  91.044 69.25 93.546 69.485 ;
     RECT  86.652 68.989 87.75 69.493 ;
     RECT  2.304 69.341 8.097 69.521 ;
     RECT  86.616 69.493 87.75 69.521 ;
     RECT  92.448 69.485 93.546 69.521 ;
     RECT  2.304 69.521 5.67 69.719 ;
     RECT  87.48 69.521 87.75 69.719 ;
     RECT  2.34 69.719 5.67 69.728 ;
     RECT  86.616 69.521 86.742 69.755 ;
     RECT  83.415 52.709 83.697 69.763 ;
     RECT  10.8 69.799 10.818 69.961 ;
     RECT  50.724 69.449 51.297 69.989 ;
     RECT  82.728 69.763 83.697 69.989 ;
     RECT  45.615 68.369 47.286 69.997 ;
     RECT  91.044 69.485 91.53 70.069 ;
     RECT  10.728 69.961 10.818 70.097 ;
     RECT  42.768 69.997 42.786 70.097 ;
     RECT  54.648 69.997 54.666 70.097 ;
     RECT  92.448 69.521 93.51 70.097 ;
     RECT  6.624 69.521 8.097 70.105 ;
     RECT  49.248 70.069 49.266 70.105 ;
     RECT  87.624 69.719 87.75 70.105 ;
     RECT  88.815 69.449 90.09 70.105 ;
     RECT  49.248 70.105 49.518 70.141 ;
     RECT  90.9 70.069 91.53 70.231 ;
     RECT  92.448 70.097 92.466 70.231 ;
     RECT  45.615 69.997 47.322 70.259 ;
     RECT  90.9 70.231 92.466 70.259 ;
     RECT  49.248 70.141 49.59 70.267 ;
     RECT  90.9 70.259 92.07 70.267 ;
     RECT  93.492 70.097 93.51 70.267 ;
     RECT  10.8 70.097 10.818 70.331 ;
     RECT  6.624 70.105 8.622 70.339 ;
     RECT  49.104 70.267 49.59 70.375 ;
     RECT  6.624 70.339 9.27 70.411 ;
     RECT  48.672 70.375 49.59 70.411 ;
     RECT  87.624 70.105 90.09 70.411 ;
     RECT  90.828 70.267 92.07 70.411 ;
     RECT  44.46 69.187 44.478 70.529 ;
     RECT  86.688 69.755 86.742 70.603 ;
     RECT  87.624 70.411 92.07 70.603 ;
     RECT  6.372 70.411 9.27 70.637 ;
     RECT  45.615 70.259 46.854 70.637 ;
     RECT  86.688 70.603 92.07 70.643 ;
     RECT  2.34 69.728 5.634 70.651 ;
     RECT  6.372 70.637 9.234 70.651 ;
     RECT  2.34 70.651 9.234 70.673 ;
     RECT  85.5 70.573 85.518 70.709 ;
     RECT  86.688 70.643 86.778 70.747 ;
     RECT  87.552 70.643 92.07 70.799 ;
     RECT  88.2 70.799 92.07 70.835 ;
     RECT  88.38 70.835 92.07 70.943 ;
     RECT  86.58 70.747 86.778 70.973 ;
     RECT  48.564 70.411 49.59 71.149 ;
     RECT  93.492 70.267 94.086 71.275 ;
     RECT  92.916 71.275 94.086 71.311 ;
     RECT  2.34 70.673 9.162 71.339 ;
     RECT  48.06 71.149 49.59 71.339 ;
     RECT  51.015 69.989 51.297 71.419 ;
     RECT  92.448 71.311 94.086 71.447 ;
     RECT  2.34 71.339 8.91 71.455 ;
     RECT  45.615 70.637 46.782 71.491 ;
     RECT  50.868 71.419 51.297 71.491 ;
     RECT  86.724 70.973 86.778 71.491 ;
     RECT  2.304 71.455 8.91 71.609 ;
     RECT  86.724 71.491 86.814 71.617 ;
     RECT  2.34 71.609 8.838 71.645 ;
     RECT  2.34 71.645 8.55 71.681 ;
     RECT  45.615 71.491 46.818 71.681 ;
     RECT  88.38 70.943 91.71 71.681 ;
     RECT  92.448 71.447 93.546 71.681 ;
     RECT  90.072 71.681 91.71 71.761 ;
     RECT  92.448 71.681 93.51 71.761 ;
     RECT  88.38 71.681 89.334 71.803 ;
     RECT  86.724 71.617 86.85 71.851 ;
     RECT  2.34 71.681 5.85 71.879 ;
     RECT  0.252 69.019 0.27 71.981 ;
     RECT  48.06 71.339 49.122 72.031 ;
     RECT  50.796 71.491 51.297 72.031 ;
     RECT  85.896 71.803 85.914 72.185 ;
     RECT  90.072 71.761 93.51 72.221 ;
     RECT  6.84 71.681 8.55 72.293 ;
     RECT  86.724 71.851 86.922 72.301 ;
     RECT  6.84 72.293 8.514 72.329 ;
     RECT  47.772 72.031 49.122 72.391 ;
     RECT  86.724 72.301 87.246 72.419 ;
     RECT  50.688 72.031 51.297 72.427 ;
     RECT  86.724 72.419 86.85 72.427 ;
     RECT  45.615 71.681 46.782 72.463 ;
     RECT  88.056 71.803 89.334 72.499 ;
     RECT  90.072 72.221 91.782 72.499 ;
     RECT  6.84 72.329 8.298 72.523 ;
     RECT  86.688 72.427 86.85 72.527 ;
     RECT  45.615 72.463 46.818 72.563 ;
     RECT  47.772 72.391 49.194 72.563 ;
     RECT  50.652 72.427 51.297 72.599 ;
     RECT  2.34 71.879 5.49 72.661 ;
     RECT  6.552 72.523 8.298 72.689 ;
     RECT  6.552 72.689 8.154 72.733 ;
     RECT  2.34 72.661 5.742 72.763 ;
     RECT  2.268 72.763 5.742 72.841 ;
     RECT  6.516 72.733 8.154 72.841 ;
     RECT  92.916 72.221 93.51 72.859 ;
     RECT  10.8 72.499 10.818 72.869 ;
     RECT  2.268 72.841 8.154 72.893 ;
     RECT  88.056 72.499 91.782 72.931 ;
     RECT  2.304 72.893 8.154 72.959 ;
     RECT  87.768 72.931 91.782 73.003 ;
     RECT  92.916 72.859 93.546 73.003 ;
     RECT  2.304 72.959 5.742 73.031 ;
     RECT  87.768 73.003 93.546 73.067 ;
     RECT  42.768 73.111 42.786 73.229 ;
     RECT  86.832 72.527 86.85 73.237 ;
     RECT  87.768 73.067 92.178 73.237 ;
     RECT  45.615 72.563 46.566 73.309 ;
     RECT  47.772 72.563 49.158 73.309 ;
     RECT  86.832 73.237 92.178 73.309 ;
     RECT  50.724 72.599 51.297 73.409 ;
     RECT  45.615 73.309 49.158 73.499 ;
     RECT  6.516 72.959 8.154 73.531 ;
     RECT  92.916 73.067 93.546 73.579 ;
     RECT  86.652 73.309 92.178 73.615 ;
     RECT  48.456 73.499 49.158 73.651 ;
     RECT  48.456 73.651 49.374 73.769 ;
     RECT  86.04 73.615 92.178 73.769 ;
     RECT  2.304 73.031 5.67 73.777 ;
     RECT  92.916 73.579 94.086 73.849 ;
     RECT  92.916 73.849 94.158 73.885 ;
     RECT  9.432 73.579 9.45 73.913 ;
     RECT  86.652 73.769 91.998 73.913 ;
     RECT  6.516 73.531 8.406 73.921 ;
     RECT  10.836 73.741 10.854 73.949 ;
     RECT  6.516 73.921 8.514 74.039 ;
     RECT  82.656 73.849 82.674 74.039 ;
     RECT  92.736 73.885 94.158 74.045 ;
     RECT  2.304 73.777 5.706 74.191 ;
     RECT  45.615 73.499 47.718 74.219 ;
     RECT  48.456 73.769 49.158 74.309 ;
     RECT  51.015 73.409 51.297 74.317 ;
     RECT  10.8 74.389 10.818 74.461 ;
     RECT  2.304 74.191 6.102 74.489 ;
     RECT  86.652 73.913 86.742 74.489 ;
     RECT  48.456 74.309 48.474 74.579 ;
     RECT  6.984 74.039 8.514 74.587 ;
     RECT  87.516 73.913 91.998 74.587 ;
     RECT  92.736 74.045 93.51 74.587 ;
     RECT  10.764 74.461 10.818 74.615 ;
     RECT  47.7 74.219 47.718 74.623 ;
     RECT  50.724 74.317 51.297 74.731 ;
     RECT  49.32 74.587 49.338 74.849 ;
     RECT  50.22 74.731 51.297 74.849 ;
     RECT  50.724 74.849 51.297 74.957 ;
     RECT  2.376 74.489 6.102 75.001 ;
     RECT  6.984 74.587 9.054 75.001 ;
     RECT  50.796 74.957 51.297 75.029 ;
     RECT  82.656 75.001 82.674 75.119 ;
     RECT  87.516 74.587 93.51 75.127 ;
     RECT  0.252 75.019 0.27 75.149 ;
     RECT  2.376 75.001 9.054 75.191 ;
     RECT  87.156 75.127 93.51 75.227 ;
     RECT  87.156 75.227 92.43 75.271 ;
     RECT  93.492 75.227 93.51 75.307 ;
     RECT  2.376 75.191 8.514 75.389 ;
     RECT  48.888 75.235 48.906 75.389 ;
     RECT  2.376 75.389 8.37 75.451 ;
     RECT  93.492 75.307 94.086 75.461 ;
     RECT  86.724 75.271 92.43 75.469 ;
     RECT  10.8 74.615 10.818 75.505 ;
     RECT  47.7 74.623 48.15 75.541 ;
     RECT  2.34 75.451 8.37 75.542 ;
     RECT  86.652 75.469 92.43 75.569 ;
     RECT  0.288 75.499 0.306 75.595 ;
     RECT  10.764 75.505 10.818 75.659 ;
     RECT  47.664 75.541 48.15 75.659 ;
     RECT  0.288 75.595 0.414 75.773 ;
     RECT  47.844 75.659 48.15 75.811 ;
     RECT  93.492 75.461 93.546 76.001 ;
     RECT  10.8 75.659 10.818 76.037 ;
     RECT  93.492 76.001 93.51 76.171 ;
     RECT  86.652 75.569 91.89 76.199 ;
     RECT  2.376 75.542 8.37 76.207 ;
     RECT  51.015 75.029 51.297 76.207 ;
     RECT  86.652 76.199 86.742 76.235 ;
     RECT  2.376 76.207 9.054 76.315 ;
     RECT  2.304 76.315 9.054 76.343 ;
     RECT  90.252 76.199 91.89 76.363 ;
     RECT  2.304 76.343 8.334 76.379 ;
     RECT  47.844 75.811 48.69 76.469 ;
     RECT  48.456 76.469 48.69 76.621 ;
     RECT  90.252 76.363 92.034 76.711 ;
     RECT  92.916 76.171 93.51 76.711 ;
     RECT  6.984 76.379 8.334 76.739 ;
     RECT  87.768 76.199 89.478 76.739 ;
     RECT  0.252 76.171 0.27 76.747 ;
     RECT  0.252 76.747 0.306 76.783 ;
     RECT  45.615 74.219 46.566 76.819 ;
     RECT  50.724 76.207 51.297 76.819 ;
     RECT  0.252 76.783 0.378 76.829 ;
     RECT  0.252 76.829 0.306 76.891 ;
     RECT  2.304 76.379 6.03 76.919 ;
     RECT  0.216 76.891 0.306 76.928 ;
     RECT  88.815 76.739 89.478 76.939 ;
     RECT  90.252 76.711 93.51 76.939 ;
     RECT  2.34 76.919 6.03 77.009 ;
     RECT  48.456 76.621 49.23 77.009 ;
     RECT  86.652 76.235 86.67 77.053 ;
     RECT  2.415 77.009 6.03 77.125 ;
     RECT  9.144 76.711 9.234 77.125 ;
     RECT  48.528 77.009 49.23 77.125 ;
     RECT  50.004 76.819 51.297 77.125 ;
     RECT  45.615 76.819 46.782 77.161 ;
     RECT  86.076 77.053 86.67 77.161 ;
     RECT  9.144 77.125 9.306 77.279 ;
     RECT  88.815 76.939 93.51 77.279 ;
     RECT  87.768 76.739 87.966 77.287 ;
     RECT  0.288 76.928 0.306 77.309 ;
     RECT  9.288 77.279 9.306 77.315 ;
     RECT  7.02 76.739 8.334 77.323 ;
     RECT  92.736 77.279 93.51 77.467 ;
     RECT  83.415 69.989 83.697 77.521 ;
     RECT  2.415 77.125 6.066 77.557 ;
     RECT  7.02 77.323 8.55 77.557 ;
     RECT  2.415 77.557 8.55 77.621 ;
     RECT  45.615 77.161 46.818 77.693 ;
     RECT  87.732 77.287 87.966 77.701 ;
     RECT  2.415 77.621 8.298 77.755 ;
     RECT  10.8 77.701 10.818 77.819 ;
     RECT  48.528 77.125 51.297 77.819 ;
     RECT  86.076 77.161 86.706 77.855 ;
     RECT  87.66 77.701 87.966 77.855 ;
     RECT  86.112 77.855 86.706 77.863 ;
     RECT  92.736 77.467 94.086 77.927 ;
     RECT  86.112 77.863 87.21 77.999 ;
     RECT  88.815 77.279 91.89 78.061 ;
     RECT  48.528 77.819 49.95 78.077 ;
     RECT  86.112 77.999 87.102 78.125 ;
     RECT  88.344 78.061 91.89 78.331 ;
     RECT  92.736 77.927 93.51 78.331 ;
     RECT  2.304 77.755 8.298 78.439 ;
     RECT  47.628 77.863 47.646 78.475 ;
     RECT  47.556 78.475 47.646 78.511 ;
     RECT  48.528 78.077 49.554 78.511 ;
     RECT  10.836 78.439 10.854 78.539 ;
     RECT  82.656 76.711 82.674 78.539 ;
     RECT  88.344 78.331 93.51 78.601 ;
     RECT  47.556 78.511 49.554 78.629 ;
     RECT  2.304 78.439 8.622 78.637 ;
     RECT  87.084 78.125 87.102 78.665 ;
     RECT  9.396 78.511 9.414 78.709 ;
     RECT  48.168 78.629 49.554 78.773 ;
     RECT  0.252 78.667 0.27 78.797 ;
     RECT  87.876 78.601 93.51 78.899 ;
     RECT  86.112 78.125 86.13 78.907 ;
     RECT  9.396 78.709 9.45 78.971 ;
     RECT  50.724 77.819 51.297 78.979 ;
     RECT  86.112 78.907 86.778 78.979 ;
     RECT  50.112 78.979 51.297 79.079 ;
     RECT  2.268 78.637 8.622 79.141 ;
     RECT  2.268 79.141 9.126 79.169 ;
     RECT  48.168 78.773 49.05 79.169 ;
     RECT  50.112 79.079 50.13 79.169 ;
     RECT  2.268 79.169 8.262 79.277 ;
     RECT  83.415 77.521 84.402 79.349 ;
     RECT  86.076 78.979 86.778 79.447 ;
     RECT  48.168 79.169 48.726 79.519 ;
     RECT  47.88 79.519 48.726 79.709 ;
     RECT  82.656 79.591 82.674 79.709 ;
     RECT  86.04 79.447 87.282 79.717 ;
     RECT  0.252 79.627 0.27 79.757 ;
     RECT  85.896 79.717 87.282 79.757 ;
     RECT  85.968 79.757 87.282 79.861 ;
     RECT  88.02 78.899 93.51 79.861 ;
     RECT  2.304 79.277 8.262 79.951 ;
     RECT  9.108 79.169 9.126 79.951 ;
     RECT  2.304 79.951 9.126 79.979 ;
     RECT  48.456 79.709 48.726 79.979 ;
     RECT  7.815 79.979 9.126 80.023 ;
     RECT  45.615 77.693 46.782 80.249 ;
     RECT  85.968 79.861 93.51 80.249 ;
     RECT  85.968 80.249 86.778 80.519 ;
     RECT  10.8 80.401 10.818 80.591 ;
     RECT  0.216 80.491 0.234 80.621 ;
     RECT  48.708 79.979 48.726 80.671 ;
     RECT  7.815 80.023 9.306 80.761 ;
     RECT  47.304 80.401 47.322 80.789 ;
     RECT  48.708 80.671 49.014 80.789 ;
     RECT  7.815 80.761 9.378 80.861 ;
     RECT  87.768 80.249 93.51 80.861 ;
     RECT  7.815 80.861 9.306 80.897 ;
     RECT  48.708 80.789 48.906 80.909 ;
     RECT  2.34 79.979 7.002 80.923 ;
     RECT  2.268 80.923 7.002 80.941 ;
     RECT  7.815 80.897 9.126 80.941 ;
     RECT  0.252 80.923 0.27 81.053 ;
     RECT  1.116 80.923 1.134 81.053 ;
     RECT  48.708 80.909 48.834 81.059 ;
     RECT  51.015 79.079 51.297 81.067 ;
     RECT  2.268 80.941 9.126 81.167 ;
     RECT  0.324 81.067 0.342 81.197 ;
     RECT  48.708 81.059 48.798 81.211 ;
     RECT  2.304 81.167 9.126 81.329 ;
     RECT  47.628 81.211 47.646 81.329 ;
     RECT  48.636 81.211 48.798 81.329 ;
     RECT  87.768 80.861 92.97 81.329 ;
     RECT  50.724 81.067 51.297 81.337 ;
     RECT  45.615 80.249 46.566 81.373 ;
     RECT  49.86 81.175 49.878 81.401 ;
     RECT  86.652 80.519 86.706 81.499 ;
     RECT  87.768 81.329 92.142 81.499 ;
     RECT  50.688 81.337 51.297 81.509 ;
     RECT  0.54 81.445 0.558 81.533 ;
     RECT  2.304 81.329 8.982 81.599 ;
     RECT  50.724 81.509 51.297 81.643 ;
     RECT  92.916 81.329 92.97 81.643 ;
     RECT  50.724 81.643 51.39 81.773 ;
     RECT  48.78 81.329 48.798 81.869 ;
     RECT  82.656 81.751 82.674 81.869 ;
     RECT  86.652 81.499 92.142 81.917 ;
     RECT  50.724 81.773 51.297 81.941 ;
     RECT  45.615 81.373 46.818 81.949 ;
     RECT  10.836 81.841 10.854 81.977 ;
     RECT  87.408 81.917 92.142 82.075 ;
     RECT  92.916 81.643 93.51 82.075 ;
     RECT  45.615 81.949 46.962 82.139 ;
     RECT  87.408 82.075 93.51 82.139 ;
     RECT  2.415 81.599 8.982 82.147 ;
     RECT  87.408 82.139 92.142 82.175 ;
     RECT  2.415 82.147 9.054 82.247 ;
     RECT  0.216 81.949 0.414 82.253 ;
     RECT  86.652 81.917 86.67 82.319 ;
     RECT  2.415 82.247 8.622 82.349 ;
     RECT  2.415 82.349 5.922 82.409 ;
     RECT  42.804 82.291 42.822 82.409 ;
     RECT  49.644 82.255 49.662 82.489 ;
     RECT  92.916 82.139 93.51 82.507 ;
     RECT  2.415 82.409 5.814 82.637 ;
     RECT  87.408 82.175 92.034 82.651 ;
     RECT  92.916 82.507 94.086 82.787 ;
     RECT  48.06 82.561 48.078 82.831 ;
     RECT  45.615 82.139 46.854 82.921 ;
     RECT  47.592 82.831 48.078 82.921 ;
     RECT  0.216 82.253 0.234 82.973 ;
     RECT  2.415 82.637 5.778 83.029 ;
     RECT  6.804 82.349 8.622 83.029 ;
     RECT  45.615 82.921 48.078 83.101 ;
     RECT  49.14 82.489 49.662 83.101 ;
     RECT  0.252 82.987 0.306 83.117 ;
     RECT  6.804 83.029 9.126 83.129 ;
     RECT  86.688 82.651 92.034 83.129 ;
     RECT  86.868 83.129 92.034 83.179 ;
     RECT  92.916 82.787 93.51 83.179 ;
     RECT  2.304 83.029 5.778 83.219 ;
     RECT  10.836 82.993 10.854 83.219 ;
     RECT  2.412 83.219 5.778 83.371 ;
     RECT  6.804 83.129 8.982 83.371 ;
     RECT  2.412 83.371 8.982 83.561 ;
     RECT  86.868 83.179 93.51 83.633 ;
     RECT  86.868 83.633 86.886 83.645 ;
     RECT  87.804 83.633 93.51 83.659 ;
     RECT  45.615 83.101 49.662 83.759 ;
     RECT  47.628 83.759 49.662 84.029 ;
     RECT  51.015 81.941 51.297 84.037 ;
     RECT  2.412 83.561 5.922 84.181 ;
     RECT  2.304 84.181 5.922 84.415 ;
     RECT  6.696 83.561 8.982 84.415 ;
     RECT  2.304 84.415 8.982 84.541 ;
     RECT  87.804 83.659 93.546 84.613 ;
     RECT  10.8 84.541 10.854 84.641 ;
     RECT  2.304 84.541 9.234 84.677 ;
     RECT  47.628 84.029 49.158 84.685 ;
     RECT  9.036 84.677 9.234 84.713 ;
     RECT  86.652 84.451 86.67 84.721 ;
     RECT  87.408 84.613 93.546 84.721 ;
     RECT  9.036 84.713 9.126 84.839 ;
     RECT  10.836 84.641 10.854 84.839 ;
     RECT  47.592 84.685 49.158 84.839 ;
     RECT  2.304 84.677 8.19 84.875 ;
     RECT  9.108 84.839 9.126 84.875 ;
     RECT  50.796 84.037 51.297 84.875 ;
     RECT  86.652 84.721 93.546 84.911 ;
     RECT  86.652 84.911 93.51 85.145 ;
     RECT  45.615 83.759 46.818 85.225 ;
     RECT  47.592 84.839 48.402 85.225 ;
     RECT  0.252 83.117 0.27 85.277 ;
     RECT  86.652 85.145 86.742 85.289 ;
     RECT  45.615 85.225 48.402 85.451 ;
     RECT  42.804 85.387 42.822 85.487 ;
     RECT  47.592 85.451 48.402 85.487 ;
     RECT  51.015 84.875 51.297 85.657 ;
     RECT  49.284 85.495 49.302 85.685 ;
     RECT  50.724 85.657 51.297 85.757 ;
     RECT  45.615 85.451 46.782 85.919 ;
     RECT  2.304 84.875 8.097 85.949 ;
     RECT  87.912 85.145 93.51 85.957 ;
     RECT  42.768 85.927 42.786 86.027 ;
     RECT  2.376 85.949 8.097 86.035 ;
     RECT  86.652 85.289 86.67 86.035 ;
     RECT  86.652 86.035 86.994 86.059 ;
     RECT  87.912 85.957 93.546 86.059 ;
     RECT  2.376 86.035 8.19 86.189 ;
     RECT  2.415 86.189 8.19 86.237 ;
     RECT  9.108 86.071 9.126 86.261 ;
     RECT  47.592 85.487 47.61 86.269 ;
     RECT  48.348 85.487 48.402 86.269 ;
     RECT  47.592 86.269 48.402 86.305 ;
     RECT  84.924 84.883 84.942 86.333 ;
     RECT  47.592 86.305 48.69 86.341 ;
     RECT  47.484 86.341 48.69 86.381 ;
     RECT  2.415 86.237 8.154 86.495 ;
     RECT  86.004 86.059 93.546 86.495 ;
     RECT  82.656 85.729 82.674 86.531 ;
     RECT  47.808 86.381 48.69 86.603 ;
     RECT  86.652 86.495 93.546 86.621 ;
     RECT  51.015 85.757 51.297 86.701 ;
     RECT  45.615 85.919 46.674 86.773 ;
     RECT  87.984 86.621 93.546 86.827 ;
     RECT  87.984 86.827 93.582 86.837 ;
     RECT  49.896 86.809 49.914 86.881 ;
     RECT  45.615 86.773 46.782 86.999 ;
     RECT  86.652 86.621 86.994 87.035 ;
     RECT  0.252 86.299 0.27 87.101 ;
     RECT  48.6 86.603 48.69 87.109 ;
     RECT  49.428 86.881 49.914 87.109 ;
     RECT  50.724 86.701 51.297 87.179 ;
     RECT  7.815 86.495 8.154 87.241 ;
     RECT  88.128 86.837 93.582 87.269 ;
     RECT  7.815 87.241 8.766 87.341 ;
     RECT  2.415 86.495 7.002 87.385 ;
     RECT  7.815 87.341 8.334 87.385 ;
     RECT  56.415 65.408 56.697 87.385 ;
     RECT  67.215 68.957 67.497 87.385 ;
     RECT  78.015 2.413 78.297 87.385 ;
     RECT  56.304 87.385 56.697 87.437 ;
     RECT  67.104 87.385 67.497 87.437 ;
     RECT  77.904 87.385 78.297 87.437 ;
     RECT  18.615 67.829 18.897 87.547 ;
     RECT  21.816 87.421 21.834 87.547 ;
     RECT  21.744 87.547 21.834 87.655 ;
     RECT  20.664 87.655 20.682 87.691 ;
     RECT  21.672 87.655 21.834 87.691 ;
     RECT  88.236 87.269 93.582 87.691 ;
     RECT  10.764 87.349 10.782 87.781 ;
     RECT  19.728 3.101 19.746 87.781 ;
     RECT  20.664 87.691 21.834 87.781 ;
     RECT  45.615 86.999 46.674 87.809 ;
     RECT  47.808 86.603 47.826 87.883 ;
     RECT  48.6 87.109 49.914 87.883 ;
     RECT  17.568 87.781 17.874 87.925 ;
     RECT  18.615 87.547 18.954 87.925 ;
     RECT  16.992 87.925 18.954 87.961 ;
     RECT  19.728 87.781 21.834 87.961 ;
     RECT  9.252 87.925 9.27 88.123 ;
     RECT  2.415 87.385 8.334 88.159 ;
     RECT  16.56 87.961 21.834 88.159 ;
     RECT  45.615 87.809 45.897 88.159 ;
     RECT  14.832 87.781 14.85 88.231 ;
     RECT  47.808 87.883 49.914 88.231 ;
     RECT  86.976 87.035 86.994 88.231 ;
     RECT  88.236 87.691 94.086 88.231 ;
     RECT  9.144 88.123 9.27 88.315 ;
     RECT  9.144 88.315 9.882 88.321 ;
     RECT  47.7 88.231 49.914 88.349 ;
     RECT  86.904 88.231 86.994 88.349 ;
     RECT  2.415 88.159 8.37 88.363 ;
     RECT  14.544 88.231 14.85 88.393 ;
     RECT  9.144 88.321 9.954 88.429 ;
     RECT  10.692 87.781 10.782 88.429 ;
     RECT  87.768 88.231 94.086 88.429 ;
     RECT  16.128 88.159 21.834 88.456 ;
     RECT  2.304 88.363 8.37 88.465 ;
     RECT  9.144 88.429 10.782 88.465 ;
     RECT  46.764 87.925 46.818 88.465 ;
     RECT  86.76 88.357 86.778 88.465 ;
     RECT  16.128 88.456 21.978 88.493 ;
     RECT  13.215 67.829 13.497 88.501 ;
     RECT  2.304 88.465 10.782 88.591 ;
     RECT  17.892 88.493 21.978 88.591 ;
     RECT  82.656 88.231 82.674 88.619 ;
     RECT  13.215 88.501 13.698 88.663 ;
     RECT  0.252 88.555 0.27 88.685 ;
     RECT  86.652 88.465 86.778 88.691 ;
     RECT  12.564 88.663 13.698 88.735 ;
     RECT  16.128 88.493 17.154 88.735 ;
     RECT  2.304 88.591 11.502 88.771 ;
     RECT  12.528 88.735 13.698 88.771 ;
     RECT  17.892 88.591 22.014 88.861 ;
     RECT  48.06 88.349 49.914 88.889 ;
     RECT  14.544 88.393 14.922 88.891 ;
     RECT  2.304 88.771 13.698 88.925 ;
     RECT  14.544 88.891 14.994 89.005 ;
     RECT  15.948 88.735 17.154 89.005 ;
     RECT  14.544 89.005 17.154 89.041 ;
     RECT  17.892 88.861 22.59 89.131 ;
     RECT  48.06 88.889 48.834 89.159 ;
     RECT  8.856 88.925 13.698 89.167 ;
     RECT  14.436 89.041 17.154 89.167 ;
     RECT  51.015 87.179 51.297 89.167 ;
     RECT  8.856 89.167 17.154 89.195 ;
     RECT  75.564 27.917 75.582 89.231 ;
     RECT  46.764 88.465 46.998 89.239 ;
     RECT  50.796 89.167 51.297 89.239 ;
     RECT  86.76 88.691 86.778 89.275 ;
     RECT  87.732 88.429 94.086 89.275 ;
     RECT  86.76 89.275 94.086 89.303 ;
     RECT  46.764 89.239 47.538 89.429 ;
     RECT  48.78 89.159 48.834 89.429 ;
     RECT  86.76 89.303 93.51 89.429 ;
     RECT  85.068 89.041 85.086 89.437 ;
     RECT  88.236 89.429 93.51 89.453 ;
     RECT  46.764 89.429 47.466 89.465 ;
     RECT  50.544 89.239 51.297 89.465 ;
     RECT  50.868 89.465 51.297 89.501 ;
     RECT  17.892 89.131 22.806 89.573 ;
     RECT  85.068 89.437 85.518 89.609 ;
     RECT  11.7 89.195 17.154 89.671 ;
     RECT  17.892 89.573 19.314 89.671 ;
     RECT  46.764 89.465 47.286 89.699 ;
     RECT  48.816 89.429 48.834 89.699 ;
     RECT  88.236 89.453 89.097 89.699 ;
     RECT  0.396 89.563 0.414 89.707 ;
     RECT  20.412 89.573 22.806 89.707 ;
     RECT  0.216 89.707 0.414 89.741 ;
     RECT  32.4 89.401 32.418 89.743 ;
     RECT  86.76 89.429 87.462 89.743 ;
     RECT  2.304 88.925 8.097 89.779 ;
     RECT  8.856 89.195 10.89 89.779 ;
     RECT  11.7 89.671 19.314 89.807 ;
     RECT  29.415 26.525 29.697 89.851 ;
     RECT  11.7 89.807 13.986 89.969 ;
     RECT  31.932 89.743 32.418 89.969 ;
     RECT  86.652 89.743 87.462 89.969 ;
     RECT  0.216 89.741 0.27 89.981 ;
     RECT  45.036 88.159 45.897 90.013 ;
     RECT  86.652 89.969 87.246 90.077 ;
     RECT  11.7 89.969 13.95 90.113 ;
     RECT  46.944 89.699 47.286 90.239 ;
     RECT  86.652 90.077 86.67 90.239 ;
     RECT  89.82 89.453 93.51 90.239 ;
     RECT  88.596 89.699 89.097 90.247 ;
     RECT  89.82 90.239 91.782 90.247 ;
     RECT  1.152 87.835 1.17 90.283 ;
     RECT  44.46 90.013 45.897 90.311 ;
     RECT  2.304 89.779 10.89 90.319 ;
     RECT  14.76 89.807 19.314 90.319 ;
     RECT  88.596 90.247 91.782 90.347 ;
     RECT  14.76 90.319 19.494 90.391 ;
     RECT  20.412 89.707 23.274 90.391 ;
     RECT  33.624 89.545 33.642 90.391 ;
     RECT  1.152 90.283 1.458 90.419 ;
     RECT  92.52 90.239 93.51 90.427 ;
     RECT  92.52 90.427 94.086 90.461 ;
     RECT  14.76 90.391 23.274 90.481 ;
     RECT  24.015 65.408 24.297 90.481 ;
     RECT  2.304 90.319 11.07 90.509 ;
     RECT  30.6 88.969 30.618 90.509 ;
     RECT  31.932 89.969 31.95 90.509 ;
     RECT  47.124 90.239 47.286 90.509 ;
     RECT  88.596 90.347 91.602 90.517 ;
     RECT  6.048 90.509 11.07 90.545 ;
     RECT  0.252 89.981 0.27 90.557 ;
     RECT  6.048 90.545 7.002 90.557 ;
     RECT  88.092 90.517 91.602 90.557 ;
     RECT  44.46 90.311 44.658 90.581 ;
     RECT  92.952 90.461 94.086 90.581 ;
     RECT  40.215 38.273 40.497 90.589 ;
     RECT  42.768 90.517 42.786 90.617 ;
     RECT  14.76 90.481 24.297 90.619 ;
     RECT  83.415 79.349 83.697 90.619 ;
     RECT  48.456 90.589 48.474 90.653 ;
     RECT  49.968 90.625 49.986 90.751 ;
     RECT  6.048 90.557 6.822 90.779 ;
     RECT  29.088 89.851 29.697 90.779 ;
     RECT  49.032 90.751 49.986 90.779 ;
     RECT  7.815 90.545 11.07 90.815 ;
     RECT  53.28 90.751 53.37 90.851 ;
     RECT  93.492 90.581 94.086 90.851 ;
     RECT  53.28 90.851 53.298 90.859 ;
     RECT  2.304 90.509 5.274 90.887 ;
     RECT  9.648 90.815 11.07 90.887 ;
     RECT  9.792 90.887 11.07 90.931 ;
     RECT  11.808 90.113 13.95 90.931 ;
     RECT  88.815 90.557 91.602 90.959 ;
     RECT  6.804 90.779 6.822 90.989 ;
     RECT  53.1 90.859 53.298 90.989 ;
     RECT  9.792 90.931 13.95 91.021 ;
     RECT  14.724 90.619 24.297 91.021 ;
     RECT  33.624 90.391 33.678 91.021 ;
     RECT  69.192 90.661 69.21 91.021 ;
     RECT  83.415 90.619 84.15 91.021 ;
     RECT  2.376 90.887 5.274 91.049 ;
     RECT  7.815 90.815 8.874 91.049 ;
     RECT  37.8 90.859 37.818 91.049 ;
     RECT  68.616 91.021 69.21 91.049 ;
     RECT  85.068 89.609 85.086 91.049 ;
     RECT  36.504 90.625 36.522 91.057 ;
     RECT  44.496 90.581 44.658 91.085 ;
     RECT  94.068 90.851 94.086 91.121 ;
     RECT  36.504 91.057 36.882 91.129 ;
     RECT  68.616 91.049 68.634 91.129 ;
     RECT  7.815 91.049 8.802 91.157 ;
     RECT  9.792 91.021 24.297 91.193 ;
     RECT  30.78 90.895 30.798 91.193 ;
     RECT  33.624 91.021 34.074 91.193 ;
     RECT  88.815 90.959 91.314 91.193 ;
     RECT  44.64 91.085 44.658 91.201 ;
     RECT  45.468 90.311 45.897 91.201 ;
     RECT  2.376 91.049 4.626 91.229 ;
     RECT  47.592 91.051 47.61 91.291 ;
     RECT  56.415 87.437 56.697 91.291 ;
     RECT  67.215 87.437 67.497 91.291 ;
     RECT  71.28 91.195 71.298 91.291 ;
     RECT  72.615 28.685 72.897 91.291 ;
     RECT  2.376 91.229 4.59 91.319 ;
     RECT  49.032 90.779 49.374 91.319 ;
     RECT  65.628 90.931 65.646 91.319 ;
     RECT  81.216 89.581 81.234 91.319 ;
     RECT  90.684 91.193 91.314 91.319 ;
     RECT  47.556 91.291 47.61 91.328 ;
     RECT  67.104 91.291 67.497 91.328 ;
     RECT  90.684 91.319 91.242 91.328 ;
     RECT  4.356 91.319 4.59 91.355 ;
     RECT  9.792 91.193 22.626 91.355 ;
     RECT  23.364 91.193 24.297 91.355 ;
     RECT  44.64 91.201 45.897 91.355 ;
     RECT  80.28 91.291 80.298 91.355 ;
     RECT  20.376 91.355 22.626 91.373 ;
     RECT  68.22 91.129 68.634 91.373 ;
     RECT  75.996 91.291 76.014 91.421 ;
     RECT  20.844 91.373 22.626 91.427 ;
     RECT  21.852 91.427 22.626 91.463 ;
     RECT  56.304 91.291 56.697 91.471 ;
     RECT  64.656 91.339 64.674 91.471 ;
     RECT  4.356 91.355 4.518 91.499 ;
     RECT  21.852 91.463 21.87 91.499 ;
     RECT  56.304 91.471 57.222 91.579 ;
     RECT  88.815 91.193 89.946 91.579 ;
     RECT  20.844 91.427 21.114 91.589 ;
     RECT  47.592 91.328 47.61 91.589 ;
     RECT  88.38 91.579 89.946 91.589 ;
     RECT  90.684 91.328 91.206 91.589 ;
     RECT  60.588 91.561 61.074 91.613 ;
     RECT  64.656 91.471 65.034 91.613 ;
     RECT  89.928 91.589 89.946 91.613 ;
     RECT  2.376 91.319 3.618 91.625 ;
     RECT  9.972 91.355 19.206 91.625 ;
     RECT  20.844 91.589 20.934 91.625 ;
     RECT  29.196 90.779 29.697 91.625 ;
     RECT  37.764 91.471 37.782 91.625 ;
     RECT  56.232 91.579 57.222 91.625 ;
     RECT  88.38 91.589 89.097 91.625 ;
     RECT  90.756 91.589 91.098 91.625 ;
     RECT  4.5 91.499 4.518 91.661 ;
     RECT  56.376 91.625 57.222 91.669 ;
     RECT  60.948 91.613 61.074 91.669 ;
     RECT  61.815 28.781 62.097 91.669 ;
     RECT  20.844 91.625 20.862 91.697 ;
     RECT  76.392 91.471 76.986 91.697 ;
     RECT  6.84 91.633 6.858 91.733 ;
     RECT  10.152 91.625 12.33 91.733 ;
     RECT  90.756 91.625 90.774 91.733 ;
     RECT  27.324 90.823 27.342 91.769 ;
     RECT  36.504 91.129 37.026 91.769 ;
     RECT  54.792 91.669 54.81 91.769 ;
     RECT  56.376 91.669 57.258 91.769 ;
     RECT  58.788 91.669 58.806 91.769 ;
     RECT  60.948 91.669 62.097 91.769 ;
     RECT  2.376 91.625 3.402 91.771 ;
     RECT  40.176 90.589 40.497 91.819 ;
     RECT  25.344 91.819 25.362 91.831 ;
     RECT  40.176 91.819 41.166 91.831 ;
     RECT  40.176 91.831 41.49 91.859 ;
     RECT  44.64 91.355 44.658 91.859 ;
     RECT  49.212 91.319 49.374 91.859 ;
     RECT  72.615 91.291 72.954 91.903 ;
     RECT  72.396 91.903 72.954 91.931 ;
     RECT  53.28 90.989 53.298 91.966 ;
     RECT  22.608 91.463 22.626 91.975 ;
     RECT  25.344 91.831 25.686 91.975 ;
     RECT  34.056 91.193 34.074 91.975 ;
     RECT  34.815 65.453 35.097 91.975 ;
     RECT  41.328 91.859 41.49 91.975 ;
     RECT  13.215 91.625 19.206 92.003 ;
     RECT  71.244 91.291 71.298 92.003 ;
     RECT  72.396 91.931 72.897 92.003 ;
     RECT  2.304 91.771 3.402 92.039 ;
     RECT  2.412 92.039 3.402 92.129 ;
     RECT  10.152 91.733 11.538 92.129 ;
     RECT  12.312 91.733 12.33 92.129 ;
     RECT  18.615 92.003 19.206 92.129 ;
     RECT  22.608 91.975 22.734 92.129 ;
     RECT  40.176 91.859 40.497 92.129 ;
     RECT  41.328 91.975 42.138 92.129 ;
     RECT  83.415 91.021 84.294 92.129 ;
     RECT  13.215 92.003 17.766 92.152 ;
     RECT  10.152 92.129 11.394 92.165 ;
     RECT  13.215 92.152 17.154 92.165 ;
     RECT  23.616 91.355 24.297 92.237 ;
     RECT  25.344 91.975 26.37 92.237 ;
     RECT  37.008 91.769 37.026 92.237 ;
     RECT  68.616 91.373 68.634 92.245 ;
     RECT  76.392 91.697 76.41 92.245 ;
     RECT  80.676 91.471 80.694 92.245 ;
     RECT  2.415 92.129 3.402 92.395 ;
     RECT  13.215 92.165 17.046 92.399 ;
     RECT  18.615 92.129 19.026 92.399 ;
     RECT  22.608 92.129 22.626 92.399 ;
     RECT  25.344 92.237 25.758 92.399 ;
     RECT  53.28 91.966 53.334 92.399 ;
     RECT  76.284 92.245 76.41 92.399 ;
     RECT  2.415 92.395 3.438 92.435 ;
     RECT  16.704 92.399 16.722 92.435 ;
     RECT  13.215 92.399 15.426 92.471 ;
     RECT  1.44 90.419 1.458 92.507 ;
     RECT  2.415 92.435 3.402 92.507 ;
     RECT  56.376 91.769 56.697 92.507 ;
     RECT  56.415 92.507 56.697 92.515 ;
     RECT  60.948 91.769 60.966 92.515 ;
     RECT  10.152 92.165 10.53 92.551 ;
     RECT  25.344 92.399 25.722 92.551 ;
     RECT  29.376 91.625 29.697 92.551 ;
     RECT  34.056 91.975 35.097 92.551 ;
     RECT  45.615 91.355 45.897 92.551 ;
     RECT  49.212 91.859 49.23 92.551 ;
     RECT  64.98 91.613 65.034 92.551 ;
     RECT  88.704 91.625 89.097 92.551 ;
     RECT  2.415 92.507 2.697 92.627 ;
     RECT  7.815 91.157 8.097 92.627 ;
     RECT  18.615 92.399 18.897 92.627 ;
     RECT  24.015 92.237 24.297 92.627 ;
     RECT  29.196 92.551 29.697 92.627 ;
     RECT  33.948 92.551 35.097 92.627 ;
     RECT  40.215 92.129 40.497 92.627 ;
     RECT  45.612 92.551 45.897 92.627 ;
     RECT  51.015 89.501 51.297 92.627 ;
     RECT  61.815 91.769 62.097 92.627 ;
     RECT  67.215 91.328 67.497 92.627 ;
     RECT  78.015 87.437 78.297 92.627 ;
     RECT  83.415 92.129 83.697 92.627 ;
     RECT  88.38 92.551 89.097 92.627 ;
     RECT  10.116 92.551 10.53 92.669 ;
     RECT  13.215 92.471 14.526 92.669 ;
     RECT  18.615 92.627 18.774 92.669 ;
     RECT  22.284 92.551 22.302 92.669 ;
     RECT  29.196 92.627 29.574 92.669 ;
     RECT  37.152 92.245 37.17 92.669 ;
     RECT  41.328 92.129 41.526 92.669 ;
     RECT  48.96 92.551 49.23 92.669 ;
     RECT  53.1 92.551 53.19 92.669 ;
     RECT  56.415 92.515 56.97 92.669 ;
     RECT  60.876 92.515 60.966 92.669 ;
     RECT  64.62 92.551 65.034 92.669 ;
     RECT  68.544 92.245 68.634 92.669 ;
     RECT  76.104 92.551 76.122 92.669 ;
     RECT  80.532 92.245 80.694 92.669 ;
     RECT  84.492 92.245 84.618 92.669 ;
     RECT  88.38 92.627 88.905 92.669 ;
     RECT  10.116 92.669 10.458 92.705 ;
     RECT  13.215 92.669 14.418 92.705 ;
     RECT  25.308 92.551 25.722 92.705 ;
     RECT  33.948 92.627 34.905 92.705 ;
     RECT  88.632 92.669 88.905 92.705 ;
     RECT  18.615 92.669 18.705 92.785 ;
     RECT  45.612 92.627 45.705 92.785 ;
     RECT  61.815 92.627 61.905 92.785 ;
     RECT  72.615 92.003 72.897 92.785 ;
     RECT  9.972 92.785 9.99 92.861 ;
     RECT  13.215 92.705 13.914 92.861 ;
     RECT  33.768 92.785 33.786 92.861 ;
     RECT  41.508 92.669 41.526 92.861 ;
     RECT  49.608 92.785 49.626 92.861 ;
     RECT  53.172 92.669 53.19 92.861 ;
     RECT  57.312 92.785 57.33 92.861 ;
     RECT  61.2 92.785 61.905 92.861 ;
     RECT  76.968 92.785 76.986 92.861 ;
     RECT  80.712 92.785 80.73 92.861 ;
     RECT  84.636 92.785 84.654 92.861 ;
     RECT  2.415 92.627 2.505 92.897 ;
     RECT  7.815 92.627 7.905 92.897 ;
     RECT  13.215 92.861 13.305 92.897 ;
     RECT  18 92.785 18.705 92.897 ;
     RECT  24.015 92.627 24.105 92.897 ;
     RECT  29.415 92.669 29.574 92.897 ;
     RECT  34.815 92.705 34.905 92.897 ;
     RECT  40.215 92.627 40.305 92.897 ;
     RECT  45.432 92.785 45.705 92.897 ;
     RECT  51.015 92.627 51.105 92.897 ;
     RECT  56.415 92.669 56.505 92.897 ;
     RECT  61.815 92.861 61.905 92.897 ;
     RECT  67.215 92.627 67.305 92.897 ;
     RECT  72.615 92.785 72.954 92.897 ;
     RECT  78.015 92.627 78.105 92.897 ;
     RECT  83.415 92.627 83.505 92.897 ;
     RECT  88.776 92.705 88.905 92.897 ;
     RECT  88.776 92.897 88.794 93.053 ;
     RECT  18 92.897 18.018 94.109 ;
     RECT  22.104 92.785 22.122 94.109 ;
     RECT  25.2 92.785 25.218 94.109 ;
     RECT  29.556 92.897 29.574 94.109 ;
     RECT  37.404 92.785 37.422 94.109 ;
     RECT  45.432 92.897 45.45 94.109 ;
     RECT  65.088 92.785 65.106 94.109 ;
     RECT  68.94 92.785 68.958 94.109 ;
     RECT  72.936 92.897 72.954 94.109 ;
    LAYER M4 ;
     RECT  0.156 4.32 0.181 90.6 ;
     RECT  0.181 4.32 0.229 90.84 ;
     RECT  0.229 4.32 0.325 91.368 ;
     RECT  0.277 92.4 0.325 92.424 ;
     RECT  0.325 4.32 0.569 92.424 ;
     RECT  0.569 4.464 2.408 92.424 ;
     RECT  2.408 2.148 2.512 92.892 ;
     RECT  2.512 2.418 2.704 92.622 ;
     RECT  2.704 4.464 2.837 91.272 ;
     RECT  2.837 4.944 2.867 91.272 ;
     RECT  2.867 4.944 2.873 90.552 ;
     RECT  2.704 92.4 3.449 92.424 ;
     RECT  2.873 5.184 4.057 90.552 ;
     RECT  4.057 5.184 4.133 90.984 ;
     RECT  4.133 5.184 4.169 49.368 ;
     RECT  4.169 5.184 4.201 43.8 ;
     RECT  4.133 50.4 4.205 90.984 ;
     RECT  4.201 5.088 4.421 43.8 ;
     RECT  4.421 5.088 4.493 26.76 ;
     RECT  4.493 5.088 4.529 17.112 ;
     RECT  4.529 9.504 4.565 17.112 ;
     RECT  4.493 18.096 4.565 26.76 ;
     RECT  4.205 50.4 4.565 59.928 ;
     RECT  4.205 60.912 4.565 90.984 ;
     RECT  4.565 18.096 4.673 24.36 ;
     RECT  4.421 27.84 4.781 43.8 ;
     RECT  4.673 18.096 4.817 24.168 ;
     RECT  4.781 28.944 4.889 43.8 ;
     RECT  4.817 20.016 4.997 24.168 ;
     RECT  4.529 5.088 5.065 8.52 ;
     RECT  4.889 32.832 5.105 43.8 ;
     RECT  4.169 45.216 5.125 49.368 ;
     RECT  4.565 50.4 5.125 57.048 ;
     RECT  5.125 45.216 5.137 57.048 ;
     RECT  4.565 60.912 5.141 75.624 ;
     RECT  4.565 76.896 5.141 90.984 ;
     RECT  4.565 9.648 5.213 17.112 ;
     RECT  5.105 40.512 5.213 43.8 ;
     RECT  4.565 58.08 5.213 59.928 ;
     RECT  5.141 62.832 5.213 75.624 ;
     RECT  4.997 20.112 5.249 24.168 ;
     RECT  4.781 27.84 5.249 27.912 ;
     RECT  4.889 28.944 5.249 31.752 ;
     RECT  5.213 40.848 5.249 43.8 ;
     RECT  5.137 44.928 5.249 57.048 ;
     RECT  5.141 76.896 5.249 82.776 ;
     RECT  5.105 32.832 5.321 39.336 ;
     RECT  5.213 62.832 5.321 73.656 ;
     RECT  5.249 81.072 5.321 82.776 ;
     RECT  5.321 32.832 5.357 35.352 ;
     RECT  5.249 20.112 5.429 24.12 ;
     RECT  4.565 25.584 5.429 26.76 ;
     RECT  5.213 58.08 5.429 59.64 ;
     RECT  5.065 4.8 5.533 8.52 ;
     RECT  5.213 9.648 5.533 10.056 ;
     RECT  5.321 62.832 5.573 73.608 ;
     RECT  5.249 76.896 5.573 78.936 ;
     RECT  5.249 50.112 5.605 57.048 ;
     RECT  5.429 58.08 5.605 58.632 ;
     RECT  5.605 50.112 5.609 58.632 ;
     RECT  5.533 4.8 5.681 10.056 ;
     RECT  5.357 32.832 5.681 34.392 ;
     RECT  5.321 36.48 5.681 39.336 ;
     RECT  5.573 76.896 5.681 77.592 ;
     RECT  5.609 50.112 5.717 56.232 ;
     RECT  5.213 74.64 5.753 75.624 ;
     RECT  5.213 11.376 5.789 17.112 ;
     RECT  4.817 18.096 5.789 18.792 ;
     RECT  5.141 60.912 5.821 61.608 ;
     RECT  5.753 75.024 5.821 75.624 ;
     RECT  5.249 40.848 5.825 43.368 ;
     RECT  5.321 81.072 5.825 82.632 ;
     RECT  5.825 40.848 5.861 42.744 ;
     RECT  5.681 76.896 5.861 76.92 ;
     RECT  5.789 18.144 5.897 18.696 ;
     RECT  5.717 50.496 5.897 56.232 ;
     RECT  5.609 57.216 5.897 58.632 ;
     RECT  5.573 62.832 5.969 72.552 ;
     RECT  5.789 11.376 6.077 15.048 ;
     RECT  5.969 63.792 6.185 72.552 ;
     RECT  5.249 28.944 6.221 31.176 ;
     RECT  5.681 7.344 6.253 10.056 ;
     RECT  5.681 33.504 6.257 34.392 ;
     RECT  5.249 44.928 6.289 48.504 ;
     RECT  6.185 63.792 6.323 70.44 ;
     RECT  5.681 36.48 6.329 37.128 ;
     RECT  6.077 11.424 6.401 15.048 ;
     RECT  6.323 65.28 6.401 70.44 ;
     RECT  5.789 16.416 6.419 17.112 ;
     RECT  6.257 33.84 6.431 34.392 ;
     RECT  6.253 7.344 6.437 10.2 ;
     RECT  6.289 44.928 6.437 49.368 ;
     RECT  6.419 16.416 6.46 16.68 ;
     RECT  5.861 41.472 6.473 42.744 ;
     RECT  5.897 50.496 6.509 53.592 ;
     RECT  5.429 25.584 6.524 26.664 ;
     RECT  5.425 27.792 6.524 27.816 ;
     RECT  5.573 78.912 6.541 78.936 ;
     RECT  5.249 80.016 6.541 80.04 ;
     RECT  6.401 65.28 6.553 70.008 ;
     RECT  6.524 25.584 6.611 27.816 ;
     RECT  5.821 60.72 6.613 61.608 ;
     RECT  6.541 78.912 6.613 80.04 ;
     RECT  5.825 81.072 6.613 82.44 ;
     RECT  5.429 20.4 6.649 24.12 ;
     RECT  6.611 25.584 6.649 26.76 ;
     RECT  6.329 36.768 6.653 37.128 ;
     RECT  5.573 73.584 6.653 73.608 ;
     RECT  6.613 78.912 6.653 82.44 ;
     RECT  5.429 59.616 6.689 59.64 ;
     RECT  5.821 75.024 6.689 75.672 ;
     RECT  6.577 43.824 6.721 43.848 ;
     RECT  6.437 44.928 6.721 45.576 ;
     RECT  6.653 79.776 6.725 82.44 ;
     RECT  6.473 41.616 6.755 42.744 ;
     RECT  6.221 28.944 6.757 29.496 ;
     RECT  5.897 55.248 6.757 56.232 ;
     RECT  5.897 57.216 6.757 58.104 ;
     RECT  6.755 42.192 6.761 42.744 ;
     RECT  6.431 33.84 6.793 34.584 ;
     RECT  5.681 38.4 6.793 39.336 ;
     RECT  6.221 30.72 6.797 31.176 ;
     RECT  6.757 55.248 6.797 58.104 ;
     RECT  6.323 63.792 6.797 64.008 ;
     RECT  5.141 83.76 6.797 90.984 ;
     RECT  6.793 38.4 6.803 39.864 ;
     RECT  6.797 63.792 6.833 63.816 ;
     RECT  6.797 87.312 6.833 90.984 ;
     RECT  6.793 33.84 6.853 34.776 ;
     RECT  6.613 60.72 6.853 61.656 ;
     RECT  6.649 19.968 6.86 24.12 ;
     RECT  5.897 18.144 6.901 18.456 ;
     RECT  6.86 19.44 6.901 24.12 ;
     RECT  6.437 46.752 6.937 49.368 ;
     RECT  6.509 50.496 6.937 53.544 ;
     RECT  6.689 75.024 6.973 75.048 ;
     RECT  6.797 83.76 7.045 86.232 ;
     RECT  6.901 18.144 7.153 24.12 ;
     RECT  6.853 60.72 7.153 62.184 ;
     RECT  7.153 32.208 7.429 32.232 ;
     RECT  6.721 43.824 7.429 45.576 ;
     RECT  6.853 33.84 7.477 35.352 ;
     RECT  6.653 36.768 7.477 36.888 ;
     RECT  7.153 60.384 7.477 62.184 ;
     RECT  7.429 43.824 7.573 45.72 ;
     RECT  6.46 16.512 7.621 16.68 ;
     RECT  7.153 18.048 7.621 24.12 ;
     RECT  6.401 11.664 7.669 15.048 ;
     RECT  7.621 16.512 7.669 24.12 ;
     RECT  6.649 25.296 7.729 26.76 ;
     RECT  6.611 27.792 7.729 27.816 ;
     RECT  6.797 55.248 7.729 57.24 ;
     RECT  6.757 28.8 7.765 29.496 ;
     RECT  5.681 4.8 7.808 6.024 ;
     RECT  6.437 7.344 7.808 9.096 ;
     RECT  6.437 10.176 7.808 10.2 ;
     RECT  7.669 11.232 7.808 15.048 ;
     RECT  7.669 16.416 7.808 24.12 ;
     RECT  7.729 25.296 7.808 27.816 ;
     RECT  7.765 28.8 7.808 30.168 ;
     RECT  6.797 31.152 7.808 31.176 ;
     RECT  7.429 32.208 7.808 32.52 ;
     RECT  7.477 33.84 7.808 36.888 ;
     RECT  6.803 38.4 7.808 38.424 ;
     RECT  6.803 39.744 7.808 39.864 ;
     RECT  6.761 42.72 7.808 42.744 ;
     RECT  7.573 43.824 7.808 45.768 ;
     RECT  6.937 46.752 7.808 53.544 ;
     RECT  7.729 54.672 7.808 57.24 ;
     RECT  7.477 60.384 7.808 62.76 ;
     RECT  6.553 65.28 7.808 66.264 ;
     RECT  6.553 67.296 7.808 70.008 ;
     RECT  6.185 71.568 7.808 72.552 ;
     RECT  7.549 73.536 7.808 73.56 ;
     RECT  6.973 74.64 7.808 75.048 ;
     RECT  7.153 77.376 7.808 77.4 ;
     RECT  6.725 79.776 7.808 80.856 ;
     RECT  6.725 81.984 7.808 82.44 ;
     RECT  7.045 83.424 7.808 86.232 ;
     RECT  6.833 87.312 7.808 90.6 ;
     RECT  7.808 2.148 7.912 92.892 ;
     RECT  7.912 2.418 8.104 92.622 ;
     RECT  8.104 87.312 8.129 90.6 ;
     RECT  8.104 11.76 8.165 13.08 ;
     RECT  8.104 29.616 8.165 31.176 ;
     RECT  8.104 32.496 8.165 32.52 ;
     RECT  8.104 50.256 8.165 50.328 ;
     RECT  8.104 80.496 8.165 82.008 ;
     RECT  8.104 60.384 8.201 60.408 ;
     RECT  8.104 74.64 8.201 74.664 ;
     RECT  8.104 86.208 8.201 86.232 ;
     RECT  8.104 65.28 8.237 66.264 ;
     RECT  8.104 20.448 8.243 20.472 ;
     RECT  8.104 23.136 8.243 23.736 ;
     RECT  8.165 29.616 8.243 30.84 ;
     RECT  8.104 34.752 8.243 35.448 ;
     RECT  8.104 36.816 8.243 36.984 ;
     RECT  8.104 38.688 8.243 40.008 ;
     RECT  8.104 71.28 8.243 72.168 ;
     RECT  8.104 77.376 8.243 78.264 ;
     RECT  8.243 30.816 8.245 30.84 ;
     RECT  8.104 10.176 8.273 10.344 ;
     RECT  8.104 41.664 8.273 42.744 ;
     RECT  8.104 56.304 8.273 56.808 ;
     RECT  8.243 78.096 8.273 78.264 ;
     RECT  8.104 84.576 8.273 84.648 ;
     RECT  8.129 87.312 8.273 90.36 ;
     RECT  8.104 26.496 8.281 27.72 ;
     RECT  8.243 29.616 8.284 29.64 ;
     RECT  8.243 34.752 8.284 34.776 ;
     RECT  8.273 41.664 8.291 42.456 ;
     RECT  8.243 38.688 8.309 38.712 ;
     RECT  8.273 78.24 8.309 78.264 ;
     RECT  8.165 11.76 8.345 12.552 ;
     RECT  8.281 27.696 8.345 27.72 ;
     RECT  8.104 47.616 8.345 48.456 ;
     RECT  8.104 16.224 8.381 16.68 ;
     RECT  8.104 64.176 8.381 64.2 ;
     RECT  8.104 75.936 8.381 75.96 ;
     RECT  8.104 14.208 8.387 14.904 ;
     RECT  8.381 16.224 8.387 16.536 ;
     RECT  8.104 5.472 8.389 7.992 ;
     RECT  8.104 73.536 8.417 73.56 ;
     RECT  8.104 67.536 8.483 67.848 ;
     RECT  8.291 41.664 8.489 41.688 ;
     RECT  8.104 52.464 8.489 52.488 ;
     RECT  8.237 65.28 8.524 65.304 ;
     RECT  8.104 69.312 8.524 69.336 ;
     RECT  8.345 11.76 8.525 11.832 ;
     RECT  8.389 5.472 8.531 6.264 ;
     RECT  8.165 50.256 8.561 50.28 ;
     RECT  8.281 26.496 8.633 26.616 ;
     RECT  8.243 36.864 8.633 36.984 ;
     RECT  8.104 45.696 8.633 45.768 ;
     RECT  8.273 10.32 8.669 10.344 ;
     RECT  8.273 56.304 8.705 56.328 ;
     RECT  8.531 5.52 8.741 6.264 ;
     RECT  8.273 87.312 8.777 89.208 ;
     RECT  8.273 84.624 8.813 84.648 ;
     RECT  8.243 71.28 8.913 71.64 ;
     RECT  8.633 36.96 8.957 36.984 ;
     RECT  8.633 45.744 8.957 45.768 ;
     RECT  8.741 5.52 9.065 6.168 ;
     RECT  8.165 80.496 9.065 80.856 ;
     RECT  8.913 71.28 9.173 71.304 ;
     RECT  8.525 11.808 9.245 11.832 ;
     RECT  8.389 7.344 9.281 7.992 ;
     RECT  8.777 87.936 9.281 89.208 ;
     RECT  9.065 5.52 9.317 5.544 ;
     RECT  9.281 7.344 9.389 7.464 ;
     RECT  9.065 80.832 9.389 80.856 ;
     RECT  8.104 9.072 9.425 9.096 ;
     RECT  9.281 88.32 9.923 89.208 ;
     RECT  9.923 88.656 9.961 89.208 ;
     RECT  8.273 90.336 9.961 90.36 ;
     RECT  9.961 88.656 10.105 90.36 ;
     RECT  10.105 88.656 10.141 91.176 ;
     RECT  9.961 92.832 10.211 92.856 ;
     RECT  10.141 88.656 10.253 91.8 ;
     RECT  10.253 90.336 10.307 91.8 ;
     RECT  10.307 90.336 10.325 91.368 ;
     RECT  10.325 90.912 10.829 91.368 ;
     RECT  10.829 91.344 11.365 91.368 ;
     RECT  11.756 90.24 11.797 90.264 ;
     RECT  11.365 91.344 11.797 91.8 ;
     RECT  11.797 90.24 11.843 91.8 ;
     RECT  11.843 90.48 11.987 91.8 ;
     RECT  11.987 90.48 12.053 91.368 ;
     RECT  10.253 88.656 13.093 89.16 ;
     RECT  8.104 3.072 13.208 3.096 ;
     RECT  9.389 7.44 13.208 7.464 ;
     RECT  8.387 16.512 13.208 16.536 ;
     RECT  8.633 26.496 13.208 26.52 ;
     RECT  8.345 47.616 13.208 47.64 ;
     RECT  8.483 67.536 13.208 67.8 ;
     RECT  13.093 88.656 13.208 89.256 ;
     RECT  12.053 90.48 13.208 90.936 ;
     RECT  13.208 2.148 13.312 92.892 ;
     RECT  13.312 2.418 13.504 92.856 ;
     RECT  13.504 92.832 14.195 92.856 ;
     RECT  13.504 88.656 14.291 89.256 ;
     RECT  13.504 90.24 14.669 90.264 ;
     RECT  13.504 91.248 14.669 91.272 ;
     RECT  14.669 90.24 14.749 91.272 ;
     RECT  14.749 90 14.785 91.272 ;
     RECT  14.785 90 15.001 91.656 ;
     RECT  14.291 88.656 15.289 88.92 ;
     RECT  15.001 90 15.289 91.944 ;
     RECT  15.289 88.656 15.349 91.944 ;
     RECT  15.349 88.32 15.373 91.944 ;
     RECT  15.373 91.632 15.397 91.944 ;
     RECT  15.373 88.32 15.401 90.552 ;
     RECT  15.397 91.632 15.617 92.136 ;
     RECT  15.617 91.92 15.977 92.136 ;
     RECT  15.401 88.32 16.805 90.312 ;
     RECT  16.805 88.32 17.201 88.68 ;
     RECT  15.977 92.112 17.269 92.136 ;
     RECT  17.269 91.728 17.309 92.136 ;
     RECT  16.805 90.24 17.449 90.312 ;
     RECT  17.309 91.728 17.449 91.752 ;
     RECT  17.449 90.24 17.845 91.752 ;
     RECT  17.201 88.656 17.873 88.68 ;
     RECT  17.845 89.712 17.873 91.752 ;
     RECT  17.989 94.08 18.275 94.104 ;
     RECT  13.504 3.072 18.608 3.096 ;
     RECT  13.504 7.44 18.608 7.464 ;
     RECT  13.504 16.512 18.608 16.536 ;
     RECT  13.504 26.496 18.608 26.52 ;
     RECT  13.504 47.616 18.608 47.64 ;
     RECT  13.504 67.536 18.608 67.8 ;
     RECT  17.873 88.656 18.608 91.752 ;
     RECT  18.608 2.148 18.712 92.892 ;
     RECT  18.712 2.418 18.904 92.622 ;
     RECT  18.805 0.528 18.965 0.552 ;
     RECT  18.904 3.072 19.613 3.096 ;
     RECT  18.904 88.656 20.003 91.368 ;
     RECT  20.003 88.848 20.405 91.368 ;
     RECT  20.629 87.696 20.716 87.72 ;
     RECT  20.405 88.848 21.125 91.08 ;
     RECT  21.125 88.848 21.301 88.92 ;
     RECT  21.125 90.048 21.347 91.08 ;
     RECT  21.301 88.8 21.841 88.92 ;
     RECT  21.841 88.464 21.989 88.92 ;
     RECT  21.347 90.24 22.277 91.08 ;
     RECT  22.093 94.08 22.403 94.104 ;
     RECT  22.277 90.24 22.457 90.792 ;
     RECT  21.989 88.896 22.601 88.92 ;
     RECT  18.904 67.536 22.633 67.8 ;
     RECT  22.633 67.488 22.777 67.8 ;
     RECT  22.777 67.488 22.789 67.848 ;
     RECT  22.789 67.536 22.997 67.848 ;
     RECT  22.457 90.624 23.893 90.792 ;
     RECT  18.904 7.44 24.008 7.464 ;
     RECT  18.904 16.512 24.008 16.536 ;
     RECT  18.904 26.496 24.008 26.52 ;
     RECT  18.904 47.616 24.008 47.64 ;
     RECT  22.741 65.376 24.008 65.4 ;
     RECT  23.893 90.624 24.008 90.888 ;
     RECT  24.008 2.148 24.112 92.892 ;
     RECT  24.112 2.418 24.304 92.622 ;
     RECT  24.304 90.864 25.285 90.888 ;
     RECT  25.285 90.864 25.331 91.848 ;
     RECT  25.331 91.152 25.373 91.848 ;
     RECT  25.189 94.08 26.003 94.104 ;
     RECT  25.373 91.152 29.185 91.176 ;
     RECT  24.304 26.496 29.293 26.52 ;
     RECT  24.304 7.44 29.408 7.464 ;
     RECT  24.304 16.512 29.408 16.536 ;
     RECT  29.293 26.256 29.408 26.52 ;
     RECT  24.304 47.616 29.408 47.64 ;
     RECT  24.304 65.376 29.408 65.4 ;
     RECT  29.185 91.056 29.408 91.176 ;
     RECT  29.408 2.148 29.512 92.892 ;
     RECT  29.512 2.418 29.704 92.622 ;
     RECT  29.704 25.68 29.765 26.28 ;
     RECT  29.765 25.68 29.845 26.184 ;
     RECT  29.704 7.44 29.939 7.992 ;
     RECT  29.545 94.08 29.939 94.104 ;
     RECT  29.939 7.968 30.035 7.992 ;
     RECT  29.845 25.68 30.061 25.704 ;
     RECT  29.704 65.376 34.732 65.4 ;
     RECT  29.704 3.552 34.808 3.576 ;
     RECT  29.704 16.512 34.808 16.536 ;
     RECT  29.704 28.656 34.808 28.68 ;
     RECT  29.704 47.616 34.808 47.64 ;
     RECT  34.732 65.376 34.808 65.448 ;
     RECT  29.704 91.056 34.808 91.08 ;
     RECT  33.757 92.832 34.808 92.856 ;
     RECT  34.808 2.148 34.912 92.892 ;
     RECT  34.912 2.418 35.104 92.622 ;
     RECT  35.104 65.424 36.313 65.448 ;
     RECT  36.313 65.232 36.641 65.448 ;
     RECT  37.393 94.08 37.667 94.104 ;
     RECT  35.104 28.656 38.761 28.68 ;
     RECT  38.761 28.656 38.801 28.776 ;
     RECT  35.104 3.552 40.208 3.576 ;
     RECT  35.104 16.512 40.208 16.536 ;
     RECT  38.801 28.752 40.208 28.776 ;
     RECT  35.104 47.616 40.208 47.64 ;
     RECT  36.641 65.232 40.208 65.256 ;
     RECT  36.853 91.104 40.208 91.128 ;
     RECT  40.208 2.148 40.312 92.892 ;
     RECT  40.312 2.418 40.504 92.622 ;
     RECT  40.504 90.96 41.171 91.848 ;
     RECT  41.171 91.056 41.212 91.848 ;
     RECT  41.497 92.832 41.603 92.856 ;
     RECT  40.504 3.552 45.608 3.576 ;
     RECT  40.504 16.512 45.608 16.536 ;
     RECT  40.504 28.752 45.608 28.776 ;
     RECT  40.504 47.616 45.608 47.64 ;
     RECT  44.413 57.12 45.608 57.144 ;
     RECT  40.504 65.232 45.608 65.256 ;
     RECT  41.212 91.056 45.608 91.08 ;
     RECT  45.608 2.148 45.712 92.892 ;
     RECT  45.421 94.08 45.731 94.104 ;
     RECT  45.712 2.418 45.904 92.622 ;
     RECT  45.904 57.12 46.073 57.624 ;
     RECT  45.904 28.752 46.793 29.016 ;
     RECT  45.904 87.6 47.509 87.624 ;
     RECT  45.904 91.056 47.545 91.08 ;
     RECT  47.468 86.352 47.555 86.376 ;
     RECT  47.509 2.304 47.603 2.328 ;
     RECT  47.545 91.056 47.621 91.32 ;
     RECT  45.904 47.616 48.269 47.64 ;
     RECT  47.509 87.408 48.517 87.624 ;
     RECT  48.524 47.568 48.611 47.592 ;
     RECT  46.073 57.12 48.611 57.144 ;
     RECT  45.904 16.512 48.809 16.536 ;
     RECT  48.517 77.328 48.841 77.352 ;
     RECT  48.764 81.456 48.86 81.48 ;
     RECT  48.86 80.88 48.901 81.48 ;
     RECT  48.901 80.88 48.947 81.672 ;
     RECT  47.621 91.152 49.021 91.32 ;
     RECT  48.517 87.408 49.292 87.912 ;
     RECT  48.841 77.328 49.333 78.072 ;
     RECT  49.292 87.12 49.379 87.912 ;
     RECT  49.597 92.832 49.811 92.856 ;
     RECT  46.793 28.992 49.861 29.016 ;
     RECT  49.82 27.312 49.907 27.336 ;
     RECT  49.333 77.328 50.101 78.456 ;
     RECT  48.997 79.44 50.101 79.464 ;
     RECT  49.861 28.704 51.008 29.016 ;
     RECT  47.689 33.648 51.008 33.672 ;
     RECT  48.565 36.96 51.008 36.984 ;
     RECT  45.904 65.232 51.008 65.256 ;
     RECT  50.101 77.328 51.008 79.464 ;
     RECT  48.947 81.648 51.008 81.672 ;
     RECT  48.805 83.04 51.008 83.064 ;
     RECT  49.379 87.408 51.008 87.912 ;
     RECT  49.021 90.864 51.008 91.32 ;
     RECT  51.008 2.148 51.112 92.892 ;
     RECT  51.112 2.418 51.304 92.622 ;
     RECT  51.304 81.648 51.401 81.768 ;
     RECT  51.304 36.48 51.517 36.504 ;
     RECT  51.304 28.56 51.875 29.016 ;
     RECT  51.304 65.232 52.553 65.256 ;
     RECT  51.304 90.864 53.125 91.32 ;
     RECT  53.125 90.864 53.129 91.608 ;
     RECT  53.129 90.96 53.171 91.608 ;
     RECT  53.161 92.832 53.411 92.856 ;
     RECT  51.875 28.56 56.408 28.728 ;
     RECT  51.304 33.648 56.408 33.672 ;
     RECT  54.061 65.376 56.408 65.4 ;
     RECT  51.304 77.328 56.408 77.352 ;
     RECT  51.304 78.432 56.408 79.464 ;
     RECT  51.401 81.744 56.408 81.768 ;
     RECT  51.304 83.04 56.408 83.064 ;
     RECT  51.304 87.408 56.408 87.912 ;
     RECT  53.171 91.296 56.408 91.608 ;
     RECT  56.408 2.148 56.512 92.892 ;
     RECT  56.512 2.418 56.704 92.856 ;
     RECT  56.704 92.832 57.395 92.856 ;
     RECT  56.704 28.56 59.177 28.728 ;
     RECT  56.704 91.296 60.577 91.32 ;
     RECT  59.177 28.56 60.685 28.584 ;
     RECT  60.685 28.56 61.808 28.776 ;
     RECT  56.704 33.648 61.808 33.672 ;
     RECT  56.704 65.376 61.808 65.4 ;
     RECT  56.704 77.328 61.808 77.352 ;
     RECT  56.704 78.432 61.808 79.464 ;
     RECT  56.704 81.744 61.808 81.768 ;
     RECT  56.704 83.04 61.808 83.064 ;
     RECT  56.704 87.408 61.808 87.912 ;
     RECT  60.577 91.296 61.808 91.608 ;
     RECT  61.189 92.832 61.808 92.856 ;
     RECT  61.808 2.148 61.912 92.892 ;
     RECT  61.912 2.418 62.104 92.622 ;
     RECT  62.104 28.56 62.705 28.776 ;
     RECT  62.104 91.296 64.685 91.608 ;
     RECT  65.228 68.304 65.293 68.328 ;
     RECT  62.104 65.376 65.315 65.4 ;
     RECT  65.293 68.304 65.315 68.952 ;
     RECT  65.077 94.08 65.603 94.104 ;
     RECT  62.705 28.56 67.208 28.68 ;
     RECT  62.104 33.648 67.208 33.672 ;
     RECT  65.315 68.928 67.208 68.952 ;
     RECT  62.104 77.328 67.208 77.352 ;
     RECT  62.104 78.432 67.208 79.464 ;
     RECT  62.104 81.744 67.208 81.768 ;
     RECT  62.104 83.04 67.208 83.064 ;
     RECT  62.104 87.408 67.208 87.912 ;
     RECT  64.685 91.296 67.208 91.368 ;
     RECT  67.208 2.148 67.312 92.892 ;
     RECT  67.312 2.418 67.504 92.622 ;
     RECT  67.504 91.2 68.249 91.368 ;
     RECT  68.929 94.08 69.203 94.104 ;
     RECT  68.249 91.2 71.233 91.32 ;
     RECT  71.233 91.2 71.309 91.992 ;
     RECT  67.504 68.352 71.315 68.952 ;
     RECT  71.309 91.296 71.337 91.992 ;
     RECT  67.504 28.56 72.493 28.68 ;
     RECT  72.493 28.512 72.608 28.68 ;
     RECT  67.504 33.648 72.608 33.672 ;
     RECT  71.315 68.928 72.608 68.952 ;
     RECT  71.269 70.8 72.608 70.824 ;
     RECT  67.504 77.328 72.608 77.352 ;
     RECT  67.504 78.432 72.608 79.464 ;
     RECT  67.504 81.744 72.608 81.768 ;
     RECT  67.504 83.04 72.608 83.064 ;
     RECT  67.504 87.408 72.608 87.912 ;
     RECT  71.337 91.968 72.608 91.992 ;
     RECT  72.608 2.148 72.712 92.892 ;
     RECT  72.712 2.418 72.904 92.622 ;
     RECT  72.925 94.08 73.139 94.104 ;
     RECT  72.904 28.512 74.101 28.584 ;
     RECT  74.101 27.888 74.189 28.584 ;
     RECT  74.588 27.504 74.675 27.528 ;
     RECT  74.189 28.56 75.697 28.584 ;
     RECT  75.409 3.936 75.827 3.96 ;
     RECT  72.904 91.296 75.985 91.32 ;
     RECT  75.985 91.296 76.025 91.416 ;
     RECT  76.645 0.192 76.853 0.216 ;
     RECT  75.781 6.384 78.008 6.408 ;
     RECT  75.697 27.888 78.008 28.584 ;
     RECT  74.629 30.576 78.008 30.6 ;
     RECT  72.904 33.648 78.008 33.672 ;
     RECT  72.904 68.928 78.008 68.952 ;
     RECT  72.904 70.8 78.008 70.824 ;
     RECT  72.904 77.328 78.008 77.352 ;
     RECT  72.904 78.432 78.008 79.464 ;
     RECT  72.904 81.744 78.008 81.768 ;
     RECT  72.904 83.04 78.008 83.064 ;
     RECT  72.904 87.408 78.008 87.912 ;
     RECT  76.025 91.392 78.008 91.416 ;
     RECT  76.957 92.832 78.008 92.856 ;
     RECT  78.008 2.148 78.112 92.892 ;
     RECT  78.112 2.418 78.304 92.622 ;
     RECT  78.304 91.296 80.309 91.32 ;
     RECT  80.701 92.832 80.867 92.856 ;
     RECT  78.304 6.384 82.969 6.408 ;
     RECT  82.969 6 83.408 6.408 ;
     RECT  78.304 27.888 83.408 28.584 ;
     RECT  78.304 30.576 83.408 30.6 ;
     RECT  78.304 33.648 83.408 33.672 ;
     RECT  78.304 68.928 83.408 68.952 ;
     RECT  78.304 70.8 83.408 70.824 ;
     RECT  78.304 77.328 83.408 77.352 ;
     RECT  78.304 78.432 83.408 79.464 ;
     RECT  78.304 81.744 83.408 81.768 ;
     RECT  78.304 83.04 83.408 83.064 ;
     RECT  78.304 87.408 83.408 87.912 ;
     RECT  83.408 2.148 83.512 92.892 ;
     RECT  83.512 2.418 83.704 92.622 ;
     RECT  84.625 92.832 84.803 92.856 ;
     RECT  83.704 6 85.777 6.408 ;
     RECT  85.597 31.872 85.777 31.896 ;
     RECT  85.777 5.088 85.817 6.408 ;
     RECT  85.741 23.04 85.885 23.064 ;
     RECT  83.704 78.432 85.885 79.464 ;
     RECT  83.704 33.648 85.909 33.672 ;
     RECT  85.777 31.632 85.955 31.896 ;
     RECT  85.885 78.432 85.957 79.752 ;
     RECT  85.885 52.464 85.969 52.488 ;
     RECT  85.777 38.4 85.993 38.424 ;
     RECT  85.909 33.216 85.997 33.672 ;
     RECT  83.704 70.8 86.005 70.824 ;
     RECT  85.885 71.808 86.005 71.832 ;
     RECT  85.669 53.568 86.051 53.592 ;
     RECT  86.005 70.8 86.051 71.832 ;
     RECT  83.704 68.928 86.101 68.952 ;
     RECT  83.704 77.328 86.101 77.352 ;
     RECT  85.957 78.432 86.101 80.424 ;
     RECT  85.993 38.4 86.137 39.336 ;
     RECT  86.137 64.368 86.317 64.392 ;
     RECT  86.209 24.624 86.348 24.648 ;
     RECT  86.209 35.328 86.353 35.352 ;
     RECT  85.957 15.312 86.533 15.336 ;
     RECT  86.051 70.8 86.569 70.968 ;
     RECT  85.997 33.264 86.581 33.672 ;
     RECT  86.569 70.752 86.609 70.968 ;
     RECT  86.173 11.424 86.641 11.448 ;
     RECT  83.704 27.888 86.641 28.584 ;
     RECT  86.101 68.112 86.677 68.952 ;
     RECT  83.704 81.744 86.677 81.768 ;
     RECT  86.137 65.52 86.712 65.544 ;
     RECT  86.609 70.752 86.713 70.824 ;
     RECT  86.712 65.52 86.732 66.12 ;
     RECT  86.732 65.52 86.789 66.792 ;
     RECT  86.789 66.096 86.819 66.792 ;
     RECT  83.704 83.04 86.828 83.064 ;
     RECT  86.005 54.864 86.857 54.888 ;
     RECT  85.777 10.224 86.897 10.248 ;
     RECT  86.828 83.04 86.915 83.64 ;
     RECT  83.704 30.576 86.929 30.6 ;
     RECT  86.819 66.096 87.005 66.12 ;
     RECT  85.817 5.088 87.037 6.024 ;
     RECT  86.677 81.744 87.061 81.912 ;
     RECT  86.641 11.424 87.073 12.408 ;
     RECT  86.641 27.888 87.073 28.728 ;
     RECT  86.929 29.904 87.073 30.6 ;
     RECT  86.929 37.296 87.073 37.32 ;
     RECT  86.137 38.4 87.073 40.008 ;
     RECT  86.677 67.872 87.073 68.952 ;
     RECT  86.713 69.984 87.073 70.824 ;
     RECT  87.037 5.088 87.077 6.312 ;
     RECT  86.101 77.328 87.107 80.424 ;
     RECT  87.061 81.504 87.109 81.912 ;
     RECT  86.915 83.04 87.109 83.208 ;
     RECT  86.389 25.824 87.116 25.848 ;
     RECT  87.073 27.888 87.116 30.6 ;
     RECT  87.107 78.432 87.141 79.752 ;
     RECT  86.965 17.664 87.145 17.688 ;
     RECT  86.348 24.624 87.157 24.696 ;
     RECT  87.116 25.824 87.157 30.6 ;
     RECT  86.317 64.08 87.173 64.392 ;
     RECT  83.704 90.624 87.173 90.648 ;
     RECT  86.533 59.52 87.205 59.544 ;
     RECT  86.065 46.128 87.217 46.152 ;
     RECT  86.869 84.96 87.221 84.984 ;
     RECT  87.173 90.048 87.251 90.648 ;
     RECT  85.885 23.04 87.253 23.112 ;
     RECT  87.157 24.624 87.253 30.6 ;
     RECT  85.561 61.344 87.253 61.368 ;
     RECT  87.173 64.08 87.257 65.016 ;
     RECT  87.251 90.048 87.257 90.552 ;
     RECT  87.109 21.696 87.289 21.72 ;
     RECT  86.581 33.264 87.289 34.104 ;
     RECT  86.857 54.048 87.325 54.888 ;
     RECT  87.325 54.048 87.356 55.128 ;
     RECT  87.253 23.04 87.397 30.6 ;
     RECT  86.353 35.328 87.397 35.448 ;
     RECT  87.253 61.344 87.397 62.184 ;
     RECT  87.289 33.264 87.404 34.344 ;
     RECT  87.397 35.328 87.404 35.88 ;
     RECT  87.073 11.376 87.437 12.552 ;
     RECT  87.356 54.048 87.437 55.272 ;
     RECT  87.437 55.104 87.443 55.272 ;
     RECT  87.205 59.232 87.443 59.544 ;
     RECT  87.397 60.672 87.443 62.184 ;
     RECT  86.533 14.832 87.445 15.336 ;
     RECT  87.217 45.552 87.493 46.152 ;
     RECT  85.909 47.472 87.493 47.496 ;
     RECT  86.353 56.88 87.5 56.904 ;
     RECT  87.257 64.08 87.505 64.728 ;
     RECT  85.993 86.064 87.505 86.088 ;
     RECT  83.704 87.408 87.505 87.912 ;
     RECT  87.493 45.552 87.539 47.496 ;
     RECT  87.404 33.264 87.541 35.88 ;
     RECT  87.5 56.112 87.541 56.904 ;
     RECT  86.641 58.128 87.541 58.152 ;
     RECT  87.253 42.768 87.577 42.792 ;
     RECT  87.541 33.264 87.58 36.024 ;
     RECT  87.539 46.656 87.58 47.496 ;
     RECT  87.437 11.424 87.581 12.552 ;
     RECT  87.541 56.112 87.587 58.152 ;
     RECT  87.581 12.336 87.613 12.552 ;
     RECT  86.605 13.824 87.613 13.848 ;
     RECT  85.955 31.632 87.613 31.656 ;
     RECT  87.58 33.264 87.613 34.2 ;
     RECT  87.587 57.6 87.625 58.152 ;
     RECT  87.539 45.552 87.653 45.576 ;
     RECT  87.443 55.104 87.653 55.128 ;
     RECT  87.397 22.8 87.721 30.6 ;
     RECT  87.613 31.632 87.721 34.2 ;
     RECT  87.445 14.832 87.779 15.528 ;
     RECT  87.145 17.664 87.781 18.456 ;
     RECT  87.145 49.392 87.781 49.416 ;
     RECT  86.173 50.544 87.781 50.568 ;
     RECT  87.443 59.52 87.793 59.544 ;
     RECT  87.443 60.672 87.793 60.696 ;
     RECT  87.073 37.296 87.829 40.008 ;
     RECT  87.577 40.992 87.829 41.016 ;
     RECT  87.58 47.04 87.829 47.496 ;
     RECT  87.781 49.392 87.829 50.568 ;
     RECT  87.109 81.504 87.829 83.208 ;
     RECT  87.793 59.52 87.833 60.696 ;
     RECT  87.073 67.872 87.973 70.824 ;
     RECT  87.505 63.264 88.009 64.728 ;
     RECT  88.028 73.776 88.045 73.8 ;
     RECT  88.045 73.776 88.069 74.616 ;
     RECT  87.973 67.296 88.081 70.824 ;
     RECT  87.037 20.016 88.117 20.04 ;
     RECT  87.141 78.432 88.153 79.464 ;
     RECT  87.58 35.28 88.165 36.024 ;
     RECT  87.829 37.296 88.165 41.016 ;
     RECT  87.779 15.504 88.189 15.528 ;
     RECT  87.781 17.088 88.189 18.456 ;
     RECT  87.145 75.792 88.225 75.816 ;
     RECT  87.107 77.328 88.225 77.352 ;
     RECT  88.153 78.432 88.309 79.8 ;
     RECT  87.829 80.928 88.309 83.208 ;
     RECT  87.505 86.064 88.333 87.912 ;
     RECT  88.081 66.576 88.369 70.824 ;
     RECT  88.045 71.808 88.369 71.832 ;
     RECT  88.117 19.872 88.477 20.04 ;
     RECT  87.577 42.768 88.477 43.416 ;
     RECT  88.225 75.792 88.508 77.352 ;
     RECT  88.508 75.744 88.585 77.352 ;
     RECT  88.309 78.432 88.585 83.208 ;
     RECT  87.833 59.76 88.801 60.696 ;
     RECT  87.077 6 88.808 6.312 ;
     RECT  87.937 7.44 88.808 7.464 ;
     RECT  86.101 8.448 88.808 8.472 ;
     RECT  87.613 12.336 88.808 13.848 ;
     RECT  88.189 15.504 88.808 16.008 ;
     RECT  88.189 17.088 88.808 18.552 ;
     RECT  88.477 19.872 88.808 20.616 ;
     RECT  87.289 21.648 88.808 21.72 ;
     RECT  87.721 22.8 88.808 34.2 ;
     RECT  88.165 35.28 88.808 41.016 ;
     RECT  88.477 42.24 88.808 43.416 ;
     RECT  87.829 47.04 88.808 50.568 ;
     RECT  87.721 51.84 88.808 51.864 ;
     RECT  87.437 54.048 88.808 54.072 ;
     RECT  87.625 58.128 88.808 58.152 ;
     RECT  88.801 59.184 88.808 60.696 ;
     RECT  88.009 62.304 88.808 64.728 ;
     RECT  88.369 66.576 88.808 71.832 ;
     RECT  88.069 73.296 88.808 74.616 ;
     RECT  88.585 75.744 88.808 83.208 ;
     RECT  88.405 84.384 88.808 84.408 ;
     RECT  88.333 85.392 88.808 87.912 ;
     RECT  87.257 90.528 88.808 90.552 ;
     RECT  88.369 91.584 88.808 91.608 ;
     RECT  88.765 93.024 88.808 93.048 ;
     RECT  88.808 2.148 88.912 93.048 ;
     RECT  88.912 2.418 88.931 93.048 ;
     RECT  88.931 2.418 89.104 92.622 ;
     RECT  89.104 64.08 89.129 70.296 ;
     RECT  89.104 18.24 89.165 44.472 ;
     RECT  89.104 45.552 89.219 47.352 ;
     RECT  89.129 64.368 89.381 70.296 ;
     RECT  89.104 48.432 89.417 49.56 ;
     RECT  89.104 71.472 89.489 71.496 ;
     RECT  89.165 19.488 89.507 44.472 ;
     RECT  89.219 45.552 89.555 46.2 ;
     RECT  89.104 59.184 89.561 60.696 ;
     RECT  89.104 7.344 89.597 9.384 ;
     RECT  89.507 19.488 89.597 21.144 ;
     RECT  89.597 9.072 89.651 9.384 ;
     RECT  89.507 42.144 89.669 44.472 ;
     RECT  89.104 51.6 89.669 52.488 ;
     RECT  89.597 7.344 89.813 7.896 ;
     RECT  89.669 42.144 89.813 43.848 ;
     RECT  89.104 72.96 89.813 91.608 ;
     RECT  89.104 53.52 89.843 54.984 ;
     RECT  89.381 67.2 89.843 70.296 ;
     RECT  89.555 45.6 89.849 46.2 ;
     RECT  89.507 22.224 89.885 40.968 ;
     RECT  89.813 75.648 89.957 91.608 ;
     RECT  89.813 43.824 90.029 43.848 ;
     RECT  89.104 55.968 90.097 55.992 ;
     RECT  89.104 57.024 90.097 58.104 ;
     RECT  89.104 13.584 90.101 13.848 ;
     RECT  89.381 64.368 90.101 66.216 ;
     RECT  89.219 47.328 90.133 47.352 ;
     RECT  89.417 48.432 90.133 48.456 ;
     RECT  90.097 55.968 90.133 58.104 ;
     RECT  89.561 59.712 90.133 60.696 ;
     RECT  90.101 64.368 90.133 65.304 ;
     RECT  89.165 18.24 90.137 18.264 ;
     RECT  89.597 19.488 90.137 19.656 ;
     RECT  89.849 45.6 90.137 45.672 ;
     RECT  89.669 51.6 90.137 52.44 ;
     RECT  89.843 54.144 90.137 54.984 ;
     RECT  90.137 51.696 90.173 52.44 ;
     RECT  89.104 62.16 90.173 62.376 ;
     RECT  90.133 55.968 90.179 58.68 ;
     RECT  89.417 49.536 90.181 49.56 ;
     RECT  90.179 55.968 90.181 57.24 ;
     RECT  90.133 47.328 90.205 48.456 ;
     RECT  89.813 42.144 90.209 42.648 ;
     RECT  90.181 49.536 90.227 50.28 ;
     RECT  90.133 59.712 90.245 60.984 ;
     RECT  90.227 50.256 90.268 50.28 ;
     RECT  90.173 62.352 90.353 62.376 ;
     RECT  90.205 46.752 90.389 48.456 ;
     RECT  90.137 19.632 90.419 19.656 ;
     RECT  89.885 22.416 90.419 40.968 ;
     RECT  89.104 5.472 90.457 6.312 ;
     RECT  89.813 72.96 90.461 74.664 ;
     RECT  89.104 15.168 90.469 16.776 ;
     RECT  90.349 17.76 90.469 17.784 ;
     RECT  90.245 59.808 90.497 60.984 ;
     RECT  90.461 73.824 90.497 74.664 ;
     RECT  90.313 12.336 90.517 12.36 ;
     RECT  90.419 22.704 90.533 40.968 ;
     RECT  90.517 11.952 90.563 13.128 ;
     RECT  90.469 15.168 90.569 17.784 ;
     RECT  90.179 58.272 90.605 58.68 ;
     RECT  89.957 75.648 90.611 91.224 ;
     RECT  90.605 58.656 90.637 58.68 ;
     RECT  90.133 63.552 90.641 65.304 ;
     RECT  90.457 5.472 90.677 6.84 ;
     RECT  89.651 9.36 90.677 9.384 ;
     RECT  90.563 13.056 90.677 13.128 ;
     RECT  90.533 38.688 90.677 40.968 ;
     RECT  90.137 45.6 90.677 45.624 ;
     RECT  90.181 57.216 90.677 57.24 ;
     RECT  90.563 11.952 90.713 11.976 ;
     RECT  90.533 22.704 90.713 37.608 ;
     RECT  90.677 39.84 90.713 40.584 ;
     RECT  90.497 60.96 90.713 60.984 ;
     RECT  90.641 63.552 90.749 64.392 ;
     RECT  90.181 55.968 90.785 55.992 ;
     RECT  90.569 15.456 90.821 17.784 ;
     RECT  90.821 16.8 90.857 17.784 ;
     RECT  90.677 5.472 90.893 6.792 ;
     RECT  90.713 31.728 90.893 37.608 ;
     RECT  90.497 59.808 91.037 59.832 ;
     RECT  90.611 77.52 91.069 91.224 ;
     RECT  90.601 72.48 91.073 72.504 ;
     RECT  91.069 77.52 91.073 91.272 ;
     RECT  90.389 46.752 91.105 48.408 ;
     RECT  91.073 77.52 91.139 83.304 ;
     RECT  89.597 21.024 91.141 21.144 ;
     RECT  90.857 17.76 91.145 17.784 ;
     RECT  90.173 51.696 91.181 51.72 ;
     RECT  91.139 77.52 91.181 82.152 ;
     RECT  91.073 84.336 91.186 91.272 ;
     RECT  90.637 58.656 91.253 58.728 ;
     RECT  90.673 10.944 91.289 10.968 ;
     RECT  90.713 22.704 91.289 30.648 ;
     RECT  91.181 82.08 91.289 82.152 ;
     RECT  91.289 22.704 91.325 28.92 ;
     RECT  89.843 67.2 91.325 68.472 ;
     RECT  91.105 46.512 91.361 48.408 ;
     RECT  90.137 54.576 91.361 54.984 ;
     RECT  91.141 21.024 91.397 21.672 ;
     RECT  90.209 42.624 91.397 42.648 ;
     RECT  91.325 24.624 91.433 28.92 ;
     RECT  91.186 84.336 91.433 91.32 ;
     RECT  90.893 6.144 91.469 6.792 ;
     RECT  90.893 31.728 91.505 37.512 ;
     RECT  90.497 74.64 91.532 74.664 ;
     RECT  90.611 75.648 91.532 76.44 ;
     RECT  91.505 31.728 91.541 37.032 ;
     RECT  91.361 54.576 91.577 54.6 ;
     RECT  90.677 13.056 91.613 13.08 ;
     RECT  91.253 58.704 91.613 58.728 ;
     RECT  91.532 74.64 91.619 76.44 ;
     RECT  91.619 75.744 91.621 76.44 ;
     RECT  91.181 77.52 91.621 81.096 ;
     RECT  91.621 75.744 91.667 81.096 ;
     RECT  91.619 74.64 91.676 74.664 ;
     RECT  91.541 34.752 91.757 37.032 ;
     RECT  91.433 89.568 91.763 91.32 ;
     RECT  91.397 21.648 91.793 21.672 ;
     RECT  91.325 22.704 91.793 23.592 ;
     RECT  90.677 38.688 91.793 38.808 ;
     RECT  90.749 64.368 91.793 64.392 ;
     RECT  91.667 75.792 91.793 81.096 ;
     RECT  91.433 84.768 91.793 88.392 ;
     RECT  91.361 47.76 91.829 48.408 ;
     RECT  91.433 24.624 91.865 28.44 ;
     RECT  91.757 34.752 91.865 34.92 ;
     RECT  91.757 36.144 91.865 37.032 ;
     RECT  89.843 69.456 91.865 70.296 ;
     RECT  91.676 74.592 91.865 74.664 ;
     RECT  89.813 7.872 92.257 7.896 ;
     RECT  91.793 22.704 92.293 23.304 ;
     RECT  91.825 11.952 92.329 11.976 ;
     RECT  92.185 19.296 92.329 19.32 ;
     RECT  91.289 30 92.329 30.648 ;
     RECT  91.541 31.728 92.329 33.72 ;
     RECT  90.713 39.84 92.329 39.864 ;
     RECT  91.361 46.512 92.329 46.68 ;
     RECT  91.717 62.688 92.329 62.712 ;
     RECT  91.325 67.2 92.329 68.424 ;
     RECT  92.041 69.408 92.329 69.432 ;
     RECT  92.329 19.296 92.365 20.184 ;
     RECT  91.139 83.184 92.509 83.304 ;
     RECT  91.865 74.592 92.833 74.616 ;
     RECT  92.329 11.952 92.869 12.264 ;
     RECT  91.829 48.384 92.869 48.408 ;
     RECT  92.329 57.168 92.869 57.192 ;
     RECT  92.833 74.592 92.869 74.76 ;
     RECT  91.793 75.888 92.869 81.096 ;
     RECT  91.793 85.68 92.869 88.392 ;
     RECT  91.763 89.568 92.869 90.456 ;
     RECT  92.329 4.608 92.905 4.92 ;
     RECT  91.469 6.48 92.905 6.792 ;
     RECT  92.257 7.872 92.905 7.944 ;
     RECT  92.329 9.936 92.905 10.392 ;
     RECT  92.869 11.376 92.905 12.264 ;
     RECT  90.821 15.456 92.905 15.48 ;
     RECT  92.329 17.856 92.905 17.88 ;
     RECT  92.365 19.296 92.905 20.328 ;
     RECT  92.293 22.032 92.905 23.304 ;
     RECT  91.865 24.624 92.905 27.816 ;
     RECT  92.329 30 92.905 33.72 ;
     RECT  91.865 34.752 92.905 34.776 ;
     RECT  91.865 37.008 92.905 37.032 ;
     RECT  92.329 38.016 92.905 38.04 ;
     RECT  92.329 39.024 92.905 39.912 ;
     RECT  92.329 42.912 92.905 42.936 ;
     RECT  92.329 44.352 92.905 44.808 ;
     RECT  92.329 46.224 92.905 46.68 ;
     RECT  92.869 48.384 92.905 48.84 ;
     RECT  92.329 51.552 92.905 53.16 ;
     RECT  92.329 55.152 92.905 55.176 ;
     RECT  92.869 57.024 92.905 57.192 ;
     RECT  92.329 58.32 92.905 58.344 ;
     RECT  92.329 60.048 92.905 60.072 ;
     RECT  92.329 62.352 92.905 63.384 ;
     RECT  92.329 65.376 92.905 65.4 ;
     RECT  92.329 66.816 92.905 69.432 ;
     RECT  92.437 73.008 92.905 73.032 ;
     RECT  92.869 74.592 92.905 81.096 ;
     RECT  91.289 82.08 92.905 82.104 ;
     RECT  92.509 83.184 92.905 83.832 ;
     RECT  92.869 85.68 92.905 90.456 ;
     RECT  92.905 9.936 92.941 16.296 ;
     RECT  92.905 17.28 92.941 23.64 ;
     RECT  92.905 24.624 92.941 40.632 ;
     RECT  92.905 41.616 92.941 41.928 ;
     RECT  92.905 42.912 92.941 70.008 ;
     RECT  92.905 4.32 93.481 7.944 ;
     RECT  92.905 8.928 93.481 8.952 ;
     RECT  92.941 9.936 93.481 23.64 ;
     RECT  92.941 24.624 93.481 70.008 ;
     RECT  92.905 71.28 93.481 90.456 ;
     RECT  93.481 4.32 94.86 90.6 ;
    LAYER M5 ;
     RECT  2.4 2.137 2.52 2.151 ;
     RECT  7.8 2.137 7.92 2.151 ;
     RECT  13.2 2.137 13.32 2.151 ;
     RECT  18.6 2.137 18.72 2.151 ;
     RECT  24 2.137 24.12 2.151 ;
     RECT  29.4 2.137 29.52 2.151 ;
     RECT  34.8 2.137 34.92 2.151 ;
     RECT  40.2 2.137 40.32 2.151 ;
     RECT  45.6 2.137 45.72 2.151 ;
     RECT  51 2.137 51.12 2.151 ;
     RECT  56.4 2.137 56.52 2.151 ;
     RECT  61.8 2.137 61.92 2.151 ;
     RECT  67.2 2.137 67.32 2.151 ;
     RECT  72.6 2.137 72.72 2.151 ;
     RECT  78 2.137 78.12 2.151 ;
     RECT  83.4 2.137 83.52 2.151 ;
     RECT  88.8 2.137 88.92 2.151 ;
     RECT  7.8 2.151 8.112 3.061 ;
     RECT  29.4 2.151 29.712 3.541 ;
     RECT  0.192 4.933 0.216 5.507 ;
     RECT  88.8 2.151 89.112 5.989 ;
     RECT  7.8 3.061 8.52 6.229 ;
     RECT  75.792 3.925 75.816 6.419 ;
     RECT  88.8 5.989 89.784 7.379 ;
     RECT  7.8 6.229 8.568 7.717 ;
     RECT  7.68 7.717 8.568 7.763 ;
     RECT  29.4 3.541 29.928 7.957 ;
     RECT  2.4 2.151 2.712 8.293 ;
     RECT  2.4 8.293 2.808 8.531 ;
     RECT  5.76 9.349 5.784 10.067 ;
     RECT  2.4 8.531 2.712 10.117 ;
     RECT  2.208 10.117 2.712 10.259 ;
     RECT  4.608 10.453 4.632 10.883 ;
     RECT  0.48 11.365 0.504 11.461 ;
     RECT  0.384 11.461 0.504 11.699 ;
     RECT  88.8 7.379 89.64 11.941 ;
     RECT  88.8 11.941 90.552 12.325 ;
     RECT  88.176 12.325 90.552 12.517 ;
     RECT  87.744 12.517 90.552 13.091 ;
     RECT  88.8 13.091 90.552 13.139 ;
     RECT  87.744 13.091 87.816 13.859 ;
     RECT  7.68 7.763 8.112 14.197 ;
     RECT  6.24 13.813 6.264 14.291 ;
     RECT  87.744 13.859 87.768 14.821 ;
     RECT  87.456 14.821 87.768 15.493 ;
     RECT  87.456 15.493 87.816 15.539 ;
     RECT  7.68 14.197 8.376 16.259 ;
     RECT  88.8 13.139 89.832 16.405 ;
     RECT  7.68 16.259 8.112 16.645 ;
     RECT  88.8 16.405 90.504 16.787 ;
     RECT  90.384 16.787 90.504 16.835 ;
     RECT  5.136 15.589 5.16 17.123 ;
     RECT  6.384 16.405 6.408 17.123 ;
     RECT  87.792 15.539 87.816 17.605 ;
     RECT  88.8 16.787 89.112 17.605 ;
     RECT  87.792 17.605 89.112 17.699 ;
     RECT  87.984 17.699 89.112 18.227 ;
     RECT  6.048 18.181 6.072 18.757 ;
     RECT  7.632 16.645 8.112 18.757 ;
     RECT  6.048 18.757 8.112 20.003 ;
     RECT  0.192 19.861 0.216 20.147 ;
     RECT  7.8 20.003 8.112 20.437 ;
     RECT  88.8 18.227 89.112 21.013 ;
     RECT  90.384 16.835 90.408 21.013 ;
     RECT  0.288 21.013 0.312 21.155 ;
     RECT  88.8 21.013 90.408 21.683 ;
     RECT  6.048 20.003 6.072 22.739 ;
     RECT  7.8 20.437 8.232 23.317 ;
     RECT  88.8 21.683 89.112 23.317 ;
     RECT  90.384 21.683 90.408 23.317 ;
     RECT  4.368 22.069 4.392 24.131 ;
     RECT  6.912 23.317 8.232 24.131 ;
     RECT  87.264 23.845 87.288 24.613 ;
     RECT  87.168 24.613 87.288 24.659 ;
     RECT  87.168 24.659 87.192 24.661 ;
     RECT  29.4 7.957 30.024 25.715 ;
     RECT  86.4 24.661 87.192 25.859 ;
     RECT  88.8 23.317 90.408 26.245 ;
     RECT  5.472 25.573 5.496 26.291 ;
     RECT  88.8 26.245 90.6 26.725 ;
     RECT  7.8 24.131 8.232 26.867 ;
     RECT  0.192 26.341 0.216 27.395 ;
     RECT  88.608 26.725 90.6 27.395 ;
     RECT  88.8 27.395 90.6 27.443 ;
     RECT  2.4 10.259 2.712 27.829 ;
     RECT  74.64 27.493 74.664 27.877 ;
     RECT  88.8 27.443 89.784 27.923 ;
     RECT  0.288 27.877 0.312 28.403 ;
     RECT  87.168 25.859 87.192 28.403 ;
     RECT  74.112 27.877 74.664 28.547 ;
     RECT  29.4 25.715 29.832 28.691 ;
     RECT  51 2.151 51.312 28.693 ;
     RECT  49.872 27.301 49.896 28.739 ;
     RECT  51 28.693 51.864 29.027 ;
     RECT  2.304 27.829 2.712 29.269 ;
     RECT  7.8 26.867 8.112 29.605 ;
     RECT  2.304 29.269 2.856 29.795 ;
     RECT  0.288 30.037 0.312 30.275 ;
     RECT  2.4 29.795 2.856 30.275 ;
     RECT  88.8 27.923 89.112 30.565 ;
     RECT  74.64 28.547 74.664 30.611 ;
     RECT  7.8 29.605 8.232 30.851 ;
     RECT  87.744 29.365 87.768 30.851 ;
     RECT  0.192 30.661 0.216 30.899 ;
     RECT  2.4 30.275 2.712 31.717 ;
     RECT  2.304 31.717 2.712 31.859 ;
     RECT  88.8 30.565 89.496 31.861 ;
     RECT  6.576 26.485 6.6 32.197 ;
     RECT  7.8 30.851 8.112 32.197 ;
     RECT  6.576 32.197 8.112 32.531 ;
     RECT  88.8 31.861 90.072 32.531 ;
     RECT  91.152 32.437 91.176 33.155 ;
     RECT  85.92 31.861 85.944 33.251 ;
     RECT  0.288 33.109 0.312 33.541 ;
     RECT  87.504 33.541 87.528 33.589 ;
     RECT  0.288 33.541 0.36 33.779 ;
     RECT  86.592 33.589 87.528 34.115 ;
     RECT  6.576 32.531 6.6 34.549 ;
     RECT  6.48 34.549 6.6 34.645 ;
     RECT  7.8 32.531 8.112 34.645 ;
     RECT  6.48 34.645 8.112 34.741 ;
     RECT  88.8 32.531 89.496 34.885 ;
     RECT  90.72 34.741 90.744 34.885 ;
     RECT  6.48 34.741 8.232 35.363 ;
     RECT  7.8 35.363 8.232 35.459 ;
     RECT  87.456 34.115 87.528 35.507 ;
     RECT  0.192 33.829 0.216 35.555 ;
     RECT  2.4 31.859 2.712 35.749 ;
     RECT  88.8 34.885 90.744 35.845 ;
     RECT  2.16 35.749 2.712 35.891 ;
     RECT  88.176 35.845 90.744 36.083 ;
     RECT  51 29.027 51.48 36.515 ;
     RECT  6.48 35.363 6.504 36.757 ;
     RECT  6.48 36.757 6.792 36.803 ;
     RECT  88.176 36.083 90.312 36.803 ;
     RECT  7.8 35.459 8.112 36.805 ;
     RECT  0.192 36.901 0.216 37.187 ;
     RECT  88.176 36.803 90.072 38.149 ;
     RECT  87.984 38.149 90.072 38.291 ;
     RECT  6.768 36.803 6.792 38.819 ;
     RECT  87.984 38.291 89.88 39.299 ;
     RECT  88.8 39.299 89.88 39.829 ;
     RECT  0.288 39.301 0.312 39.877 ;
     RECT  7.8 36.805 8.232 40.019 ;
     RECT  88.8 39.829 90.6 40.499 ;
     RECT  90.576 40.499 90.6 40.547 ;
     RECT  4.848 37.573 4.872 41.075 ;
     RECT  0.288 39.877 0.36 41.171 ;
     RECT  6.72 39.109 6.744 41.651 ;
     RECT  7.8 40.019 8.112 41.653 ;
     RECT  0.336 41.171 0.36 41.747 ;
     RECT  7.8 41.653 8.28 42.467 ;
     RECT  88.8 40.499 89.496 43.813 ;
     RECT  7.8 42.467 8.112 44.389 ;
     RECT  88.8 43.813 89.544 44.483 ;
     RECT  7.104 44.389 8.112 45.011 ;
     RECT  88.8 44.483 89.208 45.541 ;
     RECT  2.4 35.891 2.712 45.637 ;
     RECT  7.44 45.011 8.112 45.731 ;
     RECT  2.016 45.637 2.712 46.067 ;
     RECT  88.8 45.541 89.544 46.211 ;
     RECT  7.584 45.731 8.112 46.787 ;
     RECT  2.304 46.067 2.712 46.979 ;
     RECT  87.504 45.541 87.528 47.507 ;
     RECT  6.576 47.605 6.6 48.421 ;
     RECT  7.68 46.787 8.112 48.421 ;
     RECT  5.088 47.845 5.112 48.515 ;
     RECT  88.8 46.211 89.208 49.043 ;
     RECT  6.576 48.421 8.232 49.379 ;
     RECT  90.192 49.525 90.216 50.291 ;
     RECT  87.792 50.053 87.816 50.579 ;
     RECT  5.136 49.333 5.16 51.347 ;
     RECT  88.8 49.043 89.112 52.405 ;
     RECT  7.68 49.379 8.232 52.499 ;
     RECT  85.92 47.461 85.944 52.499 ;
     RECT  4.512 53.077 4.536 53.363 ;
     RECT  86.016 53.557 86.04 54.899 ;
     RECT  7.68 52.499 8.112 55.237 ;
     RECT  7.632 55.237 8.112 55.859 ;
     RECT  87.408 55.237 87.432 56.101 ;
     RECT  88.8 52.405 89.832 56.389 ;
     RECT  5.136 55.813 5.16 56.723 ;
     RECT  48.576 36.949 48.6 57.155 ;
     RECT  6.576 49.379 6.6 57.205 ;
     RECT  7.68 55.859 8.112 57.251 ;
     RECT  45.6 2.151 45.912 57.589 ;
     RECT  87.408 56.101 87.576 57.635 ;
     RECT  88.8 56.389 90.168 58.357 ;
     RECT  2.4 46.979 2.712 59.221 ;
     RECT  87.408 57.635 87.432 59.221 ;
     RECT  87.216 59.221 87.432 59.267 ;
     RECT  0.336 59.125 0.36 59.461 ;
     RECT  87.216 59.267 87.24 59.555 ;
     RECT  2.4 59.221 2.808 59.699 ;
     RECT  0.288 59.461 0.36 59.797 ;
     RECT  0.288 59.797 0.408 59.891 ;
     RECT  88.8 58.357 90.264 59.891 ;
     RECT  0.384 59.891 0.408 60.227 ;
     RECT  6.192 57.205 6.6 60.709 ;
     RECT  7.8 57.251 8.112 60.709 ;
     RECT  2.4 59.699 2.712 60.757 ;
     RECT  2.4 60.757 2.808 60.899 ;
     RECT  3.936 60.373 3.96 60.901 ;
     RECT  6.192 60.709 8.112 61.573 ;
     RECT  3.936 60.901 4.776 61.619 ;
     RECT  0.192 61.477 0.216 61.667 ;
     RECT  87.408 60.661 87.432 62.195 ;
     RECT  88.8 59.891 89.544 62.341 ;
     RECT  5.904 61.573 8.112 62.771 ;
     RECT  2.4 60.899 2.712 63.205 ;
     RECT  0.288 63.061 0.312 63.637 ;
     RECT  2.4 63.205 2.808 63.781 ;
     RECT  7.8 62.771 8.112 64.165 ;
     RECT  2.4 63.781 2.856 64.213 ;
     RECT  4.752 61.619 4.776 64.355 ;
     RECT  0.288 63.637 0.36 64.357 ;
     RECT  2.304 64.213 2.856 64.403 ;
     RECT  0.288 64.357 0.408 64.739 ;
     RECT  2.4 64.403 2.856 64.837 ;
     RECT  87.216 64.357 87.24 65.027 ;
     RECT  2.4 64.837 3.192 65.173 ;
     RECT  45.6 57.589 46.056 65.267 ;
     RECT  7.8 64.165 8.328 65.269 ;
     RECT  5.904 62.771 6.6 65.509 ;
     RECT  0.288 64.739 0.312 66.085 ;
     RECT  0.192 66.085 0.312 66.229 ;
     RECT  5.136 65.509 6.6 66.229 ;
     RECT  7.8 65.269 8.472 66.229 ;
     RECT  0.192 66.229 0.36 66.371 ;
     RECT  0.288 66.371 0.36 66.661 ;
     RECT  5.136 66.229 8.472 66.707 ;
     RECT  2.4 65.173 3.432 66.755 ;
     RECT  0.288 66.661 0.456 66.899 ;
     RECT  22.752 65.365 22.776 67.523 ;
     RECT  5.904 66.707 8.472 67.525 ;
     RECT  5.904 67.525 8.856 67.811 ;
     RECT  0.288 66.899 0.312 67.907 ;
     RECT  2.4 66.755 3.384 68.101 ;
     RECT  86.784 66.085 86.808 68.293 ;
     RECT  6.576 67.811 8.856 68.339 ;
     RECT  65.28 65.365 65.304 68.339 ;
     RECT  0.432 68.101 0.456 68.579 ;
     RECT  88.8 62.341 89.832 68.915 ;
     RECT  86.784 68.293 87.24 69.253 ;
     RECT  2.4 68.101 3.432 69.301 ;
     RECT  86.784 69.253 87.288 69.779 ;
     RECT  2.4 69.301 3.96 70.163 ;
     RECT  3.936 70.163 3.96 70.453 ;
     RECT  3.936 70.453 4.392 70.739 ;
     RECT  86.784 69.779 86.808 70.787 ;
     RECT  88.8 68.915 89.112 70.789 ;
     RECT  6.576 68.339 6.6 71.605 ;
     RECT  7.8 68.339 8.856 71.605 ;
     RECT  6.576 71.605 8.856 71.651 ;
     RECT  86.016 70.933 86.04 71.843 ;
     RECT  6.576 71.651 8.232 72.179 ;
     RECT  0.288 69.397 0.312 72.563 ;
     RECT  88.704 70.789 89.112 73.285 ;
     RECT  88.08 73.285 89.112 73.811 ;
     RECT  4.368 70.739 4.392 74.339 ;
     RECT  88.32 73.811 89.112 74.629 ;
     RECT  91.728 74.581 91.752 75.205 ;
     RECT  91.584 75.205 91.752 75.637 ;
     RECT  88.32 74.629 89.496 75.685 ;
     RECT  90.768 75.637 91.752 75.685 ;
     RECT  88.32 75.685 91.752 75.827 ;
     RECT  88.56 75.827 91.752 76.403 ;
     RECT  88.56 76.403 91.656 76.451 ;
     RECT  91.632 76.451 91.656 76.979 ;
     RECT  88.56 76.451 90.6 77.027 ;
     RECT  88.56 77.027 90.552 77.075 ;
     RECT  6.576 72.179 8.112 77.365 ;
     RECT  4.512 76.117 4.536 77.555 ;
     RECT  88.704 77.075 90.552 77.987 ;
     RECT  49.344 77.989 49.368 78.037 ;
     RECT  51 36.515 51.312 78.037 ;
     RECT  6.576 77.365 8.232 78.131 ;
     RECT  49.008 78.037 51.312 78.467 ;
     RECT  50.112 78.467 51.312 78.515 ;
     RECT  88.704 77.987 89.928 78.613 ;
     RECT  88.656 78.613 89.928 78.659 ;
     RECT  5.328 78.085 5.352 78.899 ;
     RECT  2.4 70.163 2.712 78.949 ;
     RECT  2.256 78.949 2.712 79.091 ;
     RECT  91.008 78.613 91.032 79.189 ;
     RECT  49.008 78.467 49.032 79.475 ;
     RECT  90.384 79.189 91.032 79.859 ;
     RECT  90.384 79.859 90.408 80.003 ;
     RECT  88.656 78.659 89.112 80.101 ;
     RECT  88.32 80.101 89.112 80.963 ;
     RECT  88.656 80.963 89.112 80.965 ;
     RECT  90.288 80.101 90.312 80.965 ;
     RECT  48.912 80.869 48.936 81.445 ;
     RECT  88.656 80.965 90.312 81.445 ;
     RECT  87.072 78.085 87.096 81.539 ;
     RECT  48.816 81.445 48.936 81.683 ;
     RECT  88.656 81.445 91.128 82.115 ;
     RECT  0.288 81.349 0.312 82.357 ;
     RECT  2.4 79.091 2.712 82.597 ;
     RECT  0.288 82.357 0.408 82.739 ;
     RECT  0.288 82.739 0.312 82.787 ;
     RECT  88.656 82.115 89.112 82.933 ;
     RECT  48.816 81.683 48.84 83.075 ;
     RECT  2.4 82.597 2.808 83.267 ;
     RECT  90.288 82.115 91.128 83.315 ;
     RECT  88.416 82.933 89.112 83.653 ;
     RECT  90.288 83.315 90.6 83.653 ;
     RECT  88.416 83.653 90.6 84.419 ;
     RECT  4.656 81.445 4.68 84.611 ;
     RECT  88.8 84.419 90.6 84.757 ;
     RECT  86.88 83.605 86.904 84.995 ;
     RECT  2.4 83.267 2.712 85.621 ;
     RECT  2.4 85.621 2.808 85.765 ;
     RECT  2.304 85.765 2.808 86.651 ;
     RECT  3.792 86.581 3.816 86.651 ;
     RECT  2.304 86.651 3.816 86.723 ;
     RECT  2.304 86.723 2.856 86.819 ;
     RECT  0.288 86.821 0.312 87.253 ;
     RECT  88.8 84.757 91.176 87.299 ;
     RECT  47.52 86.341 47.544 87.443 ;
     RECT  88.8 87.299 90.84 87.827 ;
     RECT  49.344 87.109 49.368 87.875 ;
     RECT  0.192 87.253 0.312 87.973 ;
     RECT  2.304 86.819 2.808 88.403 ;
     RECT  92.304 87.541 92.328 88.403 ;
     RECT  0.192 87.973 0.36 88.451 ;
     RECT  2.4 88.403 2.808 88.597 ;
     RECT  18.6 2.151 18.912 88.645 ;
     RECT  20.64 87.685 20.664 88.645 ;
     RECT  9.888 88.309 9.912 88.691 ;
     RECT  19.968 88.645 20.664 88.789 ;
     RECT  19.968 88.789 21.336 88.883 ;
     RECT  88.8 87.827 90.072 88.885 ;
     RECT  91.152 88.309 91.176 88.885 ;
     RECT  15.36 88.309 15.384 88.931 ;
     RECT  19.968 88.883 19.992 88.931 ;
     RECT  3.936 88.261 3.96 88.979 ;
     RECT  17.904 88.645 18.912 88.979 ;
     RECT  13.2 2.151 13.512 89.125 ;
     RECT  13.104 89.125 13.512 89.221 ;
     RECT  13.104 89.221 14.28 89.267 ;
     RECT  18.6 88.979 18.912 89.269 ;
     RECT  6.576 78.131 8.112 89.555 ;
     RECT  88.8 88.885 91.176 89.557 ;
     RECT  88.8 89.557 91.656 89.603 ;
     RECT  0.192 88.451 0.264 89.845 ;
     RECT  13.2 89.267 14.28 90.037 ;
     RECT  15.312 89.989 15.336 90.037 ;
     RECT  91.104 89.603 91.656 90.083 ;
     RECT  0.192 89.845 0.36 90.133 ;
     RECT  13.2 90.037 15.336 90.275 ;
     RECT  18.6 89.269 19.128 90.277 ;
     RECT  91.152 90.083 91.656 90.421 ;
     RECT  14.688 90.275 15.336 90.659 ;
     RECT  21.312 88.883 21.336 90.659 ;
     RECT  87.216 90.037 87.24 90.659 ;
     RECT  24 2.151 24.312 90.757 ;
     RECT  0.192 90.133 0.408 90.851 ;
     RECT  23.904 90.757 24.312 90.899 ;
     RECT  11.808 88.885 11.832 90.901 ;
     RECT  11.808 90.901 11.976 90.947 ;
     RECT  40.2 2.151 40.512 90.949 ;
     RECT  17.808 90.277 19.128 91.091 ;
     RECT  14.832 90.659 15.336 91.235 ;
     RECT  88.8 89.603 89.88 91.235 ;
     RECT  2.4 88.597 2.856 91.283 ;
     RECT  14.832 91.235 14.856 91.283 ;
     RECT  91.152 90.421 91.752 91.283 ;
     RECT  71.28 68.341 71.304 91.331 ;
     RECT  91.728 91.283 91.752 91.331 ;
     RECT  0.24 90.851 0.408 91.379 ;
     RECT  17.808 91.091 18.912 91.379 ;
     RECT  53.136 90.949 53.16 91.619 ;
     RECT  10.272 90.901 10.296 91.811 ;
     RECT  11.952 90.947 11.976 91.811 ;
     RECT  25.296 90.853 25.32 91.859 ;
     RECT  40.2 90.949 41.16 91.859 ;
     RECT  0.288 91.379 0.408 91.907 ;
     RECT  0.288 91.907 0.312 92.435 ;
     RECT  13.2 90.275 13.512 92.821 ;
     RECT  34.8 2.151 35.112 92.821 ;
     RECT  56.4 2.151 56.712 92.821 ;
     RECT  61.8 2.151 62.112 92.821 ;
     RECT  78 2.151 78.312 92.821 ;
     RECT  2.4 91.283 2.712 92.889 ;
     RECT  7.8 89.555 8.112 92.889 ;
     RECT  18.6 91.379 18.912 92.889 ;
     RECT  24 90.899 24.312 92.889 ;
     RECT  29.4 28.691 29.712 92.889 ;
     RECT  34.032 92.821 35.112 92.889 ;
     RECT  40.2 91.859 40.512 92.889 ;
     RECT  45.6 65.267 45.912 92.889 ;
     RECT  51 78.515 51.312 92.889 ;
     RECT  61.44 92.821 62.112 92.889 ;
     RECT  67.2 2.151 67.512 92.889 ;
     RECT  72.6 2.151 72.912 92.889 ;
     RECT  77.232 92.821 78.312 92.889 ;
     RECT  83.4 2.151 83.712 92.889 ;
     RECT  88.8 91.235 89.112 92.889 ;
     RECT  2.4 92.889 2.52 92.903 ;
     RECT  7.8 92.889 7.92 92.903 ;
     RECT  13.2 92.821 14.184 92.903 ;
     RECT  18.6 92.889 18.72 92.903 ;
     RECT  24 92.889 24.12 92.903 ;
     RECT  29.4 92.889 29.52 92.903 ;
     RECT  34.032 92.889 34.92 92.903 ;
     RECT  40.2 92.889 40.32 92.903 ;
     RECT  45.6 92.889 45.72 92.903 ;
     RECT  51 92.889 51.12 92.903 ;
     RECT  56.4 92.821 57.384 92.903 ;
     RECT  61.44 92.889 61.92 92.903 ;
     RECT  67.2 92.889 67.32 92.903 ;
     RECT  72.6 92.889 72.72 92.903 ;
     RECT  77.232 92.889 78.12 92.903 ;
     RECT  83.4 92.889 83.52 92.903 ;
     RECT  88.8 92.889 88.92 92.903 ;
     RECT  87.816 13.091 88.8 13.859 ;
     RECT  6.264 13.813 7.68 14.291 ;
     RECT  87.768 13.859 88.8 15.493 ;
     RECT  87.816 15.493 88.8 17.605 ;
     RECT  5.16 16.405 6.384 17.123 ;
     RECT  6.408 16.405 7.68 16.645 ;
     RECT  6.408 16.645 7.632 17.123 ;
     RECT  89.112 16.787 90.384 21.013 ;
     RECT  6.048 17.123 6.072 18.181 ;
     RECT  89.112 21.683 90.384 23.317 ;
     RECT  87.288 23.845 88.8 24.659 ;
     RECT  6.6 26.485 7.8 32.197 ;
     RECT  87.192 26.725 88.608 27.395 ;
     RECT  49.896 27.301 51 28.739 ;
     RECT  72.912 27.877 74.112 28.547 ;
     RECT  87.768 29.365 88.8 30.851 ;
     RECT  90.072 32.437 91.152 32.531 ;
     RECT  6.6 32.531 7.8 34.645 ;
     RECT  87.528 33.541 88.8 35.507 ;
     RECT  89.496 34.741 90.72 34.885 ;
     RECT  6.504 35.363 7.8 36.757 ;
     RECT  8.112 35.459 8.232 36.805 ;
     RECT  88.176 35.507 88.8 35.845 ;
     RECT  0.192 35.555 0.216 35.664 ;
     RECT  0.192 35.784 0.216 35.808 ;
     RECT  0.192 35.928 0.216 35.952 ;
     RECT  0.192 36.072 0.216 36.096 ;
     RECT  0.192 36.216 0.216 36.24 ;
     RECT  0.192 36.36 0.216 36.384 ;
     RECT  0.192 36.504 0.216 36.528 ;
     RECT  0.192 36.648 0.216 36.672 ;
     RECT  6.792 36.757 7.8 38.819 ;
     RECT  0.192 36.792 0.216 36.901 ;
     RECT  6.768 38.819 7.8 39.109 ;
     RECT  6.744 39.109 7.8 41.651 ;
     RECT  89.496 40.499 90.576 40.547 ;
     RECT  89.208 44.483 89.544 45.541 ;
     RECT  87.528 45.541 88.8 47.507 ;
     RECT  7.584 46.787 7.68 47.605 ;
     RECT  6.6 47.605 7.68 48.421 ;
     RECT  5.112 47.845 6.576 48.515 ;
     RECT  5.136 48.515 6.576 49.333 ;
     RECT  89.112 49.043 89.208 49.525 ;
     RECT  5.16 49.333 6.576 51.347 ;
     RECT  6.6 49.379 7.68 55.237 ;
     RECT  89.112 49.525 90.192 50.291 ;
     RECT  87.816 50.053 88.8 50.579 ;
     RECT  6.6 55.237 7.632 55.859 ;
     RECT  87.432 55.237 88.8 56.101 ;
     RECT  5.16 55.813 6.576 56.723 ;
     RECT  6.6 55.859 7.68 57.251 ;
     RECT  87.576 56.101 88.8 57.635 ;
     RECT  6.192 56.723 6.576 57.205 ;
     RECT  6.6 57.251 7.8 60.709 ;
     RECT  87.432 57.635 88.8 59.267 ;
     RECT  87.24 59.267 88.8 59.555 ;
     RECT  87.408 59.555 88.8 60.661 ;
     RECT  2.712 59.699 2.808 60.373 ;
     RECT  2.712 60.373 3.936 60.757 ;
     RECT  87.432 60.661 88.8 62.195 ;
     RECT  2.808 60.757 3.936 60.899 ;
     RECT  2.712 60.899 3.936 61.619 ;
     RECT  4.776 60.901 6.192 61.573 ;
     RECT  4.776 61.573 5.904 64.355 ;
     RECT  6.6 62.771 7.8 66.229 ;
     RECT  5.136 64.355 5.904 65.509 ;
     RECT  0.312 64.739 0.36 66.229 ;
     RECT  22.776 65.365 24 67.523 ;
     RECT  3.384 66.755 3.432 68.101 ;
     RECT  0.312 66.899 0.456 67.907 ;
     RECT  0.288 67.907 0.456 68.101 ;
     RECT  0.288 68.101 0.432 68.579 ;
     RECT  6.6 68.339 7.8 71.605 ;
     RECT  71.304 68.341 72.6 91.331 ;
     RECT  0.288 68.579 0.312 69.397 ;
     RECT  87.288 69.253 88.8 69.779 ;
     RECT  88.704 69.779 88.8 70.789 ;
     RECT  2.712 70.163 3.936 70.739 ;
     RECT  89.496 75.637 90.768 75.685 ;
     RECT  90.6 76.451 91.632 76.979 ;
     RECT  89.928 77.987 90.552 78.613 ;
     RECT  5.352 78.085 6.576 78.899 ;
     RECT  49.032 78.467 50.112 78.515 ;
     RECT  89.928 78.613 91.008 78.659 ;
     RECT  89.112 78.659 91.008 79.189 ;
     RECT  89.112 79.189 90.384 80.003 ;
     RECT  89.112 80.003 90.408 80.101 ;
     RECT  87.096 80.101 88.32 80.963 ;
     RECT  89.112 80.101 90.288 80.965 ;
     RECT  90.312 80.101 90.408 81.445 ;
     RECT  89.112 82.115 90.288 83.653 ;
     RECT  90.6 83.315 91.128 84.757 ;
     RECT  86.904 83.605 88.416 84.419 ;
     RECT  2.808 86.581 3.792 86.651 ;
     RECT  2.808 86.819 2.856 88.261 ;
     RECT  90.84 87.299 91.176 87.541 ;
     RECT  90.84 87.541 92.304 87.827 ;
     RECT  90.072 87.827 92.304 88.309 ;
     RECT  2.808 88.261 3.936 88.597 ;
     RECT  90.072 88.309 91.152 88.885 ;
     RECT  91.176 88.309 92.304 88.403 ;
     RECT  91.176 88.403 91.656 89.557 ;
     RECT  0.264 88.451 0.36 89.845 ;
     RECT  2.856 88.597 3.936 88.979 ;
     RECT  18.912 88.645 19.968 88.931 ;
     RECT  19.992 88.883 21.312 88.931 ;
     RECT  11.832 88.885 13.2 89.125 ;
     RECT  18.912 88.931 19.128 89.269 ;
     RECT  17.904 88.979 18.6 90.277 ;
     RECT  11.832 89.125 13.104 89.267 ;
     RECT  11.832 89.267 13.2 90.901 ;
     RECT  89.88 89.603 91.104 90.083 ;
     RECT  14.28 89.989 15.312 90.037 ;
     RECT  89.88 90.083 91.152 91.235 ;
     RECT  13.512 90.275 14.688 90.659 ;
     RECT  13.512 90.659 14.832 91.283 ;
     RECT  24.312 90.853 25.296 91.859 ;
     RECT  10.296 90.901 11.808 90.947 ;
     RECT  11.976 90.901 13.2 91.811 ;
  END
END dsfd_vm_static_landing_lane3
END LIBRARY
